###############################################################
#  Generated by:      Cadence Innovus 21.19-s058_1
#  OS:                Linux x86_64(Host ID fastx3-08.ews.illinois.edu)
#  Generated on:      Wed Apr 22 14:25:34 2026
#  Design:            VX_socket_top
#  Command:           write_lef_abstract -stripePin -PGpinLayers {metal7 metal8} -specifyTopLayer 8 -extractBlockObs -cutObsMinSpacing /home/rid2/cs533.work/vortex/hw/pnr/cadence/export/single-core/VX_socket_top.lef
###############################################################

VERSION 5.8 ;

BUSBITCHARS "[]" ;
DIVIDERCHAR "/" ;

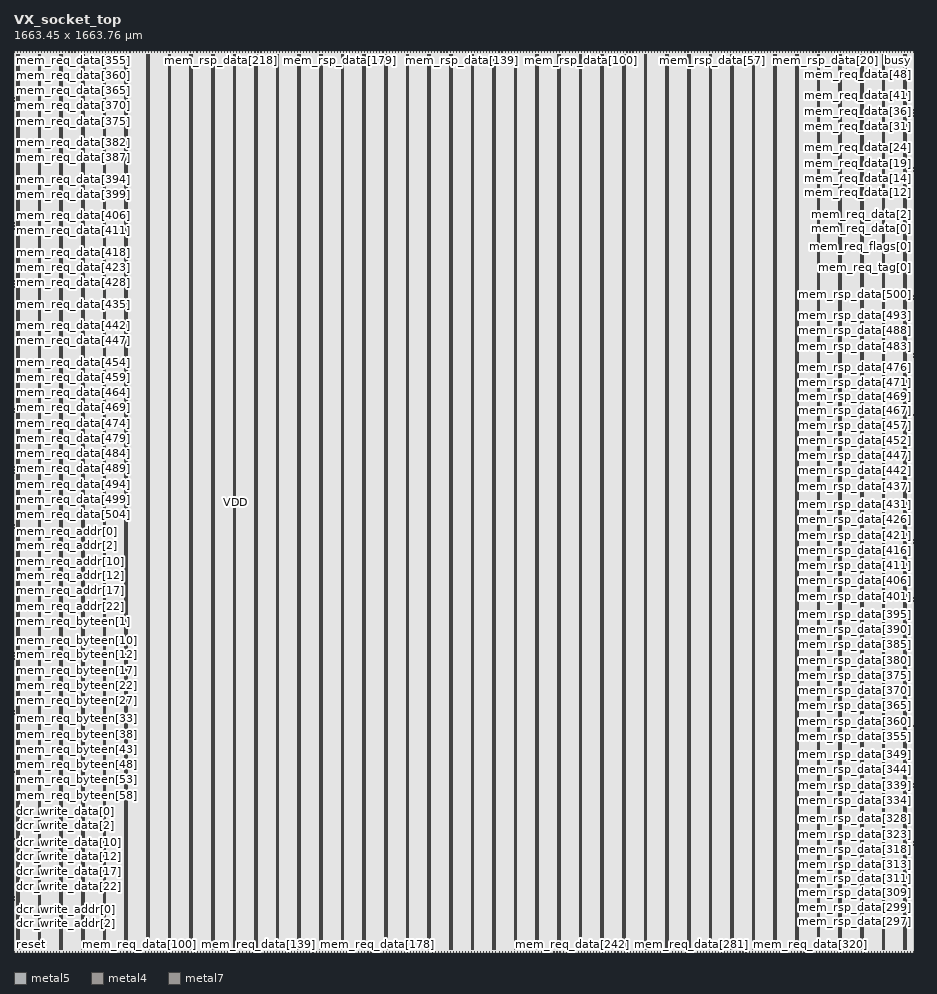
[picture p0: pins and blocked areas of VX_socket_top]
MACRO VX_socket_top
  CLASS BLOCK ;
  SIZE 1663.450000 BY 1663.760000 ;
  FOREIGN VX_socket_top 0.000000 0.000000 ;
  ORIGIN 0 0 ;
  SYMMETRY X Y R90 ;
  PIN clk
    DIRECTION INPUT ;
    USE SIGNAL ;
    PORT
      LAYER metal5 ;
        RECT 0.000000 0.280000 0.140000 0.420000 ;
    END
  END clk
  PIN reset
    DIRECTION INPUT ;
    USE SIGNAL ;
    PORT
      LAYER metal5 ;
        RECT 0.000000 5.880000 0.140000 6.020000 ;
    END
  END reset
  PIN dcr_write_valid
    DIRECTION INPUT ;
    USE SIGNAL ;
    PORT
      LAYER metal5 ;
        RECT 0.000000 11.480000 0.140000 11.620000 ;
    END
  END dcr_write_valid
  PIN dcr_write_addr[11]
    DIRECTION INPUT ;
    USE SIGNAL ;
    PORT
      LAYER metal5 ;
        RECT 0.000000 17.080000 0.140000 17.220000 ;
    END
  END dcr_write_addr[11]
  PIN dcr_write_addr[10]
    DIRECTION INPUT ;
    USE SIGNAL ;
    PORT
      LAYER metal5 ;
        RECT 0.000000 22.680000 0.140000 22.820000 ;
    END
  END dcr_write_addr[10]
  PIN dcr_write_addr[9]
    DIRECTION INPUT ;
    USE SIGNAL ;
    PORT
      LAYER metal5 ;
        RECT 0.000000 28.280000 0.140000 28.420000 ;
    END
  END dcr_write_addr[9]
  PIN dcr_write_addr[8]
    DIRECTION INPUT ;
    USE SIGNAL ;
    PORT
      LAYER metal5 ;
        RECT 0.000000 33.880000 0.140000 34.020000 ;
    END
  END dcr_write_addr[8]
  PIN dcr_write_addr[7]
    DIRECTION INPUT ;
    USE SIGNAL ;
    PORT
      LAYER metal5 ;
        RECT 0.000000 39.480000 0.140000 39.620000 ;
    END
  END dcr_write_addr[7]
  PIN dcr_write_addr[6]
    DIRECTION INPUT ;
    USE SIGNAL ;
    PORT
      LAYER metal5 ;
        RECT 0.000000 45.360000 0.140000 45.500000 ;
    END
  END dcr_write_addr[6]
  PIN dcr_write_addr[5]
    DIRECTION INPUT ;
    USE SIGNAL ;
    PORT
      LAYER metal5 ;
        RECT 0.000000 50.960000 0.140000 51.100000 ;
    END
  END dcr_write_addr[5]
  PIN dcr_write_addr[4]
    DIRECTION INPUT ;
    USE SIGNAL ;
    PORT
      LAYER metal5 ;
        RECT 0.000000 56.560000 0.140000 56.700000 ;
    END
  END dcr_write_addr[4]
  PIN dcr_write_addr[3]
    DIRECTION INPUT ;
    USE SIGNAL ;
    PORT
      LAYER metal5 ;
        RECT 0.000000 62.160000 0.140000 62.300000 ;
    END
  END dcr_write_addr[3]
  PIN dcr_write_addr[2]
    DIRECTION INPUT ;
    USE SIGNAL ;
    PORT
      LAYER metal5 ;
        RECT 0.000000 67.760000 0.140000 67.900000 ;
    END
  END dcr_write_addr[2]
  PIN dcr_write_addr[1]
    DIRECTION INPUT ;
    USE SIGNAL ;
    PORT
      LAYER metal5 ;
        RECT 0.000000 73.360000 0.140000 73.500000 ;
    END
  END dcr_write_addr[1]
  PIN dcr_write_addr[0]
    DIRECTION INPUT ;
    USE SIGNAL ;
    PORT
      LAYER metal5 ;
        RECT 0.000000 78.960000 0.140000 79.100000 ;
    END
  END dcr_write_addr[0]
  PIN dcr_write_data[31]
    DIRECTION INPUT ;
    USE SIGNAL ;
    PORT
      LAYER metal5 ;
        RECT 0.000000 84.840000 0.140000 84.980000 ;
    END
  END dcr_write_data[31]
  PIN dcr_write_data[30]
    DIRECTION INPUT ;
    USE SIGNAL ;
    PORT
      LAYER metal5 ;
        RECT 0.000000 90.440000 0.140000 90.580000 ;
    END
  END dcr_write_data[30]
  PIN dcr_write_data[29]
    DIRECTION INPUT ;
    USE SIGNAL ;
    PORT
      LAYER metal5 ;
        RECT 0.000000 96.040000 0.140000 96.180000 ;
    END
  END dcr_write_data[29]
  PIN dcr_write_data[28]
    DIRECTION INPUT ;
    USE SIGNAL ;
    PORT
      LAYER metal5 ;
        RECT 0.000000 101.640000 0.140000 101.780000 ;
    END
  END dcr_write_data[28]
  PIN dcr_write_data[27]
    DIRECTION INPUT ;
    USE SIGNAL ;
    PORT
      LAYER metal5 ;
        RECT 0.000000 107.240000 0.140000 107.380000 ;
    END
  END dcr_write_data[27]
  PIN dcr_write_data[26]
    DIRECTION INPUT ;
    USE SIGNAL ;
    PORT
      LAYER metal5 ;
        RECT 0.000000 112.840000 0.140000 112.980000 ;
    END
  END dcr_write_data[26]
  PIN dcr_write_data[25]
    DIRECTION INPUT ;
    USE SIGNAL ;
    PORT
      LAYER metal5 ;
        RECT 0.000000 118.440000 0.140000 118.580000 ;
    END
  END dcr_write_data[25]
  PIN dcr_write_data[24]
    DIRECTION INPUT ;
    USE SIGNAL ;
    PORT
      LAYER metal5 ;
        RECT 0.000000 124.040000 0.140000 124.180000 ;
    END
  END dcr_write_data[24]
  PIN dcr_write_data[23]
    DIRECTION INPUT ;
    USE SIGNAL ;
    PORT
      LAYER metal5 ;
        RECT 0.000000 129.920000 0.140000 130.060000 ;
    END
  END dcr_write_data[23]
  PIN dcr_write_data[22]
    DIRECTION INPUT ;
    USE SIGNAL ;
    PORT
      LAYER metal5 ;
        RECT 0.000000 135.520000 0.140000 135.660000 ;
    END
  END dcr_write_data[22]
  PIN dcr_write_data[21]
    DIRECTION INPUT ;
    USE SIGNAL ;
    PORT
      LAYER metal5 ;
        RECT 0.000000 141.120000 0.140000 141.260000 ;
    END
  END dcr_write_data[21]
  PIN dcr_write_data[20]
    DIRECTION INPUT ;
    USE SIGNAL ;
    PORT
      LAYER metal5 ;
        RECT 0.000000 146.720000 0.140000 146.860000 ;
    END
  END dcr_write_data[20]
  PIN dcr_write_data[19]
    DIRECTION INPUT ;
    USE SIGNAL ;
    PORT
      LAYER metal5 ;
        RECT 0.000000 152.320000 0.140000 152.460000 ;
    END
  END dcr_write_data[19]
  PIN dcr_write_data[18]
    DIRECTION INPUT ;
    USE SIGNAL ;
    PORT
      LAYER metal5 ;
        RECT 0.000000 157.920000 0.140000 158.060000 ;
    END
  END dcr_write_data[18]
  PIN dcr_write_data[17]
    DIRECTION INPUT ;
    USE SIGNAL ;
    PORT
      LAYER metal5 ;
        RECT 0.000000 163.520000 0.140000 163.660000 ;
    END
  END dcr_write_data[17]
  PIN dcr_write_data[16]
    DIRECTION INPUT ;
    USE SIGNAL ;
    PORT
      LAYER metal5 ;
        RECT 0.000000 169.400000 0.140000 169.540000 ;
    END
  END dcr_write_data[16]
  PIN dcr_write_data[15]
    DIRECTION INPUT ;
    USE SIGNAL ;
    PORT
      LAYER metal5 ;
        RECT 0.000000 175.000000 0.140000 175.140000 ;
    END
  END dcr_write_data[15]
  PIN dcr_write_data[14]
    DIRECTION INPUT ;
    USE SIGNAL ;
    PORT
      LAYER metal5 ;
        RECT 0.000000 180.600000 0.140000 180.740000 ;
    END
  END dcr_write_data[14]
  PIN dcr_write_data[13]
    DIRECTION INPUT ;
    USE SIGNAL ;
    PORT
      LAYER metal5 ;
        RECT 0.000000 186.200000 0.140000 186.340000 ;
    END
  END dcr_write_data[13]
  PIN dcr_write_data[12]
    DIRECTION INPUT ;
    USE SIGNAL ;
    PORT
      LAYER metal5 ;
        RECT 0.000000 191.800000 0.140000 191.940000 ;
    END
  END dcr_write_data[12]
  PIN dcr_write_data[11]
    DIRECTION INPUT ;
    USE SIGNAL ;
    PORT
      LAYER metal5 ;
        RECT 0.000000 197.400000 0.140000 197.540000 ;
    END
  END dcr_write_data[11]
  PIN dcr_write_data[10]
    DIRECTION INPUT ;
    USE SIGNAL ;
    PORT
      LAYER metal5 ;
        RECT 0.000000 203.000000 0.140000 203.140000 ;
    END
  END dcr_write_data[10]
  PIN dcr_write_data[9]
    DIRECTION INPUT ;
    USE SIGNAL ;
    PORT
      LAYER metal5 ;
        RECT 0.000000 208.880000 0.140000 209.020000 ;
    END
  END dcr_write_data[9]
  PIN dcr_write_data[8]
    DIRECTION INPUT ;
    USE SIGNAL ;
    PORT
      LAYER metal5 ;
        RECT 0.000000 214.480000 0.140000 214.620000 ;
    END
  END dcr_write_data[8]
  PIN dcr_write_data[7]
    DIRECTION INPUT ;
    USE SIGNAL ;
    PORT
      LAYER metal5 ;
        RECT 0.000000 220.080000 0.140000 220.220000 ;
    END
  END dcr_write_data[7]
  PIN dcr_write_data[6]
    DIRECTION INPUT ;
    USE SIGNAL ;
    PORT
      LAYER metal5 ;
        RECT 0.000000 225.680000 0.140000 225.820000 ;
    END
  END dcr_write_data[6]
  PIN dcr_write_data[5]
    DIRECTION INPUT ;
    USE SIGNAL ;
    PORT
      LAYER metal5 ;
        RECT 0.000000 231.280000 0.140000 231.420000 ;
    END
  END dcr_write_data[5]
  PIN dcr_write_data[4]
    DIRECTION INPUT ;
    USE SIGNAL ;
    PORT
      LAYER metal5 ;
        RECT 0.000000 236.880000 0.140000 237.020000 ;
    END
  END dcr_write_data[4]
  PIN dcr_write_data[3]
    DIRECTION INPUT ;
    USE SIGNAL ;
    PORT
      LAYER metal5 ;
        RECT 0.000000 242.480000 0.140000 242.620000 ;
    END
  END dcr_write_data[3]
  PIN dcr_write_data[2]
    DIRECTION INPUT ;
    USE SIGNAL ;
    PORT
      LAYER metal5 ;
        RECT 0.000000 248.080000 0.140000 248.220000 ;
    END
  END dcr_write_data[2]
  PIN dcr_write_data[1]
    DIRECTION INPUT ;
    USE SIGNAL ;
    PORT
      LAYER metal5 ;
        RECT 0.000000 253.960000 0.140000 254.100000 ;
    END
  END dcr_write_data[1]
  PIN dcr_write_data[0]
    DIRECTION INPUT ;
    USE SIGNAL ;
    PORT
      LAYER metal5 ;
        RECT 0.000000 259.560000 0.140000 259.700000 ;
    END
  END dcr_write_data[0]
  PIN mem_req_valid[0]
    DIRECTION OUTPUT ;
    USE SIGNAL ;
    PORT
      LAYER metal5 ;
        RECT 0.000000 265.160000 0.140000 265.300000 ;
    END
  END mem_req_valid[0]
  PIN mem_req_rw[0]
    DIRECTION OUTPUT ;
    USE SIGNAL ;
    PORT
      LAYER metal5 ;
        RECT 0.000000 270.760000 0.140000 270.900000 ;
    END
  END mem_req_rw[0]
  PIN mem_req_byteen[63]
    DIRECTION OUTPUT ;
    USE SIGNAL ;
    PORT
      LAYER metal5 ;
        RECT 0.000000 276.360000 0.140000 276.500000 ;
    END
  END mem_req_byteen[63]
  PIN mem_req_byteen[62]
    DIRECTION OUTPUT ;
    USE SIGNAL ;
    PORT
      LAYER metal5 ;
        RECT 0.000000 281.960000 0.140000 282.100000 ;
    END
  END mem_req_byteen[62]
  PIN mem_req_byteen[61]
    DIRECTION OUTPUT ;
    USE SIGNAL ;
    PORT
      LAYER metal5 ;
        RECT 0.000000 287.560000 0.140000 287.700000 ;
    END
  END mem_req_byteen[61]
  PIN mem_req_byteen[60]
    DIRECTION OUTPUT ;
    USE SIGNAL ;
    PORT
      LAYER metal5 ;
        RECT 0.000000 293.440000 0.140000 293.580000 ;
    END
  END mem_req_byteen[60]
  PIN mem_req_byteen[59]
    DIRECTION OUTPUT ;
    USE SIGNAL ;
    PORT
      LAYER metal5 ;
        RECT 0.000000 299.040000 0.140000 299.180000 ;
    END
  END mem_req_byteen[59]
  PIN mem_req_byteen[58]
    DIRECTION OUTPUT ;
    USE SIGNAL ;
    PORT
      LAYER metal5 ;
        RECT 0.000000 304.640000 0.140000 304.780000 ;
    END
  END mem_req_byteen[58]
  PIN mem_req_byteen[57]
    DIRECTION OUTPUT ;
    USE SIGNAL ;
    PORT
      LAYER metal5 ;
        RECT 0.000000 310.240000 0.140000 310.380000 ;
    END
  END mem_req_byteen[57]
  PIN mem_req_byteen[56]
    DIRECTION OUTPUT ;
    USE SIGNAL ;
    PORT
      LAYER metal5 ;
        RECT 0.000000 315.840000 0.140000 315.980000 ;
    END
  END mem_req_byteen[56]
  PIN mem_req_byteen[55]
    DIRECTION OUTPUT ;
    USE SIGNAL ;
    PORT
      LAYER metal5 ;
        RECT 0.000000 321.440000 0.140000 321.580000 ;
    END
  END mem_req_byteen[55]
  PIN mem_req_byteen[54]
    DIRECTION OUTPUT ;
    USE SIGNAL ;
    PORT
      LAYER metal5 ;
        RECT 0.000000 327.040000 0.140000 327.180000 ;
    END
  END mem_req_byteen[54]
  PIN mem_req_byteen[53]
    DIRECTION OUTPUT ;
    USE SIGNAL ;
    PORT
      LAYER metal5 ;
        RECT 0.000000 332.640000 0.140000 332.780000 ;
    END
  END mem_req_byteen[53]
  PIN mem_req_byteen[52]
    DIRECTION OUTPUT ;
    USE SIGNAL ;
    PORT
      LAYER metal5 ;
        RECT 0.000000 338.520000 0.140000 338.660000 ;
    END
  END mem_req_byteen[52]
  PIN mem_req_byteen[51]
    DIRECTION OUTPUT ;
    USE SIGNAL ;
    PORT
      LAYER metal5 ;
        RECT 0.000000 344.120000 0.140000 344.260000 ;
    END
  END mem_req_byteen[51]
  PIN mem_req_byteen[50]
    DIRECTION OUTPUT ;
    USE SIGNAL ;
    PORT
      LAYER metal5 ;
        RECT 0.000000 349.720000 0.140000 349.860000 ;
    END
  END mem_req_byteen[50]
  PIN mem_req_byteen[49]
    DIRECTION OUTPUT ;
    USE SIGNAL ;
    PORT
      LAYER metal5 ;
        RECT 0.000000 355.320000 0.140000 355.460000 ;
    END
  END mem_req_byteen[49]
  PIN mem_req_byteen[48]
    DIRECTION OUTPUT ;
    USE SIGNAL ;
    PORT
      LAYER metal5 ;
        RECT 0.000000 360.920000 0.140000 361.060000 ;
    END
  END mem_req_byteen[48]
  PIN mem_req_byteen[47]
    DIRECTION OUTPUT ;
    USE SIGNAL ;
    PORT
      LAYER metal5 ;
        RECT 0.000000 366.520000 0.140000 366.660000 ;
    END
  END mem_req_byteen[47]
  PIN mem_req_byteen[46]
    DIRECTION OUTPUT ;
    USE SIGNAL ;
    PORT
      LAYER metal5 ;
        RECT 0.000000 372.120000 0.140000 372.260000 ;
    END
  END mem_req_byteen[46]
  PIN mem_req_byteen[45]
    DIRECTION OUTPUT ;
    USE SIGNAL ;
    PORT
      LAYER metal5 ;
        RECT 0.000000 378.000000 0.140000 378.140000 ;
    END
  END mem_req_byteen[45]
  PIN mem_req_byteen[44]
    DIRECTION OUTPUT ;
    USE SIGNAL ;
    PORT
      LAYER metal5 ;
        RECT 0.000000 383.600000 0.140000 383.740000 ;
    END
  END mem_req_byteen[44]
  PIN mem_req_byteen[43]
    DIRECTION OUTPUT ;
    USE SIGNAL ;
    PORT
      LAYER metal5 ;
        RECT 0.000000 389.200000 0.140000 389.340000 ;
    END
  END mem_req_byteen[43]
  PIN mem_req_byteen[42]
    DIRECTION OUTPUT ;
    USE SIGNAL ;
    PORT
      LAYER metal5 ;
        RECT 0.000000 394.800000 0.140000 394.940000 ;
    END
  END mem_req_byteen[42]
  PIN mem_req_byteen[41]
    DIRECTION OUTPUT ;
    USE SIGNAL ;
    PORT
      LAYER metal5 ;
        RECT 0.000000 400.400000 0.140000 400.540000 ;
    END
  END mem_req_byteen[41]
  PIN mem_req_byteen[40]
    DIRECTION OUTPUT ;
    USE SIGNAL ;
    PORT
      LAYER metal5 ;
        RECT 0.000000 406.000000 0.140000 406.140000 ;
    END
  END mem_req_byteen[40]
  PIN mem_req_byteen[39]
    DIRECTION OUTPUT ;
    USE SIGNAL ;
    PORT
      LAYER metal5 ;
        RECT 0.000000 411.600000 0.140000 411.740000 ;
    END
  END mem_req_byteen[39]
  PIN mem_req_byteen[38]
    DIRECTION OUTPUT ;
    USE SIGNAL ;
    PORT
      LAYER metal5 ;
        RECT 0.000000 417.480000 0.140000 417.620000 ;
    END
  END mem_req_byteen[38]
  PIN mem_req_byteen[37]
    DIRECTION OUTPUT ;
    USE SIGNAL ;
    PORT
      LAYER metal5 ;
        RECT 0.000000 423.080000 0.140000 423.220000 ;
    END
  END mem_req_byteen[37]
  PIN mem_req_byteen[36]
    DIRECTION OUTPUT ;
    USE SIGNAL ;
    PORT
      LAYER metal5 ;
        RECT 0.000000 428.680000 0.140000 428.820000 ;
    END
  END mem_req_byteen[36]
  PIN mem_req_byteen[35]
    DIRECTION OUTPUT ;
    USE SIGNAL ;
    PORT
      LAYER metal5 ;
        RECT 0.000000 434.280000 0.140000 434.420000 ;
    END
  END mem_req_byteen[35]
  PIN mem_req_byteen[34]
    DIRECTION OUTPUT ;
    USE SIGNAL ;
    PORT
      LAYER metal5 ;
        RECT 0.000000 439.880000 0.140000 440.020000 ;
    END
  END mem_req_byteen[34]
  PIN mem_req_byteen[33]
    DIRECTION OUTPUT ;
    USE SIGNAL ;
    PORT
      LAYER metal5 ;
        RECT 0.000000 445.480000 0.140000 445.620000 ;
    END
  END mem_req_byteen[33]
  PIN mem_req_byteen[32]
    DIRECTION OUTPUT ;
    USE SIGNAL ;
    PORT
      LAYER metal5 ;
        RECT 0.000000 451.080000 0.140000 451.220000 ;
    END
  END mem_req_byteen[32]
  PIN mem_req_byteen[31]
    DIRECTION OUTPUT ;
    USE SIGNAL ;
    PORT
      LAYER metal5 ;
        RECT 0.000000 456.680000 0.140000 456.820000 ;
    END
  END mem_req_byteen[31]
  PIN mem_req_byteen[30]
    DIRECTION OUTPUT ;
    USE SIGNAL ;
    PORT
      LAYER metal5 ;
        RECT 0.000000 462.560000 0.140000 462.700000 ;
    END
  END mem_req_byteen[30]
  PIN mem_req_byteen[29]
    DIRECTION OUTPUT ;
    USE SIGNAL ;
    PORT
      LAYER metal5 ;
        RECT 0.000000 468.160000 0.140000 468.300000 ;
    END
  END mem_req_byteen[29]
  PIN mem_req_byteen[28]
    DIRECTION OUTPUT ;
    USE SIGNAL ;
    PORT
      LAYER metal5 ;
        RECT 0.000000 473.760000 0.140000 473.900000 ;
    END
  END mem_req_byteen[28]
  PIN mem_req_byteen[27]
    DIRECTION OUTPUT ;
    USE SIGNAL ;
    PORT
      LAYER metal5 ;
        RECT 0.000000 479.360000 0.140000 479.500000 ;
    END
  END mem_req_byteen[27]
  PIN mem_req_byteen[26]
    DIRECTION OUTPUT ;
    USE SIGNAL ;
    PORT
      LAYER metal5 ;
        RECT 0.000000 484.960000 0.140000 485.100000 ;
    END
  END mem_req_byteen[26]
  PIN mem_req_byteen[25]
    DIRECTION OUTPUT ;
    USE SIGNAL ;
    PORT
      LAYER metal5 ;
        RECT 0.000000 490.560000 0.140000 490.700000 ;
    END
  END mem_req_byteen[25]
  PIN mem_req_byteen[24]
    DIRECTION OUTPUT ;
    USE SIGNAL ;
    PORT
      LAYER metal5 ;
        RECT 0.000000 496.160000 0.140000 496.300000 ;
    END
  END mem_req_byteen[24]
  PIN mem_req_byteen[23]
    DIRECTION OUTPUT ;
    USE SIGNAL ;
    PORT
      LAYER metal5 ;
        RECT 0.000000 502.040000 0.140000 502.180000 ;
    END
  END mem_req_byteen[23]
  PIN mem_req_byteen[22]
    DIRECTION OUTPUT ;
    USE SIGNAL ;
    PORT
      LAYER metal5 ;
        RECT 0.000000 507.640000 0.140000 507.780000 ;
    END
  END mem_req_byteen[22]
  PIN mem_req_byteen[21]
    DIRECTION OUTPUT ;
    USE SIGNAL ;
    PORT
      LAYER metal5 ;
        RECT 0.000000 513.240000 0.140000 513.380000 ;
    END
  END mem_req_byteen[21]
  PIN mem_req_byteen[20]
    DIRECTION OUTPUT ;
    USE SIGNAL ;
    PORT
      LAYER metal5 ;
        RECT 0.000000 518.840000 0.140000 518.980000 ;
    END
  END mem_req_byteen[20]
  PIN mem_req_byteen[19]
    DIRECTION OUTPUT ;
    USE SIGNAL ;
    PORT
      LAYER metal5 ;
        RECT 0.000000 524.440000 0.140000 524.580000 ;
    END
  END mem_req_byteen[19]
  PIN mem_req_byteen[18]
    DIRECTION OUTPUT ;
    USE SIGNAL ;
    PORT
      LAYER metal5 ;
        RECT 0.000000 530.040000 0.140000 530.180000 ;
    END
  END mem_req_byteen[18]
  PIN mem_req_byteen[17]
    DIRECTION OUTPUT ;
    USE SIGNAL ;
    PORT
      LAYER metal5 ;
        RECT 0.000000 535.640000 0.140000 535.780000 ;
    END
  END mem_req_byteen[17]
  PIN mem_req_byteen[16]
    DIRECTION OUTPUT ;
    USE SIGNAL ;
    PORT
      LAYER metal5 ;
        RECT 0.000000 541.520000 0.140000 541.660000 ;
    END
  END mem_req_byteen[16]
  PIN mem_req_byteen[15]
    DIRECTION OUTPUT ;
    USE SIGNAL ;
    PORT
      LAYER metal5 ;
        RECT 0.000000 547.120000 0.140000 547.260000 ;
    END
  END mem_req_byteen[15]
  PIN mem_req_byteen[14]
    DIRECTION OUTPUT ;
    USE SIGNAL ;
    PORT
      LAYER metal5 ;
        RECT 0.000000 552.720000 0.140000 552.860000 ;
    END
  END mem_req_byteen[14]
  PIN mem_req_byteen[13]
    DIRECTION OUTPUT ;
    USE SIGNAL ;
    PORT
      LAYER metal5 ;
        RECT 0.000000 558.320000 0.140000 558.460000 ;
    END
  END mem_req_byteen[13]
  PIN mem_req_byteen[12]
    DIRECTION OUTPUT ;
    USE SIGNAL ;
    PORT
      LAYER metal5 ;
        RECT 0.000000 563.920000 0.140000 564.060000 ;
    END
  END mem_req_byteen[12]
  PIN mem_req_byteen[11]
    DIRECTION OUTPUT ;
    USE SIGNAL ;
    PORT
      LAYER metal5 ;
        RECT 0.000000 569.520000 0.140000 569.660000 ;
    END
  END mem_req_byteen[11]
  PIN mem_req_byteen[10]
    DIRECTION OUTPUT ;
    USE SIGNAL ;
    PORT
      LAYER metal5 ;
        RECT 0.000000 575.120000 0.140000 575.260000 ;
    END
  END mem_req_byteen[10]
  PIN mem_req_byteen[9]
    DIRECTION OUTPUT ;
    USE SIGNAL ;
    PORT
      LAYER metal5 ;
        RECT 0.000000 580.720000 0.140000 580.860000 ;
    END
  END mem_req_byteen[9]
  PIN mem_req_byteen[8]
    DIRECTION OUTPUT ;
    USE SIGNAL ;
    PORT
      LAYER metal5 ;
        RECT 0.000000 586.600000 0.140000 586.740000 ;
    END
  END mem_req_byteen[8]
  PIN mem_req_byteen[7]
    DIRECTION OUTPUT ;
    USE SIGNAL ;
    PORT
      LAYER metal5 ;
        RECT 0.000000 592.200000 0.140000 592.340000 ;
    END
  END mem_req_byteen[7]
  PIN mem_req_byteen[6]
    DIRECTION OUTPUT ;
    USE SIGNAL ;
    PORT
      LAYER metal5 ;
        RECT 0.000000 597.800000 0.140000 597.940000 ;
    END
  END mem_req_byteen[6]
  PIN mem_req_byteen[5]
    DIRECTION OUTPUT ;
    USE SIGNAL ;
    PORT
      LAYER metal5 ;
        RECT 0.000000 603.400000 0.140000 603.540000 ;
    END
  END mem_req_byteen[5]
  PIN mem_req_byteen[4]
    DIRECTION OUTPUT ;
    USE SIGNAL ;
    PORT
      LAYER metal5 ;
        RECT 0.000000 609.000000 0.140000 609.140000 ;
    END
  END mem_req_byteen[4]
  PIN mem_req_byteen[3]
    DIRECTION OUTPUT ;
    USE SIGNAL ;
    PORT
      LAYER metal5 ;
        RECT 0.000000 614.600000 0.140000 614.740000 ;
    END
  END mem_req_byteen[3]
  PIN mem_req_byteen[2]
    DIRECTION OUTPUT ;
    USE SIGNAL ;
    PORT
      LAYER metal5 ;
        RECT 0.000000 620.200000 0.140000 620.340000 ;
    END
  END mem_req_byteen[2]
  PIN mem_req_byteen[1]
    DIRECTION OUTPUT ;
    USE SIGNAL ;
    PORT
      LAYER metal5 ;
        RECT 0.000000 626.080000 0.140000 626.220000 ;
    END
  END mem_req_byteen[1]
  PIN mem_req_byteen[0]
    DIRECTION OUTPUT ;
    USE SIGNAL ;
    PORT
      LAYER metal5 ;
        RECT 0.000000 631.680000 0.140000 631.820000 ;
    END
  END mem_req_byteen[0]
  PIN mem_req_addr[25]
    DIRECTION OUTPUT ;
    USE SIGNAL ;
    PORT
      LAYER metal5 ;
        RECT 0.000000 637.280000 0.140000 637.420000 ;
    END
  END mem_req_addr[25]
  PIN mem_req_addr[24]
    DIRECTION OUTPUT ;
    USE SIGNAL ;
    PORT
      LAYER metal5 ;
        RECT 0.000000 642.880000 0.140000 643.020000 ;
    END
  END mem_req_addr[24]
  PIN mem_req_addr[23]
    DIRECTION OUTPUT ;
    USE SIGNAL ;
    PORT
      LAYER metal5 ;
        RECT 0.000000 648.480000 0.140000 648.620000 ;
    END
  END mem_req_addr[23]
  PIN mem_req_addr[22]
    DIRECTION OUTPUT ;
    USE SIGNAL ;
    PORT
      LAYER metal5 ;
        RECT 0.000000 654.080000 0.140000 654.220000 ;
    END
  END mem_req_addr[22]
  PIN mem_req_addr[21]
    DIRECTION OUTPUT ;
    USE SIGNAL ;
    PORT
      LAYER metal5 ;
        RECT 0.000000 659.680000 0.140000 659.820000 ;
    END
  END mem_req_addr[21]
  PIN mem_req_addr[20]
    DIRECTION OUTPUT ;
    USE SIGNAL ;
    PORT
      LAYER metal5 ;
        RECT 0.000000 665.280000 0.140000 665.420000 ;
    END
  END mem_req_addr[20]
  PIN mem_req_addr[19]
    DIRECTION OUTPUT ;
    USE SIGNAL ;
    PORT
      LAYER metal5 ;
        RECT 0.000000 671.160000 0.140000 671.300000 ;
    END
  END mem_req_addr[19]
  PIN mem_req_addr[18]
    DIRECTION OUTPUT ;
    USE SIGNAL ;
    PORT
      LAYER metal5 ;
        RECT 0.000000 676.760000 0.140000 676.900000 ;
    END
  END mem_req_addr[18]
  PIN mem_req_addr[17]
    DIRECTION OUTPUT ;
    USE SIGNAL ;
    PORT
      LAYER metal5 ;
        RECT 0.000000 682.360000 0.140000 682.500000 ;
    END
  END mem_req_addr[17]
  PIN mem_req_addr[16]
    DIRECTION OUTPUT ;
    USE SIGNAL ;
    PORT
      LAYER metal5 ;
        RECT 0.000000 687.960000 0.140000 688.100000 ;
    END
  END mem_req_addr[16]
  PIN mem_req_addr[15]
    DIRECTION OUTPUT ;
    USE SIGNAL ;
    PORT
      LAYER metal5 ;
        RECT 0.000000 693.560000 0.140000 693.700000 ;
    END
  END mem_req_addr[15]
  PIN mem_req_addr[14]
    DIRECTION OUTPUT ;
    USE SIGNAL ;
    PORT
      LAYER metal5 ;
        RECT 0.000000 699.160000 0.140000 699.300000 ;
    END
  END mem_req_addr[14]
  PIN mem_req_addr[13]
    DIRECTION OUTPUT ;
    USE SIGNAL ;
    PORT
      LAYER metal5 ;
        RECT 0.000000 704.760000 0.140000 704.900000 ;
    END
  END mem_req_addr[13]
  PIN mem_req_addr[12]
    DIRECTION OUTPUT ;
    USE SIGNAL ;
    PORT
      LAYER metal5 ;
        RECT 0.000000 710.640000 0.140000 710.780000 ;
    END
  END mem_req_addr[12]
  PIN mem_req_addr[11]
    DIRECTION OUTPUT ;
    USE SIGNAL ;
    PORT
      LAYER metal5 ;
        RECT 0.000000 716.240000 0.140000 716.380000 ;
    END
  END mem_req_addr[11]
  PIN mem_req_addr[10]
    DIRECTION OUTPUT ;
    USE SIGNAL ;
    PORT
      LAYER metal5 ;
        RECT 0.000000 721.840000 0.140000 721.980000 ;
    END
  END mem_req_addr[10]
  PIN mem_req_addr[9]
    DIRECTION OUTPUT ;
    USE SIGNAL ;
    PORT
      LAYER metal5 ;
        RECT 0.000000 727.440000 0.140000 727.580000 ;
    END
  END mem_req_addr[9]
  PIN mem_req_addr[8]
    DIRECTION OUTPUT ;
    USE SIGNAL ;
    PORT
      LAYER metal5 ;
        RECT 0.000000 733.040000 0.140000 733.180000 ;
    END
  END mem_req_addr[8]
  PIN mem_req_addr[7]
    DIRECTION OUTPUT ;
    USE SIGNAL ;
    PORT
      LAYER metal5 ;
        RECT 0.000000 738.640000 0.140000 738.780000 ;
    END
  END mem_req_addr[7]
  PIN mem_req_addr[6]
    DIRECTION OUTPUT ;
    USE SIGNAL ;
    PORT
      LAYER metal5 ;
        RECT 0.000000 744.240000 0.140000 744.380000 ;
    END
  END mem_req_addr[6]
  PIN mem_req_addr[5]
    DIRECTION OUTPUT ;
    USE SIGNAL ;
    PORT
      LAYER metal5 ;
        RECT 0.000000 750.120000 0.140000 750.260000 ;
    END
  END mem_req_addr[5]
  PIN mem_req_addr[4]
    DIRECTION OUTPUT ;
    USE SIGNAL ;
    PORT
      LAYER metal5 ;
        RECT 0.000000 755.720000 0.140000 755.860000 ;
    END
  END mem_req_addr[4]
  PIN mem_req_addr[3]
    DIRECTION OUTPUT ;
    USE SIGNAL ;
    PORT
      LAYER metal5 ;
        RECT 0.000000 761.320000 0.140000 761.460000 ;
    END
  END mem_req_addr[3]
  PIN mem_req_addr[2]
    DIRECTION OUTPUT ;
    USE SIGNAL ;
    PORT
      LAYER metal5 ;
        RECT 0.000000 766.920000 0.140000 767.060000 ;
    END
  END mem_req_addr[2]
  PIN mem_req_addr[1]
    DIRECTION OUTPUT ;
    USE SIGNAL ;
    PORT
      LAYER metal5 ;
        RECT 0.000000 772.520000 0.140000 772.660000 ;
    END
  END mem_req_addr[1]
  PIN mem_req_addr[0]
    DIRECTION OUTPUT ;
    USE SIGNAL ;
    PORT
      LAYER metal5 ;
        RECT 0.000000 778.120000 0.140000 778.260000 ;
    END
  END mem_req_addr[0]
  PIN mem_req_data[511]
    DIRECTION OUTPUT ;
    USE SIGNAL ;
    PORT
      LAYER metal5 ;
        RECT 0.000000 783.720000 0.140000 783.860000 ;
    END
  END mem_req_data[511]
  PIN mem_req_data[510]
    DIRECTION OUTPUT ;
    USE SIGNAL ;
    PORT
      LAYER metal5 ;
        RECT 0.000000 789.320000 0.140000 789.460000 ;
    END
  END mem_req_data[510]
  PIN mem_req_data[509]
    DIRECTION OUTPUT ;
    USE SIGNAL ;
    PORT
      LAYER metal5 ;
        RECT 0.000000 795.200000 0.140000 795.340000 ;
    END
  END mem_req_data[509]
  PIN mem_req_data[508]
    DIRECTION OUTPUT ;
    USE SIGNAL ;
    PORT
      LAYER metal5 ;
        RECT 0.000000 800.800000 0.140000 800.940000 ;
    END
  END mem_req_data[508]
  PIN mem_req_data[507]
    DIRECTION OUTPUT ;
    USE SIGNAL ;
    PORT
      LAYER metal5 ;
        RECT 0.000000 806.400000 0.140000 806.540000 ;
    END
  END mem_req_data[507]
  PIN mem_req_data[506]
    DIRECTION OUTPUT ;
    USE SIGNAL ;
    PORT
      LAYER metal5 ;
        RECT 0.000000 812.000000 0.140000 812.140000 ;
    END
  END mem_req_data[506]
  PIN mem_req_data[505]
    DIRECTION OUTPUT ;
    USE SIGNAL ;
    PORT
      LAYER metal5 ;
        RECT 0.000000 817.600000 0.140000 817.740000 ;
    END
  END mem_req_data[505]
  PIN mem_req_data[504]
    DIRECTION OUTPUT ;
    USE SIGNAL ;
    PORT
      LAYER metal5 ;
        RECT 0.000000 823.200000 0.140000 823.340000 ;
    END
  END mem_req_data[504]
  PIN mem_req_data[503]
    DIRECTION OUTPUT ;
    USE SIGNAL ;
    PORT
      LAYER metal5 ;
        RECT 0.000000 828.800000 0.140000 828.940000 ;
    END
  END mem_req_data[503]
  PIN mem_req_data[502]
    DIRECTION OUTPUT ;
    USE SIGNAL ;
    PORT
      LAYER metal5 ;
        RECT 0.000000 834.680000 0.140000 834.820000 ;
    END
  END mem_req_data[502]
  PIN mem_req_data[501]
    DIRECTION OUTPUT ;
    USE SIGNAL ;
    PORT
      LAYER metal5 ;
        RECT 0.000000 840.280000 0.140000 840.420000 ;
    END
  END mem_req_data[501]
  PIN mem_req_data[500]
    DIRECTION OUTPUT ;
    USE SIGNAL ;
    PORT
      LAYER metal5 ;
        RECT 0.000000 845.880000 0.140000 846.020000 ;
    END
  END mem_req_data[500]
  PIN mem_req_data[499]
    DIRECTION OUTPUT ;
    USE SIGNAL ;
    PORT
      LAYER metal5 ;
        RECT 0.000000 851.480000 0.140000 851.620000 ;
    END
  END mem_req_data[499]
  PIN mem_req_data[498]
    DIRECTION OUTPUT ;
    USE SIGNAL ;
    PORT
      LAYER metal5 ;
        RECT 0.000000 857.080000 0.140000 857.220000 ;
    END
  END mem_req_data[498]
  PIN mem_req_data[497]
    DIRECTION OUTPUT ;
    USE SIGNAL ;
    PORT
      LAYER metal5 ;
        RECT 0.000000 862.680000 0.140000 862.820000 ;
    END
  END mem_req_data[497]
  PIN mem_req_data[496]
    DIRECTION OUTPUT ;
    USE SIGNAL ;
    PORT
      LAYER metal5 ;
        RECT 0.000000 868.280000 0.140000 868.420000 ;
    END
  END mem_req_data[496]
  PIN mem_req_data[495]
    DIRECTION OUTPUT ;
    USE SIGNAL ;
    PORT
      LAYER metal5 ;
        RECT 0.000000 874.160000 0.140000 874.300000 ;
    END
  END mem_req_data[495]
  PIN mem_req_data[494]
    DIRECTION OUTPUT ;
    USE SIGNAL ;
    PORT
      LAYER metal5 ;
        RECT 0.000000 879.760000 0.140000 879.900000 ;
    END
  END mem_req_data[494]
  PIN mem_req_data[493]
    DIRECTION OUTPUT ;
    USE SIGNAL ;
    PORT
      LAYER metal5 ;
        RECT 0.000000 885.360000 0.140000 885.500000 ;
    END
  END mem_req_data[493]
  PIN mem_req_data[492]
    DIRECTION OUTPUT ;
    USE SIGNAL ;
    PORT
      LAYER metal5 ;
        RECT 0.000000 890.960000 0.140000 891.100000 ;
    END
  END mem_req_data[492]
  PIN mem_req_data[491]
    DIRECTION OUTPUT ;
    USE SIGNAL ;
    PORT
      LAYER metal5 ;
        RECT 0.000000 896.560000 0.140000 896.700000 ;
    END
  END mem_req_data[491]
  PIN mem_req_data[490]
    DIRECTION OUTPUT ;
    USE SIGNAL ;
    PORT
      LAYER metal5 ;
        RECT 0.000000 902.160000 0.140000 902.300000 ;
    END
  END mem_req_data[490]
  PIN mem_req_data[489]
    DIRECTION OUTPUT ;
    USE SIGNAL ;
    PORT
      LAYER metal5 ;
        RECT 0.000000 907.760000 0.140000 907.900000 ;
    END
  END mem_req_data[489]
  PIN mem_req_data[488]
    DIRECTION OUTPUT ;
    USE SIGNAL ;
    PORT
      LAYER metal5 ;
        RECT 0.000000 913.360000 0.140000 913.500000 ;
    END
  END mem_req_data[488]
  PIN mem_req_data[487]
    DIRECTION OUTPUT ;
    USE SIGNAL ;
    PORT
      LAYER metal5 ;
        RECT 0.000000 919.240000 0.140000 919.380000 ;
    END
  END mem_req_data[487]
  PIN mem_req_data[486]
    DIRECTION OUTPUT ;
    USE SIGNAL ;
    PORT
      LAYER metal5 ;
        RECT 0.000000 924.840000 0.140000 924.980000 ;
    END
  END mem_req_data[486]
  PIN mem_req_data[485]
    DIRECTION OUTPUT ;
    USE SIGNAL ;
    PORT
      LAYER metal5 ;
        RECT 0.000000 930.440000 0.140000 930.580000 ;
    END
  END mem_req_data[485]
  PIN mem_req_data[484]
    DIRECTION OUTPUT ;
    USE SIGNAL ;
    PORT
      LAYER metal5 ;
        RECT 0.000000 936.040000 0.140000 936.180000 ;
    END
  END mem_req_data[484]
  PIN mem_req_data[483]
    DIRECTION OUTPUT ;
    USE SIGNAL ;
    PORT
      LAYER metal5 ;
        RECT 0.000000 941.640000 0.140000 941.780000 ;
    END
  END mem_req_data[483]
  PIN mem_req_data[482]
    DIRECTION OUTPUT ;
    USE SIGNAL ;
    PORT
      LAYER metal5 ;
        RECT 0.000000 947.240000 0.140000 947.380000 ;
    END
  END mem_req_data[482]
  PIN mem_req_data[481]
    DIRECTION OUTPUT ;
    USE SIGNAL ;
    PORT
      LAYER metal5 ;
        RECT 0.000000 952.840000 0.140000 952.980000 ;
    END
  END mem_req_data[481]
  PIN mem_req_data[480]
    DIRECTION OUTPUT ;
    USE SIGNAL ;
    PORT
      LAYER metal5 ;
        RECT 0.000000 958.720000 0.140000 958.860000 ;
    END
  END mem_req_data[480]
  PIN mem_req_data[479]
    DIRECTION OUTPUT ;
    USE SIGNAL ;
    PORT
      LAYER metal5 ;
        RECT 0.000000 964.320000 0.140000 964.460000 ;
    END
  END mem_req_data[479]
  PIN mem_req_data[478]
    DIRECTION OUTPUT ;
    USE SIGNAL ;
    PORT
      LAYER metal5 ;
        RECT 0.000000 969.920000 0.140000 970.060000 ;
    END
  END mem_req_data[478]
  PIN mem_req_data[477]
    DIRECTION OUTPUT ;
    USE SIGNAL ;
    PORT
      LAYER metal5 ;
        RECT 0.000000 975.520000 0.140000 975.660000 ;
    END
  END mem_req_data[477]
  PIN mem_req_data[476]
    DIRECTION OUTPUT ;
    USE SIGNAL ;
    PORT
      LAYER metal5 ;
        RECT 0.000000 981.120000 0.140000 981.260000 ;
    END
  END mem_req_data[476]
  PIN mem_req_data[475]
    DIRECTION OUTPUT ;
    USE SIGNAL ;
    PORT
      LAYER metal5 ;
        RECT 0.000000 986.720000 0.140000 986.860000 ;
    END
  END mem_req_data[475]
  PIN mem_req_data[474]
    DIRECTION OUTPUT ;
    USE SIGNAL ;
    PORT
      LAYER metal5 ;
        RECT 0.000000 992.320000 0.140000 992.460000 ;
    END
  END mem_req_data[474]
  PIN mem_req_data[473]
    DIRECTION OUTPUT ;
    USE SIGNAL ;
    PORT
      LAYER metal5 ;
        RECT 0.000000 998.200000 0.140000 998.340000 ;
    END
  END mem_req_data[473]
  PIN mem_req_data[472]
    DIRECTION OUTPUT ;
    USE SIGNAL ;
    PORT
      LAYER metal5 ;
        RECT 0.000000 1003.800000 0.140000 1003.940000 ;
    END
  END mem_req_data[472]
  PIN mem_req_data[471]
    DIRECTION OUTPUT ;
    USE SIGNAL ;
    PORT
      LAYER metal5 ;
        RECT 0.000000 1009.400000 0.140000 1009.540000 ;
    END
  END mem_req_data[471]
  PIN mem_req_data[470]
    DIRECTION OUTPUT ;
    USE SIGNAL ;
    PORT
      LAYER metal5 ;
        RECT 0.000000 1015.000000 0.140000 1015.140000 ;
    END
  END mem_req_data[470]
  PIN mem_req_data[469]
    DIRECTION OUTPUT ;
    USE SIGNAL ;
    PORT
      LAYER metal5 ;
        RECT 0.000000 1020.600000 0.140000 1020.740000 ;
    END
  END mem_req_data[469]
  PIN mem_req_data[468]
    DIRECTION OUTPUT ;
    USE SIGNAL ;
    PORT
      LAYER metal5 ;
        RECT 0.000000 1026.200000 0.140000 1026.340000 ;
    END
  END mem_req_data[468]
  PIN mem_req_data[467]
    DIRECTION OUTPUT ;
    USE SIGNAL ;
    PORT
      LAYER metal5 ;
        RECT 0.000000 1031.800000 0.140000 1031.940000 ;
    END
  END mem_req_data[467]
  PIN mem_req_data[466]
    DIRECTION OUTPUT ;
    USE SIGNAL ;
    PORT
      LAYER metal5 ;
        RECT 0.000000 1037.400000 0.140000 1037.540000 ;
    END
  END mem_req_data[466]
  PIN mem_req_data[465]
    DIRECTION OUTPUT ;
    USE SIGNAL ;
    PORT
      LAYER metal5 ;
        RECT 0.000000 1043.280000 0.140000 1043.420000 ;
    END
  END mem_req_data[465]
  PIN mem_req_data[464]
    DIRECTION OUTPUT ;
    USE SIGNAL ;
    PORT
      LAYER metal5 ;
        RECT 0.000000 1048.880000 0.140000 1049.020000 ;
    END
  END mem_req_data[464]
  PIN mem_req_data[463]
    DIRECTION OUTPUT ;
    USE SIGNAL ;
    PORT
      LAYER metal5 ;
        RECT 0.000000 1054.480000 0.140000 1054.620000 ;
    END
  END mem_req_data[463]
  PIN mem_req_data[462]
    DIRECTION OUTPUT ;
    USE SIGNAL ;
    PORT
      LAYER metal5 ;
        RECT 0.000000 1060.080000 0.140000 1060.220000 ;
    END
  END mem_req_data[462]
  PIN mem_req_data[461]
    DIRECTION OUTPUT ;
    USE SIGNAL ;
    PORT
      LAYER metal5 ;
        RECT 0.000000 1065.680000 0.140000 1065.820000 ;
    END
  END mem_req_data[461]
  PIN mem_req_data[460]
    DIRECTION OUTPUT ;
    USE SIGNAL ;
    PORT
      LAYER metal5 ;
        RECT 0.000000 1071.280000 0.140000 1071.420000 ;
    END
  END mem_req_data[460]
  PIN mem_req_data[459]
    DIRECTION OUTPUT ;
    USE SIGNAL ;
    PORT
      LAYER metal5 ;
        RECT 0.000000 1076.880000 0.140000 1077.020000 ;
    END
  END mem_req_data[459]
  PIN mem_req_data[458]
    DIRECTION OUTPUT ;
    USE SIGNAL ;
    PORT
      LAYER metal5 ;
        RECT 0.000000 1082.760000 0.140000 1082.900000 ;
    END
  END mem_req_data[458]
  PIN mem_req_data[457]
    DIRECTION OUTPUT ;
    USE SIGNAL ;
    PORT
      LAYER metal5 ;
        RECT 0.000000 1088.360000 0.140000 1088.500000 ;
    END
  END mem_req_data[457]
  PIN mem_req_data[456]
    DIRECTION OUTPUT ;
    USE SIGNAL ;
    PORT
      LAYER metal5 ;
        RECT 0.000000 1093.960000 0.140000 1094.100000 ;
    END
  END mem_req_data[456]
  PIN mem_req_data[455]
    DIRECTION OUTPUT ;
    USE SIGNAL ;
    PORT
      LAYER metal5 ;
        RECT 0.000000 1099.560000 0.140000 1099.700000 ;
    END
  END mem_req_data[455]
  PIN mem_req_data[454]
    DIRECTION OUTPUT ;
    USE SIGNAL ;
    PORT
      LAYER metal5 ;
        RECT 0.000000 1105.160000 0.140000 1105.300000 ;
    END
  END mem_req_data[454]
  PIN mem_req_data[453]
    DIRECTION OUTPUT ;
    USE SIGNAL ;
    PORT
      LAYER metal5 ;
        RECT 0.000000 1110.760000 0.140000 1110.900000 ;
    END
  END mem_req_data[453]
  PIN mem_req_data[452]
    DIRECTION OUTPUT ;
    USE SIGNAL ;
    PORT
      LAYER metal5 ;
        RECT 0.000000 1116.360000 0.140000 1116.500000 ;
    END
  END mem_req_data[452]
  PIN mem_req_data[451]
    DIRECTION OUTPUT ;
    USE SIGNAL ;
    PORT
      LAYER metal5 ;
        RECT 0.000000 1121.960000 0.140000 1122.100000 ;
    END
  END mem_req_data[451]
  PIN mem_req_data[450]
    DIRECTION OUTPUT ;
    USE SIGNAL ;
    PORT
      LAYER metal5 ;
        RECT 0.000000 1127.840000 0.140000 1127.980000 ;
    END
  END mem_req_data[450]
  PIN mem_req_data[449]
    DIRECTION OUTPUT ;
    USE SIGNAL ;
    PORT
      LAYER metal5 ;
        RECT 0.000000 1133.440000 0.140000 1133.580000 ;
    END
  END mem_req_data[449]
  PIN mem_req_data[448]
    DIRECTION OUTPUT ;
    USE SIGNAL ;
    PORT
      LAYER metal5 ;
        RECT 0.000000 1139.040000 0.140000 1139.180000 ;
    END
  END mem_req_data[448]
  PIN mem_req_data[447]
    DIRECTION OUTPUT ;
    USE SIGNAL ;
    PORT
      LAYER metal5 ;
        RECT 0.000000 1144.640000 0.140000 1144.780000 ;
    END
  END mem_req_data[447]
  PIN mem_req_data[446]
    DIRECTION OUTPUT ;
    USE SIGNAL ;
    PORT
      LAYER metal5 ;
        RECT 0.000000 1150.240000 0.140000 1150.380000 ;
    END
  END mem_req_data[446]
  PIN mem_req_data[445]
    DIRECTION OUTPUT ;
    USE SIGNAL ;
    PORT
      LAYER metal5 ;
        RECT 0.000000 1155.840000 0.140000 1155.980000 ;
    END
  END mem_req_data[445]
  PIN mem_req_data[444]
    DIRECTION OUTPUT ;
    USE SIGNAL ;
    PORT
      LAYER metal5 ;
        RECT 0.000000 1161.440000 0.140000 1161.580000 ;
    END
  END mem_req_data[444]
  PIN mem_req_data[443]
    DIRECTION OUTPUT ;
    USE SIGNAL ;
    PORT
      LAYER metal5 ;
        RECT 0.000000 1167.320000 0.140000 1167.460000 ;
    END
  END mem_req_data[443]
  PIN mem_req_data[442]
    DIRECTION OUTPUT ;
    USE SIGNAL ;
    PORT
      LAYER metal5 ;
        RECT 0.000000 1172.920000 0.140000 1173.060000 ;
    END
  END mem_req_data[442]
  PIN mem_req_data[441]
    DIRECTION OUTPUT ;
    USE SIGNAL ;
    PORT
      LAYER metal5 ;
        RECT 0.000000 1178.520000 0.140000 1178.660000 ;
    END
  END mem_req_data[441]
  PIN mem_req_data[440]
    DIRECTION OUTPUT ;
    USE SIGNAL ;
    PORT
      LAYER metal5 ;
        RECT 0.000000 1184.120000 0.140000 1184.260000 ;
    END
  END mem_req_data[440]
  PIN mem_req_data[439]
    DIRECTION OUTPUT ;
    USE SIGNAL ;
    PORT
      LAYER metal5 ;
        RECT 0.000000 1189.720000 0.140000 1189.860000 ;
    END
  END mem_req_data[439]
  PIN mem_req_data[438]
    DIRECTION OUTPUT ;
    USE SIGNAL ;
    PORT
      LAYER metal5 ;
        RECT 0.000000 1195.320000 0.140000 1195.460000 ;
    END
  END mem_req_data[438]
  PIN mem_req_data[437]
    DIRECTION OUTPUT ;
    USE SIGNAL ;
    PORT
      LAYER metal5 ;
        RECT 0.000000 1200.920000 0.140000 1201.060000 ;
    END
  END mem_req_data[437]
  PIN mem_req_data[436]
    DIRECTION OUTPUT ;
    USE SIGNAL ;
    PORT
      LAYER metal5 ;
        RECT 0.000000 1206.800000 0.140000 1206.940000 ;
    END
  END mem_req_data[436]
  PIN mem_req_data[435]
    DIRECTION OUTPUT ;
    USE SIGNAL ;
    PORT
      LAYER metal5 ;
        RECT 0.000000 1212.400000 0.140000 1212.540000 ;
    END
  END mem_req_data[435]
  PIN mem_req_data[434]
    DIRECTION OUTPUT ;
    USE SIGNAL ;
    PORT
      LAYER metal5 ;
        RECT 0.000000 1218.000000 0.140000 1218.140000 ;
    END
  END mem_req_data[434]
  PIN mem_req_data[433]
    DIRECTION OUTPUT ;
    USE SIGNAL ;
    PORT
      LAYER metal5 ;
        RECT 0.000000 1223.600000 0.140000 1223.740000 ;
    END
  END mem_req_data[433]
  PIN mem_req_data[432]
    DIRECTION OUTPUT ;
    USE SIGNAL ;
    PORT
      LAYER metal5 ;
        RECT 0.000000 1229.200000 0.140000 1229.340000 ;
    END
  END mem_req_data[432]
  PIN mem_req_data[431]
    DIRECTION OUTPUT ;
    USE SIGNAL ;
    PORT
      LAYER metal5 ;
        RECT 0.000000 1234.800000 0.140000 1234.940000 ;
    END
  END mem_req_data[431]
  PIN mem_req_data[430]
    DIRECTION OUTPUT ;
    USE SIGNAL ;
    PORT
      LAYER metal5 ;
        RECT 0.000000 1240.400000 0.140000 1240.540000 ;
    END
  END mem_req_data[430]
  PIN mem_req_data[429]
    DIRECTION OUTPUT ;
    USE SIGNAL ;
    PORT
      LAYER metal5 ;
        RECT 0.000000 1246.000000 0.140000 1246.140000 ;
    END
  END mem_req_data[429]
  PIN mem_req_data[428]
    DIRECTION OUTPUT ;
    USE SIGNAL ;
    PORT
      LAYER metal5 ;
        RECT 0.000000 1251.880000 0.140000 1252.020000 ;
    END
  END mem_req_data[428]
  PIN mem_req_data[427]
    DIRECTION OUTPUT ;
    USE SIGNAL ;
    PORT
      LAYER metal5 ;
        RECT 0.000000 1257.480000 0.140000 1257.620000 ;
    END
  END mem_req_data[427]
  PIN mem_req_data[426]
    DIRECTION OUTPUT ;
    USE SIGNAL ;
    PORT
      LAYER metal5 ;
        RECT 0.000000 1263.080000 0.140000 1263.220000 ;
    END
  END mem_req_data[426]
  PIN mem_req_data[425]
    DIRECTION OUTPUT ;
    USE SIGNAL ;
    PORT
      LAYER metal5 ;
        RECT 0.000000 1268.680000 0.140000 1268.820000 ;
    END
  END mem_req_data[425]
  PIN mem_req_data[424]
    DIRECTION OUTPUT ;
    USE SIGNAL ;
    PORT
      LAYER metal5 ;
        RECT 0.000000 1274.280000 0.140000 1274.420000 ;
    END
  END mem_req_data[424]
  PIN mem_req_data[423]
    DIRECTION OUTPUT ;
    USE SIGNAL ;
    PORT
      LAYER metal5 ;
        RECT 0.000000 1279.880000 0.140000 1280.020000 ;
    END
  END mem_req_data[423]
  PIN mem_req_data[422]
    DIRECTION OUTPUT ;
    USE SIGNAL ;
    PORT
      LAYER metal5 ;
        RECT 0.000000 1285.480000 0.140000 1285.620000 ;
    END
  END mem_req_data[422]
  PIN mem_req_data[421]
    DIRECTION OUTPUT ;
    USE SIGNAL ;
    PORT
      LAYER metal5 ;
        RECT 0.000000 1291.360000 0.140000 1291.500000 ;
    END
  END mem_req_data[421]
  PIN mem_req_data[420]
    DIRECTION OUTPUT ;
    USE SIGNAL ;
    PORT
      LAYER metal5 ;
        RECT 0.000000 1296.960000 0.140000 1297.100000 ;
    END
  END mem_req_data[420]
  PIN mem_req_data[419]
    DIRECTION OUTPUT ;
    USE SIGNAL ;
    PORT
      LAYER metal5 ;
        RECT 0.000000 1302.560000 0.140000 1302.700000 ;
    END
  END mem_req_data[419]
  PIN mem_req_data[418]
    DIRECTION OUTPUT ;
    USE SIGNAL ;
    PORT
      LAYER metal5 ;
        RECT 0.000000 1308.160000 0.140000 1308.300000 ;
    END
  END mem_req_data[418]
  PIN mem_req_data[417]
    DIRECTION OUTPUT ;
    USE SIGNAL ;
    PORT
      LAYER metal5 ;
        RECT 0.000000 1313.760000 0.140000 1313.900000 ;
    END
  END mem_req_data[417]
  PIN mem_req_data[416]
    DIRECTION OUTPUT ;
    USE SIGNAL ;
    PORT
      LAYER metal5 ;
        RECT 0.000000 1319.360000 0.140000 1319.500000 ;
    END
  END mem_req_data[416]
  PIN mem_req_data[415]
    DIRECTION OUTPUT ;
    USE SIGNAL ;
    PORT
      LAYER metal5 ;
        RECT 0.000000 1324.960000 0.140000 1325.100000 ;
    END
  END mem_req_data[415]
  PIN mem_req_data[414]
    DIRECTION OUTPUT ;
    USE SIGNAL ;
    PORT
      LAYER metal5 ;
        RECT 0.000000 1330.840000 0.140000 1330.980000 ;
    END
  END mem_req_data[414]
  PIN mem_req_data[413]
    DIRECTION OUTPUT ;
    USE SIGNAL ;
    PORT
      LAYER metal5 ;
        RECT 0.000000 1336.440000 0.140000 1336.580000 ;
    END
  END mem_req_data[413]
  PIN mem_req_data[412]
    DIRECTION OUTPUT ;
    USE SIGNAL ;
    PORT
      LAYER metal5 ;
        RECT 0.000000 1342.040000 0.140000 1342.180000 ;
    END
  END mem_req_data[412]
  PIN mem_req_data[411]
    DIRECTION OUTPUT ;
    USE SIGNAL ;
    PORT
      LAYER metal5 ;
        RECT 0.000000 1347.640000 0.140000 1347.780000 ;
    END
  END mem_req_data[411]
  PIN mem_req_data[410]
    DIRECTION OUTPUT ;
    USE SIGNAL ;
    PORT
      LAYER metal5 ;
        RECT 0.000000 1353.240000 0.140000 1353.380000 ;
    END
  END mem_req_data[410]
  PIN mem_req_data[409]
    DIRECTION OUTPUT ;
    USE SIGNAL ;
    PORT
      LAYER metal5 ;
        RECT 0.000000 1358.840000 0.140000 1358.980000 ;
    END
  END mem_req_data[409]
  PIN mem_req_data[408]
    DIRECTION OUTPUT ;
    USE SIGNAL ;
    PORT
      LAYER metal5 ;
        RECT 0.000000 1364.440000 0.140000 1364.580000 ;
    END
  END mem_req_data[408]
  PIN mem_req_data[407]
    DIRECTION OUTPUT ;
    USE SIGNAL ;
    PORT
      LAYER metal5 ;
        RECT 0.000000 1370.040000 0.140000 1370.180000 ;
    END
  END mem_req_data[407]
  PIN mem_req_data[406]
    DIRECTION OUTPUT ;
    USE SIGNAL ;
    PORT
      LAYER metal5 ;
        RECT 0.000000 1375.920000 0.140000 1376.060000 ;
    END
  END mem_req_data[406]
  PIN mem_req_data[405]
    DIRECTION OUTPUT ;
    USE SIGNAL ;
    PORT
      LAYER metal5 ;
        RECT 0.000000 1381.520000 0.140000 1381.660000 ;
    END
  END mem_req_data[405]
  PIN mem_req_data[404]
    DIRECTION OUTPUT ;
    USE SIGNAL ;
    PORT
      LAYER metal5 ;
        RECT 0.000000 1387.120000 0.140000 1387.260000 ;
    END
  END mem_req_data[404]
  PIN mem_req_data[403]
    DIRECTION OUTPUT ;
    USE SIGNAL ;
    PORT
      LAYER metal5 ;
        RECT 0.000000 1392.720000 0.140000 1392.860000 ;
    END
  END mem_req_data[403]
  PIN mem_req_data[402]
    DIRECTION OUTPUT ;
    USE SIGNAL ;
    PORT
      LAYER metal5 ;
        RECT 0.000000 1398.320000 0.140000 1398.460000 ;
    END
  END mem_req_data[402]
  PIN mem_req_data[401]
    DIRECTION OUTPUT ;
    USE SIGNAL ;
    PORT
      LAYER metal5 ;
        RECT 0.000000 1403.920000 0.140000 1404.060000 ;
    END
  END mem_req_data[401]
  PIN mem_req_data[400]
    DIRECTION OUTPUT ;
    USE SIGNAL ;
    PORT
      LAYER metal5 ;
        RECT 0.000000 1409.520000 0.140000 1409.660000 ;
    END
  END mem_req_data[400]
  PIN mem_req_data[399]
    DIRECTION OUTPUT ;
    USE SIGNAL ;
    PORT
      LAYER metal5 ;
        RECT 0.000000 1415.400000 0.140000 1415.540000 ;
    END
  END mem_req_data[399]
  PIN mem_req_data[398]
    DIRECTION OUTPUT ;
    USE SIGNAL ;
    PORT
      LAYER metal5 ;
        RECT 0.000000 1421.000000 0.140000 1421.140000 ;
    END
  END mem_req_data[398]
  PIN mem_req_data[397]
    DIRECTION OUTPUT ;
    USE SIGNAL ;
    PORT
      LAYER metal5 ;
        RECT 0.000000 1426.600000 0.140000 1426.740000 ;
    END
  END mem_req_data[397]
  PIN mem_req_data[396]
    DIRECTION OUTPUT ;
    USE SIGNAL ;
    PORT
      LAYER metal5 ;
        RECT 0.000000 1432.200000 0.140000 1432.340000 ;
    END
  END mem_req_data[396]
  PIN mem_req_data[395]
    DIRECTION OUTPUT ;
    USE SIGNAL ;
    PORT
      LAYER metal5 ;
        RECT 0.000000 1437.800000 0.140000 1437.940000 ;
    END
  END mem_req_data[395]
  PIN mem_req_data[394]
    DIRECTION OUTPUT ;
    USE SIGNAL ;
    PORT
      LAYER metal5 ;
        RECT 0.000000 1443.400000 0.140000 1443.540000 ;
    END
  END mem_req_data[394]
  PIN mem_req_data[393]
    DIRECTION OUTPUT ;
    USE SIGNAL ;
    PORT
      LAYER metal5 ;
        RECT 0.000000 1449.000000 0.140000 1449.140000 ;
    END
  END mem_req_data[393]
  PIN mem_req_data[392]
    DIRECTION OUTPUT ;
    USE SIGNAL ;
    PORT
      LAYER metal5 ;
        RECT 0.000000 1454.600000 0.140000 1454.740000 ;
    END
  END mem_req_data[392]
  PIN mem_req_data[391]
    DIRECTION OUTPUT ;
    USE SIGNAL ;
    PORT
      LAYER metal5 ;
        RECT 0.000000 1460.480000 0.140000 1460.620000 ;
    END
  END mem_req_data[391]
  PIN mem_req_data[390]
    DIRECTION OUTPUT ;
    USE SIGNAL ;
    PORT
      LAYER metal5 ;
        RECT 0.000000 1466.080000 0.140000 1466.220000 ;
    END
  END mem_req_data[390]
  PIN mem_req_data[389]
    DIRECTION OUTPUT ;
    USE SIGNAL ;
    PORT
      LAYER metal5 ;
        RECT 0.000000 1471.680000 0.140000 1471.820000 ;
    END
  END mem_req_data[389]
  PIN mem_req_data[388]
    DIRECTION OUTPUT ;
    USE SIGNAL ;
    PORT
      LAYER metal5 ;
        RECT 0.000000 1477.280000 0.140000 1477.420000 ;
    END
  END mem_req_data[388]
  PIN mem_req_data[387]
    DIRECTION OUTPUT ;
    USE SIGNAL ;
    PORT
      LAYER metal5 ;
        RECT 0.000000 1482.880000 0.140000 1483.020000 ;
    END
  END mem_req_data[387]
  PIN mem_req_data[386]
    DIRECTION OUTPUT ;
    USE SIGNAL ;
    PORT
      LAYER metal5 ;
        RECT 0.000000 1488.480000 0.140000 1488.620000 ;
    END
  END mem_req_data[386]
  PIN mem_req_data[385]
    DIRECTION OUTPUT ;
    USE SIGNAL ;
    PORT
      LAYER metal5 ;
        RECT 0.000000 1494.080000 0.140000 1494.220000 ;
    END
  END mem_req_data[385]
  PIN mem_req_data[384]
    DIRECTION OUTPUT ;
    USE SIGNAL ;
    PORT
      LAYER metal5 ;
        RECT 0.000000 1499.960000 0.140000 1500.100000 ;
    END
  END mem_req_data[384]
  PIN mem_req_data[383]
    DIRECTION OUTPUT ;
    USE SIGNAL ;
    PORT
      LAYER metal5 ;
        RECT 0.000000 1505.560000 0.140000 1505.700000 ;
    END
  END mem_req_data[383]
  PIN mem_req_data[382]
    DIRECTION OUTPUT ;
    USE SIGNAL ;
    PORT
      LAYER metal5 ;
        RECT 0.000000 1511.160000 0.140000 1511.300000 ;
    END
  END mem_req_data[382]
  PIN mem_req_data[381]
    DIRECTION OUTPUT ;
    USE SIGNAL ;
    PORT
      LAYER metal5 ;
        RECT 0.000000 1516.760000 0.140000 1516.900000 ;
    END
  END mem_req_data[381]
  PIN mem_req_data[380]
    DIRECTION OUTPUT ;
    USE SIGNAL ;
    PORT
      LAYER metal5 ;
        RECT 0.000000 1522.360000 0.140000 1522.500000 ;
    END
  END mem_req_data[380]
  PIN mem_req_data[379]
    DIRECTION OUTPUT ;
    USE SIGNAL ;
    PORT
      LAYER metal5 ;
        RECT 0.000000 1527.960000 0.140000 1528.100000 ;
    END
  END mem_req_data[379]
  PIN mem_req_data[378]
    DIRECTION OUTPUT ;
    USE SIGNAL ;
    PORT
      LAYER metal5 ;
        RECT 0.000000 1533.560000 0.140000 1533.700000 ;
    END
  END mem_req_data[378]
  PIN mem_req_data[377]
    DIRECTION OUTPUT ;
    USE SIGNAL ;
    PORT
      LAYER metal5 ;
        RECT 0.000000 1539.440000 0.140000 1539.580000 ;
    END
  END mem_req_data[377]
  PIN mem_req_data[376]
    DIRECTION OUTPUT ;
    USE SIGNAL ;
    PORT
      LAYER metal5 ;
        RECT 0.000000 1545.040000 0.140000 1545.180000 ;
    END
  END mem_req_data[376]
  PIN mem_req_data[375]
    DIRECTION OUTPUT ;
    USE SIGNAL ;
    PORT
      LAYER metal5 ;
        RECT 0.000000 1550.640000 0.140000 1550.780000 ;
    END
  END mem_req_data[375]
  PIN mem_req_data[374]
    DIRECTION OUTPUT ;
    USE SIGNAL ;
    PORT
      LAYER metal5 ;
        RECT 0.000000 1556.240000 0.140000 1556.380000 ;
    END
  END mem_req_data[374]
  PIN mem_req_data[373]
    DIRECTION OUTPUT ;
    USE SIGNAL ;
    PORT
      LAYER metal5 ;
        RECT 0.000000 1561.840000 0.140000 1561.980000 ;
    END
  END mem_req_data[373]
  PIN mem_req_data[372]
    DIRECTION OUTPUT ;
    USE SIGNAL ;
    PORT
      LAYER metal5 ;
        RECT 0.000000 1567.440000 0.140000 1567.580000 ;
    END
  END mem_req_data[372]
  PIN mem_req_data[371]
    DIRECTION OUTPUT ;
    USE SIGNAL ;
    PORT
      LAYER metal5 ;
        RECT 0.000000 1573.040000 0.140000 1573.180000 ;
    END
  END mem_req_data[371]
  PIN mem_req_data[370]
    DIRECTION OUTPUT ;
    USE SIGNAL ;
    PORT
      LAYER metal5 ;
        RECT 0.000000 1578.640000 0.140000 1578.780000 ;
    END
  END mem_req_data[370]
  PIN mem_req_data[369]
    DIRECTION OUTPUT ;
    USE SIGNAL ;
    PORT
      LAYER metal5 ;
        RECT 0.000000 1584.520000 0.140000 1584.660000 ;
    END
  END mem_req_data[369]
  PIN mem_req_data[368]
    DIRECTION OUTPUT ;
    USE SIGNAL ;
    PORT
      LAYER metal5 ;
        RECT 0.000000 1590.120000 0.140000 1590.260000 ;
    END
  END mem_req_data[368]
  PIN mem_req_data[367]
    DIRECTION OUTPUT ;
    USE SIGNAL ;
    PORT
      LAYER metal5 ;
        RECT 0.000000 1595.720000 0.140000 1595.860000 ;
    END
  END mem_req_data[367]
  PIN mem_req_data[366]
    DIRECTION OUTPUT ;
    USE SIGNAL ;
    PORT
      LAYER metal5 ;
        RECT 0.000000 1601.320000 0.140000 1601.460000 ;
    END
  END mem_req_data[366]
  PIN mem_req_data[365]
    DIRECTION OUTPUT ;
    USE SIGNAL ;
    PORT
      LAYER metal5 ;
        RECT 0.000000 1606.920000 0.140000 1607.060000 ;
    END
  END mem_req_data[365]
  PIN mem_req_data[364]
    DIRECTION OUTPUT ;
    USE SIGNAL ;
    PORT
      LAYER metal5 ;
        RECT 0.000000 1612.520000 0.140000 1612.660000 ;
    END
  END mem_req_data[364]
  PIN mem_req_data[363]
    DIRECTION OUTPUT ;
    USE SIGNAL ;
    PORT
      LAYER metal5 ;
        RECT 0.000000 1618.120000 0.140000 1618.260000 ;
    END
  END mem_req_data[363]
  PIN mem_req_data[362]
    DIRECTION OUTPUT ;
    USE SIGNAL ;
    PORT
      LAYER metal5 ;
        RECT 0.000000 1624.000000 0.140000 1624.140000 ;
    END
  END mem_req_data[362]
  PIN mem_req_data[361]
    DIRECTION OUTPUT ;
    USE SIGNAL ;
    PORT
      LAYER metal5 ;
        RECT 0.000000 1629.600000 0.140000 1629.740000 ;
    END
  END mem_req_data[361]
  PIN mem_req_data[360]
    DIRECTION OUTPUT ;
    USE SIGNAL ;
    PORT
      LAYER metal5 ;
        RECT 0.000000 1635.200000 0.140000 1635.340000 ;
    END
  END mem_req_data[360]
  PIN mem_req_data[359]
    DIRECTION OUTPUT ;
    USE SIGNAL ;
    PORT
      LAYER metal5 ;
        RECT 0.000000 1640.800000 0.140000 1640.940000 ;
    END
  END mem_req_data[359]
  PIN mem_req_data[358]
    DIRECTION OUTPUT ;
    USE SIGNAL ;
    PORT
      LAYER metal5 ;
        RECT 0.000000 1646.400000 0.140000 1646.540000 ;
    END
  END mem_req_data[358]
  PIN mem_req_data[357]
    DIRECTION OUTPUT ;
    USE SIGNAL ;
    PORT
      LAYER metal5 ;
        RECT 0.000000 1652.000000 0.140000 1652.140000 ;
    END
  END mem_req_data[357]
  PIN mem_req_data[356]
    DIRECTION OUTPUT ;
    USE SIGNAL ;
    PORT
      LAYER metal5 ;
        RECT 0.000000 1657.600000 0.140000 1657.740000 ;
    END
  END mem_req_data[356]
  PIN mem_req_data[355]
    DIRECTION OUTPUT ;
    USE SIGNAL ;
    PORT
      LAYER metal5 ;
        RECT 0.000000 1663.200000 0.140000 1663.340000 ;
    END
  END mem_req_data[355]
  PIN mem_req_data[354]
    DIRECTION OUTPUT ;
    USE SIGNAL ;
    PORT
      LAYER metal4 ;
        RECT 1663.125000 0.000000 1663.265000 0.140000 ;
    END
  END mem_req_data[354]
  PIN mem_req_data[353]
    DIRECTION OUTPUT ;
    USE SIGNAL ;
    PORT
      LAYER metal4 ;
        RECT 1657.525000 0.000000 1657.665000 0.140000 ;
    END
  END mem_req_data[353]
  PIN mem_req_data[352]
    DIRECTION OUTPUT ;
    USE SIGNAL ;
    PORT
      LAYER metal4 ;
        RECT 1651.925000 0.000000 1652.065000 0.140000 ;
    END
  END mem_req_data[352]
  PIN mem_req_data[351]
    DIRECTION OUTPUT ;
    USE SIGNAL ;
    PORT
      LAYER metal4 ;
        RECT 1646.325000 0.000000 1646.465000 0.140000 ;
    END
  END mem_req_data[351]
  PIN mem_req_data[350]
    DIRECTION OUTPUT ;
    USE SIGNAL ;
    PORT
      LAYER metal4 ;
        RECT 1640.725000 0.000000 1640.865000 0.140000 ;
    END
  END mem_req_data[350]
  PIN mem_req_data[349]
    DIRECTION OUTPUT ;
    USE SIGNAL ;
    PORT
      LAYER metal4 ;
        RECT 1635.125000 0.000000 1635.265000 0.140000 ;
    END
  END mem_req_data[349]
  PIN mem_req_data[348]
    DIRECTION OUTPUT ;
    USE SIGNAL ;
    PORT
      LAYER metal4 ;
        RECT 1629.525000 0.000000 1629.665000 0.140000 ;
    END
  END mem_req_data[348]
  PIN mem_req_data[347]
    DIRECTION OUTPUT ;
    USE SIGNAL ;
    PORT
      LAYER metal4 ;
        RECT 1623.925000 0.000000 1624.065000 0.140000 ;
    END
  END mem_req_data[347]
  PIN mem_req_data[346]
    DIRECTION OUTPUT ;
    USE SIGNAL ;
    PORT
      LAYER metal4 ;
        RECT 1618.045000 0.000000 1618.185000 0.140000 ;
    END
  END mem_req_data[346]
  PIN mem_req_data[345]
    DIRECTION OUTPUT ;
    USE SIGNAL ;
    PORT
      LAYER metal4 ;
        RECT 1612.445000 0.000000 1612.585000 0.140000 ;
    END
  END mem_req_data[345]
  PIN mem_req_data[344]
    DIRECTION OUTPUT ;
    USE SIGNAL ;
    PORT
      LAYER metal4 ;
        RECT 1606.845000 0.000000 1606.985000 0.140000 ;
    END
  END mem_req_data[344]
  PIN mem_req_data[343]
    DIRECTION OUTPUT ;
    USE SIGNAL ;
    PORT
      LAYER metal4 ;
        RECT 1601.245000 0.000000 1601.385000 0.140000 ;
    END
  END mem_req_data[343]
  PIN mem_req_data[342]
    DIRECTION OUTPUT ;
    USE SIGNAL ;
    PORT
      LAYER metal4 ;
        RECT 1595.645000 0.000000 1595.785000 0.140000 ;
    END
  END mem_req_data[342]
  PIN mem_req_data[341]
    DIRECTION OUTPUT ;
    USE SIGNAL ;
    PORT
      LAYER metal4 ;
        RECT 1590.045000 0.000000 1590.185000 0.140000 ;
    END
  END mem_req_data[341]
  PIN mem_req_data[340]
    DIRECTION OUTPUT ;
    USE SIGNAL ;
    PORT
      LAYER metal4 ;
        RECT 1584.445000 0.000000 1584.585000 0.140000 ;
    END
  END mem_req_data[340]
  PIN mem_req_data[339]
    DIRECTION OUTPUT ;
    USE SIGNAL ;
    PORT
      LAYER metal4 ;
        RECT 1578.845000 0.000000 1578.985000 0.140000 ;
    END
  END mem_req_data[339]
  PIN mem_req_data[338]
    DIRECTION OUTPUT ;
    USE SIGNAL ;
    PORT
      LAYER metal4 ;
        RECT 1572.965000 0.000000 1573.105000 0.140000 ;
    END
  END mem_req_data[338]
  PIN mem_req_data[337]
    DIRECTION OUTPUT ;
    USE SIGNAL ;
    PORT
      LAYER metal4 ;
        RECT 1567.365000 0.000000 1567.505000 0.140000 ;
    END
  END mem_req_data[337]
  PIN mem_req_data[336]
    DIRECTION OUTPUT ;
    USE SIGNAL ;
    PORT
      LAYER metal4 ;
        RECT 1561.765000 0.000000 1561.905000 0.140000 ;
    END
  END mem_req_data[336]
  PIN mem_req_data[335]
    DIRECTION OUTPUT ;
    USE SIGNAL ;
    PORT
      LAYER metal4 ;
        RECT 1556.165000 0.000000 1556.305000 0.140000 ;
    END
  END mem_req_data[335]
  PIN mem_req_data[334]
    DIRECTION OUTPUT ;
    USE SIGNAL ;
    PORT
      LAYER metal4 ;
        RECT 1550.565000 0.000000 1550.705000 0.140000 ;
    END
  END mem_req_data[334]
  PIN mem_req_data[333]
    DIRECTION OUTPUT ;
    USE SIGNAL ;
    PORT
      LAYER metal4 ;
        RECT 1544.965000 0.000000 1545.105000 0.140000 ;
    END
  END mem_req_data[333]
  PIN mem_req_data[332]
    DIRECTION OUTPUT ;
    USE SIGNAL ;
    PORT
      LAYER metal4 ;
        RECT 1539.365000 0.000000 1539.505000 0.140000 ;
    END
  END mem_req_data[332]
  PIN mem_req_data[331]
    DIRECTION OUTPUT ;
    USE SIGNAL ;
    PORT
      LAYER metal4 ;
        RECT 1533.485000 0.000000 1533.625000 0.140000 ;
    END
  END mem_req_data[331]
  PIN mem_req_data[330]
    DIRECTION OUTPUT ;
    USE SIGNAL ;
    PORT
      LAYER metal4 ;
        RECT 1527.885000 0.000000 1528.025000 0.140000 ;
    END
  END mem_req_data[330]
  PIN mem_req_data[329]
    DIRECTION OUTPUT ;
    USE SIGNAL ;
    PORT
      LAYER metal4 ;
        RECT 1522.285000 0.000000 1522.425000 0.140000 ;
    END
  END mem_req_data[329]
  PIN mem_req_data[328]
    DIRECTION OUTPUT ;
    USE SIGNAL ;
    PORT
      LAYER metal4 ;
        RECT 1516.685000 0.000000 1516.825000 0.140000 ;
    END
  END mem_req_data[328]
  PIN mem_req_data[327]
    DIRECTION OUTPUT ;
    USE SIGNAL ;
    PORT
      LAYER metal4 ;
        RECT 1511.085000 0.000000 1511.225000 0.140000 ;
    END
  END mem_req_data[327]
  PIN mem_req_data[326]
    DIRECTION OUTPUT ;
    USE SIGNAL ;
    PORT
      LAYER metal4 ;
        RECT 1505.485000 0.000000 1505.625000 0.140000 ;
    END
  END mem_req_data[326]
  PIN mem_req_data[325]
    DIRECTION OUTPUT ;
    USE SIGNAL ;
    PORT
      LAYER metal4 ;
        RECT 1499.885000 0.000000 1500.025000 0.140000 ;
    END
  END mem_req_data[325]
  PIN mem_req_data[324]
    DIRECTION OUTPUT ;
    USE SIGNAL ;
    PORT
      LAYER metal4 ;
        RECT 1494.285000 0.000000 1494.425000 0.140000 ;
    END
  END mem_req_data[324]
  PIN mem_req_data[323]
    DIRECTION OUTPUT ;
    USE SIGNAL ;
    PORT
      LAYER metal4 ;
        RECT 1488.405000 0.000000 1488.545000 0.140000 ;
    END
  END mem_req_data[323]
  PIN mem_req_data[322]
    DIRECTION OUTPUT ;
    USE SIGNAL ;
    PORT
      LAYER metal4 ;
        RECT 1482.805000 0.000000 1482.945000 0.140000 ;
    END
  END mem_req_data[322]
  PIN mem_req_data[321]
    DIRECTION OUTPUT ;
    USE SIGNAL ;
    PORT
      LAYER metal4 ;
        RECT 1477.205000 0.000000 1477.345000 0.140000 ;
    END
  END mem_req_data[321]
  PIN mem_req_data[320]
    DIRECTION OUTPUT ;
    USE SIGNAL ;
    PORT
      LAYER metal4 ;
        RECT 1471.605000 0.000000 1471.745000 0.140000 ;
    END
  END mem_req_data[320]
  PIN mem_req_data[319]
    DIRECTION OUTPUT ;
    USE SIGNAL ;
    PORT
      LAYER metal4 ;
        RECT 1466.005000 0.000000 1466.145000 0.140000 ;
    END
  END mem_req_data[319]
  PIN mem_req_data[318]
    DIRECTION OUTPUT ;
    USE SIGNAL ;
    PORT
      LAYER metal4 ;
        RECT 1460.405000 0.000000 1460.545000 0.140000 ;
    END
  END mem_req_data[318]
  PIN mem_req_data[317]
    DIRECTION OUTPUT ;
    USE SIGNAL ;
    PORT
      LAYER metal4 ;
        RECT 1454.805000 0.000000 1454.945000 0.140000 ;
    END
  END mem_req_data[317]
  PIN mem_req_data[316]
    DIRECTION OUTPUT ;
    USE SIGNAL ;
    PORT
      LAYER metal4 ;
        RECT 1448.925000 0.000000 1449.065000 0.140000 ;
    END
  END mem_req_data[316]
  PIN mem_req_data[315]
    DIRECTION OUTPUT ;
    USE SIGNAL ;
    PORT
      LAYER metal4 ;
        RECT 1443.325000 0.000000 1443.465000 0.140000 ;
    END
  END mem_req_data[315]
  PIN mem_req_data[314]
    DIRECTION OUTPUT ;
    USE SIGNAL ;
    PORT
      LAYER metal4 ;
        RECT 1437.725000 0.000000 1437.865000 0.140000 ;
    END
  END mem_req_data[314]
  PIN mem_req_data[313]
    DIRECTION OUTPUT ;
    USE SIGNAL ;
    PORT
      LAYER metal4 ;
        RECT 1432.125000 0.000000 1432.265000 0.140000 ;
    END
  END mem_req_data[313]
  PIN mem_req_data[312]
    DIRECTION OUTPUT ;
    USE SIGNAL ;
    PORT
      LAYER metal4 ;
        RECT 1426.525000 0.000000 1426.665000 0.140000 ;
    END
  END mem_req_data[312]
  PIN mem_req_data[311]
    DIRECTION OUTPUT ;
    USE SIGNAL ;
    PORT
      LAYER metal4 ;
        RECT 1420.925000 0.000000 1421.065000 0.140000 ;
    END
  END mem_req_data[311]
  PIN mem_req_data[310]
    DIRECTION OUTPUT ;
    USE SIGNAL ;
    PORT
      LAYER metal4 ;
        RECT 1415.325000 0.000000 1415.465000 0.140000 ;
    END
  END mem_req_data[310]
  PIN mem_req_data[309]
    DIRECTION OUTPUT ;
    USE SIGNAL ;
    PORT
      LAYER metal4 ;
        RECT 1409.725000 0.000000 1409.865000 0.140000 ;
    END
  END mem_req_data[309]
  PIN mem_req_data[308]
    DIRECTION OUTPUT ;
    USE SIGNAL ;
    PORT
      LAYER metal4 ;
        RECT 1403.845000 0.000000 1403.985000 0.140000 ;
    END
  END mem_req_data[308]
  PIN mem_req_data[307]
    DIRECTION OUTPUT ;
    USE SIGNAL ;
    PORT
      LAYER metal4 ;
        RECT 1398.245000 0.000000 1398.385000 0.140000 ;
    END
  END mem_req_data[307]
  PIN mem_req_data[306]
    DIRECTION OUTPUT ;
    USE SIGNAL ;
    PORT
      LAYER metal4 ;
        RECT 1392.645000 0.000000 1392.785000 0.140000 ;
    END
  END mem_req_data[306]
  PIN mem_req_data[305]
    DIRECTION OUTPUT ;
    USE SIGNAL ;
    PORT
      LAYER metal4 ;
        RECT 1387.045000 0.000000 1387.185000 0.140000 ;
    END
  END mem_req_data[305]
  PIN mem_req_data[304]
    DIRECTION OUTPUT ;
    USE SIGNAL ;
    PORT
      LAYER metal4 ;
        RECT 1381.445000 0.000000 1381.585000 0.140000 ;
    END
  END mem_req_data[304]
  PIN mem_req_data[303]
    DIRECTION OUTPUT ;
    USE SIGNAL ;
    PORT
      LAYER metal4 ;
        RECT 1375.845000 0.000000 1375.985000 0.140000 ;
    END
  END mem_req_data[303]
  PIN mem_req_data[302]
    DIRECTION OUTPUT ;
    USE SIGNAL ;
    PORT
      LAYER metal4 ;
        RECT 1370.245000 0.000000 1370.385000 0.140000 ;
    END
  END mem_req_data[302]
  PIN mem_req_data[301]
    DIRECTION OUTPUT ;
    USE SIGNAL ;
    PORT
      LAYER metal4 ;
        RECT 1364.365000 0.000000 1364.505000 0.140000 ;
    END
  END mem_req_data[301]
  PIN mem_req_data[300]
    DIRECTION OUTPUT ;
    USE SIGNAL ;
    PORT
      LAYER metal4 ;
        RECT 1358.765000 0.000000 1358.905000 0.140000 ;
    END
  END mem_req_data[300]
  PIN mem_req_data[299]
    DIRECTION OUTPUT ;
    USE SIGNAL ;
    PORT
      LAYER metal4 ;
        RECT 1353.165000 0.000000 1353.305000 0.140000 ;
    END
  END mem_req_data[299]
  PIN mem_req_data[298]
    DIRECTION OUTPUT ;
    USE SIGNAL ;
    PORT
      LAYER metal4 ;
        RECT 1347.565000 0.000000 1347.705000 0.140000 ;
    END
  END mem_req_data[298]
  PIN mem_req_data[297]
    DIRECTION OUTPUT ;
    USE SIGNAL ;
    PORT
      LAYER metal4 ;
        RECT 1341.965000 0.000000 1342.105000 0.140000 ;
    END
  END mem_req_data[297]
  PIN mem_req_data[296]
    DIRECTION OUTPUT ;
    USE SIGNAL ;
    PORT
      LAYER metal4 ;
        RECT 1336.365000 0.000000 1336.505000 0.140000 ;
    END
  END mem_req_data[296]
  PIN mem_req_data[295]
    DIRECTION OUTPUT ;
    USE SIGNAL ;
    PORT
      LAYER metal4 ;
        RECT 1330.765000 0.000000 1330.905000 0.140000 ;
    END
  END mem_req_data[295]
  PIN mem_req_data[294]
    DIRECTION OUTPUT ;
    USE SIGNAL ;
    PORT
      LAYER metal4 ;
        RECT 1325.165000 0.000000 1325.305000 0.140000 ;
    END
  END mem_req_data[294]
  PIN mem_req_data[293]
    DIRECTION OUTPUT ;
    USE SIGNAL ;
    PORT
      LAYER metal4 ;
        RECT 1319.285000 0.000000 1319.425000 0.140000 ;
    END
  END mem_req_data[293]
  PIN mem_req_data[292]
    DIRECTION OUTPUT ;
    USE SIGNAL ;
    PORT
      LAYER metal4 ;
        RECT 1313.685000 0.000000 1313.825000 0.140000 ;
    END
  END mem_req_data[292]
  PIN mem_req_data[291]
    DIRECTION OUTPUT ;
    USE SIGNAL ;
    PORT
      LAYER metal4 ;
        RECT 1308.085000 0.000000 1308.225000 0.140000 ;
    END
  END mem_req_data[291]
  PIN mem_req_data[290]
    DIRECTION OUTPUT ;
    USE SIGNAL ;
    PORT
      LAYER metal4 ;
        RECT 1302.485000 0.000000 1302.625000 0.140000 ;
    END
  END mem_req_data[290]
  PIN mem_req_data[289]
    DIRECTION OUTPUT ;
    USE SIGNAL ;
    PORT
      LAYER metal4 ;
        RECT 1296.885000 0.000000 1297.025000 0.140000 ;
    END
  END mem_req_data[289]
  PIN mem_req_data[288]
    DIRECTION OUTPUT ;
    USE SIGNAL ;
    PORT
      LAYER metal4 ;
        RECT 1291.285000 0.000000 1291.425000 0.140000 ;
    END
  END mem_req_data[288]
  PIN mem_req_data[287]
    DIRECTION OUTPUT ;
    USE SIGNAL ;
    PORT
      LAYER metal4 ;
        RECT 1285.685000 0.000000 1285.825000 0.140000 ;
    END
  END mem_req_data[287]
  PIN mem_req_data[286]
    DIRECTION OUTPUT ;
    USE SIGNAL ;
    PORT
      LAYER metal4 ;
        RECT 1280.085000 0.000000 1280.225000 0.140000 ;
    END
  END mem_req_data[286]
  PIN mem_req_data[285]
    DIRECTION OUTPUT ;
    USE SIGNAL ;
    PORT
      LAYER metal4 ;
        RECT 1274.205000 0.000000 1274.345000 0.140000 ;
    END
  END mem_req_data[285]
  PIN mem_req_data[284]
    DIRECTION OUTPUT ;
    USE SIGNAL ;
    PORT
      LAYER metal4 ;
        RECT 1268.605000 0.000000 1268.745000 0.140000 ;
    END
  END mem_req_data[284]
  PIN mem_req_data[283]
    DIRECTION OUTPUT ;
    USE SIGNAL ;
    PORT
      LAYER metal4 ;
        RECT 1263.005000 0.000000 1263.145000 0.140000 ;
    END
  END mem_req_data[283]
  PIN mem_req_data[282]
    DIRECTION OUTPUT ;
    USE SIGNAL ;
    PORT
      LAYER metal4 ;
        RECT 1257.405000 0.000000 1257.545000 0.140000 ;
    END
  END mem_req_data[282]
  PIN mem_req_data[281]
    DIRECTION OUTPUT ;
    USE SIGNAL ;
    PORT
      LAYER metal4 ;
        RECT 1251.805000 0.000000 1251.945000 0.140000 ;
    END
  END mem_req_data[281]
  PIN mem_req_data[280]
    DIRECTION OUTPUT ;
    USE SIGNAL ;
    PORT
      LAYER metal4 ;
        RECT 1246.205000 0.000000 1246.345000 0.140000 ;
    END
  END mem_req_data[280]
  PIN mem_req_data[279]
    DIRECTION OUTPUT ;
    USE SIGNAL ;
    PORT
      LAYER metal4 ;
        RECT 1240.605000 0.000000 1240.745000 0.140000 ;
    END
  END mem_req_data[279]
  PIN mem_req_data[278]
    DIRECTION OUTPUT ;
    USE SIGNAL ;
    PORT
      LAYER metal4 ;
        RECT 1234.725000 0.000000 1234.865000 0.140000 ;
    END
  END mem_req_data[278]
  PIN mem_req_data[277]
    DIRECTION OUTPUT ;
    USE SIGNAL ;
    PORT
      LAYER metal4 ;
        RECT 1229.125000 0.000000 1229.265000 0.140000 ;
    END
  END mem_req_data[277]
  PIN mem_req_data[276]
    DIRECTION OUTPUT ;
    USE SIGNAL ;
    PORT
      LAYER metal4 ;
        RECT 1223.525000 0.000000 1223.665000 0.140000 ;
    END
  END mem_req_data[276]
  PIN mem_req_data[275]
    DIRECTION OUTPUT ;
    USE SIGNAL ;
    PORT
      LAYER metal4 ;
        RECT 1217.925000 0.000000 1218.065000 0.140000 ;
    END
  END mem_req_data[275]
  PIN mem_req_data[274]
    DIRECTION OUTPUT ;
    USE SIGNAL ;
    PORT
      LAYER metal4 ;
        RECT 1212.325000 0.000000 1212.465000 0.140000 ;
    END
  END mem_req_data[274]
  PIN mem_req_data[273]
    DIRECTION OUTPUT ;
    USE SIGNAL ;
    PORT
      LAYER metal4 ;
        RECT 1206.725000 0.000000 1206.865000 0.140000 ;
    END
  END mem_req_data[273]
  PIN mem_req_data[272]
    DIRECTION OUTPUT ;
    USE SIGNAL ;
    PORT
      LAYER metal4 ;
        RECT 1201.125000 0.000000 1201.265000 0.140000 ;
    END
  END mem_req_data[272]
  PIN mem_req_data[271]
    DIRECTION OUTPUT ;
    USE SIGNAL ;
    PORT
      LAYER metal4 ;
        RECT 1195.525000 0.000000 1195.665000 0.140000 ;
    END
  END mem_req_data[271]
  PIN mem_req_data[270]
    DIRECTION OUTPUT ;
    USE SIGNAL ;
    PORT
      LAYER metal4 ;
        RECT 1189.645000 0.000000 1189.785000 0.140000 ;
    END
  END mem_req_data[270]
  PIN mem_req_data[269]
    DIRECTION OUTPUT ;
    USE SIGNAL ;
    PORT
      LAYER metal4 ;
        RECT 1184.045000 0.000000 1184.185000 0.140000 ;
    END
  END mem_req_data[269]
  PIN mem_req_data[268]
    DIRECTION OUTPUT ;
    USE SIGNAL ;
    PORT
      LAYER metal4 ;
        RECT 1178.445000 0.000000 1178.585000 0.140000 ;
    END
  END mem_req_data[268]
  PIN mem_req_data[267]
    DIRECTION OUTPUT ;
    USE SIGNAL ;
    PORT
      LAYER metal4 ;
        RECT 1172.845000 0.000000 1172.985000 0.140000 ;
    END
  END mem_req_data[267]
  PIN mem_req_data[266]
    DIRECTION OUTPUT ;
    USE SIGNAL ;
    PORT
      LAYER metal4 ;
        RECT 1167.245000 0.000000 1167.385000 0.140000 ;
    END
  END mem_req_data[266]
  PIN mem_req_data[265]
    DIRECTION OUTPUT ;
    USE SIGNAL ;
    PORT
      LAYER metal4 ;
        RECT 1161.645000 0.000000 1161.785000 0.140000 ;
    END
  END mem_req_data[265]
  PIN mem_req_data[264]
    DIRECTION OUTPUT ;
    USE SIGNAL ;
    PORT
      LAYER metal4 ;
        RECT 1156.045000 0.000000 1156.185000 0.140000 ;
    END
  END mem_req_data[264]
  PIN mem_req_data[263]
    DIRECTION OUTPUT ;
    USE SIGNAL ;
    PORT
      LAYER metal4 ;
        RECT 1150.165000 0.000000 1150.305000 0.140000 ;
    END
  END mem_req_data[263]
  PIN mem_req_data[262]
    DIRECTION OUTPUT ;
    USE SIGNAL ;
    PORT
      LAYER metal4 ;
        RECT 1144.565000 0.000000 1144.705000 0.140000 ;
    END
  END mem_req_data[262]
  PIN mem_req_data[261]
    DIRECTION OUTPUT ;
    USE SIGNAL ;
    PORT
      LAYER metal4 ;
        RECT 1138.965000 0.000000 1139.105000 0.140000 ;
    END
  END mem_req_data[261]
  PIN mem_req_data[260]
    DIRECTION OUTPUT ;
    USE SIGNAL ;
    PORT
      LAYER metal4 ;
        RECT 1133.365000 0.000000 1133.505000 0.140000 ;
    END
  END mem_req_data[260]
  PIN mem_req_data[259]
    DIRECTION OUTPUT ;
    USE SIGNAL ;
    PORT
      LAYER metal4 ;
        RECT 1127.765000 0.000000 1127.905000 0.140000 ;
    END
  END mem_req_data[259]
  PIN mem_req_data[258]
    DIRECTION OUTPUT ;
    USE SIGNAL ;
    PORT
      LAYER metal4 ;
        RECT 1122.165000 0.000000 1122.305000 0.140000 ;
    END
  END mem_req_data[258]
  PIN mem_req_data[257]
    DIRECTION OUTPUT ;
    USE SIGNAL ;
    PORT
      LAYER metal4 ;
        RECT 1116.565000 0.000000 1116.705000 0.140000 ;
    END
  END mem_req_data[257]
  PIN mem_req_data[256]
    DIRECTION OUTPUT ;
    USE SIGNAL ;
    PORT
      LAYER metal4 ;
        RECT 1110.965000 0.000000 1111.105000 0.140000 ;
    END
  END mem_req_data[256]
  PIN mem_req_data[255]
    DIRECTION OUTPUT ;
    USE SIGNAL ;
    PORT
      LAYER metal4 ;
        RECT 1105.085000 0.000000 1105.225000 0.140000 ;
    END
  END mem_req_data[255]
  PIN mem_req_data[254]
    DIRECTION OUTPUT ;
    USE SIGNAL ;
    PORT
      LAYER metal4 ;
        RECT 1099.485000 0.000000 1099.625000 0.140000 ;
    END
  END mem_req_data[254]
  PIN mem_req_data[253]
    DIRECTION OUTPUT ;
    USE SIGNAL ;
    PORT
      LAYER metal4 ;
        RECT 1093.885000 0.000000 1094.025000 0.140000 ;
    END
  END mem_req_data[253]
  PIN mem_req_data[252]
    DIRECTION OUTPUT ;
    USE SIGNAL ;
    PORT
      LAYER metal4 ;
        RECT 1088.285000 0.000000 1088.425000 0.140000 ;
    END
  END mem_req_data[252]
  PIN mem_req_data[251]
    DIRECTION OUTPUT ;
    USE SIGNAL ;
    PORT
      LAYER metal4 ;
        RECT 1082.685000 0.000000 1082.825000 0.140000 ;
    END
  END mem_req_data[251]
  PIN mem_req_data[250]
    DIRECTION OUTPUT ;
    USE SIGNAL ;
    PORT
      LAYER metal4 ;
        RECT 1077.085000 0.000000 1077.225000 0.140000 ;
    END
  END mem_req_data[250]
  PIN mem_req_data[249]
    DIRECTION OUTPUT ;
    USE SIGNAL ;
    PORT
      LAYER metal4 ;
        RECT 1071.485000 0.000000 1071.625000 0.140000 ;
    END
  END mem_req_data[249]
  PIN mem_req_data[248]
    DIRECTION OUTPUT ;
    USE SIGNAL ;
    PORT
      LAYER metal4 ;
        RECT 1065.605000 0.000000 1065.745000 0.140000 ;
    END
  END mem_req_data[248]
  PIN mem_req_data[247]
    DIRECTION OUTPUT ;
    USE SIGNAL ;
    PORT
      LAYER metal4 ;
        RECT 1060.005000 0.000000 1060.145000 0.140000 ;
    END
  END mem_req_data[247]
  PIN mem_req_data[246]
    DIRECTION OUTPUT ;
    USE SIGNAL ;
    PORT
      LAYER metal4 ;
        RECT 1054.405000 0.000000 1054.545000 0.140000 ;
    END
  END mem_req_data[246]
  PIN mem_req_data[245]
    DIRECTION OUTPUT ;
    USE SIGNAL ;
    PORT
      LAYER metal4 ;
        RECT 1048.805000 0.000000 1048.945000 0.140000 ;
    END
  END mem_req_data[245]
  PIN mem_req_data[244]
    DIRECTION OUTPUT ;
    USE SIGNAL ;
    PORT
      LAYER metal4 ;
        RECT 1043.205000 0.000000 1043.345000 0.140000 ;
    END
  END mem_req_data[244]
  PIN mem_req_data[243]
    DIRECTION OUTPUT ;
    USE SIGNAL ;
    PORT
      LAYER metal4 ;
        RECT 1037.605000 0.000000 1037.745000 0.140000 ;
    END
  END mem_req_data[243]
  PIN mem_req_data[242]
    DIRECTION OUTPUT ;
    USE SIGNAL ;
    PORT
      LAYER metal4 ;
        RECT 1032.005000 0.000000 1032.145000 0.140000 ;
    END
  END mem_req_data[242]
  PIN mem_req_data[241]
    DIRECTION OUTPUT ;
    USE SIGNAL ;
    PORT
      LAYER metal4 ;
        RECT 1026.405000 0.000000 1026.545000 0.140000 ;
    END
  END mem_req_data[241]
  PIN mem_req_data[240]
    DIRECTION OUTPUT ;
    USE SIGNAL ;
    PORT
      LAYER metal4 ;
        RECT 1020.525000 0.000000 1020.665000 0.140000 ;
    END
  END mem_req_data[240]
  PIN mem_req_data[239]
    DIRECTION OUTPUT ;
    USE SIGNAL ;
    PORT
      LAYER metal4 ;
        RECT 1014.925000 0.000000 1015.065000 0.140000 ;
    END
  END mem_req_data[239]
  PIN mem_req_data[238]
    DIRECTION OUTPUT ;
    USE SIGNAL ;
    PORT
      LAYER metal4 ;
        RECT 1009.325000 0.000000 1009.465000 0.140000 ;
    END
  END mem_req_data[238]
  PIN mem_req_data[237]
    DIRECTION OUTPUT ;
    USE SIGNAL ;
    PORT
      LAYER metal4 ;
        RECT 1003.725000 0.000000 1003.865000 0.140000 ;
    END
  END mem_req_data[237]
  PIN mem_req_data[236]
    DIRECTION OUTPUT ;
    USE SIGNAL ;
    PORT
      LAYER metal4 ;
        RECT 998.125000 0.000000 998.265000 0.140000 ;
    END
  END mem_req_data[236]
  PIN mem_req_data[235]
    DIRECTION OUTPUT ;
    USE SIGNAL ;
    PORT
      LAYER metal4 ;
        RECT 992.525000 0.000000 992.665000 0.140000 ;
    END
  END mem_req_data[235]
  PIN mem_req_data[234]
    DIRECTION OUTPUT ;
    USE SIGNAL ;
    PORT
      LAYER metal4 ;
        RECT 986.925000 0.000000 987.065000 0.140000 ;
    END
  END mem_req_data[234]
  PIN mem_req_data[233]
    DIRECTION OUTPUT ;
    USE SIGNAL ;
    PORT
      LAYER metal4 ;
        RECT 981.325000 0.000000 981.465000 0.140000 ;
    END
  END mem_req_data[233]
  PIN mem_req_data[232]
    DIRECTION OUTPUT ;
    USE SIGNAL ;
    PORT
      LAYER metal4 ;
        RECT 975.445000 0.000000 975.585000 0.140000 ;
    END
  END mem_req_data[232]
  PIN mem_req_data[231]
    DIRECTION OUTPUT ;
    USE SIGNAL ;
    PORT
      LAYER metal4 ;
        RECT 969.845000 0.000000 969.985000 0.140000 ;
    END
  END mem_req_data[231]
  PIN mem_req_data[230]
    DIRECTION OUTPUT ;
    USE SIGNAL ;
    PORT
      LAYER metal4 ;
        RECT 964.245000 0.000000 964.385000 0.140000 ;
    END
  END mem_req_data[230]
  PIN mem_req_data[229]
    DIRECTION OUTPUT ;
    USE SIGNAL ;
    PORT
      LAYER metal4 ;
        RECT 958.645000 0.000000 958.785000 0.140000 ;
    END
  END mem_req_data[229]
  PIN mem_req_data[228]
    DIRECTION OUTPUT ;
    USE SIGNAL ;
    PORT
      LAYER metal4 ;
        RECT 953.045000 0.000000 953.185000 0.140000 ;
    END
  END mem_req_data[228]
  PIN mem_req_data[227]
    DIRECTION OUTPUT ;
    USE SIGNAL ;
    PORT
      LAYER metal4 ;
        RECT 947.445000 0.000000 947.585000 0.140000 ;
    END
  END mem_req_data[227]
  PIN mem_req_data[226]
    DIRECTION OUTPUT ;
    USE SIGNAL ;
    PORT
      LAYER metal4 ;
        RECT 941.845000 0.000000 941.985000 0.140000 ;
    END
  END mem_req_data[226]
  PIN mem_req_data[225]
    DIRECTION OUTPUT ;
    USE SIGNAL ;
    PORT
      LAYER metal4 ;
        RECT 935.965000 0.000000 936.105000 0.140000 ;
    END
  END mem_req_data[225]
  PIN mem_req_data[224]
    DIRECTION OUTPUT ;
    USE SIGNAL ;
    PORT
      LAYER metal4 ;
        RECT 930.365000 0.000000 930.505000 0.140000 ;
    END
  END mem_req_data[224]
  PIN mem_req_data[223]
    DIRECTION OUTPUT ;
    USE SIGNAL ;
    PORT
      LAYER metal4 ;
        RECT 924.765000 0.000000 924.905000 0.140000 ;
    END
  END mem_req_data[223]
  PIN mem_req_data[222]
    DIRECTION OUTPUT ;
    USE SIGNAL ;
    PORT
      LAYER metal4 ;
        RECT 919.165000 0.000000 919.305000 0.140000 ;
    END
  END mem_req_data[222]
  PIN mem_req_data[221]
    DIRECTION OUTPUT ;
    USE SIGNAL ;
    PORT
      LAYER metal4 ;
        RECT 913.565000 0.000000 913.705000 0.140000 ;
    END
  END mem_req_data[221]
  PIN mem_req_data[220]
    DIRECTION OUTPUT ;
    USE SIGNAL ;
    PORT
      LAYER metal4 ;
        RECT 907.965000 0.000000 908.105000 0.140000 ;
    END
  END mem_req_data[220]
  PIN mem_req_data[219]
    DIRECTION OUTPUT ;
    USE SIGNAL ;
    PORT
      LAYER metal4 ;
        RECT 902.365000 0.000000 902.505000 0.140000 ;
    END
  END mem_req_data[219]
  PIN mem_req_data[218]
    DIRECTION OUTPUT ;
    USE SIGNAL ;
    PORT
      LAYER metal4 ;
        RECT 896.765000 0.000000 896.905000 0.140000 ;
    END
  END mem_req_data[218]
  PIN mem_req_data[217]
    DIRECTION OUTPUT ;
    USE SIGNAL ;
    PORT
      LAYER metal4 ;
        RECT 890.885000 0.000000 891.025000 0.140000 ;
    END
  END mem_req_data[217]
  PIN mem_req_data[216]
    DIRECTION OUTPUT ;
    USE SIGNAL ;
    PORT
      LAYER metal4 ;
        RECT 885.285000 0.000000 885.425000 0.140000 ;
    END
  END mem_req_data[216]
  PIN mem_req_data[215]
    DIRECTION OUTPUT ;
    USE SIGNAL ;
    PORT
      LAYER metal4 ;
        RECT 879.685000 0.000000 879.825000 0.140000 ;
    END
  END mem_req_data[215]
  PIN mem_req_data[214]
    DIRECTION OUTPUT ;
    USE SIGNAL ;
    PORT
      LAYER metal4 ;
        RECT 874.085000 0.000000 874.225000 0.140000 ;
    END
  END mem_req_data[214]
  PIN mem_req_data[213]
    DIRECTION OUTPUT ;
    USE SIGNAL ;
    PORT
      LAYER metal4 ;
        RECT 868.485000 0.000000 868.625000 0.140000 ;
    END
  END mem_req_data[213]
  PIN mem_req_data[212]
    DIRECTION OUTPUT ;
    USE SIGNAL ;
    PORT
      LAYER metal4 ;
        RECT 862.885000 0.000000 863.025000 0.140000 ;
    END
  END mem_req_data[212]
  PIN mem_req_data[211]
    DIRECTION OUTPUT ;
    USE SIGNAL ;
    PORT
      LAYER metal4 ;
        RECT 857.285000 0.000000 857.425000 0.140000 ;
    END
  END mem_req_data[211]
  PIN mem_req_data[210]
    DIRECTION OUTPUT ;
    USE SIGNAL ;
    PORT
      LAYER metal4 ;
        RECT 851.405000 0.000000 851.545000 0.140000 ;
    END
  END mem_req_data[210]
  PIN mem_req_data[209]
    DIRECTION OUTPUT ;
    USE SIGNAL ;
    PORT
      LAYER metal4 ;
        RECT 845.805000 0.000000 845.945000 0.140000 ;
    END
  END mem_req_data[209]
  PIN mem_req_data[208]
    DIRECTION OUTPUT ;
    USE SIGNAL ;
    PORT
      LAYER metal4 ;
        RECT 840.205000 0.000000 840.345000 0.140000 ;
    END
  END mem_req_data[208]
  PIN mem_req_data[207]
    DIRECTION OUTPUT ;
    USE SIGNAL ;
    PORT
      LAYER metal4 ;
        RECT 834.605000 0.000000 834.745000 0.140000 ;
    END
  END mem_req_data[207]
  PIN mem_req_data[206]
    DIRECTION OUTPUT ;
    USE SIGNAL ;
    PORT
      LAYER metal4 ;
        RECT 829.005000 0.000000 829.145000 0.140000 ;
    END
  END mem_req_data[206]
  PIN mem_req_data[205]
    DIRECTION OUTPUT ;
    USE SIGNAL ;
    PORT
      LAYER metal4 ;
        RECT 823.405000 0.000000 823.545000 0.140000 ;
    END
  END mem_req_data[205]
  PIN mem_req_data[204]
    DIRECTION OUTPUT ;
    USE SIGNAL ;
    PORT
      LAYER metal4 ;
        RECT 817.805000 0.000000 817.945000 0.140000 ;
    END
  END mem_req_data[204]
  PIN mem_req_data[203]
    DIRECTION OUTPUT ;
    USE SIGNAL ;
    PORT
      LAYER metal4 ;
        RECT 812.205000 0.000000 812.345000 0.140000 ;
    END
  END mem_req_data[203]
  PIN mem_req_data[202]
    DIRECTION OUTPUT ;
    USE SIGNAL ;
    PORT
      LAYER metal4 ;
        RECT 806.325000 0.000000 806.465000 0.140000 ;
    END
  END mem_req_data[202]
  PIN mem_req_data[201]
    DIRECTION OUTPUT ;
    USE SIGNAL ;
    PORT
      LAYER metal4 ;
        RECT 800.725000 0.000000 800.865000 0.140000 ;
    END
  END mem_req_data[201]
  PIN mem_req_data[200]
    DIRECTION OUTPUT ;
    USE SIGNAL ;
    PORT
      LAYER metal4 ;
        RECT 795.125000 0.000000 795.265000 0.140000 ;
    END
  END mem_req_data[200]
  PIN mem_req_data[199]
    DIRECTION OUTPUT ;
    USE SIGNAL ;
    PORT
      LAYER metal4 ;
        RECT 789.525000 0.000000 789.665000 0.140000 ;
    END
  END mem_req_data[199]
  PIN mem_req_data[198]
    DIRECTION OUTPUT ;
    USE SIGNAL ;
    PORT
      LAYER metal4 ;
        RECT 783.925000 0.000000 784.065000 0.140000 ;
    END
  END mem_req_data[198]
  PIN mem_req_data[197]
    DIRECTION OUTPUT ;
    USE SIGNAL ;
    PORT
      LAYER metal4 ;
        RECT 778.325000 0.000000 778.465000 0.140000 ;
    END
  END mem_req_data[197]
  PIN mem_req_data[196]
    DIRECTION OUTPUT ;
    USE SIGNAL ;
    PORT
      LAYER metal4 ;
        RECT 772.725000 0.000000 772.865000 0.140000 ;
    END
  END mem_req_data[196]
  PIN mem_req_data[195]
    DIRECTION OUTPUT ;
    USE SIGNAL ;
    PORT
      LAYER metal4 ;
        RECT 766.845000 0.000000 766.985000 0.140000 ;
    END
  END mem_req_data[195]
  PIN mem_req_data[194]
    DIRECTION OUTPUT ;
    USE SIGNAL ;
    PORT
      LAYER metal4 ;
        RECT 761.245000 0.000000 761.385000 0.140000 ;
    END
  END mem_req_data[194]
  PIN mem_req_data[193]
    DIRECTION OUTPUT ;
    USE SIGNAL ;
    PORT
      LAYER metal4 ;
        RECT 755.645000 0.000000 755.785000 0.140000 ;
    END
  END mem_req_data[193]
  PIN mem_req_data[192]
    DIRECTION OUTPUT ;
    USE SIGNAL ;
    PORT
      LAYER metal4 ;
        RECT 750.045000 0.000000 750.185000 0.140000 ;
    END
  END mem_req_data[192]
  PIN mem_req_data[191]
    DIRECTION OUTPUT ;
    USE SIGNAL ;
    PORT
      LAYER metal4 ;
        RECT 744.445000 0.000000 744.585000 0.140000 ;
    END
  END mem_req_data[191]
  PIN mem_req_data[190]
    DIRECTION OUTPUT ;
    USE SIGNAL ;
    PORT
      LAYER metal4 ;
        RECT 738.845000 0.000000 738.985000 0.140000 ;
    END
  END mem_req_data[190]
  PIN mem_req_data[189]
    DIRECTION OUTPUT ;
    USE SIGNAL ;
    PORT
      LAYER metal4 ;
        RECT 733.245000 0.000000 733.385000 0.140000 ;
    END
  END mem_req_data[189]
  PIN mem_req_data[188]
    DIRECTION OUTPUT ;
    USE SIGNAL ;
    PORT
      LAYER metal4 ;
        RECT 727.645000 0.000000 727.785000 0.140000 ;
    END
  END mem_req_data[188]
  PIN mem_req_data[187]
    DIRECTION OUTPUT ;
    USE SIGNAL ;
    PORT
      LAYER metal4 ;
        RECT 721.765000 0.000000 721.905000 0.140000 ;
    END
  END mem_req_data[187]
  PIN mem_req_data[186]
    DIRECTION OUTPUT ;
    USE SIGNAL ;
    PORT
      LAYER metal4 ;
        RECT 716.165000 0.000000 716.305000 0.140000 ;
    END
  END mem_req_data[186]
  PIN mem_req_data[185]
    DIRECTION OUTPUT ;
    USE SIGNAL ;
    PORT
      LAYER metal4 ;
        RECT 710.565000 0.000000 710.705000 0.140000 ;
    END
  END mem_req_data[185]
  PIN mem_req_data[184]
    DIRECTION OUTPUT ;
    USE SIGNAL ;
    PORT
      LAYER metal4 ;
        RECT 704.965000 0.000000 705.105000 0.140000 ;
    END
  END mem_req_data[184]
  PIN mem_req_data[183]
    DIRECTION OUTPUT ;
    USE SIGNAL ;
    PORT
      LAYER metal4 ;
        RECT 699.365000 0.000000 699.505000 0.140000 ;
    END
  END mem_req_data[183]
  PIN mem_req_data[182]
    DIRECTION OUTPUT ;
    USE SIGNAL ;
    PORT
      LAYER metal4 ;
        RECT 693.765000 0.000000 693.905000 0.140000 ;
    END
  END mem_req_data[182]
  PIN mem_req_data[181]
    DIRECTION OUTPUT ;
    USE SIGNAL ;
    PORT
      LAYER metal4 ;
        RECT 688.165000 0.000000 688.305000 0.140000 ;
    END
  END mem_req_data[181]
  PIN mem_req_data[180]
    DIRECTION OUTPUT ;
    USE SIGNAL ;
    PORT
      LAYER metal4 ;
        RECT 682.285000 0.000000 682.425000 0.140000 ;
    END
  END mem_req_data[180]
  PIN mem_req_data[179]
    DIRECTION OUTPUT ;
    USE SIGNAL ;
    PORT
      LAYER metal4 ;
        RECT 676.685000 0.000000 676.825000 0.140000 ;
    END
  END mem_req_data[179]
  PIN mem_req_data[178]
    DIRECTION OUTPUT ;
    USE SIGNAL ;
    PORT
      LAYER metal4 ;
        RECT 671.085000 0.000000 671.225000 0.140000 ;
    END
  END mem_req_data[178]
  PIN mem_req_data[177]
    DIRECTION OUTPUT ;
    USE SIGNAL ;
    PORT
      LAYER metal4 ;
        RECT 665.485000 0.000000 665.625000 0.140000 ;
    END
  END mem_req_data[177]
  PIN mem_req_data[176]
    DIRECTION OUTPUT ;
    USE SIGNAL ;
    PORT
      LAYER metal4 ;
        RECT 659.885000 0.000000 660.025000 0.140000 ;
    END
  END mem_req_data[176]
  PIN mem_req_data[175]
    DIRECTION OUTPUT ;
    USE SIGNAL ;
    PORT
      LAYER metal4 ;
        RECT 654.285000 0.000000 654.425000 0.140000 ;
    END
  END mem_req_data[175]
  PIN mem_req_data[174]
    DIRECTION OUTPUT ;
    USE SIGNAL ;
    PORT
      LAYER metal4 ;
        RECT 648.685000 0.000000 648.825000 0.140000 ;
    END
  END mem_req_data[174]
  PIN mem_req_data[173]
    DIRECTION OUTPUT ;
    USE SIGNAL ;
    PORT
      LAYER metal4 ;
        RECT 643.085000 0.000000 643.225000 0.140000 ;
    END
  END mem_req_data[173]
  PIN mem_req_data[172]
    DIRECTION OUTPUT ;
    USE SIGNAL ;
    PORT
      LAYER metal4 ;
        RECT 637.205000 0.000000 637.345000 0.140000 ;
    END
  END mem_req_data[172]
  PIN mem_req_data[171]
    DIRECTION OUTPUT ;
    USE SIGNAL ;
    PORT
      LAYER metal4 ;
        RECT 631.605000 0.000000 631.745000 0.140000 ;
    END
  END mem_req_data[171]
  PIN mem_req_data[170]
    DIRECTION OUTPUT ;
    USE SIGNAL ;
    PORT
      LAYER metal4 ;
        RECT 626.005000 0.000000 626.145000 0.140000 ;
    END
  END mem_req_data[170]
  PIN mem_req_data[169]
    DIRECTION OUTPUT ;
    USE SIGNAL ;
    PORT
      LAYER metal4 ;
        RECT 620.405000 0.000000 620.545000 0.140000 ;
    END
  END mem_req_data[169]
  PIN mem_req_data[168]
    DIRECTION OUTPUT ;
    USE SIGNAL ;
    PORT
      LAYER metal4 ;
        RECT 614.805000 0.000000 614.945000 0.140000 ;
    END
  END mem_req_data[168]
  PIN mem_req_data[167]
    DIRECTION OUTPUT ;
    USE SIGNAL ;
    PORT
      LAYER metal4 ;
        RECT 609.205000 0.000000 609.345000 0.140000 ;
    END
  END mem_req_data[167]
  PIN mem_req_data[166]
    DIRECTION OUTPUT ;
    USE SIGNAL ;
    PORT
      LAYER metal4 ;
        RECT 603.605000 0.000000 603.745000 0.140000 ;
    END
  END mem_req_data[166]
  PIN mem_req_data[165]
    DIRECTION OUTPUT ;
    USE SIGNAL ;
    PORT
      LAYER metal4 ;
        RECT 598.005000 0.000000 598.145000 0.140000 ;
    END
  END mem_req_data[165]
  PIN mem_req_data[164]
    DIRECTION OUTPUT ;
    USE SIGNAL ;
    PORT
      LAYER metal4 ;
        RECT 592.125000 0.000000 592.265000 0.140000 ;
    END
  END mem_req_data[164]
  PIN mem_req_data[163]
    DIRECTION OUTPUT ;
    USE SIGNAL ;
    PORT
      LAYER metal4 ;
        RECT 586.525000 0.000000 586.665000 0.140000 ;
    END
  END mem_req_data[163]
  PIN mem_req_data[162]
    DIRECTION OUTPUT ;
    USE SIGNAL ;
    PORT
      LAYER metal4 ;
        RECT 580.925000 0.000000 581.065000 0.140000 ;
    END
  END mem_req_data[162]
  PIN mem_req_data[161]
    DIRECTION OUTPUT ;
    USE SIGNAL ;
    PORT
      LAYER metal4 ;
        RECT 575.325000 0.000000 575.465000 0.140000 ;
    END
  END mem_req_data[161]
  PIN mem_req_data[160]
    DIRECTION OUTPUT ;
    USE SIGNAL ;
    PORT
      LAYER metal4 ;
        RECT 569.725000 0.000000 569.865000 0.140000 ;
    END
  END mem_req_data[160]
  PIN mem_req_data[159]
    DIRECTION OUTPUT ;
    USE SIGNAL ;
    PORT
      LAYER metal4 ;
        RECT 564.125000 0.000000 564.265000 0.140000 ;
    END
  END mem_req_data[159]
  PIN mem_req_data[158]
    DIRECTION OUTPUT ;
    USE SIGNAL ;
    PORT
      LAYER metal4 ;
        RECT 558.525000 0.000000 558.665000 0.140000 ;
    END
  END mem_req_data[158]
  PIN mem_req_data[157]
    DIRECTION OUTPUT ;
    USE SIGNAL ;
    PORT
      LAYER metal4 ;
        RECT 552.645000 0.000000 552.785000 0.140000 ;
    END
  END mem_req_data[157]
  PIN mem_req_data[156]
    DIRECTION OUTPUT ;
    USE SIGNAL ;
    PORT
      LAYER metal4 ;
        RECT 547.045000 0.000000 547.185000 0.140000 ;
    END
  END mem_req_data[156]
  PIN mem_req_data[155]
    DIRECTION OUTPUT ;
    USE SIGNAL ;
    PORT
      LAYER metal4 ;
        RECT 541.445000 0.000000 541.585000 0.140000 ;
    END
  END mem_req_data[155]
  PIN mem_req_data[154]
    DIRECTION OUTPUT ;
    USE SIGNAL ;
    PORT
      LAYER metal4 ;
        RECT 535.845000 0.000000 535.985000 0.140000 ;
    END
  END mem_req_data[154]
  PIN mem_req_data[153]
    DIRECTION OUTPUT ;
    USE SIGNAL ;
    PORT
      LAYER metal4 ;
        RECT 530.245000 0.000000 530.385000 0.140000 ;
    END
  END mem_req_data[153]
  PIN mem_req_data[152]
    DIRECTION OUTPUT ;
    USE SIGNAL ;
    PORT
      LAYER metal4 ;
        RECT 524.645000 0.000000 524.785000 0.140000 ;
    END
  END mem_req_data[152]
  PIN mem_req_data[151]
    DIRECTION OUTPUT ;
    USE SIGNAL ;
    PORT
      LAYER metal4 ;
        RECT 519.045000 0.000000 519.185000 0.140000 ;
    END
  END mem_req_data[151]
  PIN mem_req_data[150]
    DIRECTION OUTPUT ;
    USE SIGNAL ;
    PORT
      LAYER metal4 ;
        RECT 513.445000 0.000000 513.585000 0.140000 ;
    END
  END mem_req_data[150]
  PIN mem_req_data[149]
    DIRECTION OUTPUT ;
    USE SIGNAL ;
    PORT
      LAYER metal4 ;
        RECT 507.565000 0.000000 507.705000 0.140000 ;
    END
  END mem_req_data[149]
  PIN mem_req_data[148]
    DIRECTION OUTPUT ;
    USE SIGNAL ;
    PORT
      LAYER metal4 ;
        RECT 501.965000 0.000000 502.105000 0.140000 ;
    END
  END mem_req_data[148]
  PIN mem_req_data[147]
    DIRECTION OUTPUT ;
    USE SIGNAL ;
    PORT
      LAYER metal4 ;
        RECT 496.365000 0.000000 496.505000 0.140000 ;
    END
  END mem_req_data[147]
  PIN mem_req_data[146]
    DIRECTION OUTPUT ;
    USE SIGNAL ;
    PORT
      LAYER metal4 ;
        RECT 490.765000 0.000000 490.905000 0.140000 ;
    END
  END mem_req_data[146]
  PIN mem_req_data[145]
    DIRECTION OUTPUT ;
    USE SIGNAL ;
    PORT
      LAYER metal4 ;
        RECT 485.165000 0.000000 485.305000 0.140000 ;
    END
  END mem_req_data[145]
  PIN mem_req_data[144]
    DIRECTION OUTPUT ;
    USE SIGNAL ;
    PORT
      LAYER metal4 ;
        RECT 479.565000 0.000000 479.705000 0.140000 ;
    END
  END mem_req_data[144]
  PIN mem_req_data[143]
    DIRECTION OUTPUT ;
    USE SIGNAL ;
    PORT
      LAYER metal4 ;
        RECT 473.965000 0.000000 474.105000 0.140000 ;
    END
  END mem_req_data[143]
  PIN mem_req_data[142]
    DIRECTION OUTPUT ;
    USE SIGNAL ;
    PORT
      LAYER metal4 ;
        RECT 468.085000 0.000000 468.225000 0.140000 ;
    END
  END mem_req_data[142]
  PIN mem_req_data[141]
    DIRECTION OUTPUT ;
    USE SIGNAL ;
    PORT
      LAYER metal4 ;
        RECT 462.485000 0.000000 462.625000 0.140000 ;
    END
  END mem_req_data[141]
  PIN mem_req_data[140]
    DIRECTION OUTPUT ;
    USE SIGNAL ;
    PORT
      LAYER metal4 ;
        RECT 456.885000 0.000000 457.025000 0.140000 ;
    END
  END mem_req_data[140]
  PIN mem_req_data[139]
    DIRECTION OUTPUT ;
    USE SIGNAL ;
    PORT
      LAYER metal4 ;
        RECT 451.285000 0.000000 451.425000 0.140000 ;
    END
  END mem_req_data[139]
  PIN mem_req_data[138]
    DIRECTION OUTPUT ;
    USE SIGNAL ;
    PORT
      LAYER metal4 ;
        RECT 445.685000 0.000000 445.825000 0.140000 ;
    END
  END mem_req_data[138]
  PIN mem_req_data[137]
    DIRECTION OUTPUT ;
    USE SIGNAL ;
    PORT
      LAYER metal4 ;
        RECT 440.085000 0.000000 440.225000 0.140000 ;
    END
  END mem_req_data[137]
  PIN mem_req_data[136]
    DIRECTION OUTPUT ;
    USE SIGNAL ;
    PORT
      LAYER metal4 ;
        RECT 434.485000 0.000000 434.625000 0.140000 ;
    END
  END mem_req_data[136]
  PIN mem_req_data[135]
    DIRECTION OUTPUT ;
    USE SIGNAL ;
    PORT
      LAYER metal4 ;
        RECT 428.885000 0.000000 429.025000 0.140000 ;
    END
  END mem_req_data[135]
  PIN mem_req_data[134]
    DIRECTION OUTPUT ;
    USE SIGNAL ;
    PORT
      LAYER metal4 ;
        RECT 423.005000 0.000000 423.145000 0.140000 ;
    END
  END mem_req_data[134]
  PIN mem_req_data[133]
    DIRECTION OUTPUT ;
    USE SIGNAL ;
    PORT
      LAYER metal4 ;
        RECT 417.405000 0.000000 417.545000 0.140000 ;
    END
  END mem_req_data[133]
  PIN mem_req_data[132]
    DIRECTION OUTPUT ;
    USE SIGNAL ;
    PORT
      LAYER metal4 ;
        RECT 411.805000 0.000000 411.945000 0.140000 ;
    END
  END mem_req_data[132]
  PIN mem_req_data[131]
    DIRECTION OUTPUT ;
    USE SIGNAL ;
    PORT
      LAYER metal4 ;
        RECT 406.205000 0.000000 406.345000 0.140000 ;
    END
  END mem_req_data[131]
  PIN mem_req_data[130]
    DIRECTION OUTPUT ;
    USE SIGNAL ;
    PORT
      LAYER metal4 ;
        RECT 400.605000 0.000000 400.745000 0.140000 ;
    END
  END mem_req_data[130]
  PIN mem_req_data[129]
    DIRECTION OUTPUT ;
    USE SIGNAL ;
    PORT
      LAYER metal4 ;
        RECT 395.005000 0.000000 395.145000 0.140000 ;
    END
  END mem_req_data[129]
  PIN mem_req_data[128]
    DIRECTION OUTPUT ;
    USE SIGNAL ;
    PORT
      LAYER metal4 ;
        RECT 389.405000 0.000000 389.545000 0.140000 ;
    END
  END mem_req_data[128]
  PIN mem_req_data[127]
    DIRECTION OUTPUT ;
    USE SIGNAL ;
    PORT
      LAYER metal4 ;
        RECT 383.525000 0.000000 383.665000 0.140000 ;
    END
  END mem_req_data[127]
  PIN mem_req_data[126]
    DIRECTION OUTPUT ;
    USE SIGNAL ;
    PORT
      LAYER metal4 ;
        RECT 377.925000 0.000000 378.065000 0.140000 ;
    END
  END mem_req_data[126]
  PIN mem_req_data[125]
    DIRECTION OUTPUT ;
    USE SIGNAL ;
    PORT
      LAYER metal4 ;
        RECT 372.325000 0.000000 372.465000 0.140000 ;
    END
  END mem_req_data[125]
  PIN mem_req_data[124]
    DIRECTION OUTPUT ;
    USE SIGNAL ;
    PORT
      LAYER metal4 ;
        RECT 366.725000 0.000000 366.865000 0.140000 ;
    END
  END mem_req_data[124]
  PIN mem_req_data[123]
    DIRECTION OUTPUT ;
    USE SIGNAL ;
    PORT
      LAYER metal4 ;
        RECT 361.125000 0.000000 361.265000 0.140000 ;
    END
  END mem_req_data[123]
  PIN mem_req_data[122]
    DIRECTION OUTPUT ;
    USE SIGNAL ;
    PORT
      LAYER metal4 ;
        RECT 355.525000 0.000000 355.665000 0.140000 ;
    END
  END mem_req_data[122]
  PIN mem_req_data[121]
    DIRECTION OUTPUT ;
    USE SIGNAL ;
    PORT
      LAYER metal4 ;
        RECT 349.925000 0.000000 350.065000 0.140000 ;
    END
  END mem_req_data[121]
  PIN mem_req_data[120]
    DIRECTION OUTPUT ;
    USE SIGNAL ;
    PORT
      LAYER metal4 ;
        RECT 344.325000 0.000000 344.465000 0.140000 ;
    END
  END mem_req_data[120]
  PIN mem_req_data[119]
    DIRECTION OUTPUT ;
    USE SIGNAL ;
    PORT
      LAYER metal4 ;
        RECT 338.445000 0.000000 338.585000 0.140000 ;
    END
  END mem_req_data[119]
  PIN mem_req_data[118]
    DIRECTION OUTPUT ;
    USE SIGNAL ;
    PORT
      LAYER metal4 ;
        RECT 332.845000 0.000000 332.985000 0.140000 ;
    END
  END mem_req_data[118]
  PIN mem_req_data[117]
    DIRECTION OUTPUT ;
    USE SIGNAL ;
    PORT
      LAYER metal4 ;
        RECT 327.245000 0.000000 327.385000 0.140000 ;
    END
  END mem_req_data[117]
  PIN mem_req_data[116]
    DIRECTION OUTPUT ;
    USE SIGNAL ;
    PORT
      LAYER metal4 ;
        RECT 321.645000 0.000000 321.785000 0.140000 ;
    END
  END mem_req_data[116]
  PIN mem_req_data[115]
    DIRECTION OUTPUT ;
    USE SIGNAL ;
    PORT
      LAYER metal4 ;
        RECT 316.045000 0.000000 316.185000 0.140000 ;
    END
  END mem_req_data[115]
  PIN mem_req_data[114]
    DIRECTION OUTPUT ;
    USE SIGNAL ;
    PORT
      LAYER metal4 ;
        RECT 310.445000 0.000000 310.585000 0.140000 ;
    END
  END mem_req_data[114]
  PIN mem_req_data[113]
    DIRECTION OUTPUT ;
    USE SIGNAL ;
    PORT
      LAYER metal4 ;
        RECT 304.845000 0.000000 304.985000 0.140000 ;
    END
  END mem_req_data[113]
  PIN mem_req_data[112]
    DIRECTION OUTPUT ;
    USE SIGNAL ;
    PORT
      LAYER metal4 ;
        RECT 299.245000 0.000000 299.385000 0.140000 ;
    END
  END mem_req_data[112]
  PIN mem_req_data[111]
    DIRECTION OUTPUT ;
    USE SIGNAL ;
    PORT
      LAYER metal4 ;
        RECT 293.365000 0.000000 293.505000 0.140000 ;
    END
  END mem_req_data[111]
  PIN mem_req_data[110]
    DIRECTION OUTPUT ;
    USE SIGNAL ;
    PORT
      LAYER metal4 ;
        RECT 287.765000 0.000000 287.905000 0.140000 ;
    END
  END mem_req_data[110]
  PIN mem_req_data[109]
    DIRECTION OUTPUT ;
    USE SIGNAL ;
    PORT
      LAYER metal4 ;
        RECT 282.165000 0.000000 282.305000 0.140000 ;
    END
  END mem_req_data[109]
  PIN mem_req_data[108]
    DIRECTION OUTPUT ;
    USE SIGNAL ;
    PORT
      LAYER metal4 ;
        RECT 276.565000 0.000000 276.705000 0.140000 ;
    END
  END mem_req_data[108]
  PIN mem_req_data[107]
    DIRECTION OUTPUT ;
    USE SIGNAL ;
    PORT
      LAYER metal4 ;
        RECT 270.965000 0.000000 271.105000 0.140000 ;
    END
  END mem_req_data[107]
  PIN mem_req_data[106]
    DIRECTION OUTPUT ;
    USE SIGNAL ;
    PORT
      LAYER metal4 ;
        RECT 265.365000 0.000000 265.505000 0.140000 ;
    END
  END mem_req_data[106]
  PIN mem_req_data[105]
    DIRECTION OUTPUT ;
    USE SIGNAL ;
    PORT
      LAYER metal4 ;
        RECT 259.765000 0.000000 259.905000 0.140000 ;
    END
  END mem_req_data[105]
  PIN mem_req_data[104]
    DIRECTION OUTPUT ;
    USE SIGNAL ;
    PORT
      LAYER metal4 ;
        RECT 253.885000 0.000000 254.025000 0.140000 ;
    END
  END mem_req_data[104]
  PIN mem_req_data[103]
    DIRECTION OUTPUT ;
    USE SIGNAL ;
    PORT
      LAYER metal4 ;
        RECT 248.285000 0.000000 248.425000 0.140000 ;
    END
  END mem_req_data[103]
  PIN mem_req_data[102]
    DIRECTION OUTPUT ;
    USE SIGNAL ;
    PORT
      LAYER metal4 ;
        RECT 242.685000 0.000000 242.825000 0.140000 ;
    END
  END mem_req_data[102]
  PIN mem_req_data[101]
    DIRECTION OUTPUT ;
    USE SIGNAL ;
    PORT
      LAYER metal4 ;
        RECT 237.085000 0.000000 237.225000 0.140000 ;
    END
  END mem_req_data[101]
  PIN mem_req_data[100]
    DIRECTION OUTPUT ;
    USE SIGNAL ;
    PORT
      LAYER metal4 ;
        RECT 231.485000 0.000000 231.625000 0.140000 ;
    END
  END mem_req_data[100]
  PIN mem_req_data[99]
    DIRECTION OUTPUT ;
    USE SIGNAL ;
    PORT
      LAYER metal4 ;
        RECT 225.885000 0.000000 226.025000 0.140000 ;
    END
  END mem_req_data[99]
  PIN mem_req_data[98]
    DIRECTION OUTPUT ;
    USE SIGNAL ;
    PORT
      LAYER metal4 ;
        RECT 220.285000 0.000000 220.425000 0.140000 ;
    END
  END mem_req_data[98]
  PIN mem_req_data[97]
    DIRECTION OUTPUT ;
    USE SIGNAL ;
    PORT
      LAYER metal4 ;
        RECT 214.685000 0.000000 214.825000 0.140000 ;
    END
  END mem_req_data[97]
  PIN mem_req_data[96]
    DIRECTION OUTPUT ;
    USE SIGNAL ;
    PORT
      LAYER metal4 ;
        RECT 208.805000 0.000000 208.945000 0.140000 ;
    END
  END mem_req_data[96]
  PIN mem_req_data[95]
    DIRECTION OUTPUT ;
    USE SIGNAL ;
    PORT
      LAYER metal4 ;
        RECT 203.205000 0.000000 203.345000 0.140000 ;
    END
  END mem_req_data[95]
  PIN mem_req_data[94]
    DIRECTION OUTPUT ;
    USE SIGNAL ;
    PORT
      LAYER metal4 ;
        RECT 197.605000 0.000000 197.745000 0.140000 ;
    END
  END mem_req_data[94]
  PIN mem_req_data[93]
    DIRECTION OUTPUT ;
    USE SIGNAL ;
    PORT
      LAYER metal4 ;
        RECT 192.005000 0.000000 192.145000 0.140000 ;
    END
  END mem_req_data[93]
  PIN mem_req_data[92]
    DIRECTION OUTPUT ;
    USE SIGNAL ;
    PORT
      LAYER metal4 ;
        RECT 186.405000 0.000000 186.545000 0.140000 ;
    END
  END mem_req_data[92]
  PIN mem_req_data[91]
    DIRECTION OUTPUT ;
    USE SIGNAL ;
    PORT
      LAYER metal4 ;
        RECT 180.805000 0.000000 180.945000 0.140000 ;
    END
  END mem_req_data[91]
  PIN mem_req_data[90]
    DIRECTION OUTPUT ;
    USE SIGNAL ;
    PORT
      LAYER metal4 ;
        RECT 175.205000 0.000000 175.345000 0.140000 ;
    END
  END mem_req_data[90]
  PIN mem_req_data[89]
    DIRECTION OUTPUT ;
    USE SIGNAL ;
    PORT
      LAYER metal4 ;
        RECT 169.325000 0.000000 169.465000 0.140000 ;
    END
  END mem_req_data[89]
  PIN mem_req_data[88]
    DIRECTION OUTPUT ;
    USE SIGNAL ;
    PORT
      LAYER metal4 ;
        RECT 163.725000 0.000000 163.865000 0.140000 ;
    END
  END mem_req_data[88]
  PIN mem_req_data[87]
    DIRECTION OUTPUT ;
    USE SIGNAL ;
    PORT
      LAYER metal4 ;
        RECT 158.125000 0.000000 158.265000 0.140000 ;
    END
  END mem_req_data[87]
  PIN mem_req_data[86]
    DIRECTION OUTPUT ;
    USE SIGNAL ;
    PORT
      LAYER metal4 ;
        RECT 152.525000 0.000000 152.665000 0.140000 ;
    END
  END mem_req_data[86]
  PIN mem_req_data[85]
    DIRECTION OUTPUT ;
    USE SIGNAL ;
    PORT
      LAYER metal4 ;
        RECT 146.925000 0.000000 147.065000 0.140000 ;
    END
  END mem_req_data[85]
  PIN mem_req_data[84]
    DIRECTION OUTPUT ;
    USE SIGNAL ;
    PORT
      LAYER metal4 ;
        RECT 141.325000 0.000000 141.465000 0.140000 ;
    END
  END mem_req_data[84]
  PIN mem_req_data[83]
    DIRECTION OUTPUT ;
    USE SIGNAL ;
    PORT
      LAYER metal4 ;
        RECT 135.725000 0.000000 135.865000 0.140000 ;
    END
  END mem_req_data[83]
  PIN mem_req_data[82]
    DIRECTION OUTPUT ;
    USE SIGNAL ;
    PORT
      LAYER metal4 ;
        RECT 130.125000 0.000000 130.265000 0.140000 ;
    END
  END mem_req_data[82]
  PIN mem_req_data[81]
    DIRECTION OUTPUT ;
    USE SIGNAL ;
    PORT
      LAYER metal4 ;
        RECT 124.245000 0.000000 124.385000 0.140000 ;
    END
  END mem_req_data[81]
  PIN mem_req_data[80]
    DIRECTION OUTPUT ;
    USE SIGNAL ;
    PORT
      LAYER metal4 ;
        RECT 118.645000 0.000000 118.785000 0.140000 ;
    END
  END mem_req_data[80]
  PIN mem_req_data[79]
    DIRECTION OUTPUT ;
    USE SIGNAL ;
    PORT
      LAYER metal4 ;
        RECT 113.045000 0.000000 113.185000 0.140000 ;
    END
  END mem_req_data[79]
  PIN mem_req_data[78]
    DIRECTION OUTPUT ;
    USE SIGNAL ;
    PORT
      LAYER metal4 ;
        RECT 107.445000 0.000000 107.585000 0.140000 ;
    END
  END mem_req_data[78]
  PIN mem_req_data[77]
    DIRECTION OUTPUT ;
    USE SIGNAL ;
    PORT
      LAYER metal4 ;
        RECT 101.845000 0.000000 101.985000 0.140000 ;
    END
  END mem_req_data[77]
  PIN mem_req_data[76]
    DIRECTION OUTPUT ;
    USE SIGNAL ;
    PORT
      LAYER metal4 ;
        RECT 96.245000 0.000000 96.385000 0.140000 ;
    END
  END mem_req_data[76]
  PIN mem_req_data[75]
    DIRECTION OUTPUT ;
    USE SIGNAL ;
    PORT
      LAYER metal4 ;
        RECT 90.645000 0.000000 90.785000 0.140000 ;
    END
  END mem_req_data[75]
  PIN mem_req_data[74]
    DIRECTION OUTPUT ;
    USE SIGNAL ;
    PORT
      LAYER metal4 ;
        RECT 84.765000 0.000000 84.905000 0.140000 ;
    END
  END mem_req_data[74]
  PIN mem_req_data[73]
    DIRECTION OUTPUT ;
    USE SIGNAL ;
    PORT
      LAYER metal4 ;
        RECT 79.165000 0.000000 79.305000 0.140000 ;
    END
  END mem_req_data[73]
  PIN mem_req_data[72]
    DIRECTION OUTPUT ;
    USE SIGNAL ;
    PORT
      LAYER metal4 ;
        RECT 73.565000 0.000000 73.705000 0.140000 ;
    END
  END mem_req_data[72]
  PIN mem_req_data[71]
    DIRECTION OUTPUT ;
    USE SIGNAL ;
    PORT
      LAYER metal4 ;
        RECT 67.965000 0.000000 68.105000 0.140000 ;
    END
  END mem_req_data[71]
  PIN mem_req_data[70]
    DIRECTION OUTPUT ;
    USE SIGNAL ;
    PORT
      LAYER metal4 ;
        RECT 62.365000 0.000000 62.505000 0.140000 ;
    END
  END mem_req_data[70]
  PIN mem_req_data[69]
    DIRECTION OUTPUT ;
    USE SIGNAL ;
    PORT
      LAYER metal4 ;
        RECT 56.765000 0.000000 56.905000 0.140000 ;
    END
  END mem_req_data[69]
  PIN mem_req_data[68]
    DIRECTION OUTPUT ;
    USE SIGNAL ;
    PORT
      LAYER metal4 ;
        RECT 51.165000 0.000000 51.305000 0.140000 ;
    END
  END mem_req_data[68]
  PIN mem_req_data[67]
    DIRECTION OUTPUT ;
    USE SIGNAL ;
    PORT
      LAYER metal4 ;
        RECT 45.565000 0.000000 45.705000 0.140000 ;
    END
  END mem_req_data[67]
  PIN mem_req_data[66]
    DIRECTION OUTPUT ;
    USE SIGNAL ;
    PORT
      LAYER metal4 ;
        RECT 39.685000 0.000000 39.825000 0.140000 ;
    END
  END mem_req_data[66]
  PIN mem_req_data[65]
    DIRECTION OUTPUT ;
    USE SIGNAL ;
    PORT
      LAYER metal4 ;
        RECT 34.085000 0.000000 34.225000 0.140000 ;
    END
  END mem_req_data[65]
  PIN mem_req_data[64]
    DIRECTION OUTPUT ;
    USE SIGNAL ;
    PORT
      LAYER metal4 ;
        RECT 28.485000 0.000000 28.625000 0.140000 ;
    END
  END mem_req_data[64]
  PIN mem_req_data[63]
    DIRECTION OUTPUT ;
    USE SIGNAL ;
    PORT
      LAYER metal4 ;
        RECT 22.885000 0.000000 23.025000 0.140000 ;
    END
  END mem_req_data[63]
  PIN mem_req_data[62]
    DIRECTION OUTPUT ;
    USE SIGNAL ;
    PORT
      LAYER metal4 ;
        RECT 17.285000 0.000000 17.425000 0.140000 ;
    END
  END mem_req_data[62]
  PIN mem_req_data[61]
    DIRECTION OUTPUT ;
    USE SIGNAL ;
    PORT
      LAYER metal4 ;
        RECT 11.685000 0.000000 11.825000 0.140000 ;
    END
  END mem_req_data[61]
  PIN mem_req_data[60]
    DIRECTION OUTPUT ;
    USE SIGNAL ;
    PORT
      LAYER metal4 ;
        RECT 6.085000 0.000000 6.225000 0.140000 ;
    END
  END mem_req_data[60]
  PIN mem_req_data[59]
    DIRECTION OUTPUT ;
    USE SIGNAL ;
    PORT
      LAYER metal4 ;
        RECT 0.485000 0.000000 0.625000 0.140000 ;
    END
  END mem_req_data[59]
  PIN mem_req_data[58]
    DIRECTION OUTPUT ;
    USE SIGNAL ;
    PORT
      LAYER metal5 ;
        RECT 1663.310000 1663.480000 1663.450000 1663.620000 ;
    END
  END mem_req_data[58]
  PIN mem_req_data[57]
    DIRECTION OUTPUT ;
    USE SIGNAL ;
    PORT
      LAYER metal5 ;
        RECT 1663.310000 1657.880000 1663.450000 1658.020000 ;
    END
  END mem_req_data[57]
  PIN mem_req_data[56]
    DIRECTION OUTPUT ;
    USE SIGNAL ;
    PORT
      LAYER metal5 ;
        RECT 1663.310000 1652.280000 1663.450000 1652.420000 ;
    END
  END mem_req_data[56]
  PIN mem_req_data[55]
    DIRECTION OUTPUT ;
    USE SIGNAL ;
    PORT
      LAYER metal5 ;
        RECT 1663.310000 1646.680000 1663.450000 1646.820000 ;
    END
  END mem_req_data[55]
  PIN mem_req_data[54]
    DIRECTION OUTPUT ;
    USE SIGNAL ;
    PORT
      LAYER metal5 ;
        RECT 1663.310000 1641.080000 1663.450000 1641.220000 ;
    END
  END mem_req_data[54]
  PIN mem_req_data[53]
    DIRECTION OUTPUT ;
    USE SIGNAL ;
    PORT
      LAYER metal5 ;
        RECT 1663.310000 1635.480000 1663.450000 1635.620000 ;
    END
  END mem_req_data[53]
  PIN mem_req_data[52]
    DIRECTION OUTPUT ;
    USE SIGNAL ;
    PORT
      LAYER metal5 ;
        RECT 1663.310000 1629.880000 1663.450000 1630.020000 ;
    END
  END mem_req_data[52]
  PIN mem_req_data[51]
    DIRECTION OUTPUT ;
    USE SIGNAL ;
    PORT
      LAYER metal5 ;
        RECT 1663.310000 1624.280000 1663.450000 1624.420000 ;
    END
  END mem_req_data[51]
  PIN mem_req_data[50]
    DIRECTION OUTPUT ;
    USE SIGNAL ;
    PORT
      LAYER metal5 ;
        RECT 1663.310000 1618.400000 1663.450000 1618.540000 ;
    END
  END mem_req_data[50]
  PIN mem_req_data[49]
    DIRECTION OUTPUT ;
    USE SIGNAL ;
    PORT
      LAYER metal5 ;
        RECT 1663.310000 1612.800000 1663.450000 1612.940000 ;
    END
  END mem_req_data[49]
  PIN mem_req_data[48]
    DIRECTION OUTPUT ;
    USE SIGNAL ;
    PORT
      LAYER metal5 ;
        RECT 1663.310000 1607.200000 1663.450000 1607.340000 ;
    END
  END mem_req_data[48]
  PIN mem_req_data[47]
    DIRECTION OUTPUT ;
    USE SIGNAL ;
    PORT
      LAYER metal5 ;
        RECT 1663.310000 1601.600000 1663.450000 1601.740000 ;
    END
  END mem_req_data[47]
  PIN mem_req_data[46]
    DIRECTION OUTPUT ;
    USE SIGNAL ;
    PORT
      LAYER metal5 ;
        RECT 1663.310000 1596.000000 1663.450000 1596.140000 ;
    END
  END mem_req_data[46]
  PIN mem_req_data[45]
    DIRECTION OUTPUT ;
    USE SIGNAL ;
    PORT
      LAYER metal5 ;
        RECT 1663.310000 1590.400000 1663.450000 1590.540000 ;
    END
  END mem_req_data[45]
  PIN mem_req_data[44]
    DIRECTION OUTPUT ;
    USE SIGNAL ;
    PORT
      LAYER metal5 ;
        RECT 1663.310000 1584.800000 1663.450000 1584.940000 ;
    END
  END mem_req_data[44]
  PIN mem_req_data[43]
    DIRECTION OUTPUT ;
    USE SIGNAL ;
    PORT
      LAYER metal5 ;
        RECT 1663.310000 1578.920000 1663.450000 1579.060000 ;
    END
  END mem_req_data[43]
  PIN mem_req_data[42]
    DIRECTION OUTPUT ;
    USE SIGNAL ;
    PORT
      LAYER metal5 ;
        RECT 1663.310000 1573.320000 1663.450000 1573.460000 ;
    END
  END mem_req_data[42]
  PIN mem_req_data[41]
    DIRECTION OUTPUT ;
    USE SIGNAL ;
    PORT
      LAYER metal5 ;
        RECT 1663.310000 1567.720000 1663.450000 1567.860000 ;
    END
  END mem_req_data[41]
  PIN mem_req_data[40]
    DIRECTION OUTPUT ;
    USE SIGNAL ;
    PORT
      LAYER metal5 ;
        RECT 1663.310000 1562.120000 1663.450000 1562.260000 ;
    END
  END mem_req_data[40]
  PIN mem_req_data[39]
    DIRECTION OUTPUT ;
    USE SIGNAL ;
    PORT
      LAYER metal5 ;
        RECT 1663.310000 1556.520000 1663.450000 1556.660000 ;
    END
  END mem_req_data[39]
  PIN mem_req_data[38]
    DIRECTION OUTPUT ;
    USE SIGNAL ;
    PORT
      LAYER metal5 ;
        RECT 1663.310000 1550.920000 1663.450000 1551.060000 ;
    END
  END mem_req_data[38]
  PIN mem_req_data[37]
    DIRECTION OUTPUT ;
    USE SIGNAL ;
    PORT
      LAYER metal5 ;
        RECT 1663.310000 1545.320000 1663.450000 1545.460000 ;
    END
  END mem_req_data[37]
  PIN mem_req_data[36]
    DIRECTION OUTPUT ;
    USE SIGNAL ;
    PORT
      LAYER metal5 ;
        RECT 1663.310000 1539.720000 1663.450000 1539.860000 ;
    END
  END mem_req_data[36]
  PIN mem_req_data[35]
    DIRECTION OUTPUT ;
    USE SIGNAL ;
    PORT
      LAYER metal5 ;
        RECT 1663.310000 1533.840000 1663.450000 1533.980000 ;
    END
  END mem_req_data[35]
  PIN mem_req_data[34]
    DIRECTION OUTPUT ;
    USE SIGNAL ;
    PORT
      LAYER metal5 ;
        RECT 1663.310000 1528.240000 1663.450000 1528.380000 ;
    END
  END mem_req_data[34]
  PIN mem_req_data[33]
    DIRECTION OUTPUT ;
    USE SIGNAL ;
    PORT
      LAYER metal5 ;
        RECT 1663.310000 1522.640000 1663.450000 1522.780000 ;
    END
  END mem_req_data[33]
  PIN mem_req_data[32]
    DIRECTION OUTPUT ;
    USE SIGNAL ;
    PORT
      LAYER metal5 ;
        RECT 1663.310000 1517.040000 1663.450000 1517.180000 ;
    END
  END mem_req_data[32]
  PIN mem_req_data[31]
    DIRECTION OUTPUT ;
    USE SIGNAL ;
    PORT
      LAYER metal5 ;
        RECT 1663.310000 1511.440000 1663.450000 1511.580000 ;
    END
  END mem_req_data[31]
  PIN mem_req_data[30]
    DIRECTION OUTPUT ;
    USE SIGNAL ;
    PORT
      LAYER metal5 ;
        RECT 1663.310000 1505.840000 1663.450000 1505.980000 ;
    END
  END mem_req_data[30]
  PIN mem_req_data[29]
    DIRECTION OUTPUT ;
    USE SIGNAL ;
    PORT
      LAYER metal5 ;
        RECT 1663.310000 1500.240000 1663.450000 1500.380000 ;
    END
  END mem_req_data[29]
  PIN mem_req_data[28]
    DIRECTION OUTPUT ;
    USE SIGNAL ;
    PORT
      LAYER metal5 ;
        RECT 1663.310000 1494.360000 1663.450000 1494.500000 ;
    END
  END mem_req_data[28]
  PIN mem_req_data[27]
    DIRECTION OUTPUT ;
    USE SIGNAL ;
    PORT
      LAYER metal5 ;
        RECT 1663.310000 1488.760000 1663.450000 1488.900000 ;
    END
  END mem_req_data[27]
  PIN mem_req_data[26]
    DIRECTION OUTPUT ;
    USE SIGNAL ;
    PORT
      LAYER metal5 ;
        RECT 1663.310000 1483.160000 1663.450000 1483.300000 ;
    END
  END mem_req_data[26]
  PIN mem_req_data[25]
    DIRECTION OUTPUT ;
    USE SIGNAL ;
    PORT
      LAYER metal5 ;
        RECT 1663.310000 1477.560000 1663.450000 1477.700000 ;
    END
  END mem_req_data[25]
  PIN mem_req_data[24]
    DIRECTION OUTPUT ;
    USE SIGNAL ;
    PORT
      LAYER metal5 ;
        RECT 1663.310000 1471.960000 1663.450000 1472.100000 ;
    END
  END mem_req_data[24]
  PIN mem_req_data[23]
    DIRECTION OUTPUT ;
    USE SIGNAL ;
    PORT
      LAYER metal5 ;
        RECT 1663.310000 1466.360000 1663.450000 1466.500000 ;
    END
  END mem_req_data[23]
  PIN mem_req_data[22]
    DIRECTION OUTPUT ;
    USE SIGNAL ;
    PORT
      LAYER metal5 ;
        RECT 1663.310000 1460.760000 1663.450000 1460.900000 ;
    END
  END mem_req_data[22]
  PIN mem_req_data[21]
    DIRECTION OUTPUT ;
    USE SIGNAL ;
    PORT
      LAYER metal5 ;
        RECT 1663.310000 1454.880000 1663.450000 1455.020000 ;
    END
  END mem_req_data[21]
  PIN mem_req_data[20]
    DIRECTION OUTPUT ;
    USE SIGNAL ;
    PORT
      LAYER metal5 ;
        RECT 1663.310000 1449.280000 1663.450000 1449.420000 ;
    END
  END mem_req_data[20]
  PIN mem_req_data[19]
    DIRECTION OUTPUT ;
    USE SIGNAL ;
    PORT
      LAYER metal5 ;
        RECT 1663.310000 1443.680000 1663.450000 1443.820000 ;
    END
  END mem_req_data[19]
  PIN mem_req_data[18]
    DIRECTION OUTPUT ;
    USE SIGNAL ;
    PORT
      LAYER metal5 ;
        RECT 1663.310000 1438.080000 1663.450000 1438.220000 ;
    END
  END mem_req_data[18]
  PIN mem_req_data[17]
    DIRECTION OUTPUT ;
    USE SIGNAL ;
    PORT
      LAYER metal5 ;
        RECT 1663.310000 1432.480000 1663.450000 1432.620000 ;
    END
  END mem_req_data[17]
  PIN mem_req_data[16]
    DIRECTION OUTPUT ;
    USE SIGNAL ;
    PORT
      LAYER metal5 ;
        RECT 1663.310000 1426.880000 1663.450000 1427.020000 ;
    END
  END mem_req_data[16]
  PIN mem_req_data[15]
    DIRECTION OUTPUT ;
    USE SIGNAL ;
    PORT
      LAYER metal5 ;
        RECT 1663.310000 1421.280000 1663.450000 1421.420000 ;
    END
  END mem_req_data[15]
  PIN mem_req_data[14]
    DIRECTION OUTPUT ;
    USE SIGNAL ;
    PORT
      LAYER metal5 ;
        RECT 1663.310000 1415.680000 1663.450000 1415.820000 ;
    END
  END mem_req_data[14]
  PIN mem_req_data[13]
    DIRECTION OUTPUT ;
    USE SIGNAL ;
    PORT
      LAYER metal5 ;
        RECT 1663.310000 1409.800000 1663.450000 1409.940000 ;
    END
  END mem_req_data[13]
  PIN mem_req_data[12]
    DIRECTION OUTPUT ;
    USE SIGNAL ;
    PORT
      LAYER metal5 ;
        RECT 1663.310000 1404.200000 1663.450000 1404.340000 ;
    END
  END mem_req_data[12]
  PIN mem_req_data[11]
    DIRECTION OUTPUT ;
    USE SIGNAL ;
    PORT
      LAYER metal5 ;
        RECT 1663.310000 1398.600000 1663.450000 1398.740000 ;
    END
  END mem_req_data[11]
  PIN mem_req_data[10]
    DIRECTION OUTPUT ;
    USE SIGNAL ;
    PORT
      LAYER metal5 ;
        RECT 1663.310000 1393.000000 1663.450000 1393.140000 ;
    END
  END mem_req_data[10]
  PIN mem_req_data[9]
    DIRECTION OUTPUT ;
    USE SIGNAL ;
    PORT
      LAYER metal5 ;
        RECT 1663.310000 1387.400000 1663.450000 1387.540000 ;
    END
  END mem_req_data[9]
  PIN mem_req_data[8]
    DIRECTION OUTPUT ;
    USE SIGNAL ;
    PORT
      LAYER metal5 ;
        RECT 1663.310000 1381.800000 1663.450000 1381.940000 ;
    END
  END mem_req_data[8]
  PIN mem_req_data[7]
    DIRECTION OUTPUT ;
    USE SIGNAL ;
    PORT
      LAYER metal5 ;
        RECT 1663.310000 1376.200000 1663.450000 1376.340000 ;
    END
  END mem_req_data[7]
  PIN mem_req_data[6]
    DIRECTION OUTPUT ;
    USE SIGNAL ;
    PORT
      LAYER metal5 ;
        RECT 1663.310000 1370.320000 1663.450000 1370.460000 ;
    END
  END mem_req_data[6]
  PIN mem_req_data[5]
    DIRECTION OUTPUT ;
    USE SIGNAL ;
    PORT
      LAYER metal5 ;
        RECT 1663.310000 1364.720000 1663.450000 1364.860000 ;
    END
  END mem_req_data[5]
  PIN mem_req_data[4]
    DIRECTION OUTPUT ;
    USE SIGNAL ;
    PORT
      LAYER metal5 ;
        RECT 1663.310000 1359.120000 1663.450000 1359.260000 ;
    END
  END mem_req_data[4]
  PIN mem_req_data[3]
    DIRECTION OUTPUT ;
    USE SIGNAL ;
    PORT
      LAYER metal5 ;
        RECT 1663.310000 1353.520000 1663.450000 1353.660000 ;
    END
  END mem_req_data[3]
  PIN mem_req_data[2]
    DIRECTION OUTPUT ;
    USE SIGNAL ;
    PORT
      LAYER metal5 ;
        RECT 1663.310000 1347.920000 1663.450000 1348.060000 ;
    END
  END mem_req_data[2]
  PIN mem_req_data[1]
    DIRECTION OUTPUT ;
    USE SIGNAL ;
    PORT
      LAYER metal5 ;
        RECT 1663.310000 1342.320000 1663.450000 1342.460000 ;
    END
  END mem_req_data[1]
  PIN mem_req_data[0]
    DIRECTION OUTPUT ;
    USE SIGNAL ;
    PORT
      LAYER metal5 ;
        RECT 1663.310000 1336.720000 1663.450000 1336.860000 ;
    END
  END mem_req_data[0]
  PIN mem_req_flags[2]
    DIRECTION OUTPUT ;
    USE SIGNAL ;
    PORT
      LAYER metal5 ;
        RECT 1663.310000 1331.120000 1663.450000 1331.260000 ;
    END
  END mem_req_flags[2]
  PIN mem_req_flags[1]
    DIRECTION OUTPUT ;
    USE SIGNAL ;
    PORT
      LAYER metal5 ;
        RECT 1663.310000 1325.240000 1663.450000 1325.380000 ;
    END
  END mem_req_flags[1]
  PIN mem_req_flags[0]
    DIRECTION OUTPUT ;
    USE SIGNAL ;
    PORT
      LAYER metal5 ;
        RECT 1663.310000 1319.640000 1663.450000 1319.780000 ;
    END
  END mem_req_flags[0]
  PIN mem_req_tag[6]
    DIRECTION OUTPUT ;
    USE SIGNAL ;
    PORT
      LAYER metal5 ;
        RECT 1663.310000 1314.040000 1663.450000 1314.180000 ;
    END
  END mem_req_tag[6]
  PIN mem_req_tag[5]
    DIRECTION OUTPUT ;
    USE SIGNAL ;
    PORT
      LAYER metal5 ;
        RECT 1663.310000 1308.440000 1663.450000 1308.580000 ;
    END
  END mem_req_tag[5]
  PIN mem_req_tag[4]
    DIRECTION OUTPUT ;
    USE SIGNAL ;
    PORT
      LAYER metal5 ;
        RECT 1663.310000 1302.840000 1663.450000 1302.980000 ;
    END
  END mem_req_tag[4]
  PIN mem_req_tag[3]
    DIRECTION OUTPUT ;
    USE SIGNAL ;
    PORT
      LAYER metal5 ;
        RECT 1663.310000 1297.240000 1663.450000 1297.380000 ;
    END
  END mem_req_tag[3]
  PIN mem_req_tag[2]
    DIRECTION OUTPUT ;
    USE SIGNAL ;
    PORT
      LAYER metal5 ;
        RECT 1663.310000 1291.640000 1663.450000 1291.780000 ;
    END
  END mem_req_tag[2]
  PIN mem_req_tag[1]
    DIRECTION OUTPUT ;
    USE SIGNAL ;
    PORT
      LAYER metal5 ;
        RECT 1663.310000 1285.760000 1663.450000 1285.900000 ;
    END
  END mem_req_tag[1]
  PIN mem_req_tag[0]
    DIRECTION OUTPUT ;
    USE SIGNAL ;
    PORT
      LAYER metal5 ;
        RECT 1663.310000 1280.160000 1663.450000 1280.300000 ;
    END
  END mem_req_tag[0]
  PIN mem_req_ready[0]
    DIRECTION INPUT ;
    USE SIGNAL ;
    PORT
      LAYER metal5 ;
        RECT 1663.310000 1274.560000 1663.450000 1274.700000 ;
    END
  END mem_req_ready[0]
  PIN mem_rsp_valid[0]
    DIRECTION INPUT ;
    USE SIGNAL ;
    PORT
      LAYER metal5 ;
        RECT 1663.310000 1268.960000 1663.450000 1269.100000 ;
    END
  END mem_rsp_valid[0]
  PIN mem_rsp_data[511]
    DIRECTION INPUT ;
    USE SIGNAL ;
    PORT
      LAYER metal5 ;
        RECT 1663.310000 1263.360000 1663.450000 1263.500000 ;
    END
  END mem_rsp_data[511]
  PIN mem_rsp_data[510]
    DIRECTION INPUT ;
    USE SIGNAL ;
    PORT
      LAYER metal5 ;
        RECT 1663.310000 1257.760000 1663.450000 1257.900000 ;
    END
  END mem_rsp_data[510]
  PIN mem_rsp_data[509]
    DIRECTION INPUT ;
    USE SIGNAL ;
    PORT
      LAYER metal5 ;
        RECT 1663.310000 1252.160000 1663.450000 1252.300000 ;
    END
  END mem_rsp_data[509]
  PIN mem_rsp_data[508]
    DIRECTION INPUT ;
    USE SIGNAL ;
    PORT
      LAYER metal5 ;
        RECT 1663.310000 1246.280000 1663.450000 1246.420000 ;
    END
  END mem_rsp_data[508]
  PIN mem_rsp_data[507]
    DIRECTION INPUT ;
    USE SIGNAL ;
    PORT
      LAYER metal5 ;
        RECT 1663.310000 1240.680000 1663.450000 1240.820000 ;
    END
  END mem_rsp_data[507]
  PIN mem_rsp_data[506]
    DIRECTION INPUT ;
    USE SIGNAL ;
    PORT
      LAYER metal5 ;
        RECT 1663.310000 1235.080000 1663.450000 1235.220000 ;
    END
  END mem_rsp_data[506]
  PIN mem_rsp_data[505]
    DIRECTION INPUT ;
    USE SIGNAL ;
    PORT
      LAYER metal5 ;
        RECT 1663.310000 1229.480000 1663.450000 1229.620000 ;
    END
  END mem_rsp_data[505]
  PIN mem_rsp_data[504]
    DIRECTION INPUT ;
    USE SIGNAL ;
    PORT
      LAYER metal5 ;
        RECT 1663.310000 1223.880000 1663.450000 1224.020000 ;
    END
  END mem_rsp_data[504]
  PIN mem_rsp_data[503]
    DIRECTION INPUT ;
    USE SIGNAL ;
    PORT
      LAYER metal5 ;
        RECT 1663.310000 1218.280000 1663.450000 1218.420000 ;
    END
  END mem_rsp_data[503]
  PIN mem_rsp_data[502]
    DIRECTION INPUT ;
    USE SIGNAL ;
    PORT
      LAYER metal5 ;
        RECT 1663.310000 1212.680000 1663.450000 1212.820000 ;
    END
  END mem_rsp_data[502]
  PIN mem_rsp_data[501]
    DIRECTION INPUT ;
    USE SIGNAL ;
    PORT
      LAYER metal5 ;
        RECT 1663.310000 1207.080000 1663.450000 1207.220000 ;
    END
  END mem_rsp_data[501]
  PIN mem_rsp_data[500]
    DIRECTION INPUT ;
    USE SIGNAL ;
    PORT
      LAYER metal5 ;
        RECT 1663.310000 1201.200000 1663.450000 1201.340000 ;
    END
  END mem_rsp_data[500]
  PIN mem_rsp_data[499]
    DIRECTION INPUT ;
    USE SIGNAL ;
    PORT
      LAYER metal5 ;
        RECT 1663.310000 1195.600000 1663.450000 1195.740000 ;
    END
  END mem_rsp_data[499]
  PIN mem_rsp_data[498]
    DIRECTION INPUT ;
    USE SIGNAL ;
    PORT
      LAYER metal5 ;
        RECT 1663.310000 1190.000000 1663.450000 1190.140000 ;
    END
  END mem_rsp_data[498]
  PIN mem_rsp_data[497]
    DIRECTION INPUT ;
    USE SIGNAL ;
    PORT
      LAYER metal5 ;
        RECT 1663.310000 1184.400000 1663.450000 1184.540000 ;
    END
  END mem_rsp_data[497]
  PIN mem_rsp_data[496]
    DIRECTION INPUT ;
    USE SIGNAL ;
    PORT
      LAYER metal5 ;
        RECT 1663.310000 1178.800000 1663.450000 1178.940000 ;
    END
  END mem_rsp_data[496]
  PIN mem_rsp_data[495]
    DIRECTION INPUT ;
    USE SIGNAL ;
    PORT
      LAYER metal5 ;
        RECT 1663.310000 1173.200000 1663.450000 1173.340000 ;
    END
  END mem_rsp_data[495]
  PIN mem_rsp_data[494]
    DIRECTION INPUT ;
    USE SIGNAL ;
    PORT
      LAYER metal5 ;
        RECT 1663.310000 1167.600000 1663.450000 1167.740000 ;
    END
  END mem_rsp_data[494]
  PIN mem_rsp_data[493]
    DIRECTION INPUT ;
    USE SIGNAL ;
    PORT
      LAYER metal5 ;
        RECT 1663.310000 1161.720000 1663.450000 1161.860000 ;
    END
  END mem_rsp_data[493]
  PIN mem_rsp_data[492]
    DIRECTION INPUT ;
    USE SIGNAL ;
    PORT
      LAYER metal5 ;
        RECT 1663.310000 1156.120000 1663.450000 1156.260000 ;
    END
  END mem_rsp_data[492]
  PIN mem_rsp_data[491]
    DIRECTION INPUT ;
    USE SIGNAL ;
    PORT
      LAYER metal5 ;
        RECT 1663.310000 1150.520000 1663.450000 1150.660000 ;
    END
  END mem_rsp_data[491]
  PIN mem_rsp_data[490]
    DIRECTION INPUT ;
    USE SIGNAL ;
    PORT
      LAYER metal5 ;
        RECT 1663.310000 1144.920000 1663.450000 1145.060000 ;
    END
  END mem_rsp_data[490]
  PIN mem_rsp_data[489]
    DIRECTION INPUT ;
    USE SIGNAL ;
    PORT
      LAYER metal5 ;
        RECT 1663.310000 1139.320000 1663.450000 1139.460000 ;
    END
  END mem_rsp_data[489]
  PIN mem_rsp_data[488]
    DIRECTION INPUT ;
    USE SIGNAL ;
    PORT
      LAYER metal5 ;
        RECT 1663.310000 1133.720000 1663.450000 1133.860000 ;
    END
  END mem_rsp_data[488]
  PIN mem_rsp_data[487]
    DIRECTION INPUT ;
    USE SIGNAL ;
    PORT
      LAYER metal5 ;
        RECT 1663.310000 1128.120000 1663.450000 1128.260000 ;
    END
  END mem_rsp_data[487]
  PIN mem_rsp_data[486]
    DIRECTION INPUT ;
    USE SIGNAL ;
    PORT
      LAYER metal5 ;
        RECT 1663.310000 1122.240000 1663.450000 1122.380000 ;
    END
  END mem_rsp_data[486]
  PIN mem_rsp_data[485]
    DIRECTION INPUT ;
    USE SIGNAL ;
    PORT
      LAYER metal5 ;
        RECT 1663.310000 1116.640000 1663.450000 1116.780000 ;
    END
  END mem_rsp_data[485]
  PIN mem_rsp_data[484]
    DIRECTION INPUT ;
    USE SIGNAL ;
    PORT
      LAYER metal5 ;
        RECT 1663.310000 1111.040000 1663.450000 1111.180000 ;
    END
  END mem_rsp_data[484]
  PIN mem_rsp_data[483]
    DIRECTION INPUT ;
    USE SIGNAL ;
    PORT
      LAYER metal5 ;
        RECT 1663.310000 1105.440000 1663.450000 1105.580000 ;
    END
  END mem_rsp_data[483]
  PIN mem_rsp_data[482]
    DIRECTION INPUT ;
    USE SIGNAL ;
    PORT
      LAYER metal5 ;
        RECT 1663.310000 1099.840000 1663.450000 1099.980000 ;
    END
  END mem_rsp_data[482]
  PIN mem_rsp_data[481]
    DIRECTION INPUT ;
    USE SIGNAL ;
    PORT
      LAYER metal5 ;
        RECT 1663.310000 1094.240000 1663.450000 1094.380000 ;
    END
  END mem_rsp_data[481]
  PIN mem_rsp_data[480]
    DIRECTION INPUT ;
    USE SIGNAL ;
    PORT
      LAYER metal5 ;
        RECT 1663.310000 1088.640000 1663.450000 1088.780000 ;
    END
  END mem_rsp_data[480]
  PIN mem_rsp_data[479]
    DIRECTION INPUT ;
    USE SIGNAL ;
    PORT
      LAYER metal5 ;
        RECT 1663.310000 1083.040000 1663.450000 1083.180000 ;
    END
  END mem_rsp_data[479]
  PIN mem_rsp_data[478]
    DIRECTION INPUT ;
    USE SIGNAL ;
    PORT
      LAYER metal5 ;
        RECT 1663.310000 1077.160000 1663.450000 1077.300000 ;
    END
  END mem_rsp_data[478]
  PIN mem_rsp_data[477]
    DIRECTION INPUT ;
    USE SIGNAL ;
    PORT
      LAYER metal5 ;
        RECT 1663.310000 1071.560000 1663.450000 1071.700000 ;
    END
  END mem_rsp_data[477]
  PIN mem_rsp_data[476]
    DIRECTION INPUT ;
    USE SIGNAL ;
    PORT
      LAYER metal5 ;
        RECT 1663.310000 1065.960000 1663.450000 1066.100000 ;
    END
  END mem_rsp_data[476]
  PIN mem_rsp_data[475]
    DIRECTION INPUT ;
    USE SIGNAL ;
    PORT
      LAYER metal5 ;
        RECT 1663.310000 1060.360000 1663.450000 1060.500000 ;
    END
  END mem_rsp_data[475]
  PIN mem_rsp_data[474]
    DIRECTION INPUT ;
    USE SIGNAL ;
    PORT
      LAYER metal5 ;
        RECT 1663.310000 1054.760000 1663.450000 1054.900000 ;
    END
  END mem_rsp_data[474]
  PIN mem_rsp_data[473]
    DIRECTION INPUT ;
    USE SIGNAL ;
    PORT
      LAYER metal5 ;
        RECT 1663.310000 1049.160000 1663.450000 1049.300000 ;
    END
  END mem_rsp_data[473]
  PIN mem_rsp_data[472]
    DIRECTION INPUT ;
    USE SIGNAL ;
    PORT
      LAYER metal5 ;
        RECT 1663.310000 1043.560000 1663.450000 1043.700000 ;
    END
  END mem_rsp_data[472]
  PIN mem_rsp_data[471]
    DIRECTION INPUT ;
    USE SIGNAL ;
    PORT
      LAYER metal5 ;
        RECT 1663.310000 1037.680000 1663.450000 1037.820000 ;
    END
  END mem_rsp_data[471]
  PIN mem_rsp_data[470]
    DIRECTION INPUT ;
    USE SIGNAL ;
    PORT
      LAYER metal5 ;
        RECT 1663.310000 1032.080000 1663.450000 1032.220000 ;
    END
  END mem_rsp_data[470]
  PIN mem_rsp_data[469]
    DIRECTION INPUT ;
    USE SIGNAL ;
    PORT
      LAYER metal5 ;
        RECT 1663.310000 1026.480000 1663.450000 1026.620000 ;
    END
  END mem_rsp_data[469]
  PIN mem_rsp_data[468]
    DIRECTION INPUT ;
    USE SIGNAL ;
    PORT
      LAYER metal5 ;
        RECT 1663.310000 1020.880000 1663.450000 1021.020000 ;
    END
  END mem_rsp_data[468]
  PIN mem_rsp_data[467]
    DIRECTION INPUT ;
    USE SIGNAL ;
    PORT
      LAYER metal5 ;
        RECT 1663.310000 1015.280000 1663.450000 1015.420000 ;
    END
  END mem_rsp_data[467]
  PIN mem_rsp_data[466]
    DIRECTION INPUT ;
    USE SIGNAL ;
    PORT
      LAYER metal5 ;
        RECT 1663.310000 1009.680000 1663.450000 1009.820000 ;
    END
  END mem_rsp_data[466]
  PIN mem_rsp_data[465]
    DIRECTION INPUT ;
    USE SIGNAL ;
    PORT
      LAYER metal5 ;
        RECT 1663.310000 1004.080000 1663.450000 1004.220000 ;
    END
  END mem_rsp_data[465]
  PIN mem_rsp_data[464]
    DIRECTION INPUT ;
    USE SIGNAL ;
    PORT
      LAYER metal5 ;
        RECT 1663.310000 998.480000 1663.450000 998.620000 ;
    END
  END mem_rsp_data[464]
  PIN mem_rsp_data[463]
    DIRECTION INPUT ;
    USE SIGNAL ;
    PORT
      LAYER metal5 ;
        RECT 1663.310000 992.600000 1663.450000 992.740000 ;
    END
  END mem_rsp_data[463]
  PIN mem_rsp_data[462]
    DIRECTION INPUT ;
    USE SIGNAL ;
    PORT
      LAYER metal5 ;
        RECT 1663.310000 987.000000 1663.450000 987.140000 ;
    END
  END mem_rsp_data[462]
  PIN mem_rsp_data[461]
    DIRECTION INPUT ;
    USE SIGNAL ;
    PORT
      LAYER metal5 ;
        RECT 1663.310000 981.400000 1663.450000 981.540000 ;
    END
  END mem_rsp_data[461]
  PIN mem_rsp_data[460]
    DIRECTION INPUT ;
    USE SIGNAL ;
    PORT
      LAYER metal5 ;
        RECT 1663.310000 975.800000 1663.450000 975.940000 ;
    END
  END mem_rsp_data[460]
  PIN mem_rsp_data[459]
    DIRECTION INPUT ;
    USE SIGNAL ;
    PORT
      LAYER metal5 ;
        RECT 1663.310000 970.200000 1663.450000 970.340000 ;
    END
  END mem_rsp_data[459]
  PIN mem_rsp_data[458]
    DIRECTION INPUT ;
    USE SIGNAL ;
    PORT
      LAYER metal5 ;
        RECT 1663.310000 964.600000 1663.450000 964.740000 ;
    END
  END mem_rsp_data[458]
  PIN mem_rsp_data[457]
    DIRECTION INPUT ;
    USE SIGNAL ;
    PORT
      LAYER metal5 ;
        RECT 1663.310000 959.000000 1663.450000 959.140000 ;
    END
  END mem_rsp_data[457]
  PIN mem_rsp_data[456]
    DIRECTION INPUT ;
    USE SIGNAL ;
    PORT
      LAYER metal5 ;
        RECT 1663.310000 953.120000 1663.450000 953.260000 ;
    END
  END mem_rsp_data[456]
  PIN mem_rsp_data[455]
    DIRECTION INPUT ;
    USE SIGNAL ;
    PORT
      LAYER metal5 ;
        RECT 1663.310000 947.520000 1663.450000 947.660000 ;
    END
  END mem_rsp_data[455]
  PIN mem_rsp_data[454]
    DIRECTION INPUT ;
    USE SIGNAL ;
    PORT
      LAYER metal5 ;
        RECT 1663.310000 941.920000 1663.450000 942.060000 ;
    END
  END mem_rsp_data[454]
  PIN mem_rsp_data[453]
    DIRECTION INPUT ;
    USE SIGNAL ;
    PORT
      LAYER metal5 ;
        RECT 1663.310000 936.320000 1663.450000 936.460000 ;
    END
  END mem_rsp_data[453]
  PIN mem_rsp_data[452]
    DIRECTION INPUT ;
    USE SIGNAL ;
    PORT
      LAYER metal5 ;
        RECT 1663.310000 930.720000 1663.450000 930.860000 ;
    END
  END mem_rsp_data[452]
  PIN mem_rsp_data[451]
    DIRECTION INPUT ;
    USE SIGNAL ;
    PORT
      LAYER metal5 ;
        RECT 1663.310000 925.120000 1663.450000 925.260000 ;
    END
  END mem_rsp_data[451]
  PIN mem_rsp_data[450]
    DIRECTION INPUT ;
    USE SIGNAL ;
    PORT
      LAYER metal5 ;
        RECT 1663.310000 919.520000 1663.450000 919.660000 ;
    END
  END mem_rsp_data[450]
  PIN mem_rsp_data[449]
    DIRECTION INPUT ;
    USE SIGNAL ;
    PORT
      LAYER metal5 ;
        RECT 1663.310000 913.640000 1663.450000 913.780000 ;
    END
  END mem_rsp_data[449]
  PIN mem_rsp_data[448]
    DIRECTION INPUT ;
    USE SIGNAL ;
    PORT
      LAYER metal5 ;
        RECT 1663.310000 908.040000 1663.450000 908.180000 ;
    END
  END mem_rsp_data[448]
  PIN mem_rsp_data[447]
    DIRECTION INPUT ;
    USE SIGNAL ;
    PORT
      LAYER metal5 ;
        RECT 1663.310000 902.440000 1663.450000 902.580000 ;
    END
  END mem_rsp_data[447]
  PIN mem_rsp_data[446]
    DIRECTION INPUT ;
    USE SIGNAL ;
    PORT
      LAYER metal5 ;
        RECT 1663.310000 896.840000 1663.450000 896.980000 ;
    END
  END mem_rsp_data[446]
  PIN mem_rsp_data[445]
    DIRECTION INPUT ;
    USE SIGNAL ;
    PORT
      LAYER metal5 ;
        RECT 1663.310000 891.240000 1663.450000 891.380000 ;
    END
  END mem_rsp_data[445]
  PIN mem_rsp_data[444]
    DIRECTION INPUT ;
    USE SIGNAL ;
    PORT
      LAYER metal5 ;
        RECT 1663.310000 885.640000 1663.450000 885.780000 ;
    END
  END mem_rsp_data[444]
  PIN mem_rsp_data[443]
    DIRECTION INPUT ;
    USE SIGNAL ;
    PORT
      LAYER metal5 ;
        RECT 1663.310000 880.040000 1663.450000 880.180000 ;
    END
  END mem_rsp_data[443]
  PIN mem_rsp_data[442]
    DIRECTION INPUT ;
    USE SIGNAL ;
    PORT
      LAYER metal5 ;
        RECT 1663.310000 874.440000 1663.450000 874.580000 ;
    END
  END mem_rsp_data[442]
  PIN mem_rsp_data[441]
    DIRECTION INPUT ;
    USE SIGNAL ;
    PORT
      LAYER metal5 ;
        RECT 1663.310000 868.560000 1663.450000 868.700000 ;
    END
  END mem_rsp_data[441]
  PIN mem_rsp_data[440]
    DIRECTION INPUT ;
    USE SIGNAL ;
    PORT
      LAYER metal5 ;
        RECT 1663.310000 862.960000 1663.450000 863.100000 ;
    END
  END mem_rsp_data[440]
  PIN mem_rsp_data[439]
    DIRECTION INPUT ;
    USE SIGNAL ;
    PORT
      LAYER metal5 ;
        RECT 1663.310000 857.360000 1663.450000 857.500000 ;
    END
  END mem_rsp_data[439]
  PIN mem_rsp_data[438]
    DIRECTION INPUT ;
    USE SIGNAL ;
    PORT
      LAYER metal5 ;
        RECT 1663.310000 851.760000 1663.450000 851.900000 ;
    END
  END mem_rsp_data[438]
  PIN mem_rsp_data[437]
    DIRECTION INPUT ;
    USE SIGNAL ;
    PORT
      LAYER metal5 ;
        RECT 1663.310000 846.160000 1663.450000 846.300000 ;
    END
  END mem_rsp_data[437]
  PIN mem_rsp_data[436]
    DIRECTION INPUT ;
    USE SIGNAL ;
    PORT
      LAYER metal5 ;
        RECT 1663.310000 840.560000 1663.450000 840.700000 ;
    END
  END mem_rsp_data[436]
  PIN mem_rsp_data[435]
    DIRECTION INPUT ;
    USE SIGNAL ;
    PORT
      LAYER metal5 ;
        RECT 1663.310000 834.960000 1663.450000 835.100000 ;
    END
  END mem_rsp_data[435]
  PIN mem_rsp_data[434]
    DIRECTION INPUT ;
    USE SIGNAL ;
    PORT
      LAYER metal5 ;
        RECT 1663.310000 829.080000 1663.450000 829.220000 ;
    END
  END mem_rsp_data[434]
  PIN mem_rsp_data[433]
    DIRECTION INPUT ;
    USE SIGNAL ;
    PORT
      LAYER metal5 ;
        RECT 1663.310000 823.480000 1663.450000 823.620000 ;
    END
  END mem_rsp_data[433]
  PIN mem_rsp_data[432]
    DIRECTION INPUT ;
    USE SIGNAL ;
    PORT
      LAYER metal5 ;
        RECT 1663.310000 817.880000 1663.450000 818.020000 ;
    END
  END mem_rsp_data[432]
  PIN mem_rsp_data[431]
    DIRECTION INPUT ;
    USE SIGNAL ;
    PORT
      LAYER metal5 ;
        RECT 1663.310000 812.280000 1663.450000 812.420000 ;
    END
  END mem_rsp_data[431]
  PIN mem_rsp_data[430]
    DIRECTION INPUT ;
    USE SIGNAL ;
    PORT
      LAYER metal5 ;
        RECT 1663.310000 806.680000 1663.450000 806.820000 ;
    END
  END mem_rsp_data[430]
  PIN mem_rsp_data[429]
    DIRECTION INPUT ;
    USE SIGNAL ;
    PORT
      LAYER metal5 ;
        RECT 1663.310000 801.080000 1663.450000 801.220000 ;
    END
  END mem_rsp_data[429]
  PIN mem_rsp_data[428]
    DIRECTION INPUT ;
    USE SIGNAL ;
    PORT
      LAYER metal5 ;
        RECT 1663.310000 795.480000 1663.450000 795.620000 ;
    END
  END mem_rsp_data[428]
  PIN mem_rsp_data[427]
    DIRECTION INPUT ;
    USE SIGNAL ;
    PORT
      LAYER metal5 ;
        RECT 1663.310000 789.600000 1663.450000 789.740000 ;
    END
  END mem_rsp_data[427]
  PIN mem_rsp_data[426]
    DIRECTION INPUT ;
    USE SIGNAL ;
    PORT
      LAYER metal5 ;
        RECT 1663.310000 784.000000 1663.450000 784.140000 ;
    END
  END mem_rsp_data[426]
  PIN mem_rsp_data[425]
    DIRECTION INPUT ;
    USE SIGNAL ;
    PORT
      LAYER metal5 ;
        RECT 1663.310000 778.400000 1663.450000 778.540000 ;
    END
  END mem_rsp_data[425]
  PIN mem_rsp_data[424]
    DIRECTION INPUT ;
    USE SIGNAL ;
    PORT
      LAYER metal5 ;
        RECT 1663.310000 772.800000 1663.450000 772.940000 ;
    END
  END mem_rsp_data[424]
  PIN mem_rsp_data[423]
    DIRECTION INPUT ;
    USE SIGNAL ;
    PORT
      LAYER metal5 ;
        RECT 1663.310000 767.200000 1663.450000 767.340000 ;
    END
  END mem_rsp_data[423]
  PIN mem_rsp_data[422]
    DIRECTION INPUT ;
    USE SIGNAL ;
    PORT
      LAYER metal5 ;
        RECT 1663.310000 761.600000 1663.450000 761.740000 ;
    END
  END mem_rsp_data[422]
  PIN mem_rsp_data[421]
    DIRECTION INPUT ;
    USE SIGNAL ;
    PORT
      LAYER metal5 ;
        RECT 1663.310000 756.000000 1663.450000 756.140000 ;
    END
  END mem_rsp_data[421]
  PIN mem_rsp_data[420]
    DIRECTION INPUT ;
    USE SIGNAL ;
    PORT
      LAYER metal5 ;
        RECT 1663.310000 750.400000 1663.450000 750.540000 ;
    END
  END mem_rsp_data[420]
  PIN mem_rsp_data[419]
    DIRECTION INPUT ;
    USE SIGNAL ;
    PORT
      LAYER metal5 ;
        RECT 1663.310000 744.520000 1663.450000 744.660000 ;
    END
  END mem_rsp_data[419]
  PIN mem_rsp_data[418]
    DIRECTION INPUT ;
    USE SIGNAL ;
    PORT
      LAYER metal5 ;
        RECT 1663.310000 738.920000 1663.450000 739.060000 ;
    END
  END mem_rsp_data[418]
  PIN mem_rsp_data[417]
    DIRECTION INPUT ;
    USE SIGNAL ;
    PORT
      LAYER metal5 ;
        RECT 1663.310000 733.320000 1663.450000 733.460000 ;
    END
  END mem_rsp_data[417]
  PIN mem_rsp_data[416]
    DIRECTION INPUT ;
    USE SIGNAL ;
    PORT
      LAYER metal5 ;
        RECT 1663.310000 727.720000 1663.450000 727.860000 ;
    END
  END mem_rsp_data[416]
  PIN mem_rsp_data[415]
    DIRECTION INPUT ;
    USE SIGNAL ;
    PORT
      LAYER metal5 ;
        RECT 1663.310000 722.120000 1663.450000 722.260000 ;
    END
  END mem_rsp_data[415]
  PIN mem_rsp_data[414]
    DIRECTION INPUT ;
    USE SIGNAL ;
    PORT
      LAYER metal5 ;
        RECT 1663.310000 716.520000 1663.450000 716.660000 ;
    END
  END mem_rsp_data[414]
  PIN mem_rsp_data[413]
    DIRECTION INPUT ;
    USE SIGNAL ;
    PORT
      LAYER metal5 ;
        RECT 1663.310000 710.920000 1663.450000 711.060000 ;
    END
  END mem_rsp_data[413]
  PIN mem_rsp_data[412]
    DIRECTION INPUT ;
    USE SIGNAL ;
    PORT
      LAYER metal5 ;
        RECT 1663.310000 705.040000 1663.450000 705.180000 ;
    END
  END mem_rsp_data[412]
  PIN mem_rsp_data[411]
    DIRECTION INPUT ;
    USE SIGNAL ;
    PORT
      LAYER metal5 ;
        RECT 1663.310000 699.440000 1663.450000 699.580000 ;
    END
  END mem_rsp_data[411]
  PIN mem_rsp_data[410]
    DIRECTION INPUT ;
    USE SIGNAL ;
    PORT
      LAYER metal5 ;
        RECT 1663.310000 693.840000 1663.450000 693.980000 ;
    END
  END mem_rsp_data[410]
  PIN mem_rsp_data[409]
    DIRECTION INPUT ;
    USE SIGNAL ;
    PORT
      LAYER metal5 ;
        RECT 1663.310000 688.240000 1663.450000 688.380000 ;
    END
  END mem_rsp_data[409]
  PIN mem_rsp_data[408]
    DIRECTION INPUT ;
    USE SIGNAL ;
    PORT
      LAYER metal5 ;
        RECT 1663.310000 682.640000 1663.450000 682.780000 ;
    END
  END mem_rsp_data[408]
  PIN mem_rsp_data[407]
    DIRECTION INPUT ;
    USE SIGNAL ;
    PORT
      LAYER metal5 ;
        RECT 1663.310000 677.040000 1663.450000 677.180000 ;
    END
  END mem_rsp_data[407]
  PIN mem_rsp_data[406]
    DIRECTION INPUT ;
    USE SIGNAL ;
    PORT
      LAYER metal5 ;
        RECT 1663.310000 671.440000 1663.450000 671.580000 ;
    END
  END mem_rsp_data[406]
  PIN mem_rsp_data[405]
    DIRECTION INPUT ;
    USE SIGNAL ;
    PORT
      LAYER metal5 ;
        RECT 1663.310000 665.560000 1663.450000 665.700000 ;
    END
  END mem_rsp_data[405]
  PIN mem_rsp_data[404]
    DIRECTION INPUT ;
    USE SIGNAL ;
    PORT
      LAYER metal5 ;
        RECT 1663.310000 659.960000 1663.450000 660.100000 ;
    END
  END mem_rsp_data[404]
  PIN mem_rsp_data[403]
    DIRECTION INPUT ;
    USE SIGNAL ;
    PORT
      LAYER metal5 ;
        RECT 1663.310000 654.360000 1663.450000 654.500000 ;
    END
  END mem_rsp_data[403]
  PIN mem_rsp_data[402]
    DIRECTION INPUT ;
    USE SIGNAL ;
    PORT
      LAYER metal5 ;
        RECT 1663.310000 648.760000 1663.450000 648.900000 ;
    END
  END mem_rsp_data[402]
  PIN mem_rsp_data[401]
    DIRECTION INPUT ;
    USE SIGNAL ;
    PORT
      LAYER metal5 ;
        RECT 1663.310000 643.160000 1663.450000 643.300000 ;
    END
  END mem_rsp_data[401]
  PIN mem_rsp_data[400]
    DIRECTION INPUT ;
    USE SIGNAL ;
    PORT
      LAYER metal5 ;
        RECT 1663.310000 637.560000 1663.450000 637.700000 ;
    END
  END mem_rsp_data[400]
  PIN mem_rsp_data[399]
    DIRECTION INPUT ;
    USE SIGNAL ;
    PORT
      LAYER metal5 ;
        RECT 1663.310000 631.960000 1663.450000 632.100000 ;
    END
  END mem_rsp_data[399]
  PIN mem_rsp_data[398]
    DIRECTION INPUT ;
    USE SIGNAL ;
    PORT
      LAYER metal5 ;
        RECT 1663.310000 626.360000 1663.450000 626.500000 ;
    END
  END mem_rsp_data[398]
  PIN mem_rsp_data[397]
    DIRECTION INPUT ;
    USE SIGNAL ;
    PORT
      LAYER metal5 ;
        RECT 1663.310000 620.480000 1663.450000 620.620000 ;
    END
  END mem_rsp_data[397]
  PIN mem_rsp_data[396]
    DIRECTION INPUT ;
    USE SIGNAL ;
    PORT
      LAYER metal5 ;
        RECT 1663.310000 614.880000 1663.450000 615.020000 ;
    END
  END mem_rsp_data[396]
  PIN mem_rsp_data[395]
    DIRECTION INPUT ;
    USE SIGNAL ;
    PORT
      LAYER metal5 ;
        RECT 1663.310000 609.280000 1663.450000 609.420000 ;
    END
  END mem_rsp_data[395]
  PIN mem_rsp_data[394]
    DIRECTION INPUT ;
    USE SIGNAL ;
    PORT
      LAYER metal5 ;
        RECT 1663.310000 603.680000 1663.450000 603.820000 ;
    END
  END mem_rsp_data[394]
  PIN mem_rsp_data[393]
    DIRECTION INPUT ;
    USE SIGNAL ;
    PORT
      LAYER metal5 ;
        RECT 1663.310000 598.080000 1663.450000 598.220000 ;
    END
  END mem_rsp_data[393]
  PIN mem_rsp_data[392]
    DIRECTION INPUT ;
    USE SIGNAL ;
    PORT
      LAYER metal5 ;
        RECT 1663.310000 592.480000 1663.450000 592.620000 ;
    END
  END mem_rsp_data[392]
  PIN mem_rsp_data[391]
    DIRECTION INPUT ;
    USE SIGNAL ;
    PORT
      LAYER metal5 ;
        RECT 1663.310000 586.880000 1663.450000 587.020000 ;
    END
  END mem_rsp_data[391]
  PIN mem_rsp_data[390]
    DIRECTION INPUT ;
    USE SIGNAL ;
    PORT
      LAYER metal5 ;
        RECT 1663.310000 581.000000 1663.450000 581.140000 ;
    END
  END mem_rsp_data[390]
  PIN mem_rsp_data[389]
    DIRECTION INPUT ;
    USE SIGNAL ;
    PORT
      LAYER metal5 ;
        RECT 1663.310000 575.400000 1663.450000 575.540000 ;
    END
  END mem_rsp_data[389]
  PIN mem_rsp_data[388]
    DIRECTION INPUT ;
    USE SIGNAL ;
    PORT
      LAYER metal5 ;
        RECT 1663.310000 569.800000 1663.450000 569.940000 ;
    END
  END mem_rsp_data[388]
  PIN mem_rsp_data[387]
    DIRECTION INPUT ;
    USE SIGNAL ;
    PORT
      LAYER metal5 ;
        RECT 1663.310000 564.200000 1663.450000 564.340000 ;
    END
  END mem_rsp_data[387]
  PIN mem_rsp_data[386]
    DIRECTION INPUT ;
    USE SIGNAL ;
    PORT
      LAYER metal5 ;
        RECT 1663.310000 558.600000 1663.450000 558.740000 ;
    END
  END mem_rsp_data[386]
  PIN mem_rsp_data[385]
    DIRECTION INPUT ;
    USE SIGNAL ;
    PORT
      LAYER metal5 ;
        RECT 1663.310000 553.000000 1663.450000 553.140000 ;
    END
  END mem_rsp_data[385]
  PIN mem_rsp_data[384]
    DIRECTION INPUT ;
    USE SIGNAL ;
    PORT
      LAYER metal5 ;
        RECT 1663.310000 547.400000 1663.450000 547.540000 ;
    END
  END mem_rsp_data[384]
  PIN mem_rsp_data[383]
    DIRECTION INPUT ;
    USE SIGNAL ;
    PORT
      LAYER metal5 ;
        RECT 1663.310000 541.800000 1663.450000 541.940000 ;
    END
  END mem_rsp_data[383]
  PIN mem_rsp_data[382]
    DIRECTION INPUT ;
    USE SIGNAL ;
    PORT
      LAYER metal5 ;
        RECT 1663.310000 535.920000 1663.450000 536.060000 ;
    END
  END mem_rsp_data[382]
  PIN mem_rsp_data[381]
    DIRECTION INPUT ;
    USE SIGNAL ;
    PORT
      LAYER metal5 ;
        RECT 1663.310000 530.320000 1663.450000 530.460000 ;
    END
  END mem_rsp_data[381]
  PIN mem_rsp_data[380]
    DIRECTION INPUT ;
    USE SIGNAL ;
    PORT
      LAYER metal5 ;
        RECT 1663.310000 524.720000 1663.450000 524.860000 ;
    END
  END mem_rsp_data[380]
  PIN mem_rsp_data[379]
    DIRECTION INPUT ;
    USE SIGNAL ;
    PORT
      LAYER metal5 ;
        RECT 1663.310000 519.120000 1663.450000 519.260000 ;
    END
  END mem_rsp_data[379]
  PIN mem_rsp_data[378]
    DIRECTION INPUT ;
    USE SIGNAL ;
    PORT
      LAYER metal5 ;
        RECT 1663.310000 513.520000 1663.450000 513.660000 ;
    END
  END mem_rsp_data[378]
  PIN mem_rsp_data[377]
    DIRECTION INPUT ;
    USE SIGNAL ;
    PORT
      LAYER metal5 ;
        RECT 1663.310000 507.920000 1663.450000 508.060000 ;
    END
  END mem_rsp_data[377]
  PIN mem_rsp_data[376]
    DIRECTION INPUT ;
    USE SIGNAL ;
    PORT
      LAYER metal5 ;
        RECT 1663.310000 502.320000 1663.450000 502.460000 ;
    END
  END mem_rsp_data[376]
  PIN mem_rsp_data[375]
    DIRECTION INPUT ;
    USE SIGNAL ;
    PORT
      LAYER metal5 ;
        RECT 1663.310000 496.440000 1663.450000 496.580000 ;
    END
  END mem_rsp_data[375]
  PIN mem_rsp_data[374]
    DIRECTION INPUT ;
    USE SIGNAL ;
    PORT
      LAYER metal5 ;
        RECT 1663.310000 490.840000 1663.450000 490.980000 ;
    END
  END mem_rsp_data[374]
  PIN mem_rsp_data[373]
    DIRECTION INPUT ;
    USE SIGNAL ;
    PORT
      LAYER metal5 ;
        RECT 1663.310000 485.240000 1663.450000 485.380000 ;
    END
  END mem_rsp_data[373]
  PIN mem_rsp_data[372]
    DIRECTION INPUT ;
    USE SIGNAL ;
    PORT
      LAYER metal5 ;
        RECT 1663.310000 479.640000 1663.450000 479.780000 ;
    END
  END mem_rsp_data[372]
  PIN mem_rsp_data[371]
    DIRECTION INPUT ;
    USE SIGNAL ;
    PORT
      LAYER metal5 ;
        RECT 1663.310000 474.040000 1663.450000 474.180000 ;
    END
  END mem_rsp_data[371]
  PIN mem_rsp_data[370]
    DIRECTION INPUT ;
    USE SIGNAL ;
    PORT
      LAYER metal5 ;
        RECT 1663.310000 468.440000 1663.450000 468.580000 ;
    END
  END mem_rsp_data[370]
  PIN mem_rsp_data[369]
    DIRECTION INPUT ;
    USE SIGNAL ;
    PORT
      LAYER metal5 ;
        RECT 1663.310000 462.840000 1663.450000 462.980000 ;
    END
  END mem_rsp_data[369]
  PIN mem_rsp_data[368]
    DIRECTION INPUT ;
    USE SIGNAL ;
    PORT
      LAYER metal5 ;
        RECT 1663.310000 456.960000 1663.450000 457.100000 ;
    END
  END mem_rsp_data[368]
  PIN mem_rsp_data[367]
    DIRECTION INPUT ;
    USE SIGNAL ;
    PORT
      LAYER metal5 ;
        RECT 1663.310000 451.360000 1663.450000 451.500000 ;
    END
  END mem_rsp_data[367]
  PIN mem_rsp_data[366]
    DIRECTION INPUT ;
    USE SIGNAL ;
    PORT
      LAYER metal5 ;
        RECT 1663.310000 445.760000 1663.450000 445.900000 ;
    END
  END mem_rsp_data[366]
  PIN mem_rsp_data[365]
    DIRECTION INPUT ;
    USE SIGNAL ;
    PORT
      LAYER metal5 ;
        RECT 1663.310000 440.160000 1663.450000 440.300000 ;
    END
  END mem_rsp_data[365]
  PIN mem_rsp_data[364]
    DIRECTION INPUT ;
    USE SIGNAL ;
    PORT
      LAYER metal5 ;
        RECT 1663.310000 434.560000 1663.450000 434.700000 ;
    END
  END mem_rsp_data[364]
  PIN mem_rsp_data[363]
    DIRECTION INPUT ;
    USE SIGNAL ;
    PORT
      LAYER metal5 ;
        RECT 1663.310000 428.960000 1663.450000 429.100000 ;
    END
  END mem_rsp_data[363]
  PIN mem_rsp_data[362]
    DIRECTION INPUT ;
    USE SIGNAL ;
    PORT
      LAYER metal5 ;
        RECT 1663.310000 423.360000 1663.450000 423.500000 ;
    END
  END mem_rsp_data[362]
  PIN mem_rsp_data[361]
    DIRECTION INPUT ;
    USE SIGNAL ;
    PORT
      LAYER metal5 ;
        RECT 1663.310000 417.760000 1663.450000 417.900000 ;
    END
  END mem_rsp_data[361]
  PIN mem_rsp_data[360]
    DIRECTION INPUT ;
    USE SIGNAL ;
    PORT
      LAYER metal5 ;
        RECT 1663.310000 411.880000 1663.450000 412.020000 ;
    END
  END mem_rsp_data[360]
  PIN mem_rsp_data[359]
    DIRECTION INPUT ;
    USE SIGNAL ;
    PORT
      LAYER metal5 ;
        RECT 1663.310000 406.280000 1663.450000 406.420000 ;
    END
  END mem_rsp_data[359]
  PIN mem_rsp_data[358]
    DIRECTION INPUT ;
    USE SIGNAL ;
    PORT
      LAYER metal5 ;
        RECT 1663.310000 400.680000 1663.450000 400.820000 ;
    END
  END mem_rsp_data[358]
  PIN mem_rsp_data[357]
    DIRECTION INPUT ;
    USE SIGNAL ;
    PORT
      LAYER metal5 ;
        RECT 1663.310000 395.080000 1663.450000 395.220000 ;
    END
  END mem_rsp_data[357]
  PIN mem_rsp_data[356]
    DIRECTION INPUT ;
    USE SIGNAL ;
    PORT
      LAYER metal5 ;
        RECT 1663.310000 389.480000 1663.450000 389.620000 ;
    END
  END mem_rsp_data[356]
  PIN mem_rsp_data[355]
    DIRECTION INPUT ;
    USE SIGNAL ;
    PORT
      LAYER metal5 ;
        RECT 1663.310000 383.880000 1663.450000 384.020000 ;
    END
  END mem_rsp_data[355]
  PIN mem_rsp_data[354]
    DIRECTION INPUT ;
    USE SIGNAL ;
    PORT
      LAYER metal5 ;
        RECT 1663.310000 378.280000 1663.450000 378.420000 ;
    END
  END mem_rsp_data[354]
  PIN mem_rsp_data[353]
    DIRECTION INPUT ;
    USE SIGNAL ;
    PORT
      LAYER metal5 ;
        RECT 1663.310000 372.400000 1663.450000 372.540000 ;
    END
  END mem_rsp_data[353]
  PIN mem_rsp_data[352]
    DIRECTION INPUT ;
    USE SIGNAL ;
    PORT
      LAYER metal5 ;
        RECT 1663.310000 366.800000 1663.450000 366.940000 ;
    END
  END mem_rsp_data[352]
  PIN mem_rsp_data[351]
    DIRECTION INPUT ;
    USE SIGNAL ;
    PORT
      LAYER metal5 ;
        RECT 1663.310000 361.200000 1663.450000 361.340000 ;
    END
  END mem_rsp_data[351]
  PIN mem_rsp_data[350]
    DIRECTION INPUT ;
    USE SIGNAL ;
    PORT
      LAYER metal5 ;
        RECT 1663.310000 355.600000 1663.450000 355.740000 ;
    END
  END mem_rsp_data[350]
  PIN mem_rsp_data[349]
    DIRECTION INPUT ;
    USE SIGNAL ;
    PORT
      LAYER metal5 ;
        RECT 1663.310000 350.000000 1663.450000 350.140000 ;
    END
  END mem_rsp_data[349]
  PIN mem_rsp_data[348]
    DIRECTION INPUT ;
    USE SIGNAL ;
    PORT
      LAYER metal5 ;
        RECT 1663.310000 344.400000 1663.450000 344.540000 ;
    END
  END mem_rsp_data[348]
  PIN mem_rsp_data[347]
    DIRECTION INPUT ;
    USE SIGNAL ;
    PORT
      LAYER metal5 ;
        RECT 1663.310000 338.800000 1663.450000 338.940000 ;
    END
  END mem_rsp_data[347]
  PIN mem_rsp_data[346]
    DIRECTION INPUT ;
    USE SIGNAL ;
    PORT
      LAYER metal5 ;
        RECT 1663.310000 332.920000 1663.450000 333.060000 ;
    END
  END mem_rsp_data[346]
  PIN mem_rsp_data[345]
    DIRECTION INPUT ;
    USE SIGNAL ;
    PORT
      LAYER metal5 ;
        RECT 1663.310000 327.320000 1663.450000 327.460000 ;
    END
  END mem_rsp_data[345]
  PIN mem_rsp_data[344]
    DIRECTION INPUT ;
    USE SIGNAL ;
    PORT
      LAYER metal5 ;
        RECT 1663.310000 321.720000 1663.450000 321.860000 ;
    END
  END mem_rsp_data[344]
  PIN mem_rsp_data[343]
    DIRECTION INPUT ;
    USE SIGNAL ;
    PORT
      LAYER metal5 ;
        RECT 1663.310000 316.120000 1663.450000 316.260000 ;
    END
  END mem_rsp_data[343]
  PIN mem_rsp_data[342]
    DIRECTION INPUT ;
    USE SIGNAL ;
    PORT
      LAYER metal5 ;
        RECT 1663.310000 310.520000 1663.450000 310.660000 ;
    END
  END mem_rsp_data[342]
  PIN mem_rsp_data[341]
    DIRECTION INPUT ;
    USE SIGNAL ;
    PORT
      LAYER metal5 ;
        RECT 1663.310000 304.920000 1663.450000 305.060000 ;
    END
  END mem_rsp_data[341]
  PIN mem_rsp_data[340]
    DIRECTION INPUT ;
    USE SIGNAL ;
    PORT
      LAYER metal5 ;
        RECT 1663.310000 299.320000 1663.450000 299.460000 ;
    END
  END mem_rsp_data[340]
  PIN mem_rsp_data[339]
    DIRECTION INPUT ;
    USE SIGNAL ;
    PORT
      LAYER metal5 ;
        RECT 1663.310000 293.720000 1663.450000 293.860000 ;
    END
  END mem_rsp_data[339]
  PIN mem_rsp_data[338]
    DIRECTION INPUT ;
    USE SIGNAL ;
    PORT
      LAYER metal5 ;
        RECT 1663.310000 287.840000 1663.450000 287.980000 ;
    END
  END mem_rsp_data[338]
  PIN mem_rsp_data[337]
    DIRECTION INPUT ;
    USE SIGNAL ;
    PORT
      LAYER metal5 ;
        RECT 1663.310000 282.240000 1663.450000 282.380000 ;
    END
  END mem_rsp_data[337]
  PIN mem_rsp_data[336]
    DIRECTION INPUT ;
    USE SIGNAL ;
    PORT
      LAYER metal5 ;
        RECT 1663.310000 276.640000 1663.450000 276.780000 ;
    END
  END mem_rsp_data[336]
  PIN mem_rsp_data[335]
    DIRECTION INPUT ;
    USE SIGNAL ;
    PORT
      LAYER metal5 ;
        RECT 1663.310000 271.040000 1663.450000 271.180000 ;
    END
  END mem_rsp_data[335]
  PIN mem_rsp_data[334]
    DIRECTION INPUT ;
    USE SIGNAL ;
    PORT
      LAYER metal5 ;
        RECT 1663.310000 265.440000 1663.450000 265.580000 ;
    END
  END mem_rsp_data[334]
  PIN mem_rsp_data[333]
    DIRECTION INPUT ;
    USE SIGNAL ;
    PORT
      LAYER metal5 ;
        RECT 1663.310000 259.840000 1663.450000 259.980000 ;
    END
  END mem_rsp_data[333]
  PIN mem_rsp_data[332]
    DIRECTION INPUT ;
    USE SIGNAL ;
    PORT
      LAYER metal5 ;
        RECT 1663.310000 254.240000 1663.450000 254.380000 ;
    END
  END mem_rsp_data[332]
  PIN mem_rsp_data[331]
    DIRECTION INPUT ;
    USE SIGNAL ;
    PORT
      LAYER metal5 ;
        RECT 1663.310000 248.360000 1663.450000 248.500000 ;
    END
  END mem_rsp_data[331]
  PIN mem_rsp_data[330]
    DIRECTION INPUT ;
    USE SIGNAL ;
    PORT
      LAYER metal5 ;
        RECT 1663.310000 242.760000 1663.450000 242.900000 ;
    END
  END mem_rsp_data[330]
  PIN mem_rsp_data[329]
    DIRECTION INPUT ;
    USE SIGNAL ;
    PORT
      LAYER metal5 ;
        RECT 1663.310000 237.160000 1663.450000 237.300000 ;
    END
  END mem_rsp_data[329]
  PIN mem_rsp_data[328]
    DIRECTION INPUT ;
    USE SIGNAL ;
    PORT
      LAYER metal5 ;
        RECT 1663.310000 231.560000 1663.450000 231.700000 ;
    END
  END mem_rsp_data[328]
  PIN mem_rsp_data[327]
    DIRECTION INPUT ;
    USE SIGNAL ;
    PORT
      LAYER metal5 ;
        RECT 1663.310000 225.960000 1663.450000 226.100000 ;
    END
  END mem_rsp_data[327]
  PIN mem_rsp_data[326]
    DIRECTION INPUT ;
    USE SIGNAL ;
    PORT
      LAYER metal5 ;
        RECT 1663.310000 220.360000 1663.450000 220.500000 ;
    END
  END mem_rsp_data[326]
  PIN mem_rsp_data[325]
    DIRECTION INPUT ;
    USE SIGNAL ;
    PORT
      LAYER metal5 ;
        RECT 1663.310000 214.760000 1663.450000 214.900000 ;
    END
  END mem_rsp_data[325]
  PIN mem_rsp_data[324]
    DIRECTION INPUT ;
    USE SIGNAL ;
    PORT
      LAYER metal5 ;
        RECT 1663.310000 209.160000 1663.450000 209.300000 ;
    END
  END mem_rsp_data[324]
  PIN mem_rsp_data[323]
    DIRECTION INPUT ;
    USE SIGNAL ;
    PORT
      LAYER metal5 ;
        RECT 1663.310000 203.280000 1663.450000 203.420000 ;
    END
  END mem_rsp_data[323]
  PIN mem_rsp_data[322]
    DIRECTION INPUT ;
    USE SIGNAL ;
    PORT
      LAYER metal5 ;
        RECT 1663.310000 197.680000 1663.450000 197.820000 ;
    END
  END mem_rsp_data[322]
  PIN mem_rsp_data[321]
    DIRECTION INPUT ;
    USE SIGNAL ;
    PORT
      LAYER metal5 ;
        RECT 1663.310000 192.080000 1663.450000 192.220000 ;
    END
  END mem_rsp_data[321]
  PIN mem_rsp_data[320]
    DIRECTION INPUT ;
    USE SIGNAL ;
    PORT
      LAYER metal5 ;
        RECT 1663.310000 186.480000 1663.450000 186.620000 ;
    END
  END mem_rsp_data[320]
  PIN mem_rsp_data[319]
    DIRECTION INPUT ;
    USE SIGNAL ;
    PORT
      LAYER metal5 ;
        RECT 1663.310000 180.880000 1663.450000 181.020000 ;
    END
  END mem_rsp_data[319]
  PIN mem_rsp_data[318]
    DIRECTION INPUT ;
    USE SIGNAL ;
    PORT
      LAYER metal5 ;
        RECT 1663.310000 175.280000 1663.450000 175.420000 ;
    END
  END mem_rsp_data[318]
  PIN mem_rsp_data[317]
    DIRECTION INPUT ;
    USE SIGNAL ;
    PORT
      LAYER metal5 ;
        RECT 1663.310000 169.680000 1663.450000 169.820000 ;
    END
  END mem_rsp_data[317]
  PIN mem_rsp_data[316]
    DIRECTION INPUT ;
    USE SIGNAL ;
    PORT
      LAYER metal5 ;
        RECT 1663.310000 163.800000 1663.450000 163.940000 ;
    END
  END mem_rsp_data[316]
  PIN mem_rsp_data[315]
    DIRECTION INPUT ;
    USE SIGNAL ;
    PORT
      LAYER metal5 ;
        RECT 1663.310000 158.200000 1663.450000 158.340000 ;
    END
  END mem_rsp_data[315]
  PIN mem_rsp_data[314]
    DIRECTION INPUT ;
    USE SIGNAL ;
    PORT
      LAYER metal5 ;
        RECT 1663.310000 152.600000 1663.450000 152.740000 ;
    END
  END mem_rsp_data[314]
  PIN mem_rsp_data[313]
    DIRECTION INPUT ;
    USE SIGNAL ;
    PORT
      LAYER metal5 ;
        RECT 1663.310000 147.000000 1663.450000 147.140000 ;
    END
  END mem_rsp_data[313]
  PIN mem_rsp_data[312]
    DIRECTION INPUT ;
    USE SIGNAL ;
    PORT
      LAYER metal5 ;
        RECT 1663.310000 141.400000 1663.450000 141.540000 ;
    END
  END mem_rsp_data[312]
  PIN mem_rsp_data[311]
    DIRECTION INPUT ;
    USE SIGNAL ;
    PORT
      LAYER metal5 ;
        RECT 1663.310000 135.800000 1663.450000 135.940000 ;
    END
  END mem_rsp_data[311]
  PIN mem_rsp_data[310]
    DIRECTION INPUT ;
    USE SIGNAL ;
    PORT
      LAYER metal5 ;
        RECT 1663.310000 130.200000 1663.450000 130.340000 ;
    END
  END mem_rsp_data[310]
  PIN mem_rsp_data[309]
    DIRECTION INPUT ;
    USE SIGNAL ;
    PORT
      LAYER metal5 ;
        RECT 1663.310000 124.320000 1663.450000 124.460000 ;
    END
  END mem_rsp_data[309]
  PIN mem_rsp_data[308]
    DIRECTION INPUT ;
    USE SIGNAL ;
    PORT
      LAYER metal5 ;
        RECT 1663.310000 118.720000 1663.450000 118.860000 ;
    END
  END mem_rsp_data[308]
  PIN mem_rsp_data[307]
    DIRECTION INPUT ;
    USE SIGNAL ;
    PORT
      LAYER metal5 ;
        RECT 1663.310000 113.120000 1663.450000 113.260000 ;
    END
  END mem_rsp_data[307]
  PIN mem_rsp_data[306]
    DIRECTION INPUT ;
    USE SIGNAL ;
    PORT
      LAYER metal5 ;
        RECT 1663.310000 107.520000 1663.450000 107.660000 ;
    END
  END mem_rsp_data[306]
  PIN mem_rsp_data[305]
    DIRECTION INPUT ;
    USE SIGNAL ;
    PORT
      LAYER metal5 ;
        RECT 1663.310000 101.920000 1663.450000 102.060000 ;
    END
  END mem_rsp_data[305]
  PIN mem_rsp_data[304]
    DIRECTION INPUT ;
    USE SIGNAL ;
    PORT
      LAYER metal5 ;
        RECT 1663.310000 96.320000 1663.450000 96.460000 ;
    END
  END mem_rsp_data[304]
  PIN mem_rsp_data[303]
    DIRECTION INPUT ;
    USE SIGNAL ;
    PORT
      LAYER metal5 ;
        RECT 1663.310000 90.720000 1663.450000 90.860000 ;
    END
  END mem_rsp_data[303]
  PIN mem_rsp_data[302]
    DIRECTION INPUT ;
    USE SIGNAL ;
    PORT
      LAYER metal5 ;
        RECT 1663.310000 85.120000 1663.450000 85.260000 ;
    END
  END mem_rsp_data[302]
  PIN mem_rsp_data[301]
    DIRECTION INPUT ;
    USE SIGNAL ;
    PORT
      LAYER metal5 ;
        RECT 1663.310000 79.240000 1663.450000 79.380000 ;
    END
  END mem_rsp_data[301]
  PIN mem_rsp_data[300]
    DIRECTION INPUT ;
    USE SIGNAL ;
    PORT
      LAYER metal5 ;
        RECT 1663.310000 73.640000 1663.450000 73.780000 ;
    END
  END mem_rsp_data[300]
  PIN mem_rsp_data[299]
    DIRECTION INPUT ;
    USE SIGNAL ;
    PORT
      LAYER metal5 ;
        RECT 1663.310000 68.040000 1663.450000 68.180000 ;
    END
  END mem_rsp_data[299]
  PIN mem_rsp_data[298]
    DIRECTION INPUT ;
    USE SIGNAL ;
    PORT
      LAYER metal5 ;
        RECT 1663.310000 62.440000 1663.450000 62.580000 ;
    END
  END mem_rsp_data[298]
  PIN mem_rsp_data[297]
    DIRECTION INPUT ;
    USE SIGNAL ;
    PORT
      LAYER metal5 ;
        RECT 1663.310000 56.840000 1663.450000 56.980000 ;
    END
  END mem_rsp_data[297]
  PIN mem_rsp_data[296]
    DIRECTION INPUT ;
    USE SIGNAL ;
    PORT
      LAYER metal5 ;
        RECT 1663.310000 51.240000 1663.450000 51.380000 ;
    END
  END mem_rsp_data[296]
  PIN mem_rsp_data[295]
    DIRECTION INPUT ;
    USE SIGNAL ;
    PORT
      LAYER metal5 ;
        RECT 1663.310000 45.640000 1663.450000 45.780000 ;
    END
  END mem_rsp_data[295]
  PIN mem_rsp_data[294]
    DIRECTION INPUT ;
    USE SIGNAL ;
    PORT
      LAYER metal5 ;
        RECT 1663.310000 39.760000 1663.450000 39.900000 ;
    END
  END mem_rsp_data[294]
  PIN mem_rsp_data[293]
    DIRECTION INPUT ;
    USE SIGNAL ;
    PORT
      LAYER metal5 ;
        RECT 1663.310000 34.160000 1663.450000 34.300000 ;
    END
  END mem_rsp_data[293]
  PIN mem_rsp_data[292]
    DIRECTION INPUT ;
    USE SIGNAL ;
    PORT
      LAYER metal5 ;
        RECT 1663.310000 28.560000 1663.450000 28.700000 ;
    END
  END mem_rsp_data[292]
  PIN mem_rsp_data[291]
    DIRECTION INPUT ;
    USE SIGNAL ;
    PORT
      LAYER metal5 ;
        RECT 1663.310000 22.960000 1663.450000 23.100000 ;
    END
  END mem_rsp_data[291]
  PIN mem_rsp_data[290]
    DIRECTION INPUT ;
    USE SIGNAL ;
    PORT
      LAYER metal5 ;
        RECT 1663.310000 17.360000 1663.450000 17.500000 ;
    END
  END mem_rsp_data[290]
  PIN mem_rsp_data[289]
    DIRECTION INPUT ;
    USE SIGNAL ;
    PORT
      LAYER metal5 ;
        RECT 1663.310000 11.760000 1663.450000 11.900000 ;
    END
  END mem_rsp_data[289]
  PIN mem_rsp_data[288]
    DIRECTION INPUT ;
    USE SIGNAL ;
    PORT
      LAYER metal5 ;
        RECT 1663.310000 6.160000 1663.450000 6.300000 ;
    END
  END mem_rsp_data[288]
  PIN mem_rsp_data[287]
    DIRECTION INPUT ;
    USE SIGNAL ;
    PORT
      LAYER metal5 ;
        RECT 1663.310000 0.560000 1663.450000 0.700000 ;
    END
  END mem_rsp_data[287]
  PIN mem_rsp_data[286]
    DIRECTION INPUT ;
    USE SIGNAL ;
    PORT
      LAYER metal4 ;
        RECT 0.205000 1663.620000 0.345000 1663.760000 ;
    END
  END mem_rsp_data[286]
  PIN mem_rsp_data[285]
    DIRECTION INPUT ;
    USE SIGNAL ;
    PORT
      LAYER metal4 ;
        RECT 5.805000 1663.620000 5.945000 1663.760000 ;
    END
  END mem_rsp_data[285]
  PIN mem_rsp_data[284]
    DIRECTION INPUT ;
    USE SIGNAL ;
    PORT
      LAYER metal4 ;
        RECT 11.405000 1663.620000 11.545000 1663.760000 ;
    END
  END mem_rsp_data[284]
  PIN mem_rsp_data[283]
    DIRECTION INPUT ;
    USE SIGNAL ;
    PORT
      LAYER metal4 ;
        RECT 17.005000 1663.620000 17.145000 1663.760000 ;
    END
  END mem_rsp_data[283]
  PIN mem_rsp_data[282]
    DIRECTION INPUT ;
    USE SIGNAL ;
    PORT
      LAYER metal4 ;
        RECT 22.605000 1663.620000 22.745000 1663.760000 ;
    END
  END mem_rsp_data[282]
  PIN mem_rsp_data[281]
    DIRECTION INPUT ;
    USE SIGNAL ;
    PORT
      LAYER metal4 ;
        RECT 28.205000 1663.620000 28.345000 1663.760000 ;
    END
  END mem_rsp_data[281]
  PIN mem_rsp_data[280]
    DIRECTION INPUT ;
    USE SIGNAL ;
    PORT
      LAYER metal4 ;
        RECT 33.805000 1663.620000 33.945000 1663.760000 ;
    END
  END mem_rsp_data[280]
  PIN mem_rsp_data[279]
    DIRECTION INPUT ;
    USE SIGNAL ;
    PORT
      LAYER metal4 ;
        RECT 39.405000 1663.620000 39.545000 1663.760000 ;
    END
  END mem_rsp_data[279]
  PIN mem_rsp_data[278]
    DIRECTION INPUT ;
    USE SIGNAL ;
    PORT
      LAYER metal4 ;
        RECT 45.285000 1663.620000 45.425000 1663.760000 ;
    END
  END mem_rsp_data[278]
  PIN mem_rsp_data[277]
    DIRECTION INPUT ;
    USE SIGNAL ;
    PORT
      LAYER metal4 ;
        RECT 50.885000 1663.620000 51.025000 1663.760000 ;
    END
  END mem_rsp_data[277]
  PIN mem_rsp_data[276]
    DIRECTION INPUT ;
    USE SIGNAL ;
    PORT
      LAYER metal4 ;
        RECT 56.485000 1663.620000 56.625000 1663.760000 ;
    END
  END mem_rsp_data[276]
  PIN mem_rsp_data[275]
    DIRECTION INPUT ;
    USE SIGNAL ;
    PORT
      LAYER metal4 ;
        RECT 62.085000 1663.620000 62.225000 1663.760000 ;
    END
  END mem_rsp_data[275]
  PIN mem_rsp_data[274]
    DIRECTION INPUT ;
    USE SIGNAL ;
    PORT
      LAYER metal4 ;
        RECT 67.685000 1663.620000 67.825000 1663.760000 ;
    END
  END mem_rsp_data[274]
  PIN mem_rsp_data[273]
    DIRECTION INPUT ;
    USE SIGNAL ;
    PORT
      LAYER metal4 ;
        RECT 73.285000 1663.620000 73.425000 1663.760000 ;
    END
  END mem_rsp_data[273]
  PIN mem_rsp_data[272]
    DIRECTION INPUT ;
    USE SIGNAL ;
    PORT
      LAYER metal4 ;
        RECT 78.885000 1663.620000 79.025000 1663.760000 ;
    END
  END mem_rsp_data[272]
  PIN mem_rsp_data[271]
    DIRECTION INPUT ;
    USE SIGNAL ;
    PORT
      LAYER metal4 ;
        RECT 84.485000 1663.620000 84.625000 1663.760000 ;
    END
  END mem_rsp_data[271]
  PIN mem_rsp_data[270]
    DIRECTION INPUT ;
    USE SIGNAL ;
    PORT
      LAYER metal4 ;
        RECT 90.365000 1663.620000 90.505000 1663.760000 ;
    END
  END mem_rsp_data[270]
  PIN mem_rsp_data[269]
    DIRECTION INPUT ;
    USE SIGNAL ;
    PORT
      LAYER metal4 ;
        RECT 95.965000 1663.620000 96.105000 1663.760000 ;
    END
  END mem_rsp_data[269]
  PIN mem_rsp_data[268]
    DIRECTION INPUT ;
    USE SIGNAL ;
    PORT
      LAYER metal4 ;
        RECT 101.565000 1663.620000 101.705000 1663.760000 ;
    END
  END mem_rsp_data[268]
  PIN mem_rsp_data[267]
    DIRECTION INPUT ;
    USE SIGNAL ;
    PORT
      LAYER metal4 ;
        RECT 107.165000 1663.620000 107.305000 1663.760000 ;
    END
  END mem_rsp_data[267]
  PIN mem_rsp_data[266]
    DIRECTION INPUT ;
    USE SIGNAL ;
    PORT
      LAYER metal4 ;
        RECT 112.765000 1663.620000 112.905000 1663.760000 ;
    END
  END mem_rsp_data[266]
  PIN mem_rsp_data[265]
    DIRECTION INPUT ;
    USE SIGNAL ;
    PORT
      LAYER metal4 ;
        RECT 118.365000 1663.620000 118.505000 1663.760000 ;
    END
  END mem_rsp_data[265]
  PIN mem_rsp_data[264]
    DIRECTION INPUT ;
    USE SIGNAL ;
    PORT
      LAYER metal4 ;
        RECT 123.965000 1663.620000 124.105000 1663.760000 ;
    END
  END mem_rsp_data[264]
  PIN mem_rsp_data[263]
    DIRECTION INPUT ;
    USE SIGNAL ;
    PORT
      LAYER metal4 ;
        RECT 129.845000 1663.620000 129.985000 1663.760000 ;
    END
  END mem_rsp_data[263]
  PIN mem_rsp_data[262]
    DIRECTION INPUT ;
    USE SIGNAL ;
    PORT
      LAYER metal4 ;
        RECT 135.445000 1663.620000 135.585000 1663.760000 ;
    END
  END mem_rsp_data[262]
  PIN mem_rsp_data[261]
    DIRECTION INPUT ;
    USE SIGNAL ;
    PORT
      LAYER metal4 ;
        RECT 141.045000 1663.620000 141.185000 1663.760000 ;
    END
  END mem_rsp_data[261]
  PIN mem_rsp_data[260]
    DIRECTION INPUT ;
    USE SIGNAL ;
    PORT
      LAYER metal4 ;
        RECT 146.645000 1663.620000 146.785000 1663.760000 ;
    END
  END mem_rsp_data[260]
  PIN mem_rsp_data[259]
    DIRECTION INPUT ;
    USE SIGNAL ;
    PORT
      LAYER metal4 ;
        RECT 152.245000 1663.620000 152.385000 1663.760000 ;
    END
  END mem_rsp_data[259]
  PIN mem_rsp_data[258]
    DIRECTION INPUT ;
    USE SIGNAL ;
    PORT
      LAYER metal4 ;
        RECT 157.845000 1663.620000 157.985000 1663.760000 ;
    END
  END mem_rsp_data[258]
  PIN mem_rsp_data[257]
    DIRECTION INPUT ;
    USE SIGNAL ;
    PORT
      LAYER metal4 ;
        RECT 163.445000 1663.620000 163.585000 1663.760000 ;
    END
  END mem_rsp_data[257]
  PIN mem_rsp_data[256]
    DIRECTION INPUT ;
    USE SIGNAL ;
    PORT
      LAYER metal4 ;
        RECT 169.045000 1663.620000 169.185000 1663.760000 ;
    END
  END mem_rsp_data[256]
  PIN mem_rsp_data[255]
    DIRECTION INPUT ;
    USE SIGNAL ;
    PORT
      LAYER metal4 ;
        RECT 174.925000 1663.620000 175.065000 1663.760000 ;
    END
  END mem_rsp_data[255]
  PIN mem_rsp_data[254]
    DIRECTION INPUT ;
    USE SIGNAL ;
    PORT
      LAYER metal4 ;
        RECT 180.525000 1663.620000 180.665000 1663.760000 ;
    END
  END mem_rsp_data[254]
  PIN mem_rsp_data[253]
    DIRECTION INPUT ;
    USE SIGNAL ;
    PORT
      LAYER metal4 ;
        RECT 186.125000 1663.620000 186.265000 1663.760000 ;
    END
  END mem_rsp_data[253]
  PIN mem_rsp_data[252]
    DIRECTION INPUT ;
    USE SIGNAL ;
    PORT
      LAYER metal4 ;
        RECT 191.725000 1663.620000 191.865000 1663.760000 ;
    END
  END mem_rsp_data[252]
  PIN mem_rsp_data[251]
    DIRECTION INPUT ;
    USE SIGNAL ;
    PORT
      LAYER metal4 ;
        RECT 197.325000 1663.620000 197.465000 1663.760000 ;
    END
  END mem_rsp_data[251]
  PIN mem_rsp_data[250]
    DIRECTION INPUT ;
    USE SIGNAL ;
    PORT
      LAYER metal4 ;
        RECT 202.925000 1663.620000 203.065000 1663.760000 ;
    END
  END mem_rsp_data[250]
  PIN mem_rsp_data[249]
    DIRECTION INPUT ;
    USE SIGNAL ;
    PORT
      LAYER metal4 ;
        RECT 208.525000 1663.620000 208.665000 1663.760000 ;
    END
  END mem_rsp_data[249]
  PIN mem_rsp_data[248]
    DIRECTION INPUT ;
    USE SIGNAL ;
    PORT
      LAYER metal4 ;
        RECT 214.405000 1663.620000 214.545000 1663.760000 ;
    END
  END mem_rsp_data[248]
  PIN mem_rsp_data[247]
    DIRECTION INPUT ;
    USE SIGNAL ;
    PORT
      LAYER metal4 ;
        RECT 220.005000 1663.620000 220.145000 1663.760000 ;
    END
  END mem_rsp_data[247]
  PIN mem_rsp_data[246]
    DIRECTION INPUT ;
    USE SIGNAL ;
    PORT
      LAYER metal4 ;
        RECT 225.605000 1663.620000 225.745000 1663.760000 ;
    END
  END mem_rsp_data[246]
  PIN mem_rsp_data[245]
    DIRECTION INPUT ;
    USE SIGNAL ;
    PORT
      LAYER metal4 ;
        RECT 231.205000 1663.620000 231.345000 1663.760000 ;
    END
  END mem_rsp_data[245]
  PIN mem_rsp_data[244]
    DIRECTION INPUT ;
    USE SIGNAL ;
    PORT
      LAYER metal4 ;
        RECT 236.805000 1663.620000 236.945000 1663.760000 ;
    END
  END mem_rsp_data[244]
  PIN mem_rsp_data[243]
    DIRECTION INPUT ;
    USE SIGNAL ;
    PORT
      LAYER metal4 ;
        RECT 242.405000 1663.620000 242.545000 1663.760000 ;
    END
  END mem_rsp_data[243]
  PIN mem_rsp_data[242]
    DIRECTION INPUT ;
    USE SIGNAL ;
    PORT
      LAYER metal4 ;
        RECT 248.005000 1663.620000 248.145000 1663.760000 ;
    END
  END mem_rsp_data[242]
  PIN mem_rsp_data[241]
    DIRECTION INPUT ;
    USE SIGNAL ;
    PORT
      LAYER metal4 ;
        RECT 253.605000 1663.620000 253.745000 1663.760000 ;
    END
  END mem_rsp_data[241]
  PIN mem_rsp_data[240]
    DIRECTION INPUT ;
    USE SIGNAL ;
    PORT
      LAYER metal4 ;
        RECT 259.485000 1663.620000 259.625000 1663.760000 ;
    END
  END mem_rsp_data[240]
  PIN mem_rsp_data[239]
    DIRECTION INPUT ;
    USE SIGNAL ;
    PORT
      LAYER metal4 ;
        RECT 265.085000 1663.620000 265.225000 1663.760000 ;
    END
  END mem_rsp_data[239]
  PIN mem_rsp_data[238]
    DIRECTION INPUT ;
    USE SIGNAL ;
    PORT
      LAYER metal4 ;
        RECT 270.685000 1663.620000 270.825000 1663.760000 ;
    END
  END mem_rsp_data[238]
  PIN mem_rsp_data[237]
    DIRECTION INPUT ;
    USE SIGNAL ;
    PORT
      LAYER metal4 ;
        RECT 276.285000 1663.620000 276.425000 1663.760000 ;
    END
  END mem_rsp_data[237]
  PIN mem_rsp_data[236]
    DIRECTION INPUT ;
    USE SIGNAL ;
    PORT
      LAYER metal4 ;
        RECT 281.885000 1663.620000 282.025000 1663.760000 ;
    END
  END mem_rsp_data[236]
  PIN mem_rsp_data[235]
    DIRECTION INPUT ;
    USE SIGNAL ;
    PORT
      LAYER metal4 ;
        RECT 287.485000 1663.620000 287.625000 1663.760000 ;
    END
  END mem_rsp_data[235]
  PIN mem_rsp_data[234]
    DIRECTION INPUT ;
    USE SIGNAL ;
    PORT
      LAYER metal4 ;
        RECT 293.085000 1663.620000 293.225000 1663.760000 ;
    END
  END mem_rsp_data[234]
  PIN mem_rsp_data[233]
    DIRECTION INPUT ;
    USE SIGNAL ;
    PORT
      LAYER metal4 ;
        RECT 298.965000 1663.620000 299.105000 1663.760000 ;
    END
  END mem_rsp_data[233]
  PIN mem_rsp_data[232]
    DIRECTION INPUT ;
    USE SIGNAL ;
    PORT
      LAYER metal4 ;
        RECT 304.565000 1663.620000 304.705000 1663.760000 ;
    END
  END mem_rsp_data[232]
  PIN mem_rsp_data[231]
    DIRECTION INPUT ;
    USE SIGNAL ;
    PORT
      LAYER metal4 ;
        RECT 310.165000 1663.620000 310.305000 1663.760000 ;
    END
  END mem_rsp_data[231]
  PIN mem_rsp_data[230]
    DIRECTION INPUT ;
    USE SIGNAL ;
    PORT
      LAYER metal4 ;
        RECT 315.765000 1663.620000 315.905000 1663.760000 ;
    END
  END mem_rsp_data[230]
  PIN mem_rsp_data[229]
    DIRECTION INPUT ;
    USE SIGNAL ;
    PORT
      LAYER metal4 ;
        RECT 321.365000 1663.620000 321.505000 1663.760000 ;
    END
  END mem_rsp_data[229]
  PIN mem_rsp_data[228]
    DIRECTION INPUT ;
    USE SIGNAL ;
    PORT
      LAYER metal4 ;
        RECT 326.965000 1663.620000 327.105000 1663.760000 ;
    END
  END mem_rsp_data[228]
  PIN mem_rsp_data[227]
    DIRECTION INPUT ;
    USE SIGNAL ;
    PORT
      LAYER metal4 ;
        RECT 332.565000 1663.620000 332.705000 1663.760000 ;
    END
  END mem_rsp_data[227]
  PIN mem_rsp_data[226]
    DIRECTION INPUT ;
    USE SIGNAL ;
    PORT
      LAYER metal4 ;
        RECT 338.165000 1663.620000 338.305000 1663.760000 ;
    END
  END mem_rsp_data[226]
  PIN mem_rsp_data[225]
    DIRECTION INPUT ;
    USE SIGNAL ;
    PORT
      LAYER metal4 ;
        RECT 344.045000 1663.620000 344.185000 1663.760000 ;
    END
  END mem_rsp_data[225]
  PIN mem_rsp_data[224]
    DIRECTION INPUT ;
    USE SIGNAL ;
    PORT
      LAYER metal4 ;
        RECT 349.645000 1663.620000 349.785000 1663.760000 ;
    END
  END mem_rsp_data[224]
  PIN mem_rsp_data[223]
    DIRECTION INPUT ;
    USE SIGNAL ;
    PORT
      LAYER metal4 ;
        RECT 355.245000 1663.620000 355.385000 1663.760000 ;
    END
  END mem_rsp_data[223]
  PIN mem_rsp_data[222]
    DIRECTION INPUT ;
    USE SIGNAL ;
    PORT
      LAYER metal4 ;
        RECT 360.845000 1663.620000 360.985000 1663.760000 ;
    END
  END mem_rsp_data[222]
  PIN mem_rsp_data[221]
    DIRECTION INPUT ;
    USE SIGNAL ;
    PORT
      LAYER metal4 ;
        RECT 366.445000 1663.620000 366.585000 1663.760000 ;
    END
  END mem_rsp_data[221]
  PIN mem_rsp_data[220]
    DIRECTION INPUT ;
    USE SIGNAL ;
    PORT
      LAYER metal4 ;
        RECT 372.045000 1663.620000 372.185000 1663.760000 ;
    END
  END mem_rsp_data[220]
  PIN mem_rsp_data[219]
    DIRECTION INPUT ;
    USE SIGNAL ;
    PORT
      LAYER metal4 ;
        RECT 377.645000 1663.620000 377.785000 1663.760000 ;
    END
  END mem_rsp_data[219]
  PIN mem_rsp_data[218]
    DIRECTION INPUT ;
    USE SIGNAL ;
    PORT
      LAYER metal4 ;
        RECT 383.245000 1663.620000 383.385000 1663.760000 ;
    END
  END mem_rsp_data[218]
  PIN mem_rsp_data[217]
    DIRECTION INPUT ;
    USE SIGNAL ;
    PORT
      LAYER metal4 ;
        RECT 389.125000 1663.620000 389.265000 1663.760000 ;
    END
  END mem_rsp_data[217]
  PIN mem_rsp_data[216]
    DIRECTION INPUT ;
    USE SIGNAL ;
    PORT
      LAYER metal4 ;
        RECT 394.725000 1663.620000 394.865000 1663.760000 ;
    END
  END mem_rsp_data[216]
  PIN mem_rsp_data[215]
    DIRECTION INPUT ;
    USE SIGNAL ;
    PORT
      LAYER metal4 ;
        RECT 400.325000 1663.620000 400.465000 1663.760000 ;
    END
  END mem_rsp_data[215]
  PIN mem_rsp_data[214]
    DIRECTION INPUT ;
    USE SIGNAL ;
    PORT
      LAYER metal4 ;
        RECT 405.925000 1663.620000 406.065000 1663.760000 ;
    END
  END mem_rsp_data[214]
  PIN mem_rsp_data[213]
    DIRECTION INPUT ;
    USE SIGNAL ;
    PORT
      LAYER metal4 ;
        RECT 411.525000 1663.620000 411.665000 1663.760000 ;
    END
  END mem_rsp_data[213]
  PIN mem_rsp_data[212]
    DIRECTION INPUT ;
    USE SIGNAL ;
    PORT
      LAYER metal4 ;
        RECT 417.125000 1663.620000 417.265000 1663.760000 ;
    END
  END mem_rsp_data[212]
  PIN mem_rsp_data[211]
    DIRECTION INPUT ;
    USE SIGNAL ;
    PORT
      LAYER metal4 ;
        RECT 422.725000 1663.620000 422.865000 1663.760000 ;
    END
  END mem_rsp_data[211]
  PIN mem_rsp_data[210]
    DIRECTION INPUT ;
    USE SIGNAL ;
    PORT
      LAYER metal4 ;
        RECT 428.605000 1663.620000 428.745000 1663.760000 ;
    END
  END mem_rsp_data[210]
  PIN mem_rsp_data[209]
    DIRECTION INPUT ;
    USE SIGNAL ;
    PORT
      LAYER metal4 ;
        RECT 434.205000 1663.620000 434.345000 1663.760000 ;
    END
  END mem_rsp_data[209]
  PIN mem_rsp_data[208]
    DIRECTION INPUT ;
    USE SIGNAL ;
    PORT
      LAYER metal4 ;
        RECT 439.805000 1663.620000 439.945000 1663.760000 ;
    END
  END mem_rsp_data[208]
  PIN mem_rsp_data[207]
    DIRECTION INPUT ;
    USE SIGNAL ;
    PORT
      LAYER metal4 ;
        RECT 445.405000 1663.620000 445.545000 1663.760000 ;
    END
  END mem_rsp_data[207]
  PIN mem_rsp_data[206]
    DIRECTION INPUT ;
    USE SIGNAL ;
    PORT
      LAYER metal4 ;
        RECT 451.005000 1663.620000 451.145000 1663.760000 ;
    END
  END mem_rsp_data[206]
  PIN mem_rsp_data[205]
    DIRECTION INPUT ;
    USE SIGNAL ;
    PORT
      LAYER metal4 ;
        RECT 456.605000 1663.620000 456.745000 1663.760000 ;
    END
  END mem_rsp_data[205]
  PIN mem_rsp_data[204]
    DIRECTION INPUT ;
    USE SIGNAL ;
    PORT
      LAYER metal4 ;
        RECT 462.205000 1663.620000 462.345000 1663.760000 ;
    END
  END mem_rsp_data[204]
  PIN mem_rsp_data[203]
    DIRECTION INPUT ;
    USE SIGNAL ;
    PORT
      LAYER metal4 ;
        RECT 467.805000 1663.620000 467.945000 1663.760000 ;
    END
  END mem_rsp_data[203]
  PIN mem_rsp_data[202]
    DIRECTION INPUT ;
    USE SIGNAL ;
    PORT
      LAYER metal4 ;
        RECT 473.685000 1663.620000 473.825000 1663.760000 ;
    END
  END mem_rsp_data[202]
  PIN mem_rsp_data[201]
    DIRECTION INPUT ;
    USE SIGNAL ;
    PORT
      LAYER metal4 ;
        RECT 479.285000 1663.620000 479.425000 1663.760000 ;
    END
  END mem_rsp_data[201]
  PIN mem_rsp_data[200]
    DIRECTION INPUT ;
    USE SIGNAL ;
    PORT
      LAYER metal4 ;
        RECT 484.885000 1663.620000 485.025000 1663.760000 ;
    END
  END mem_rsp_data[200]
  PIN mem_rsp_data[199]
    DIRECTION INPUT ;
    USE SIGNAL ;
    PORT
      LAYER metal4 ;
        RECT 490.485000 1663.620000 490.625000 1663.760000 ;
    END
  END mem_rsp_data[199]
  PIN mem_rsp_data[198]
    DIRECTION INPUT ;
    USE SIGNAL ;
    PORT
      LAYER metal4 ;
        RECT 496.085000 1663.620000 496.225000 1663.760000 ;
    END
  END mem_rsp_data[198]
  PIN mem_rsp_data[197]
    DIRECTION INPUT ;
    USE SIGNAL ;
    PORT
      LAYER metal4 ;
        RECT 501.685000 1663.620000 501.825000 1663.760000 ;
    END
  END mem_rsp_data[197]
  PIN mem_rsp_data[196]
    DIRECTION INPUT ;
    USE SIGNAL ;
    PORT
      LAYER metal4 ;
        RECT 507.285000 1663.620000 507.425000 1663.760000 ;
    END
  END mem_rsp_data[196]
  PIN mem_rsp_data[195]
    DIRECTION INPUT ;
    USE SIGNAL ;
    PORT
      LAYER metal4 ;
        RECT 513.165000 1663.620000 513.305000 1663.760000 ;
    END
  END mem_rsp_data[195]
  PIN mem_rsp_data[194]
    DIRECTION INPUT ;
    USE SIGNAL ;
    PORT
      LAYER metal4 ;
        RECT 518.765000 1663.620000 518.905000 1663.760000 ;
    END
  END mem_rsp_data[194]
  PIN mem_rsp_data[193]
    DIRECTION INPUT ;
    USE SIGNAL ;
    PORT
      LAYER metal4 ;
        RECT 524.365000 1663.620000 524.505000 1663.760000 ;
    END
  END mem_rsp_data[193]
  PIN mem_rsp_data[192]
    DIRECTION INPUT ;
    USE SIGNAL ;
    PORT
      LAYER metal4 ;
        RECT 529.965000 1663.620000 530.105000 1663.760000 ;
    END
  END mem_rsp_data[192]
  PIN mem_rsp_data[191]
    DIRECTION INPUT ;
    USE SIGNAL ;
    PORT
      LAYER metal4 ;
        RECT 535.565000 1663.620000 535.705000 1663.760000 ;
    END
  END mem_rsp_data[191]
  PIN mem_rsp_data[190]
    DIRECTION INPUT ;
    USE SIGNAL ;
    PORT
      LAYER metal4 ;
        RECT 541.165000 1663.620000 541.305000 1663.760000 ;
    END
  END mem_rsp_data[190]
  PIN mem_rsp_data[189]
    DIRECTION INPUT ;
    USE SIGNAL ;
    PORT
      LAYER metal4 ;
        RECT 546.765000 1663.620000 546.905000 1663.760000 ;
    END
  END mem_rsp_data[189]
  PIN mem_rsp_data[188]
    DIRECTION INPUT ;
    USE SIGNAL ;
    PORT
      LAYER metal4 ;
        RECT 552.365000 1663.620000 552.505000 1663.760000 ;
    END
  END mem_rsp_data[188]
  PIN mem_rsp_data[187]
    DIRECTION INPUT ;
    USE SIGNAL ;
    PORT
      LAYER metal4 ;
        RECT 558.245000 1663.620000 558.385000 1663.760000 ;
    END
  END mem_rsp_data[187]
  PIN mem_rsp_data[186]
    DIRECTION INPUT ;
    USE SIGNAL ;
    PORT
      LAYER metal4 ;
        RECT 563.845000 1663.620000 563.985000 1663.760000 ;
    END
  END mem_rsp_data[186]
  PIN mem_rsp_data[185]
    DIRECTION INPUT ;
    USE SIGNAL ;
    PORT
      LAYER metal4 ;
        RECT 569.445000 1663.620000 569.585000 1663.760000 ;
    END
  END mem_rsp_data[185]
  PIN mem_rsp_data[184]
    DIRECTION INPUT ;
    USE SIGNAL ;
    PORT
      LAYER metal4 ;
        RECT 575.045000 1663.620000 575.185000 1663.760000 ;
    END
  END mem_rsp_data[184]
  PIN mem_rsp_data[183]
    DIRECTION INPUT ;
    USE SIGNAL ;
    PORT
      LAYER metal4 ;
        RECT 580.645000 1663.620000 580.785000 1663.760000 ;
    END
  END mem_rsp_data[183]
  PIN mem_rsp_data[182]
    DIRECTION INPUT ;
    USE SIGNAL ;
    PORT
      LAYER metal4 ;
        RECT 586.245000 1663.620000 586.385000 1663.760000 ;
    END
  END mem_rsp_data[182]
  PIN mem_rsp_data[181]
    DIRECTION INPUT ;
    USE SIGNAL ;
    PORT
      LAYER metal4 ;
        RECT 591.845000 1663.620000 591.985000 1663.760000 ;
    END
  END mem_rsp_data[181]
  PIN mem_rsp_data[180]
    DIRECTION INPUT ;
    USE SIGNAL ;
    PORT
      LAYER metal4 ;
        RECT 597.725000 1663.620000 597.865000 1663.760000 ;
    END
  END mem_rsp_data[180]
  PIN mem_rsp_data[179]
    DIRECTION INPUT ;
    USE SIGNAL ;
    PORT
      LAYER metal4 ;
        RECT 603.325000 1663.620000 603.465000 1663.760000 ;
    END
  END mem_rsp_data[179]
  PIN mem_rsp_data[178]
    DIRECTION INPUT ;
    USE SIGNAL ;
    PORT
      LAYER metal4 ;
        RECT 608.925000 1663.620000 609.065000 1663.760000 ;
    END
  END mem_rsp_data[178]
  PIN mem_rsp_data[177]
    DIRECTION INPUT ;
    USE SIGNAL ;
    PORT
      LAYER metal4 ;
        RECT 614.525000 1663.620000 614.665000 1663.760000 ;
    END
  END mem_rsp_data[177]
  PIN mem_rsp_data[176]
    DIRECTION INPUT ;
    USE SIGNAL ;
    PORT
      LAYER metal4 ;
        RECT 620.125000 1663.620000 620.265000 1663.760000 ;
    END
  END mem_rsp_data[176]
  PIN mem_rsp_data[175]
    DIRECTION INPUT ;
    USE SIGNAL ;
    PORT
      LAYER metal4 ;
        RECT 625.725000 1663.620000 625.865000 1663.760000 ;
    END
  END mem_rsp_data[175]
  PIN mem_rsp_data[174]
    DIRECTION INPUT ;
    USE SIGNAL ;
    PORT
      LAYER metal4 ;
        RECT 631.325000 1663.620000 631.465000 1663.760000 ;
    END
  END mem_rsp_data[174]
  PIN mem_rsp_data[173]
    DIRECTION INPUT ;
    USE SIGNAL ;
    PORT
      LAYER metal4 ;
        RECT 636.925000 1663.620000 637.065000 1663.760000 ;
    END
  END mem_rsp_data[173]
  PIN mem_rsp_data[172]
    DIRECTION INPUT ;
    USE SIGNAL ;
    PORT
      LAYER metal4 ;
        RECT 642.805000 1663.620000 642.945000 1663.760000 ;
    END
  END mem_rsp_data[172]
  PIN mem_rsp_data[171]
    DIRECTION INPUT ;
    USE SIGNAL ;
    PORT
      LAYER metal4 ;
        RECT 648.405000 1663.620000 648.545000 1663.760000 ;
    END
  END mem_rsp_data[171]
  PIN mem_rsp_data[170]
    DIRECTION INPUT ;
    USE SIGNAL ;
    PORT
      LAYER metal4 ;
        RECT 654.005000 1663.620000 654.145000 1663.760000 ;
    END
  END mem_rsp_data[170]
  PIN mem_rsp_data[169]
    DIRECTION INPUT ;
    USE SIGNAL ;
    PORT
      LAYER metal4 ;
        RECT 659.605000 1663.620000 659.745000 1663.760000 ;
    END
  END mem_rsp_data[169]
  PIN mem_rsp_data[168]
    DIRECTION INPUT ;
    USE SIGNAL ;
    PORT
      LAYER metal4 ;
        RECT 665.205000 1663.620000 665.345000 1663.760000 ;
    END
  END mem_rsp_data[168]
  PIN mem_rsp_data[167]
    DIRECTION INPUT ;
    USE SIGNAL ;
    PORT
      LAYER metal4 ;
        RECT 670.805000 1663.620000 670.945000 1663.760000 ;
    END
  END mem_rsp_data[167]
  PIN mem_rsp_data[166]
    DIRECTION INPUT ;
    USE SIGNAL ;
    PORT
      LAYER metal4 ;
        RECT 676.405000 1663.620000 676.545000 1663.760000 ;
    END
  END mem_rsp_data[166]
  PIN mem_rsp_data[165]
    DIRECTION INPUT ;
    USE SIGNAL ;
    PORT
      LAYER metal4 ;
        RECT 682.005000 1663.620000 682.145000 1663.760000 ;
    END
  END mem_rsp_data[165]
  PIN mem_rsp_data[164]
    DIRECTION INPUT ;
    USE SIGNAL ;
    PORT
      LAYER metal4 ;
        RECT 687.885000 1663.620000 688.025000 1663.760000 ;
    END
  END mem_rsp_data[164]
  PIN mem_rsp_data[163]
    DIRECTION INPUT ;
    USE SIGNAL ;
    PORT
      LAYER metal4 ;
        RECT 693.485000 1663.620000 693.625000 1663.760000 ;
    END
  END mem_rsp_data[163]
  PIN mem_rsp_data[162]
    DIRECTION INPUT ;
    USE SIGNAL ;
    PORT
      LAYER metal4 ;
        RECT 699.085000 1663.620000 699.225000 1663.760000 ;
    END
  END mem_rsp_data[162]
  PIN mem_rsp_data[161]
    DIRECTION INPUT ;
    USE SIGNAL ;
    PORT
      LAYER metal4 ;
        RECT 704.685000 1663.620000 704.825000 1663.760000 ;
    END
  END mem_rsp_data[161]
  PIN mem_rsp_data[160]
    DIRECTION INPUT ;
    USE SIGNAL ;
    PORT
      LAYER metal4 ;
        RECT 710.285000 1663.620000 710.425000 1663.760000 ;
    END
  END mem_rsp_data[160]
  PIN mem_rsp_data[159]
    DIRECTION INPUT ;
    USE SIGNAL ;
    PORT
      LAYER metal4 ;
        RECT 715.885000 1663.620000 716.025000 1663.760000 ;
    END
  END mem_rsp_data[159]
  PIN mem_rsp_data[158]
    DIRECTION INPUT ;
    USE SIGNAL ;
    PORT
      LAYER metal4 ;
        RECT 721.485000 1663.620000 721.625000 1663.760000 ;
    END
  END mem_rsp_data[158]
  PIN mem_rsp_data[157]
    DIRECTION INPUT ;
    USE SIGNAL ;
    PORT
      LAYER metal4 ;
        RECT 727.365000 1663.620000 727.505000 1663.760000 ;
    END
  END mem_rsp_data[157]
  PIN mem_rsp_data[156]
    DIRECTION INPUT ;
    USE SIGNAL ;
    PORT
      LAYER metal4 ;
        RECT 732.965000 1663.620000 733.105000 1663.760000 ;
    END
  END mem_rsp_data[156]
  PIN mem_rsp_data[155]
    DIRECTION INPUT ;
    USE SIGNAL ;
    PORT
      LAYER metal4 ;
        RECT 738.565000 1663.620000 738.705000 1663.760000 ;
    END
  END mem_rsp_data[155]
  PIN mem_rsp_data[154]
    DIRECTION INPUT ;
    USE SIGNAL ;
    PORT
      LAYER metal4 ;
        RECT 744.165000 1663.620000 744.305000 1663.760000 ;
    END
  END mem_rsp_data[154]
  PIN mem_rsp_data[153]
    DIRECTION INPUT ;
    USE SIGNAL ;
    PORT
      LAYER metal4 ;
        RECT 749.765000 1663.620000 749.905000 1663.760000 ;
    END
  END mem_rsp_data[153]
  PIN mem_rsp_data[152]
    DIRECTION INPUT ;
    USE SIGNAL ;
    PORT
      LAYER metal4 ;
        RECT 755.365000 1663.620000 755.505000 1663.760000 ;
    END
  END mem_rsp_data[152]
  PIN mem_rsp_data[151]
    DIRECTION INPUT ;
    USE SIGNAL ;
    PORT
      LAYER metal4 ;
        RECT 760.965000 1663.620000 761.105000 1663.760000 ;
    END
  END mem_rsp_data[151]
  PIN mem_rsp_data[150]
    DIRECTION INPUT ;
    USE SIGNAL ;
    PORT
      LAYER metal4 ;
        RECT 766.565000 1663.620000 766.705000 1663.760000 ;
    END
  END mem_rsp_data[150]
  PIN mem_rsp_data[149]
    DIRECTION INPUT ;
    USE SIGNAL ;
    PORT
      LAYER metal4 ;
        RECT 772.445000 1663.620000 772.585000 1663.760000 ;
    END
  END mem_rsp_data[149]
  PIN mem_rsp_data[148]
    DIRECTION INPUT ;
    USE SIGNAL ;
    PORT
      LAYER metal4 ;
        RECT 778.045000 1663.620000 778.185000 1663.760000 ;
    END
  END mem_rsp_data[148]
  PIN mem_rsp_data[147]
    DIRECTION INPUT ;
    USE SIGNAL ;
    PORT
      LAYER metal4 ;
        RECT 783.645000 1663.620000 783.785000 1663.760000 ;
    END
  END mem_rsp_data[147]
  PIN mem_rsp_data[146]
    DIRECTION INPUT ;
    USE SIGNAL ;
    PORT
      LAYER metal4 ;
        RECT 789.245000 1663.620000 789.385000 1663.760000 ;
    END
  END mem_rsp_data[146]
  PIN mem_rsp_data[145]
    DIRECTION INPUT ;
    USE SIGNAL ;
    PORT
      LAYER metal4 ;
        RECT 794.845000 1663.620000 794.985000 1663.760000 ;
    END
  END mem_rsp_data[145]
  PIN mem_rsp_data[144]
    DIRECTION INPUT ;
    USE SIGNAL ;
    PORT
      LAYER metal4 ;
        RECT 800.445000 1663.620000 800.585000 1663.760000 ;
    END
  END mem_rsp_data[144]
  PIN mem_rsp_data[143]
    DIRECTION INPUT ;
    USE SIGNAL ;
    PORT
      LAYER metal4 ;
        RECT 806.045000 1663.620000 806.185000 1663.760000 ;
    END
  END mem_rsp_data[143]
  PIN mem_rsp_data[142]
    DIRECTION INPUT ;
    USE SIGNAL ;
    PORT
      LAYER metal4 ;
        RECT 811.925000 1663.620000 812.065000 1663.760000 ;
    END
  END mem_rsp_data[142]
  PIN mem_rsp_data[141]
    DIRECTION INPUT ;
    USE SIGNAL ;
    PORT
      LAYER metal4 ;
        RECT 817.525000 1663.620000 817.665000 1663.760000 ;
    END
  END mem_rsp_data[141]
  PIN mem_rsp_data[140]
    DIRECTION INPUT ;
    USE SIGNAL ;
    PORT
      LAYER metal4 ;
        RECT 823.125000 1663.620000 823.265000 1663.760000 ;
    END
  END mem_rsp_data[140]
  PIN mem_rsp_data[139]
    DIRECTION INPUT ;
    USE SIGNAL ;
    PORT
      LAYER metal4 ;
        RECT 828.725000 1663.620000 828.865000 1663.760000 ;
    END
  END mem_rsp_data[139]
  PIN mem_rsp_data[138]
    DIRECTION INPUT ;
    USE SIGNAL ;
    PORT
      LAYER metal4 ;
        RECT 834.325000 1663.620000 834.465000 1663.760000 ;
    END
  END mem_rsp_data[138]
  PIN mem_rsp_data[137]
    DIRECTION INPUT ;
    USE SIGNAL ;
    PORT
      LAYER metal4 ;
        RECT 839.925000 1663.620000 840.065000 1663.760000 ;
    END
  END mem_rsp_data[137]
  PIN mem_rsp_data[136]
    DIRECTION INPUT ;
    USE SIGNAL ;
    PORT
      LAYER metal4 ;
        RECT 845.525000 1663.620000 845.665000 1663.760000 ;
    END
  END mem_rsp_data[136]
  PIN mem_rsp_data[135]
    DIRECTION INPUT ;
    USE SIGNAL ;
    PORT
      LAYER metal4 ;
        RECT 851.125000 1663.620000 851.265000 1663.760000 ;
    END
  END mem_rsp_data[135]
  PIN mem_rsp_data[134]
    DIRECTION INPUT ;
    USE SIGNAL ;
    PORT
      LAYER metal4 ;
        RECT 857.005000 1663.620000 857.145000 1663.760000 ;
    END
  END mem_rsp_data[134]
  PIN mem_rsp_data[133]
    DIRECTION INPUT ;
    USE SIGNAL ;
    PORT
      LAYER metal4 ;
        RECT 862.605000 1663.620000 862.745000 1663.760000 ;
    END
  END mem_rsp_data[133]
  PIN mem_rsp_data[132]
    DIRECTION INPUT ;
    USE SIGNAL ;
    PORT
      LAYER metal4 ;
        RECT 868.205000 1663.620000 868.345000 1663.760000 ;
    END
  END mem_rsp_data[132]
  PIN mem_rsp_data[131]
    DIRECTION INPUT ;
    USE SIGNAL ;
    PORT
      LAYER metal4 ;
        RECT 873.805000 1663.620000 873.945000 1663.760000 ;
    END
  END mem_rsp_data[131]
  PIN mem_rsp_data[130]
    DIRECTION INPUT ;
    USE SIGNAL ;
    PORT
      LAYER metal4 ;
        RECT 879.405000 1663.620000 879.545000 1663.760000 ;
    END
  END mem_rsp_data[130]
  PIN mem_rsp_data[129]
    DIRECTION INPUT ;
    USE SIGNAL ;
    PORT
      LAYER metal4 ;
        RECT 885.005000 1663.620000 885.145000 1663.760000 ;
    END
  END mem_rsp_data[129]
  PIN mem_rsp_data[128]
    DIRECTION INPUT ;
    USE SIGNAL ;
    PORT
      LAYER metal4 ;
        RECT 890.605000 1663.620000 890.745000 1663.760000 ;
    END
  END mem_rsp_data[128]
  PIN mem_rsp_data[127]
    DIRECTION INPUT ;
    USE SIGNAL ;
    PORT
      LAYER metal4 ;
        RECT 896.485000 1663.620000 896.625000 1663.760000 ;
    END
  END mem_rsp_data[127]
  PIN mem_rsp_data[126]
    DIRECTION INPUT ;
    USE SIGNAL ;
    PORT
      LAYER metal4 ;
        RECT 902.085000 1663.620000 902.225000 1663.760000 ;
    END
  END mem_rsp_data[126]
  PIN mem_rsp_data[125]
    DIRECTION INPUT ;
    USE SIGNAL ;
    PORT
      LAYER metal4 ;
        RECT 907.685000 1663.620000 907.825000 1663.760000 ;
    END
  END mem_rsp_data[125]
  PIN mem_rsp_data[124]
    DIRECTION INPUT ;
    USE SIGNAL ;
    PORT
      LAYER metal4 ;
        RECT 913.285000 1663.620000 913.425000 1663.760000 ;
    END
  END mem_rsp_data[124]
  PIN mem_rsp_data[123]
    DIRECTION INPUT ;
    USE SIGNAL ;
    PORT
      LAYER metal4 ;
        RECT 918.885000 1663.620000 919.025000 1663.760000 ;
    END
  END mem_rsp_data[123]
  PIN mem_rsp_data[122]
    DIRECTION INPUT ;
    USE SIGNAL ;
    PORT
      LAYER metal4 ;
        RECT 924.485000 1663.620000 924.625000 1663.760000 ;
    END
  END mem_rsp_data[122]
  PIN mem_rsp_data[121]
    DIRECTION INPUT ;
    USE SIGNAL ;
    PORT
      LAYER metal4 ;
        RECT 930.085000 1663.620000 930.225000 1663.760000 ;
    END
  END mem_rsp_data[121]
  PIN mem_rsp_data[120]
    DIRECTION INPUT ;
    USE SIGNAL ;
    PORT
      LAYER metal4 ;
        RECT 935.685000 1663.620000 935.825000 1663.760000 ;
    END
  END mem_rsp_data[120]
  PIN mem_rsp_data[119]
    DIRECTION INPUT ;
    USE SIGNAL ;
    PORT
      LAYER metal4 ;
        RECT 941.565000 1663.620000 941.705000 1663.760000 ;
    END
  END mem_rsp_data[119]
  PIN mem_rsp_data[118]
    DIRECTION INPUT ;
    USE SIGNAL ;
    PORT
      LAYER metal4 ;
        RECT 947.165000 1663.620000 947.305000 1663.760000 ;
    END
  END mem_rsp_data[118]
  PIN mem_rsp_data[117]
    DIRECTION INPUT ;
    USE SIGNAL ;
    PORT
      LAYER metal4 ;
        RECT 952.765000 1663.620000 952.905000 1663.760000 ;
    END
  END mem_rsp_data[117]
  PIN mem_rsp_data[116]
    DIRECTION INPUT ;
    USE SIGNAL ;
    PORT
      LAYER metal4 ;
        RECT 958.365000 1663.620000 958.505000 1663.760000 ;
    END
  END mem_rsp_data[116]
  PIN mem_rsp_data[115]
    DIRECTION INPUT ;
    USE SIGNAL ;
    PORT
      LAYER metal4 ;
        RECT 963.965000 1663.620000 964.105000 1663.760000 ;
    END
  END mem_rsp_data[115]
  PIN mem_rsp_data[114]
    DIRECTION INPUT ;
    USE SIGNAL ;
    PORT
      LAYER metal4 ;
        RECT 969.565000 1663.620000 969.705000 1663.760000 ;
    END
  END mem_rsp_data[114]
  PIN mem_rsp_data[113]
    DIRECTION INPUT ;
    USE SIGNAL ;
    PORT
      LAYER metal4 ;
        RECT 975.165000 1663.620000 975.305000 1663.760000 ;
    END
  END mem_rsp_data[113]
  PIN mem_rsp_data[112]
    DIRECTION INPUT ;
    USE SIGNAL ;
    PORT
      LAYER metal4 ;
        RECT 981.045000 1663.620000 981.185000 1663.760000 ;
    END
  END mem_rsp_data[112]
  PIN mem_rsp_data[111]
    DIRECTION INPUT ;
    USE SIGNAL ;
    PORT
      LAYER metal4 ;
        RECT 986.645000 1663.620000 986.785000 1663.760000 ;
    END
  END mem_rsp_data[111]
  PIN mem_rsp_data[110]
    DIRECTION INPUT ;
    USE SIGNAL ;
    PORT
      LAYER metal4 ;
        RECT 992.245000 1663.620000 992.385000 1663.760000 ;
    END
  END mem_rsp_data[110]
  PIN mem_rsp_data[109]
    DIRECTION INPUT ;
    USE SIGNAL ;
    PORT
      LAYER metal4 ;
        RECT 997.845000 1663.620000 997.985000 1663.760000 ;
    END
  END mem_rsp_data[109]
  PIN mem_rsp_data[108]
    DIRECTION INPUT ;
    USE SIGNAL ;
    PORT
      LAYER metal4 ;
        RECT 1003.445000 1663.620000 1003.585000 1663.760000 ;
    END
  END mem_rsp_data[108]
  PIN mem_rsp_data[107]
    DIRECTION INPUT ;
    USE SIGNAL ;
    PORT
      LAYER metal4 ;
        RECT 1009.045000 1663.620000 1009.185000 1663.760000 ;
    END
  END mem_rsp_data[107]
  PIN mem_rsp_data[106]
    DIRECTION INPUT ;
    USE SIGNAL ;
    PORT
      LAYER metal4 ;
        RECT 1014.645000 1663.620000 1014.785000 1663.760000 ;
    END
  END mem_rsp_data[106]
  PIN mem_rsp_data[105]
    DIRECTION INPUT ;
    USE SIGNAL ;
    PORT
      LAYER metal4 ;
        RECT 1020.245000 1663.620000 1020.385000 1663.760000 ;
    END
  END mem_rsp_data[105]
  PIN mem_rsp_data[104]
    DIRECTION INPUT ;
    USE SIGNAL ;
    PORT
      LAYER metal4 ;
        RECT 1026.125000 1663.620000 1026.265000 1663.760000 ;
    END
  END mem_rsp_data[104]
  PIN mem_rsp_data[103]
    DIRECTION INPUT ;
    USE SIGNAL ;
    PORT
      LAYER metal4 ;
        RECT 1031.725000 1663.620000 1031.865000 1663.760000 ;
    END
  END mem_rsp_data[103]
  PIN mem_rsp_data[102]
    DIRECTION INPUT ;
    USE SIGNAL ;
    PORT
      LAYER metal4 ;
        RECT 1037.325000 1663.620000 1037.465000 1663.760000 ;
    END
  END mem_rsp_data[102]
  PIN mem_rsp_data[101]
    DIRECTION INPUT ;
    USE SIGNAL ;
    PORT
      LAYER metal4 ;
        RECT 1042.925000 1663.620000 1043.065000 1663.760000 ;
    END
  END mem_rsp_data[101]
  PIN mem_rsp_data[100]
    DIRECTION INPUT ;
    USE SIGNAL ;
    PORT
      LAYER metal4 ;
        RECT 1048.525000 1663.620000 1048.665000 1663.760000 ;
    END
  END mem_rsp_data[100]
  PIN mem_rsp_data[99]
    DIRECTION INPUT ;
    USE SIGNAL ;
    PORT
      LAYER metal4 ;
        RECT 1054.125000 1663.620000 1054.265000 1663.760000 ;
    END
  END mem_rsp_data[99]
  PIN mem_rsp_data[98]
    DIRECTION INPUT ;
    USE SIGNAL ;
    PORT
      LAYER metal4 ;
        RECT 1059.725000 1663.620000 1059.865000 1663.760000 ;
    END
  END mem_rsp_data[98]
  PIN mem_rsp_data[97]
    DIRECTION INPUT ;
    USE SIGNAL ;
    PORT
      LAYER metal4 ;
        RECT 1065.325000 1663.620000 1065.465000 1663.760000 ;
    END
  END mem_rsp_data[97]
  PIN mem_rsp_data[96]
    DIRECTION INPUT ;
    USE SIGNAL ;
    PORT
      LAYER metal4 ;
        RECT 1071.205000 1663.620000 1071.345000 1663.760000 ;
    END
  END mem_rsp_data[96]
  PIN mem_rsp_data[95]
    DIRECTION INPUT ;
    USE SIGNAL ;
    PORT
      LAYER metal4 ;
        RECT 1076.805000 1663.620000 1076.945000 1663.760000 ;
    END
  END mem_rsp_data[95]
  PIN mem_rsp_data[94]
    DIRECTION INPUT ;
    USE SIGNAL ;
    PORT
      LAYER metal4 ;
        RECT 1082.405000 1663.620000 1082.545000 1663.760000 ;
    END
  END mem_rsp_data[94]
  PIN mem_rsp_data[93]
    DIRECTION INPUT ;
    USE SIGNAL ;
    PORT
      LAYER metal4 ;
        RECT 1088.005000 1663.620000 1088.145000 1663.760000 ;
    END
  END mem_rsp_data[93]
  PIN mem_rsp_data[92]
    DIRECTION INPUT ;
    USE SIGNAL ;
    PORT
      LAYER metal4 ;
        RECT 1093.605000 1663.620000 1093.745000 1663.760000 ;
    END
  END mem_rsp_data[92]
  PIN mem_rsp_data[91]
    DIRECTION INPUT ;
    USE SIGNAL ;
    PORT
      LAYER metal4 ;
        RECT 1099.205000 1663.620000 1099.345000 1663.760000 ;
    END
  END mem_rsp_data[91]
  PIN mem_rsp_data[90]
    DIRECTION INPUT ;
    USE SIGNAL ;
    PORT
      LAYER metal4 ;
        RECT 1104.805000 1663.620000 1104.945000 1663.760000 ;
    END
  END mem_rsp_data[90]
  PIN mem_rsp_data[89]
    DIRECTION INPUT ;
    USE SIGNAL ;
    PORT
      LAYER metal4 ;
        RECT 1110.685000 1663.620000 1110.825000 1663.760000 ;
    END
  END mem_rsp_data[89]
  PIN mem_rsp_data[88]
    DIRECTION INPUT ;
    USE SIGNAL ;
    PORT
      LAYER metal4 ;
        RECT 1116.285000 1663.620000 1116.425000 1663.760000 ;
    END
  END mem_rsp_data[88]
  PIN mem_rsp_data[87]
    DIRECTION INPUT ;
    USE SIGNAL ;
    PORT
      LAYER metal4 ;
        RECT 1121.885000 1663.620000 1122.025000 1663.760000 ;
    END
  END mem_rsp_data[87]
  PIN mem_rsp_data[86]
    DIRECTION INPUT ;
    USE SIGNAL ;
    PORT
      LAYER metal4 ;
        RECT 1127.485000 1663.620000 1127.625000 1663.760000 ;
    END
  END mem_rsp_data[86]
  PIN mem_rsp_data[85]
    DIRECTION INPUT ;
    USE SIGNAL ;
    PORT
      LAYER metal4 ;
        RECT 1133.085000 1663.620000 1133.225000 1663.760000 ;
    END
  END mem_rsp_data[85]
  PIN mem_rsp_data[84]
    DIRECTION INPUT ;
    USE SIGNAL ;
    PORT
      LAYER metal4 ;
        RECT 1138.685000 1663.620000 1138.825000 1663.760000 ;
    END
  END mem_rsp_data[84]
  PIN mem_rsp_data[83]
    DIRECTION INPUT ;
    USE SIGNAL ;
    PORT
      LAYER metal4 ;
        RECT 1144.285000 1663.620000 1144.425000 1663.760000 ;
    END
  END mem_rsp_data[83]
  PIN mem_rsp_data[82]
    DIRECTION INPUT ;
    USE SIGNAL ;
    PORT
      LAYER metal4 ;
        RECT 1149.885000 1663.620000 1150.025000 1663.760000 ;
    END
  END mem_rsp_data[82]
  PIN mem_rsp_data[81]
    DIRECTION INPUT ;
    USE SIGNAL ;
    PORT
      LAYER metal4 ;
        RECT 1155.765000 1663.620000 1155.905000 1663.760000 ;
    END
  END mem_rsp_data[81]
  PIN mem_rsp_data[80]
    DIRECTION INPUT ;
    USE SIGNAL ;
    PORT
      LAYER metal4 ;
        RECT 1161.365000 1663.620000 1161.505000 1663.760000 ;
    END
  END mem_rsp_data[80]
  PIN mem_rsp_data[79]
    DIRECTION INPUT ;
    USE SIGNAL ;
    PORT
      LAYER metal4 ;
        RECT 1166.965000 1663.620000 1167.105000 1663.760000 ;
    END
  END mem_rsp_data[79]
  PIN mem_rsp_data[78]
    DIRECTION INPUT ;
    USE SIGNAL ;
    PORT
      LAYER metal4 ;
        RECT 1172.565000 1663.620000 1172.705000 1663.760000 ;
    END
  END mem_rsp_data[78]
  PIN mem_rsp_data[77]
    DIRECTION INPUT ;
    USE SIGNAL ;
    PORT
      LAYER metal4 ;
        RECT 1178.165000 1663.620000 1178.305000 1663.760000 ;
    END
  END mem_rsp_data[77]
  PIN mem_rsp_data[76]
    DIRECTION INPUT ;
    USE SIGNAL ;
    PORT
      LAYER metal4 ;
        RECT 1183.765000 1663.620000 1183.905000 1663.760000 ;
    END
  END mem_rsp_data[76]
  PIN mem_rsp_data[75]
    DIRECTION INPUT ;
    USE SIGNAL ;
    PORT
      LAYER metal4 ;
        RECT 1189.365000 1663.620000 1189.505000 1663.760000 ;
    END
  END mem_rsp_data[75]
  PIN mem_rsp_data[74]
    DIRECTION INPUT ;
    USE SIGNAL ;
    PORT
      LAYER metal4 ;
        RECT 1195.245000 1663.620000 1195.385000 1663.760000 ;
    END
  END mem_rsp_data[74]
  PIN mem_rsp_data[73]
    DIRECTION INPUT ;
    USE SIGNAL ;
    PORT
      LAYER metal4 ;
        RECT 1200.845000 1663.620000 1200.985000 1663.760000 ;
    END
  END mem_rsp_data[73]
  PIN mem_rsp_data[72]
    DIRECTION INPUT ;
    USE SIGNAL ;
    PORT
      LAYER metal4 ;
        RECT 1206.445000 1663.620000 1206.585000 1663.760000 ;
    END
  END mem_rsp_data[72]
  PIN mem_rsp_data[71]
    DIRECTION INPUT ;
    USE SIGNAL ;
    PORT
      LAYER metal4 ;
        RECT 1212.045000 1663.620000 1212.185000 1663.760000 ;
    END
  END mem_rsp_data[71]
  PIN mem_rsp_data[70]
    DIRECTION INPUT ;
    USE SIGNAL ;
    PORT
      LAYER metal4 ;
        RECT 1217.645000 1663.620000 1217.785000 1663.760000 ;
    END
  END mem_rsp_data[70]
  PIN mem_rsp_data[69]
    DIRECTION INPUT ;
    USE SIGNAL ;
    PORT
      LAYER metal4 ;
        RECT 1223.245000 1663.620000 1223.385000 1663.760000 ;
    END
  END mem_rsp_data[69]
  PIN mem_rsp_data[68]
    DIRECTION INPUT ;
    USE SIGNAL ;
    PORT
      LAYER metal4 ;
        RECT 1228.845000 1663.620000 1228.985000 1663.760000 ;
    END
  END mem_rsp_data[68]
  PIN mem_rsp_data[67]
    DIRECTION INPUT ;
    USE SIGNAL ;
    PORT
      LAYER metal4 ;
        RECT 1234.445000 1663.620000 1234.585000 1663.760000 ;
    END
  END mem_rsp_data[67]
  PIN mem_rsp_data[66]
    DIRECTION INPUT ;
    USE SIGNAL ;
    PORT
      LAYER metal4 ;
        RECT 1240.325000 1663.620000 1240.465000 1663.760000 ;
    END
  END mem_rsp_data[66]
  PIN mem_rsp_data[65]
    DIRECTION INPUT ;
    USE SIGNAL ;
    PORT
      LAYER metal4 ;
        RECT 1245.925000 1663.620000 1246.065000 1663.760000 ;
    END
  END mem_rsp_data[65]
  PIN mem_rsp_data[64]
    DIRECTION INPUT ;
    USE SIGNAL ;
    PORT
      LAYER metal4 ;
        RECT 1251.525000 1663.620000 1251.665000 1663.760000 ;
    END
  END mem_rsp_data[64]
  PIN mem_rsp_data[63]
    DIRECTION INPUT ;
    USE SIGNAL ;
    PORT
      LAYER metal4 ;
        RECT 1257.125000 1663.620000 1257.265000 1663.760000 ;
    END
  END mem_rsp_data[63]
  PIN mem_rsp_data[62]
    DIRECTION INPUT ;
    USE SIGNAL ;
    PORT
      LAYER metal4 ;
        RECT 1262.725000 1663.620000 1262.865000 1663.760000 ;
    END
  END mem_rsp_data[62]
  PIN mem_rsp_data[61]
    DIRECTION INPUT ;
    USE SIGNAL ;
    PORT
      LAYER metal4 ;
        RECT 1268.325000 1663.620000 1268.465000 1663.760000 ;
    END
  END mem_rsp_data[61]
  PIN mem_rsp_data[60]
    DIRECTION INPUT ;
    USE SIGNAL ;
    PORT
      LAYER metal4 ;
        RECT 1273.925000 1663.620000 1274.065000 1663.760000 ;
    END
  END mem_rsp_data[60]
  PIN mem_rsp_data[59]
    DIRECTION INPUT ;
    USE SIGNAL ;
    PORT
      LAYER metal4 ;
        RECT 1279.805000 1663.620000 1279.945000 1663.760000 ;
    END
  END mem_rsp_data[59]
  PIN mem_rsp_data[58]
    DIRECTION INPUT ;
    USE SIGNAL ;
    PORT
      LAYER metal4 ;
        RECT 1285.405000 1663.620000 1285.545000 1663.760000 ;
    END
  END mem_rsp_data[58]
  PIN mem_rsp_data[57]
    DIRECTION INPUT ;
    USE SIGNAL ;
    PORT
      LAYER metal4 ;
        RECT 1291.005000 1663.620000 1291.145000 1663.760000 ;
    END
  END mem_rsp_data[57]
  PIN mem_rsp_data[56]
    DIRECTION INPUT ;
    USE SIGNAL ;
    PORT
      LAYER metal4 ;
        RECT 1296.605000 1663.620000 1296.745000 1663.760000 ;
    END
  END mem_rsp_data[56]
  PIN mem_rsp_data[55]
    DIRECTION INPUT ;
    USE SIGNAL ;
    PORT
      LAYER metal4 ;
        RECT 1302.205000 1663.620000 1302.345000 1663.760000 ;
    END
  END mem_rsp_data[55]
  PIN mem_rsp_data[54]
    DIRECTION INPUT ;
    USE SIGNAL ;
    PORT
      LAYER metal4 ;
        RECT 1307.805000 1663.620000 1307.945000 1663.760000 ;
    END
  END mem_rsp_data[54]
  PIN mem_rsp_data[53]
    DIRECTION INPUT ;
    USE SIGNAL ;
    PORT
      LAYER metal4 ;
        RECT 1313.405000 1663.620000 1313.545000 1663.760000 ;
    END
  END mem_rsp_data[53]
  PIN mem_rsp_data[52]
    DIRECTION INPUT ;
    USE SIGNAL ;
    PORT
      LAYER metal4 ;
        RECT 1319.005000 1663.620000 1319.145000 1663.760000 ;
    END
  END mem_rsp_data[52]
  PIN mem_rsp_data[51]
    DIRECTION INPUT ;
    USE SIGNAL ;
    PORT
      LAYER metal4 ;
        RECT 1324.885000 1663.620000 1325.025000 1663.760000 ;
    END
  END mem_rsp_data[51]
  PIN mem_rsp_data[50]
    DIRECTION INPUT ;
    USE SIGNAL ;
    PORT
      LAYER metal4 ;
        RECT 1330.485000 1663.620000 1330.625000 1663.760000 ;
    END
  END mem_rsp_data[50]
  PIN mem_rsp_data[49]
    DIRECTION INPUT ;
    USE SIGNAL ;
    PORT
      LAYER metal4 ;
        RECT 1336.085000 1663.620000 1336.225000 1663.760000 ;
    END
  END mem_rsp_data[49]
  PIN mem_rsp_data[48]
    DIRECTION INPUT ;
    USE SIGNAL ;
    PORT
      LAYER metal4 ;
        RECT 1341.685000 1663.620000 1341.825000 1663.760000 ;
    END
  END mem_rsp_data[48]
  PIN mem_rsp_data[47]
    DIRECTION INPUT ;
    USE SIGNAL ;
    PORT
      LAYER metal4 ;
        RECT 1347.285000 1663.620000 1347.425000 1663.760000 ;
    END
  END mem_rsp_data[47]
  PIN mem_rsp_data[46]
    DIRECTION INPUT ;
    USE SIGNAL ;
    PORT
      LAYER metal4 ;
        RECT 1352.885000 1663.620000 1353.025000 1663.760000 ;
    END
  END mem_rsp_data[46]
  PIN mem_rsp_data[45]
    DIRECTION INPUT ;
    USE SIGNAL ;
    PORT
      LAYER metal4 ;
        RECT 1358.485000 1663.620000 1358.625000 1663.760000 ;
    END
  END mem_rsp_data[45]
  PIN mem_rsp_data[44]
    DIRECTION INPUT ;
    USE SIGNAL ;
    PORT
      LAYER metal4 ;
        RECT 1364.085000 1663.620000 1364.225000 1663.760000 ;
    END
  END mem_rsp_data[44]
  PIN mem_rsp_data[43]
    DIRECTION INPUT ;
    USE SIGNAL ;
    PORT
      LAYER metal4 ;
        RECT 1369.965000 1663.620000 1370.105000 1663.760000 ;
    END
  END mem_rsp_data[43]
  PIN mem_rsp_data[42]
    DIRECTION INPUT ;
    USE SIGNAL ;
    PORT
      LAYER metal4 ;
        RECT 1375.565000 1663.620000 1375.705000 1663.760000 ;
    END
  END mem_rsp_data[42]
  PIN mem_rsp_data[41]
    DIRECTION INPUT ;
    USE SIGNAL ;
    PORT
      LAYER metal4 ;
        RECT 1381.165000 1663.620000 1381.305000 1663.760000 ;
    END
  END mem_rsp_data[41]
  PIN mem_rsp_data[40]
    DIRECTION INPUT ;
    USE SIGNAL ;
    PORT
      LAYER metal4 ;
        RECT 1386.765000 1663.620000 1386.905000 1663.760000 ;
    END
  END mem_rsp_data[40]
  PIN mem_rsp_data[39]
    DIRECTION INPUT ;
    USE SIGNAL ;
    PORT
      LAYER metal4 ;
        RECT 1392.365000 1663.620000 1392.505000 1663.760000 ;
    END
  END mem_rsp_data[39]
  PIN mem_rsp_data[38]
    DIRECTION INPUT ;
    USE SIGNAL ;
    PORT
      LAYER metal4 ;
        RECT 1397.965000 1663.620000 1398.105000 1663.760000 ;
    END
  END mem_rsp_data[38]
  PIN mem_rsp_data[37]
    DIRECTION INPUT ;
    USE SIGNAL ;
    PORT
      LAYER metal4 ;
        RECT 1403.565000 1663.620000 1403.705000 1663.760000 ;
    END
  END mem_rsp_data[37]
  PIN mem_rsp_data[36]
    DIRECTION INPUT ;
    USE SIGNAL ;
    PORT
      LAYER metal4 ;
        RECT 1409.445000 1663.620000 1409.585000 1663.760000 ;
    END
  END mem_rsp_data[36]
  PIN mem_rsp_data[35]
    DIRECTION INPUT ;
    USE SIGNAL ;
    PORT
      LAYER metal4 ;
        RECT 1415.045000 1663.620000 1415.185000 1663.760000 ;
    END
  END mem_rsp_data[35]
  PIN mem_rsp_data[34]
    DIRECTION INPUT ;
    USE SIGNAL ;
    PORT
      LAYER metal4 ;
        RECT 1420.645000 1663.620000 1420.785000 1663.760000 ;
    END
  END mem_rsp_data[34]
  PIN mem_rsp_data[33]
    DIRECTION INPUT ;
    USE SIGNAL ;
    PORT
      LAYER metal4 ;
        RECT 1426.245000 1663.620000 1426.385000 1663.760000 ;
    END
  END mem_rsp_data[33]
  PIN mem_rsp_data[32]
    DIRECTION INPUT ;
    USE SIGNAL ;
    PORT
      LAYER metal4 ;
        RECT 1431.845000 1663.620000 1431.985000 1663.760000 ;
    END
  END mem_rsp_data[32]
  PIN mem_rsp_data[31]
    DIRECTION INPUT ;
    USE SIGNAL ;
    PORT
      LAYER metal4 ;
        RECT 1437.445000 1663.620000 1437.585000 1663.760000 ;
    END
  END mem_rsp_data[31]
  PIN mem_rsp_data[30]
    DIRECTION INPUT ;
    USE SIGNAL ;
    PORT
      LAYER metal4 ;
        RECT 1443.045000 1663.620000 1443.185000 1663.760000 ;
    END
  END mem_rsp_data[30]
  PIN mem_rsp_data[29]
    DIRECTION INPUT ;
    USE SIGNAL ;
    PORT
      LAYER metal4 ;
        RECT 1448.645000 1663.620000 1448.785000 1663.760000 ;
    END
  END mem_rsp_data[29]
  PIN mem_rsp_data[28]
    DIRECTION INPUT ;
    USE SIGNAL ;
    PORT
      LAYER metal4 ;
        RECT 1454.525000 1663.620000 1454.665000 1663.760000 ;
    END
  END mem_rsp_data[28]
  PIN mem_rsp_data[27]
    DIRECTION INPUT ;
    USE SIGNAL ;
    PORT
      LAYER metal4 ;
        RECT 1460.125000 1663.620000 1460.265000 1663.760000 ;
    END
  END mem_rsp_data[27]
  PIN mem_rsp_data[26]
    DIRECTION INPUT ;
    USE SIGNAL ;
    PORT
      LAYER metal4 ;
        RECT 1465.725000 1663.620000 1465.865000 1663.760000 ;
    END
  END mem_rsp_data[26]
  PIN mem_rsp_data[25]
    DIRECTION INPUT ;
    USE SIGNAL ;
    PORT
      LAYER metal4 ;
        RECT 1471.325000 1663.620000 1471.465000 1663.760000 ;
    END
  END mem_rsp_data[25]
  PIN mem_rsp_data[24]
    DIRECTION INPUT ;
    USE SIGNAL ;
    PORT
      LAYER metal4 ;
        RECT 1476.925000 1663.620000 1477.065000 1663.760000 ;
    END
  END mem_rsp_data[24]
  PIN mem_rsp_data[23]
    DIRECTION INPUT ;
    USE SIGNAL ;
    PORT
      LAYER metal4 ;
        RECT 1482.525000 1663.620000 1482.665000 1663.760000 ;
    END
  END mem_rsp_data[23]
  PIN mem_rsp_data[22]
    DIRECTION INPUT ;
    USE SIGNAL ;
    PORT
      LAYER metal4 ;
        RECT 1488.125000 1663.620000 1488.265000 1663.760000 ;
    END
  END mem_rsp_data[22]
  PIN mem_rsp_data[21]
    DIRECTION INPUT ;
    USE SIGNAL ;
    PORT
      LAYER metal4 ;
        RECT 1494.005000 1663.620000 1494.145000 1663.760000 ;
    END
  END mem_rsp_data[21]
  PIN mem_rsp_data[20]
    DIRECTION INPUT ;
    USE SIGNAL ;
    PORT
      LAYER metal4 ;
        RECT 1499.605000 1663.620000 1499.745000 1663.760000 ;
    END
  END mem_rsp_data[20]
  PIN mem_rsp_data[19]
    DIRECTION INPUT ;
    USE SIGNAL ;
    PORT
      LAYER metal4 ;
        RECT 1505.205000 1663.620000 1505.345000 1663.760000 ;
    END
  END mem_rsp_data[19]
  PIN mem_rsp_data[18]
    DIRECTION INPUT ;
    USE SIGNAL ;
    PORT
      LAYER metal4 ;
        RECT 1510.805000 1663.620000 1510.945000 1663.760000 ;
    END
  END mem_rsp_data[18]
  PIN mem_rsp_data[17]
    DIRECTION INPUT ;
    USE SIGNAL ;
    PORT
      LAYER metal4 ;
        RECT 1516.405000 1663.620000 1516.545000 1663.760000 ;
    END
  END mem_rsp_data[17]
  PIN mem_rsp_data[16]
    DIRECTION INPUT ;
    USE SIGNAL ;
    PORT
      LAYER metal4 ;
        RECT 1522.005000 1663.620000 1522.145000 1663.760000 ;
    END
  END mem_rsp_data[16]
  PIN mem_rsp_data[15]
    DIRECTION INPUT ;
    USE SIGNAL ;
    PORT
      LAYER metal4 ;
        RECT 1527.605000 1663.620000 1527.745000 1663.760000 ;
    END
  END mem_rsp_data[15]
  PIN mem_rsp_data[14]
    DIRECTION INPUT ;
    USE SIGNAL ;
    PORT
      LAYER metal4 ;
        RECT 1533.205000 1663.620000 1533.345000 1663.760000 ;
    END
  END mem_rsp_data[14]
  PIN mem_rsp_data[13]
    DIRECTION INPUT ;
    USE SIGNAL ;
    PORT
      LAYER metal4 ;
        RECT 1539.085000 1663.620000 1539.225000 1663.760000 ;
    END
  END mem_rsp_data[13]
  PIN mem_rsp_data[12]
    DIRECTION INPUT ;
    USE SIGNAL ;
    PORT
      LAYER metal4 ;
        RECT 1544.685000 1663.620000 1544.825000 1663.760000 ;
    END
  END mem_rsp_data[12]
  PIN mem_rsp_data[11]
    DIRECTION INPUT ;
    USE SIGNAL ;
    PORT
      LAYER metal4 ;
        RECT 1550.285000 1663.620000 1550.425000 1663.760000 ;
    END
  END mem_rsp_data[11]
  PIN mem_rsp_data[10]
    DIRECTION INPUT ;
    USE SIGNAL ;
    PORT
      LAYER metal4 ;
        RECT 1555.885000 1663.620000 1556.025000 1663.760000 ;
    END
  END mem_rsp_data[10]
  PIN mem_rsp_data[9]
    DIRECTION INPUT ;
    USE SIGNAL ;
    PORT
      LAYER metal4 ;
        RECT 1561.485000 1663.620000 1561.625000 1663.760000 ;
    END
  END mem_rsp_data[9]
  PIN mem_rsp_data[8]
    DIRECTION INPUT ;
    USE SIGNAL ;
    PORT
      LAYER metal4 ;
        RECT 1567.085000 1663.620000 1567.225000 1663.760000 ;
    END
  END mem_rsp_data[8]
  PIN mem_rsp_data[7]
    DIRECTION INPUT ;
    USE SIGNAL ;
    PORT
      LAYER metal4 ;
        RECT 1572.685000 1663.620000 1572.825000 1663.760000 ;
    END
  END mem_rsp_data[7]
  PIN mem_rsp_data[6]
    DIRECTION INPUT ;
    USE SIGNAL ;
    PORT
      LAYER metal4 ;
        RECT 1578.565000 1663.620000 1578.705000 1663.760000 ;
    END
  END mem_rsp_data[6]
  PIN mem_rsp_data[5]
    DIRECTION INPUT ;
    USE SIGNAL ;
    PORT
      LAYER metal4 ;
        RECT 1584.165000 1663.620000 1584.305000 1663.760000 ;
    END
  END mem_rsp_data[5]
  PIN mem_rsp_data[4]
    DIRECTION INPUT ;
    USE SIGNAL ;
    PORT
      LAYER metal4 ;
        RECT 1589.765000 1663.620000 1589.905000 1663.760000 ;
    END
  END mem_rsp_data[4]
  PIN mem_rsp_data[3]
    DIRECTION INPUT ;
    USE SIGNAL ;
    PORT
      LAYER metal4 ;
        RECT 1595.365000 1663.620000 1595.505000 1663.760000 ;
    END
  END mem_rsp_data[3]
  PIN mem_rsp_data[2]
    DIRECTION INPUT ;
    USE SIGNAL ;
    PORT
      LAYER metal4 ;
        RECT 1600.965000 1663.620000 1601.105000 1663.760000 ;
    END
  END mem_rsp_data[2]
  PIN mem_rsp_data[1]
    DIRECTION INPUT ;
    USE SIGNAL ;
    PORT
      LAYER metal4 ;
        RECT 1606.565000 1663.620000 1606.705000 1663.760000 ;
    END
  END mem_rsp_data[1]
  PIN mem_rsp_data[0]
    DIRECTION INPUT ;
    USE SIGNAL ;
    PORT
      LAYER metal4 ;
        RECT 1612.165000 1663.620000 1612.305000 1663.760000 ;
    END
  END mem_rsp_data[0]
  PIN mem_rsp_tag[6]
    DIRECTION INPUT ;
    USE SIGNAL ;
    PORT
      LAYER metal4 ;
        RECT 1617.765000 1663.620000 1617.905000 1663.760000 ;
    END
  END mem_rsp_tag[6]
  PIN mem_rsp_tag[5]
    DIRECTION INPUT ;
    USE SIGNAL ;
    PORT
      LAYER metal4 ;
        RECT 1623.645000 1663.620000 1623.785000 1663.760000 ;
    END
  END mem_rsp_tag[5]
  PIN mem_rsp_tag[4]
    DIRECTION INPUT ;
    USE SIGNAL ;
    PORT
      LAYER metal4 ;
        RECT 1629.245000 1663.620000 1629.385000 1663.760000 ;
    END
  END mem_rsp_tag[4]
  PIN mem_rsp_tag[3]
    DIRECTION INPUT ;
    USE SIGNAL ;
    PORT
      LAYER metal4 ;
        RECT 1634.845000 1663.620000 1634.985000 1663.760000 ;
    END
  END mem_rsp_tag[3]
  PIN mem_rsp_tag[2]
    DIRECTION INPUT ;
    USE SIGNAL ;
    PORT
      LAYER metal4 ;
        RECT 1640.445000 1663.620000 1640.585000 1663.760000 ;
    END
  END mem_rsp_tag[2]
  PIN mem_rsp_tag[1]
    DIRECTION INPUT ;
    USE SIGNAL ;
    PORT
      LAYER metal4 ;
        RECT 1646.045000 1663.620000 1646.185000 1663.760000 ;
    END
  END mem_rsp_tag[1]
  PIN mem_rsp_tag[0]
    DIRECTION INPUT ;
    USE SIGNAL ;
    PORT
      LAYER metal4 ;
        RECT 1651.645000 1663.620000 1651.785000 1663.760000 ;
    END
  END mem_rsp_tag[0]
  PIN mem_rsp_ready[0]
    DIRECTION OUTPUT ;
    USE SIGNAL ;
    PORT
      LAYER metal4 ;
        RECT 1657.245000 1663.620000 1657.385000 1663.760000 ;
    END
  END mem_rsp_ready[0]
  PIN busy
    DIRECTION OUTPUT ;
    USE SIGNAL ;
    PORT
      LAYER metal4 ;
        RECT 1662.845000 1663.620000 1662.985000 1663.760000 ;
    END
  END busy
  PIN VSS
    DIRECTION INOUT ;
    USE GROUND ;

# P/G power stripe data as pin
    PORT
      LAYER metal7 ;
        RECT 404.940000 5.040000 406.540000 1658.720000 ;
        RECT 364.940000 5.040000 366.540000 1658.720000 ;
        RECT 324.940000 5.040000 326.540000 1658.720000 ;
        RECT 284.940000 5.040000 286.540000 1658.720000 ;
        RECT 244.940000 5.040000 246.540000 1658.720000 ;
        RECT 204.940000 5.040000 206.540000 1658.720000 ;
        RECT 164.940000 5.040000 166.540000 1658.720000 ;
        RECT 124.940000 5.040000 126.540000 1658.720000 ;
        RECT 84.940000 5.040000 86.540000 1658.720000 ;
        RECT 44.940000 5.040000 46.540000 1658.720000 ;
        RECT 4.940000 5.040000 6.540000 1658.720000 ;
        RECT 804.940000 5.040000 806.540000 1658.720000 ;
        RECT 764.940000 5.040000 766.540000 1658.720000 ;
        RECT 724.940000 5.040000 726.540000 1658.720000 ;
        RECT 684.940000 5.040000 686.540000 1658.720000 ;
        RECT 644.940000 5.040000 646.540000 1658.720000 ;
        RECT 604.940000 5.040000 606.540000 1658.720000 ;
        RECT 564.940000 5.040000 566.540000 1658.720000 ;
        RECT 524.940000 5.040000 526.540000 1658.720000 ;
        RECT 484.940000 5.040000 486.540000 1658.720000 ;
        RECT 444.940000 5.040000 446.540000 1658.720000 ;
        RECT 1164.940000 5.040000 1166.540000 1658.720000 ;
        RECT 1124.940000 5.040000 1126.540000 1658.720000 ;
        RECT 1084.940000 5.040000 1086.540000 1658.720000 ;
        RECT 1044.940000 5.040000 1046.540000 1658.720000 ;
        RECT 1004.940000 5.040000 1006.540000 1658.720000 ;
        RECT 964.940000 5.040000 966.540000 1658.720000 ;
        RECT 924.940000 5.040000 926.540000 1658.720000 ;
        RECT 884.940000 5.040000 886.540000 1658.720000 ;
        RECT 844.940000 5.040000 846.540000 1658.720000 ;
        RECT 1204.940000 5.040000 1206.540000 1658.720000 ;
        RECT 1244.940000 5.040000 1246.540000 1658.720000 ;
        RECT 1284.940000 5.040000 1286.540000 1658.720000 ;
        RECT 1324.940000 5.040000 1326.540000 1658.720000 ;
        RECT 1364.940000 5.040000 1366.540000 1658.720000 ;
        RECT 1404.940000 5.040000 1406.540000 1658.720000 ;
        RECT 1444.940000 5.040000 1446.540000 1658.720000 ;
        RECT 1484.940000 5.040000 1486.540000 1658.720000 ;
        RECT 1524.940000 5.040000 1526.540000 1658.720000 ;
        RECT 1564.940000 5.040000 1566.540000 1658.720000 ;
        RECT 1604.940000 5.040000 1606.540000 1658.720000 ;
        RECT 1644.940000 5.040000 1646.540000 1658.720000 ;
    END
# end of P/G power stripe data as pin

  END VSS
  PIN VDD
    DIRECTION INOUT ;
    USE POWER ;

# P/G power stripe data as pin
    PORT
      LAYER metal7 ;
        RECT 408.140000 5.040000 409.740000 1658.720000 ;
        RECT 368.140000 5.040000 369.740000 1658.720000 ;
        RECT 8.140000 5.040000 9.740000 1658.720000 ;
        RECT 48.140000 5.040000 49.740000 1658.720000 ;
        RECT 88.140000 5.040000 89.740000 1658.720000 ;
        RECT 128.140000 5.040000 129.740000 1658.720000 ;
        RECT 168.140000 5.040000 169.740000 1658.720000 ;
        RECT 208.140000 5.040000 209.740000 1658.720000 ;
        RECT 248.140000 5.040000 249.740000 1658.720000 ;
        RECT 288.140000 5.040000 289.740000 1658.720000 ;
        RECT 328.140000 5.040000 329.740000 1658.720000 ;
        RECT 808.140000 5.040000 809.740000 1658.720000 ;
        RECT 768.140000 5.040000 769.740000 1658.720000 ;
        RECT 728.140000 5.040000 729.740000 1658.720000 ;
        RECT 688.140000 5.040000 689.740000 1658.720000 ;
        RECT 648.140000 5.040000 649.740000 1658.720000 ;
        RECT 608.140000 5.040000 609.740000 1658.720000 ;
        RECT 568.140000 5.040000 569.740000 1658.720000 ;
        RECT 528.140000 5.040000 529.740000 1658.720000 ;
        RECT 488.140000 5.040000 489.740000 1658.720000 ;
        RECT 448.140000 5.040000 449.740000 1658.720000 ;
        RECT 1208.140000 5.040000 1209.740000 1658.720000 ;
        RECT 848.140000 5.040000 849.740000 1658.720000 ;
        RECT 888.140000 5.040000 889.740000 1658.720000 ;
        RECT 928.140000 5.040000 929.740000 1658.720000 ;
        RECT 968.140000 5.040000 969.740000 1658.720000 ;
        RECT 1008.140000 5.040000 1009.740000 1658.720000 ;
        RECT 1048.140000 5.040000 1049.740000 1658.720000 ;
        RECT 1088.140000 5.040000 1089.740000 1658.720000 ;
        RECT 1128.140000 5.040000 1129.740000 1658.720000 ;
        RECT 1168.140000 5.040000 1169.740000 1658.720000 ;
        RECT 1648.140000 5.040000 1649.740000 1658.720000 ;
        RECT 1608.140000 5.040000 1609.740000 1658.720000 ;
        RECT 1568.140000 5.040000 1569.740000 1658.720000 ;
        RECT 1528.140000 5.040000 1529.740000 1658.720000 ;
        RECT 1488.140000 5.040000 1489.740000 1658.720000 ;
        RECT 1448.140000 5.040000 1449.740000 1658.720000 ;
        RECT 1408.140000 5.040000 1409.740000 1658.720000 ;
        RECT 1368.140000 5.040000 1369.740000 1658.720000 ;
        RECT 1328.140000 5.040000 1329.740000 1658.720000 ;
        RECT 1288.140000 5.040000 1289.740000 1658.720000 ;
        RECT 1248.140000 5.040000 1249.740000 1658.720000 ;
        RECT 8.140000 4.882500 9.740000 5.282500 ;
        RECT 48.140000 4.882500 49.740000 5.282500 ;
        RECT 88.140000 4.882500 89.740000 5.282500 ;
        RECT 128.140000 4.882500 129.740000 5.282500 ;
        RECT 168.140000 4.882500 169.740000 5.282500 ;
        RECT 208.140000 4.882500 209.740000 5.282500 ;
        RECT 248.140000 4.882500 249.740000 5.282500 ;
        RECT 288.140000 4.882500 289.740000 5.282500 ;
        RECT 328.140000 4.882500 329.740000 5.282500 ;
        RECT 368.140000 4.882500 369.740000 5.282500 ;
        RECT 408.140000 4.882500 409.740000 5.282500 ;
        RECT 448.140000 4.882500 449.740000 5.282500 ;
        RECT 488.140000 4.882500 489.740000 5.282500 ;
        RECT 528.140000 4.882500 529.740000 5.282500 ;
        RECT 568.140000 4.882500 569.740000 5.282500 ;
        RECT 608.140000 4.882500 609.740000 5.282500 ;
        RECT 648.140000 4.882500 649.740000 5.282500 ;
        RECT 688.140000 4.882500 689.740000 5.282500 ;
        RECT 728.140000 4.882500 729.740000 5.282500 ;
        RECT 768.140000 4.882500 769.740000 5.282500 ;
        RECT 808.140000 4.882500 809.740000 5.282500 ;
        RECT 848.140000 4.882500 849.740000 5.282500 ;
        RECT 888.140000 4.882500 889.740000 5.282500 ;
        RECT 928.140000 4.882500 929.740000 5.282500 ;
        RECT 968.140000 4.882500 969.740000 5.282500 ;
        RECT 1008.140000 4.882500 1009.740000 5.282500 ;
        RECT 1048.140000 4.882500 1049.740000 5.282500 ;
        RECT 1088.140000 4.882500 1089.740000 5.282500 ;
        RECT 1128.140000 4.882500 1129.740000 5.282500 ;
        RECT 1168.140000 4.882500 1169.740000 5.282500 ;
        RECT 1208.140000 4.882500 1209.740000 5.282500 ;
        RECT 1248.140000 4.882500 1249.740000 5.282500 ;
        RECT 1288.140000 4.882500 1289.740000 5.282500 ;
        RECT 1328.140000 4.882500 1329.740000 5.282500 ;
        RECT 1368.140000 4.882500 1369.740000 5.282500 ;
        RECT 1408.140000 4.882500 1409.740000 5.282500 ;
        RECT 1448.140000 4.882500 1449.740000 5.282500 ;
        RECT 1488.140000 4.882500 1489.740000 5.282500 ;
        RECT 1528.140000 4.882500 1529.740000 5.282500 ;
        RECT 1568.140000 4.882500 1569.740000 5.282500 ;
        RECT 1608.140000 4.882500 1609.740000 5.282500 ;
        RECT 1648.140000 4.882500 1649.740000 5.282500 ;
    END
# end of P/G power stripe data as pin

  END VDD
  OBS
    LAYER metal1 ;
      RECT 0.000000 0.000000 1663.450000 1663.760000 ;
    LAYER metal2 ;
      RECT 0.000000 0.000000 1663.450000 1663.760000 ;
    LAYER metal3 ;
      RECT 0.000000 0.000000 1663.450000 1663.760000 ;
    LAYER metal4 ;
      RECT 1663.125000 1663.480000 1663.450000 1663.760000 ;
      RECT 1657.525000 1663.480000 1662.705000 1663.760000 ;
      RECT 1651.925000 1663.480000 1657.105000 1663.760000 ;
      RECT 1646.325000 1663.480000 1651.505000 1663.760000 ;
      RECT 1640.725000 1663.480000 1645.905000 1663.760000 ;
      RECT 1635.125000 1663.480000 1640.305000 1663.760000 ;
      RECT 1629.525000 1663.480000 1634.705000 1663.760000 ;
      RECT 1623.925000 1663.480000 1629.105000 1663.760000 ;
      RECT 1618.045000 1663.480000 1623.505000 1663.760000 ;
      RECT 1612.445000 1663.480000 1617.625000 1663.760000 ;
      RECT 1606.845000 1663.480000 1612.025000 1663.760000 ;
      RECT 1601.245000 1663.480000 1606.425000 1663.760000 ;
      RECT 1595.645000 1663.480000 1600.825000 1663.760000 ;
      RECT 1590.045000 1663.480000 1595.225000 1663.760000 ;
      RECT 1584.445000 1663.480000 1589.625000 1663.760000 ;
      RECT 1578.845000 1663.480000 1584.025000 1663.760000 ;
      RECT 1572.965000 1663.480000 1578.425000 1663.760000 ;
      RECT 1567.365000 1663.480000 1572.545000 1663.760000 ;
      RECT 1561.765000 1663.480000 1566.945000 1663.760000 ;
      RECT 1556.165000 1663.480000 1561.345000 1663.760000 ;
      RECT 1550.565000 1663.480000 1555.745000 1663.760000 ;
      RECT 1544.965000 1663.480000 1550.145000 1663.760000 ;
      RECT 1539.365000 1663.480000 1544.545000 1663.760000 ;
      RECT 1533.485000 1663.480000 1538.945000 1663.760000 ;
      RECT 1527.885000 1663.480000 1533.065000 1663.760000 ;
      RECT 1522.285000 1663.480000 1527.465000 1663.760000 ;
      RECT 1516.685000 1663.480000 1521.865000 1663.760000 ;
      RECT 1511.085000 1663.480000 1516.265000 1663.760000 ;
      RECT 1505.485000 1663.480000 1510.665000 1663.760000 ;
      RECT 1499.885000 1663.480000 1505.065000 1663.760000 ;
      RECT 1494.285000 1663.480000 1499.465000 1663.760000 ;
      RECT 1488.405000 1663.480000 1493.865000 1663.760000 ;
      RECT 1482.805000 1663.480000 1487.985000 1663.760000 ;
      RECT 1477.205000 1663.480000 1482.385000 1663.760000 ;
      RECT 1471.605000 1663.480000 1476.785000 1663.760000 ;
      RECT 1466.005000 1663.480000 1471.185000 1663.760000 ;
      RECT 1460.405000 1663.480000 1465.585000 1663.760000 ;
      RECT 1454.805000 1663.480000 1459.985000 1663.760000 ;
      RECT 1448.925000 1663.480000 1454.385000 1663.760000 ;
      RECT 1443.325000 1663.480000 1448.505000 1663.760000 ;
      RECT 1437.725000 1663.480000 1442.905000 1663.760000 ;
      RECT 1432.125000 1663.480000 1437.305000 1663.760000 ;
      RECT 1426.525000 1663.480000 1431.705000 1663.760000 ;
      RECT 1420.925000 1663.480000 1426.105000 1663.760000 ;
      RECT 1415.325000 1663.480000 1420.505000 1663.760000 ;
      RECT 1409.725000 1663.480000 1414.905000 1663.760000 ;
      RECT 1403.845000 1663.480000 1409.305000 1663.760000 ;
      RECT 1398.245000 1663.480000 1403.425000 1663.760000 ;
      RECT 1392.645000 1663.480000 1397.825000 1663.760000 ;
      RECT 1387.045000 1663.480000 1392.225000 1663.760000 ;
      RECT 1381.445000 1663.480000 1386.625000 1663.760000 ;
      RECT 1375.845000 1663.480000 1381.025000 1663.760000 ;
      RECT 1370.245000 1663.480000 1375.425000 1663.760000 ;
      RECT 1364.365000 1663.480000 1369.825000 1663.760000 ;
      RECT 1358.765000 1663.480000 1363.945000 1663.760000 ;
      RECT 1353.165000 1663.480000 1358.345000 1663.760000 ;
      RECT 1347.565000 1663.480000 1352.745000 1663.760000 ;
      RECT 1341.965000 1663.480000 1347.145000 1663.760000 ;
      RECT 1336.365000 1663.480000 1341.545000 1663.760000 ;
      RECT 1330.765000 1663.480000 1335.945000 1663.760000 ;
      RECT 1325.165000 1663.480000 1330.345000 1663.760000 ;
      RECT 1319.285000 1663.480000 1324.745000 1663.760000 ;
      RECT 1313.685000 1663.480000 1318.865000 1663.760000 ;
      RECT 1308.085000 1663.480000 1313.265000 1663.760000 ;
      RECT 1302.485000 1663.480000 1307.665000 1663.760000 ;
      RECT 1296.885000 1663.480000 1302.065000 1663.760000 ;
      RECT 1291.285000 1663.480000 1296.465000 1663.760000 ;
      RECT 1285.685000 1663.480000 1290.865000 1663.760000 ;
      RECT 1280.085000 1663.480000 1285.265000 1663.760000 ;
      RECT 1274.205000 1663.480000 1279.665000 1663.760000 ;
      RECT 1268.605000 1663.480000 1273.785000 1663.760000 ;
      RECT 1263.005000 1663.480000 1268.185000 1663.760000 ;
      RECT 1257.405000 1663.480000 1262.585000 1663.760000 ;
      RECT 1251.805000 1663.480000 1256.985000 1663.760000 ;
      RECT 1246.205000 1663.480000 1251.385000 1663.760000 ;
      RECT 1240.605000 1663.480000 1245.785000 1663.760000 ;
      RECT 1234.725000 1663.480000 1240.185000 1663.760000 ;
      RECT 1229.125000 1663.480000 1234.305000 1663.760000 ;
      RECT 1223.525000 1663.480000 1228.705000 1663.760000 ;
      RECT 1217.925000 1663.480000 1223.105000 1663.760000 ;
      RECT 1212.325000 1663.480000 1217.505000 1663.760000 ;
      RECT 1206.725000 1663.480000 1211.905000 1663.760000 ;
      RECT 1201.125000 1663.480000 1206.305000 1663.760000 ;
      RECT 1195.525000 1663.480000 1200.705000 1663.760000 ;
      RECT 1189.645000 1663.480000 1195.105000 1663.760000 ;
      RECT 1184.045000 1663.480000 1189.225000 1663.760000 ;
      RECT 1178.445000 1663.480000 1183.625000 1663.760000 ;
      RECT 1172.845000 1663.480000 1178.025000 1663.760000 ;
      RECT 1167.245000 1663.480000 1172.425000 1663.760000 ;
      RECT 1161.645000 1663.480000 1166.825000 1663.760000 ;
      RECT 1156.045000 1663.480000 1161.225000 1663.760000 ;
      RECT 1150.165000 1663.480000 1155.625000 1663.760000 ;
      RECT 1144.565000 1663.480000 1149.745000 1663.760000 ;
      RECT 1138.965000 1663.480000 1144.145000 1663.760000 ;
      RECT 1133.365000 1663.480000 1138.545000 1663.760000 ;
      RECT 1127.765000 1663.480000 1132.945000 1663.760000 ;
      RECT 1122.165000 1663.480000 1127.345000 1663.760000 ;
      RECT 1116.565000 1663.480000 1121.745000 1663.760000 ;
      RECT 1110.965000 1663.480000 1116.145000 1663.760000 ;
      RECT 1105.085000 1663.480000 1110.545000 1663.760000 ;
      RECT 1099.485000 1663.480000 1104.665000 1663.760000 ;
      RECT 1093.885000 1663.480000 1099.065000 1663.760000 ;
      RECT 1088.285000 1663.480000 1093.465000 1663.760000 ;
      RECT 1082.685000 1663.480000 1087.865000 1663.760000 ;
      RECT 1077.085000 1663.480000 1082.265000 1663.760000 ;
      RECT 1071.485000 1663.480000 1076.665000 1663.760000 ;
      RECT 1065.605000 1663.480000 1071.065000 1663.760000 ;
      RECT 1060.005000 1663.480000 1065.185000 1663.760000 ;
      RECT 1054.405000 1663.480000 1059.585000 1663.760000 ;
      RECT 1048.805000 1663.480000 1053.985000 1663.760000 ;
      RECT 1043.205000 1663.480000 1048.385000 1663.760000 ;
      RECT 1037.605000 1663.480000 1042.785000 1663.760000 ;
      RECT 1032.005000 1663.480000 1037.185000 1663.760000 ;
      RECT 1026.405000 1663.480000 1031.585000 1663.760000 ;
      RECT 1020.525000 1663.480000 1025.985000 1663.760000 ;
      RECT 1014.925000 1663.480000 1020.105000 1663.760000 ;
      RECT 1009.325000 1663.480000 1014.505000 1663.760000 ;
      RECT 1003.725000 1663.480000 1008.905000 1663.760000 ;
      RECT 998.125000 1663.480000 1003.305000 1663.760000 ;
      RECT 992.525000 1663.480000 997.705000 1663.760000 ;
      RECT 986.925000 1663.480000 992.105000 1663.760000 ;
      RECT 981.325000 1663.480000 986.505000 1663.760000 ;
      RECT 975.445000 1663.480000 980.905000 1663.760000 ;
      RECT 969.845000 1663.480000 975.025000 1663.760000 ;
      RECT 964.245000 1663.480000 969.425000 1663.760000 ;
      RECT 958.645000 1663.480000 963.825000 1663.760000 ;
      RECT 953.045000 1663.480000 958.225000 1663.760000 ;
      RECT 947.445000 1663.480000 952.625000 1663.760000 ;
      RECT 941.845000 1663.480000 947.025000 1663.760000 ;
      RECT 935.965000 1663.480000 941.425000 1663.760000 ;
      RECT 930.365000 1663.480000 935.545000 1663.760000 ;
      RECT 924.765000 1663.480000 929.945000 1663.760000 ;
      RECT 919.165000 1663.480000 924.345000 1663.760000 ;
      RECT 913.565000 1663.480000 918.745000 1663.760000 ;
      RECT 907.965000 1663.480000 913.145000 1663.760000 ;
      RECT 902.365000 1663.480000 907.545000 1663.760000 ;
      RECT 896.765000 1663.480000 901.945000 1663.760000 ;
      RECT 890.885000 1663.480000 896.345000 1663.760000 ;
      RECT 885.285000 1663.480000 890.465000 1663.760000 ;
      RECT 879.685000 1663.480000 884.865000 1663.760000 ;
      RECT 874.085000 1663.480000 879.265000 1663.760000 ;
      RECT 868.485000 1663.480000 873.665000 1663.760000 ;
      RECT 862.885000 1663.480000 868.065000 1663.760000 ;
      RECT 857.285000 1663.480000 862.465000 1663.760000 ;
      RECT 851.405000 1663.480000 856.865000 1663.760000 ;
      RECT 845.805000 1663.480000 850.985000 1663.760000 ;
      RECT 840.205000 1663.480000 845.385000 1663.760000 ;
      RECT 834.605000 1663.480000 839.785000 1663.760000 ;
      RECT 829.005000 1663.480000 834.185000 1663.760000 ;
      RECT 823.405000 1663.480000 828.585000 1663.760000 ;
      RECT 817.805000 1663.480000 822.985000 1663.760000 ;
      RECT 812.205000 1663.480000 817.385000 1663.760000 ;
      RECT 806.325000 1663.480000 811.785000 1663.760000 ;
      RECT 800.725000 1663.480000 805.905000 1663.760000 ;
      RECT 795.125000 1663.480000 800.305000 1663.760000 ;
      RECT 789.525000 1663.480000 794.705000 1663.760000 ;
      RECT 783.925000 1663.480000 789.105000 1663.760000 ;
      RECT 778.325000 1663.480000 783.505000 1663.760000 ;
      RECT 772.725000 1663.480000 777.905000 1663.760000 ;
      RECT 766.845000 1663.480000 772.305000 1663.760000 ;
      RECT 761.245000 1663.480000 766.425000 1663.760000 ;
      RECT 755.645000 1663.480000 760.825000 1663.760000 ;
      RECT 750.045000 1663.480000 755.225000 1663.760000 ;
      RECT 744.445000 1663.480000 749.625000 1663.760000 ;
      RECT 738.845000 1663.480000 744.025000 1663.760000 ;
      RECT 733.245000 1663.480000 738.425000 1663.760000 ;
      RECT 727.645000 1663.480000 732.825000 1663.760000 ;
      RECT 721.765000 1663.480000 727.225000 1663.760000 ;
      RECT 716.165000 1663.480000 721.345000 1663.760000 ;
      RECT 710.565000 1663.480000 715.745000 1663.760000 ;
      RECT 704.965000 1663.480000 710.145000 1663.760000 ;
      RECT 699.365000 1663.480000 704.545000 1663.760000 ;
      RECT 693.765000 1663.480000 698.945000 1663.760000 ;
      RECT 688.165000 1663.480000 693.345000 1663.760000 ;
      RECT 682.285000 1663.480000 687.745000 1663.760000 ;
      RECT 676.685000 1663.480000 681.865000 1663.760000 ;
      RECT 671.085000 1663.480000 676.265000 1663.760000 ;
      RECT 665.485000 1663.480000 670.665000 1663.760000 ;
      RECT 659.885000 1663.480000 665.065000 1663.760000 ;
      RECT 654.285000 1663.480000 659.465000 1663.760000 ;
      RECT 648.685000 1663.480000 653.865000 1663.760000 ;
      RECT 643.085000 1663.480000 648.265000 1663.760000 ;
      RECT 637.205000 1663.480000 642.665000 1663.760000 ;
      RECT 631.605000 1663.480000 636.785000 1663.760000 ;
      RECT 626.005000 1663.480000 631.185000 1663.760000 ;
      RECT 620.405000 1663.480000 625.585000 1663.760000 ;
      RECT 614.805000 1663.480000 619.985000 1663.760000 ;
      RECT 609.205000 1663.480000 614.385000 1663.760000 ;
      RECT 603.605000 1663.480000 608.785000 1663.760000 ;
      RECT 598.005000 1663.480000 603.185000 1663.760000 ;
      RECT 592.125000 1663.480000 597.585000 1663.760000 ;
      RECT 586.525000 1663.480000 591.705000 1663.760000 ;
      RECT 580.925000 1663.480000 586.105000 1663.760000 ;
      RECT 575.325000 1663.480000 580.505000 1663.760000 ;
      RECT 569.725000 1663.480000 574.905000 1663.760000 ;
      RECT 564.125000 1663.480000 569.305000 1663.760000 ;
      RECT 558.525000 1663.480000 563.705000 1663.760000 ;
      RECT 552.645000 1663.480000 558.105000 1663.760000 ;
      RECT 547.045000 1663.480000 552.225000 1663.760000 ;
      RECT 541.445000 1663.480000 546.625000 1663.760000 ;
      RECT 535.845000 1663.480000 541.025000 1663.760000 ;
      RECT 530.245000 1663.480000 535.425000 1663.760000 ;
      RECT 524.645000 1663.480000 529.825000 1663.760000 ;
      RECT 519.045000 1663.480000 524.225000 1663.760000 ;
      RECT 513.445000 1663.480000 518.625000 1663.760000 ;
      RECT 507.565000 1663.480000 513.025000 1663.760000 ;
      RECT 501.965000 1663.480000 507.145000 1663.760000 ;
      RECT 496.365000 1663.480000 501.545000 1663.760000 ;
      RECT 490.765000 1663.480000 495.945000 1663.760000 ;
      RECT 485.165000 1663.480000 490.345000 1663.760000 ;
      RECT 479.565000 1663.480000 484.745000 1663.760000 ;
      RECT 473.965000 1663.480000 479.145000 1663.760000 ;
      RECT 468.085000 1663.480000 473.545000 1663.760000 ;
      RECT 462.485000 1663.480000 467.665000 1663.760000 ;
      RECT 456.885000 1663.480000 462.065000 1663.760000 ;
      RECT 451.285000 1663.480000 456.465000 1663.760000 ;
      RECT 445.685000 1663.480000 450.865000 1663.760000 ;
      RECT 440.085000 1663.480000 445.265000 1663.760000 ;
      RECT 434.485000 1663.480000 439.665000 1663.760000 ;
      RECT 428.885000 1663.480000 434.065000 1663.760000 ;
      RECT 423.005000 1663.480000 428.465000 1663.760000 ;
      RECT 417.405000 1663.480000 422.585000 1663.760000 ;
      RECT 411.805000 1663.480000 416.985000 1663.760000 ;
      RECT 406.205000 1663.480000 411.385000 1663.760000 ;
      RECT 400.605000 1663.480000 405.785000 1663.760000 ;
      RECT 395.005000 1663.480000 400.185000 1663.760000 ;
      RECT 389.405000 1663.480000 394.585000 1663.760000 ;
      RECT 383.525000 1663.480000 388.985000 1663.760000 ;
      RECT 377.925000 1663.480000 383.105000 1663.760000 ;
      RECT 372.325000 1663.480000 377.505000 1663.760000 ;
      RECT 366.725000 1663.480000 371.905000 1663.760000 ;
      RECT 361.125000 1663.480000 366.305000 1663.760000 ;
      RECT 355.525000 1663.480000 360.705000 1663.760000 ;
      RECT 349.925000 1663.480000 355.105000 1663.760000 ;
      RECT 344.325000 1663.480000 349.505000 1663.760000 ;
      RECT 338.445000 1663.480000 343.905000 1663.760000 ;
      RECT 332.845000 1663.480000 338.025000 1663.760000 ;
      RECT 327.245000 1663.480000 332.425000 1663.760000 ;
      RECT 321.645000 1663.480000 326.825000 1663.760000 ;
      RECT 316.045000 1663.480000 321.225000 1663.760000 ;
      RECT 310.445000 1663.480000 315.625000 1663.760000 ;
      RECT 304.845000 1663.480000 310.025000 1663.760000 ;
      RECT 299.245000 1663.480000 304.425000 1663.760000 ;
      RECT 293.365000 1663.480000 298.825000 1663.760000 ;
      RECT 287.765000 1663.480000 292.945000 1663.760000 ;
      RECT 282.165000 1663.480000 287.345000 1663.760000 ;
      RECT 276.565000 1663.480000 281.745000 1663.760000 ;
      RECT 270.965000 1663.480000 276.145000 1663.760000 ;
      RECT 265.365000 1663.480000 270.545000 1663.760000 ;
      RECT 259.765000 1663.480000 264.945000 1663.760000 ;
      RECT 253.885000 1663.480000 259.345000 1663.760000 ;
      RECT 248.285000 1663.480000 253.465000 1663.760000 ;
      RECT 242.685000 1663.480000 247.865000 1663.760000 ;
      RECT 237.085000 1663.480000 242.265000 1663.760000 ;
      RECT 231.485000 1663.480000 236.665000 1663.760000 ;
      RECT 225.885000 1663.480000 231.065000 1663.760000 ;
      RECT 220.285000 1663.480000 225.465000 1663.760000 ;
      RECT 214.685000 1663.480000 219.865000 1663.760000 ;
      RECT 208.805000 1663.480000 214.265000 1663.760000 ;
      RECT 203.205000 1663.480000 208.385000 1663.760000 ;
      RECT 197.605000 1663.480000 202.785000 1663.760000 ;
      RECT 192.005000 1663.480000 197.185000 1663.760000 ;
      RECT 186.405000 1663.480000 191.585000 1663.760000 ;
      RECT 180.805000 1663.480000 185.985000 1663.760000 ;
      RECT 175.205000 1663.480000 180.385000 1663.760000 ;
      RECT 169.325000 1663.480000 174.785000 1663.760000 ;
      RECT 163.725000 1663.480000 168.905000 1663.760000 ;
      RECT 158.125000 1663.480000 163.305000 1663.760000 ;
      RECT 152.525000 1663.480000 157.705000 1663.760000 ;
      RECT 146.925000 1663.480000 152.105000 1663.760000 ;
      RECT 141.325000 1663.480000 146.505000 1663.760000 ;
      RECT 135.725000 1663.480000 140.905000 1663.760000 ;
      RECT 130.125000 1663.480000 135.305000 1663.760000 ;
      RECT 124.245000 1663.480000 129.705000 1663.760000 ;
      RECT 118.645000 1663.480000 123.825000 1663.760000 ;
      RECT 113.045000 1663.480000 118.225000 1663.760000 ;
      RECT 107.445000 1663.480000 112.625000 1663.760000 ;
      RECT 101.845000 1663.480000 107.025000 1663.760000 ;
      RECT 96.245000 1663.480000 101.425000 1663.760000 ;
      RECT 90.645000 1663.480000 95.825000 1663.760000 ;
      RECT 84.765000 1663.480000 90.225000 1663.760000 ;
      RECT 79.165000 1663.480000 84.345000 1663.760000 ;
      RECT 73.565000 1663.480000 78.745000 1663.760000 ;
      RECT 67.965000 1663.480000 73.145000 1663.760000 ;
      RECT 62.365000 1663.480000 67.545000 1663.760000 ;
      RECT 56.765000 1663.480000 61.945000 1663.760000 ;
      RECT 51.165000 1663.480000 56.345000 1663.760000 ;
      RECT 45.565000 1663.480000 50.745000 1663.760000 ;
      RECT 39.685000 1663.480000 45.145000 1663.760000 ;
      RECT 34.085000 1663.480000 39.265000 1663.760000 ;
      RECT 28.485000 1663.480000 33.665000 1663.760000 ;
      RECT 22.885000 1663.480000 28.065000 1663.760000 ;
      RECT 17.285000 1663.480000 22.465000 1663.760000 ;
      RECT 11.685000 1663.480000 16.865000 1663.760000 ;
      RECT 6.085000 1663.480000 11.265000 1663.760000 ;
      RECT 0.485000 1663.480000 5.665000 1663.760000 ;
      RECT 0.000000 1663.480000 0.065000 1663.760000 ;
      RECT 0.000000 0.280000 1663.450000 1663.480000 ;
      RECT 1663.405000 0.000000 1663.450000 0.280000 ;
      RECT 1657.805000 0.000000 1662.985000 0.280000 ;
      RECT 1652.205000 0.000000 1657.385000 0.280000 ;
      RECT 1646.605000 0.000000 1651.785000 0.280000 ;
      RECT 1641.005000 0.000000 1646.185000 0.280000 ;
      RECT 1635.405000 0.000000 1640.585000 0.280000 ;
      RECT 1629.805000 0.000000 1634.985000 0.280000 ;
      RECT 1624.205000 0.000000 1629.385000 0.280000 ;
      RECT 1618.325000 0.000000 1623.785000 0.280000 ;
      RECT 1612.725000 0.000000 1617.905000 0.280000 ;
      RECT 1607.125000 0.000000 1612.305000 0.280000 ;
      RECT 1601.525000 0.000000 1606.705000 0.280000 ;
      RECT 1595.925000 0.000000 1601.105000 0.280000 ;
      RECT 1590.325000 0.000000 1595.505000 0.280000 ;
      RECT 1584.725000 0.000000 1589.905000 0.280000 ;
      RECT 1579.125000 0.000000 1584.305000 0.280000 ;
      RECT 1573.245000 0.000000 1578.705000 0.280000 ;
      RECT 1567.645000 0.000000 1572.825000 0.280000 ;
      RECT 1562.045000 0.000000 1567.225000 0.280000 ;
      RECT 1556.445000 0.000000 1561.625000 0.280000 ;
      RECT 1550.845000 0.000000 1556.025000 0.280000 ;
      RECT 1545.245000 0.000000 1550.425000 0.280000 ;
      RECT 1539.645000 0.000000 1544.825000 0.280000 ;
      RECT 1533.765000 0.000000 1539.225000 0.280000 ;
      RECT 1528.165000 0.000000 1533.345000 0.280000 ;
      RECT 1522.565000 0.000000 1527.745000 0.280000 ;
      RECT 1516.965000 0.000000 1522.145000 0.280000 ;
      RECT 1511.365000 0.000000 1516.545000 0.280000 ;
      RECT 1505.765000 0.000000 1510.945000 0.280000 ;
      RECT 1500.165000 0.000000 1505.345000 0.280000 ;
      RECT 1494.565000 0.000000 1499.745000 0.280000 ;
      RECT 1488.685000 0.000000 1494.145000 0.280000 ;
      RECT 1483.085000 0.000000 1488.265000 0.280000 ;
      RECT 1477.485000 0.000000 1482.665000 0.280000 ;
      RECT 1471.885000 0.000000 1477.065000 0.280000 ;
      RECT 1466.285000 0.000000 1471.465000 0.280000 ;
      RECT 1460.685000 0.000000 1465.865000 0.280000 ;
      RECT 1455.085000 0.000000 1460.265000 0.280000 ;
      RECT 1449.205000 0.000000 1454.665000 0.280000 ;
      RECT 1443.605000 0.000000 1448.785000 0.280000 ;
      RECT 1438.005000 0.000000 1443.185000 0.280000 ;
      RECT 1432.405000 0.000000 1437.585000 0.280000 ;
      RECT 1426.805000 0.000000 1431.985000 0.280000 ;
      RECT 1421.205000 0.000000 1426.385000 0.280000 ;
      RECT 1415.605000 0.000000 1420.785000 0.280000 ;
      RECT 1410.005000 0.000000 1415.185000 0.280000 ;
      RECT 1404.125000 0.000000 1409.585000 0.280000 ;
      RECT 1398.525000 0.000000 1403.705000 0.280000 ;
      RECT 1392.925000 0.000000 1398.105000 0.280000 ;
      RECT 1387.325000 0.000000 1392.505000 0.280000 ;
      RECT 1381.725000 0.000000 1386.905000 0.280000 ;
      RECT 1376.125000 0.000000 1381.305000 0.280000 ;
      RECT 1370.525000 0.000000 1375.705000 0.280000 ;
      RECT 1364.645000 0.000000 1370.105000 0.280000 ;
      RECT 1359.045000 0.000000 1364.225000 0.280000 ;
      RECT 1353.445000 0.000000 1358.625000 0.280000 ;
      RECT 1347.845000 0.000000 1353.025000 0.280000 ;
      RECT 1342.245000 0.000000 1347.425000 0.280000 ;
      RECT 1336.645000 0.000000 1341.825000 0.280000 ;
      RECT 1331.045000 0.000000 1336.225000 0.280000 ;
      RECT 1325.445000 0.000000 1330.625000 0.280000 ;
      RECT 1319.565000 0.000000 1325.025000 0.280000 ;
      RECT 1313.965000 0.000000 1319.145000 0.280000 ;
      RECT 1308.365000 0.000000 1313.545000 0.280000 ;
      RECT 1302.765000 0.000000 1307.945000 0.280000 ;
      RECT 1297.165000 0.000000 1302.345000 0.280000 ;
      RECT 1291.565000 0.000000 1296.745000 0.280000 ;
      RECT 1285.965000 0.000000 1291.145000 0.280000 ;
      RECT 1280.365000 0.000000 1285.545000 0.280000 ;
      RECT 1274.485000 0.000000 1279.945000 0.280000 ;
      RECT 1268.885000 0.000000 1274.065000 0.280000 ;
      RECT 1263.285000 0.000000 1268.465000 0.280000 ;
      RECT 1257.685000 0.000000 1262.865000 0.280000 ;
      RECT 1252.085000 0.000000 1257.265000 0.280000 ;
      RECT 1246.485000 0.000000 1251.665000 0.280000 ;
      RECT 1240.885000 0.000000 1246.065000 0.280000 ;
      RECT 1235.005000 0.000000 1240.465000 0.280000 ;
      RECT 1229.405000 0.000000 1234.585000 0.280000 ;
      RECT 1223.805000 0.000000 1228.985000 0.280000 ;
      RECT 1218.205000 0.000000 1223.385000 0.280000 ;
      RECT 1212.605000 0.000000 1217.785000 0.280000 ;
      RECT 1207.005000 0.000000 1212.185000 0.280000 ;
      RECT 1201.405000 0.000000 1206.585000 0.280000 ;
      RECT 1195.805000 0.000000 1200.985000 0.280000 ;
      RECT 1189.925000 0.000000 1195.385000 0.280000 ;
      RECT 1184.325000 0.000000 1189.505000 0.280000 ;
      RECT 1178.725000 0.000000 1183.905000 0.280000 ;
      RECT 1173.125000 0.000000 1178.305000 0.280000 ;
      RECT 1167.525000 0.000000 1172.705000 0.280000 ;
      RECT 1161.925000 0.000000 1167.105000 0.280000 ;
      RECT 1156.325000 0.000000 1161.505000 0.280000 ;
      RECT 1150.445000 0.000000 1155.905000 0.280000 ;
      RECT 1144.845000 0.000000 1150.025000 0.280000 ;
      RECT 1139.245000 0.000000 1144.425000 0.280000 ;
      RECT 1133.645000 0.000000 1138.825000 0.280000 ;
      RECT 1128.045000 0.000000 1133.225000 0.280000 ;
      RECT 1122.445000 0.000000 1127.625000 0.280000 ;
      RECT 1116.845000 0.000000 1122.025000 0.280000 ;
      RECT 1111.245000 0.000000 1116.425000 0.280000 ;
      RECT 1105.365000 0.000000 1110.825000 0.280000 ;
      RECT 1099.765000 0.000000 1104.945000 0.280000 ;
      RECT 1094.165000 0.000000 1099.345000 0.280000 ;
      RECT 1088.565000 0.000000 1093.745000 0.280000 ;
      RECT 1082.965000 0.000000 1088.145000 0.280000 ;
      RECT 1077.365000 0.000000 1082.545000 0.280000 ;
      RECT 1071.765000 0.000000 1076.945000 0.280000 ;
      RECT 1065.885000 0.000000 1071.345000 0.280000 ;
      RECT 1060.285000 0.000000 1065.465000 0.280000 ;
      RECT 1054.685000 0.000000 1059.865000 0.280000 ;
      RECT 1049.085000 0.000000 1054.265000 0.280000 ;
      RECT 1043.485000 0.000000 1048.665000 0.280000 ;
      RECT 1037.885000 0.000000 1043.065000 0.280000 ;
      RECT 1032.285000 0.000000 1037.465000 0.280000 ;
      RECT 1026.685000 0.000000 1031.865000 0.280000 ;
      RECT 1020.805000 0.000000 1026.265000 0.280000 ;
      RECT 1015.205000 0.000000 1020.385000 0.280000 ;
      RECT 1009.605000 0.000000 1014.785000 0.280000 ;
      RECT 1004.005000 0.000000 1009.185000 0.280000 ;
      RECT 998.405000 0.000000 1003.585000 0.280000 ;
      RECT 992.805000 0.000000 997.985000 0.280000 ;
      RECT 987.205000 0.000000 992.385000 0.280000 ;
      RECT 981.605000 0.000000 986.785000 0.280000 ;
      RECT 975.725000 0.000000 981.185000 0.280000 ;
      RECT 970.125000 0.000000 975.305000 0.280000 ;
      RECT 964.525000 0.000000 969.705000 0.280000 ;
      RECT 958.925000 0.000000 964.105000 0.280000 ;
      RECT 953.325000 0.000000 958.505000 0.280000 ;
      RECT 947.725000 0.000000 952.905000 0.280000 ;
      RECT 942.125000 0.000000 947.305000 0.280000 ;
      RECT 936.245000 0.000000 941.705000 0.280000 ;
      RECT 930.645000 0.000000 935.825000 0.280000 ;
      RECT 925.045000 0.000000 930.225000 0.280000 ;
      RECT 919.445000 0.000000 924.625000 0.280000 ;
      RECT 913.845000 0.000000 919.025000 0.280000 ;
      RECT 908.245000 0.000000 913.425000 0.280000 ;
      RECT 902.645000 0.000000 907.825000 0.280000 ;
      RECT 897.045000 0.000000 902.225000 0.280000 ;
      RECT 891.165000 0.000000 896.625000 0.280000 ;
      RECT 885.565000 0.000000 890.745000 0.280000 ;
      RECT 879.965000 0.000000 885.145000 0.280000 ;
      RECT 874.365000 0.000000 879.545000 0.280000 ;
      RECT 868.765000 0.000000 873.945000 0.280000 ;
      RECT 863.165000 0.000000 868.345000 0.280000 ;
      RECT 857.565000 0.000000 862.745000 0.280000 ;
      RECT 851.685000 0.000000 857.145000 0.280000 ;
      RECT 846.085000 0.000000 851.265000 0.280000 ;
      RECT 840.485000 0.000000 845.665000 0.280000 ;
      RECT 834.885000 0.000000 840.065000 0.280000 ;
      RECT 829.285000 0.000000 834.465000 0.280000 ;
      RECT 823.685000 0.000000 828.865000 0.280000 ;
      RECT 818.085000 0.000000 823.265000 0.280000 ;
      RECT 812.485000 0.000000 817.665000 0.280000 ;
      RECT 806.605000 0.000000 812.065000 0.280000 ;
      RECT 801.005000 0.000000 806.185000 0.280000 ;
      RECT 795.405000 0.000000 800.585000 0.280000 ;
      RECT 789.805000 0.000000 794.985000 0.280000 ;
      RECT 784.205000 0.000000 789.385000 0.280000 ;
      RECT 778.605000 0.000000 783.785000 0.280000 ;
      RECT 773.005000 0.000000 778.185000 0.280000 ;
      RECT 767.125000 0.000000 772.585000 0.280000 ;
      RECT 761.525000 0.000000 766.705000 0.280000 ;
      RECT 755.925000 0.000000 761.105000 0.280000 ;
      RECT 750.325000 0.000000 755.505000 0.280000 ;
      RECT 744.725000 0.000000 749.905000 0.280000 ;
      RECT 739.125000 0.000000 744.305000 0.280000 ;
      RECT 733.525000 0.000000 738.705000 0.280000 ;
      RECT 727.925000 0.000000 733.105000 0.280000 ;
      RECT 722.045000 0.000000 727.505000 0.280000 ;
      RECT 716.445000 0.000000 721.625000 0.280000 ;
      RECT 710.845000 0.000000 716.025000 0.280000 ;
      RECT 705.245000 0.000000 710.425000 0.280000 ;
      RECT 699.645000 0.000000 704.825000 0.280000 ;
      RECT 694.045000 0.000000 699.225000 0.280000 ;
      RECT 688.445000 0.000000 693.625000 0.280000 ;
      RECT 682.565000 0.000000 688.025000 0.280000 ;
      RECT 676.965000 0.000000 682.145000 0.280000 ;
      RECT 671.365000 0.000000 676.545000 0.280000 ;
      RECT 665.765000 0.000000 670.945000 0.280000 ;
      RECT 660.165000 0.000000 665.345000 0.280000 ;
      RECT 654.565000 0.000000 659.745000 0.280000 ;
      RECT 648.965000 0.000000 654.145000 0.280000 ;
      RECT 643.365000 0.000000 648.545000 0.280000 ;
      RECT 637.485000 0.000000 642.945000 0.280000 ;
      RECT 631.885000 0.000000 637.065000 0.280000 ;
      RECT 626.285000 0.000000 631.465000 0.280000 ;
      RECT 620.685000 0.000000 625.865000 0.280000 ;
      RECT 615.085000 0.000000 620.265000 0.280000 ;
      RECT 609.485000 0.000000 614.665000 0.280000 ;
      RECT 603.885000 0.000000 609.065000 0.280000 ;
      RECT 598.285000 0.000000 603.465000 0.280000 ;
      RECT 592.405000 0.000000 597.865000 0.280000 ;
      RECT 586.805000 0.000000 591.985000 0.280000 ;
      RECT 581.205000 0.000000 586.385000 0.280000 ;
      RECT 575.605000 0.000000 580.785000 0.280000 ;
      RECT 570.005000 0.000000 575.185000 0.280000 ;
      RECT 564.405000 0.000000 569.585000 0.280000 ;
      RECT 558.805000 0.000000 563.985000 0.280000 ;
      RECT 552.925000 0.000000 558.385000 0.280000 ;
      RECT 547.325000 0.000000 552.505000 0.280000 ;
      RECT 541.725000 0.000000 546.905000 0.280000 ;
      RECT 536.125000 0.000000 541.305000 0.280000 ;
      RECT 530.525000 0.000000 535.705000 0.280000 ;
      RECT 524.925000 0.000000 530.105000 0.280000 ;
      RECT 519.325000 0.000000 524.505000 0.280000 ;
      RECT 513.725000 0.000000 518.905000 0.280000 ;
      RECT 507.845000 0.000000 513.305000 0.280000 ;
      RECT 502.245000 0.000000 507.425000 0.280000 ;
      RECT 496.645000 0.000000 501.825000 0.280000 ;
      RECT 491.045000 0.000000 496.225000 0.280000 ;
      RECT 485.445000 0.000000 490.625000 0.280000 ;
      RECT 479.845000 0.000000 485.025000 0.280000 ;
      RECT 474.245000 0.000000 479.425000 0.280000 ;
      RECT 468.365000 0.000000 473.825000 0.280000 ;
      RECT 462.765000 0.000000 467.945000 0.280000 ;
      RECT 457.165000 0.000000 462.345000 0.280000 ;
      RECT 451.565000 0.000000 456.745000 0.280000 ;
      RECT 445.965000 0.000000 451.145000 0.280000 ;
      RECT 440.365000 0.000000 445.545000 0.280000 ;
      RECT 434.765000 0.000000 439.945000 0.280000 ;
      RECT 429.165000 0.000000 434.345000 0.280000 ;
      RECT 423.285000 0.000000 428.745000 0.280000 ;
      RECT 417.685000 0.000000 422.865000 0.280000 ;
      RECT 412.085000 0.000000 417.265000 0.280000 ;
      RECT 406.485000 0.000000 411.665000 0.280000 ;
      RECT 400.885000 0.000000 406.065000 0.280000 ;
      RECT 395.285000 0.000000 400.465000 0.280000 ;
      RECT 389.685000 0.000000 394.865000 0.280000 ;
      RECT 383.805000 0.000000 389.265000 0.280000 ;
      RECT 378.205000 0.000000 383.385000 0.280000 ;
      RECT 372.605000 0.000000 377.785000 0.280000 ;
      RECT 367.005000 0.000000 372.185000 0.280000 ;
      RECT 361.405000 0.000000 366.585000 0.280000 ;
      RECT 355.805000 0.000000 360.985000 0.280000 ;
      RECT 350.205000 0.000000 355.385000 0.280000 ;
      RECT 344.605000 0.000000 349.785000 0.280000 ;
      RECT 338.725000 0.000000 344.185000 0.280000 ;
      RECT 333.125000 0.000000 338.305000 0.280000 ;
      RECT 327.525000 0.000000 332.705000 0.280000 ;
      RECT 321.925000 0.000000 327.105000 0.280000 ;
      RECT 316.325000 0.000000 321.505000 0.280000 ;
      RECT 310.725000 0.000000 315.905000 0.280000 ;
      RECT 305.125000 0.000000 310.305000 0.280000 ;
      RECT 299.525000 0.000000 304.705000 0.280000 ;
      RECT 293.645000 0.000000 299.105000 0.280000 ;
      RECT 288.045000 0.000000 293.225000 0.280000 ;
      RECT 282.445000 0.000000 287.625000 0.280000 ;
      RECT 276.845000 0.000000 282.025000 0.280000 ;
      RECT 271.245000 0.000000 276.425000 0.280000 ;
      RECT 265.645000 0.000000 270.825000 0.280000 ;
      RECT 260.045000 0.000000 265.225000 0.280000 ;
      RECT 254.165000 0.000000 259.625000 0.280000 ;
      RECT 248.565000 0.000000 253.745000 0.280000 ;
      RECT 242.965000 0.000000 248.145000 0.280000 ;
      RECT 237.365000 0.000000 242.545000 0.280000 ;
      RECT 231.765000 0.000000 236.945000 0.280000 ;
      RECT 226.165000 0.000000 231.345000 0.280000 ;
      RECT 220.565000 0.000000 225.745000 0.280000 ;
      RECT 214.965000 0.000000 220.145000 0.280000 ;
      RECT 209.085000 0.000000 214.545000 0.280000 ;
      RECT 203.485000 0.000000 208.665000 0.280000 ;
      RECT 197.885000 0.000000 203.065000 0.280000 ;
      RECT 192.285000 0.000000 197.465000 0.280000 ;
      RECT 186.685000 0.000000 191.865000 0.280000 ;
      RECT 181.085000 0.000000 186.265000 0.280000 ;
      RECT 175.485000 0.000000 180.665000 0.280000 ;
      RECT 169.605000 0.000000 175.065000 0.280000 ;
      RECT 164.005000 0.000000 169.185000 0.280000 ;
      RECT 158.405000 0.000000 163.585000 0.280000 ;
      RECT 152.805000 0.000000 157.985000 0.280000 ;
      RECT 147.205000 0.000000 152.385000 0.280000 ;
      RECT 141.605000 0.000000 146.785000 0.280000 ;
      RECT 136.005000 0.000000 141.185000 0.280000 ;
      RECT 130.405000 0.000000 135.585000 0.280000 ;
      RECT 124.525000 0.000000 129.985000 0.280000 ;
      RECT 118.925000 0.000000 124.105000 0.280000 ;
      RECT 113.325000 0.000000 118.505000 0.280000 ;
      RECT 107.725000 0.000000 112.905000 0.280000 ;
      RECT 102.125000 0.000000 107.305000 0.280000 ;
      RECT 96.525000 0.000000 101.705000 0.280000 ;
      RECT 90.925000 0.000000 96.105000 0.280000 ;
      RECT 85.045000 0.000000 90.505000 0.280000 ;
      RECT 79.445000 0.000000 84.625000 0.280000 ;
      RECT 73.845000 0.000000 79.025000 0.280000 ;
      RECT 68.245000 0.000000 73.425000 0.280000 ;
      RECT 62.645000 0.000000 67.825000 0.280000 ;
      RECT 57.045000 0.000000 62.225000 0.280000 ;
      RECT 51.445000 0.000000 56.625000 0.280000 ;
      RECT 45.845000 0.000000 51.025000 0.280000 ;
      RECT 39.965000 0.000000 45.425000 0.280000 ;
      RECT 34.365000 0.000000 39.545000 0.280000 ;
      RECT 28.765000 0.000000 33.945000 0.280000 ;
      RECT 23.165000 0.000000 28.345000 0.280000 ;
      RECT 17.565000 0.000000 22.745000 0.280000 ;
      RECT 11.965000 0.000000 17.145000 0.280000 ;
      RECT 6.365000 0.000000 11.545000 0.280000 ;
      RECT 0.765000 0.000000 5.945000 0.280000 ;
      RECT 0.000000 0.000000 0.345000 0.280000 ;
    LAYER metal5 ;
      RECT 0.000000 1663.480000 1663.170000 1663.760000 ;
      RECT 0.280000 1663.340000 1663.170000 1663.480000 ;
      RECT 0.280000 1663.060000 1663.450000 1663.340000 ;
      RECT 0.000000 1658.160000 1663.450000 1663.060000 ;
      RECT 0.000000 1657.880000 1663.170000 1658.160000 ;
      RECT 0.280000 1657.740000 1663.170000 1657.880000 ;
      RECT 0.280000 1657.460000 1663.450000 1657.740000 ;
      RECT 0.000000 1652.560000 1663.450000 1657.460000 ;
      RECT 0.000000 1652.280000 1663.170000 1652.560000 ;
      RECT 0.280000 1652.140000 1663.170000 1652.280000 ;
      RECT 0.280000 1651.860000 1663.450000 1652.140000 ;
      RECT 0.000000 1646.960000 1663.450000 1651.860000 ;
      RECT 0.000000 1646.680000 1663.170000 1646.960000 ;
      RECT 0.280000 1646.540000 1663.170000 1646.680000 ;
      RECT 0.280000 1646.260000 1663.450000 1646.540000 ;
      RECT 0.000000 1641.360000 1663.450000 1646.260000 ;
      RECT 0.000000 1641.080000 1663.170000 1641.360000 ;
      RECT 0.280000 1640.940000 1663.170000 1641.080000 ;
      RECT 0.280000 1640.660000 1663.450000 1640.940000 ;
      RECT 0.000000 1635.760000 1663.450000 1640.660000 ;
      RECT 0.000000 1635.480000 1663.170000 1635.760000 ;
      RECT 0.280000 1635.340000 1663.170000 1635.480000 ;
      RECT 0.280000 1635.060000 1663.450000 1635.340000 ;
      RECT 0.000000 1630.160000 1663.450000 1635.060000 ;
      RECT 0.000000 1629.880000 1663.170000 1630.160000 ;
      RECT 0.280000 1629.740000 1663.170000 1629.880000 ;
      RECT 0.280000 1629.460000 1663.450000 1629.740000 ;
      RECT 0.000000 1624.560000 1663.450000 1629.460000 ;
      RECT 0.000000 1624.280000 1663.170000 1624.560000 ;
      RECT 0.280000 1624.140000 1663.170000 1624.280000 ;
      RECT 0.280000 1623.860000 1663.450000 1624.140000 ;
      RECT 0.000000 1618.680000 1663.450000 1623.860000 ;
      RECT 0.000000 1618.400000 1663.170000 1618.680000 ;
      RECT 0.280000 1618.260000 1663.170000 1618.400000 ;
      RECT 0.280000 1617.980000 1663.450000 1618.260000 ;
      RECT 0.000000 1613.080000 1663.450000 1617.980000 ;
      RECT 0.000000 1612.800000 1663.170000 1613.080000 ;
      RECT 0.280000 1612.660000 1663.170000 1612.800000 ;
      RECT 0.280000 1612.380000 1663.450000 1612.660000 ;
      RECT 0.000000 1607.480000 1663.450000 1612.380000 ;
      RECT 0.000000 1607.200000 1663.170000 1607.480000 ;
      RECT 0.280000 1607.060000 1663.170000 1607.200000 ;
      RECT 0.280000 1606.780000 1663.450000 1607.060000 ;
      RECT 0.000000 1601.880000 1663.450000 1606.780000 ;
      RECT 0.000000 1601.600000 1663.170000 1601.880000 ;
      RECT 0.280000 1601.460000 1663.170000 1601.600000 ;
      RECT 0.280000 1601.180000 1663.450000 1601.460000 ;
      RECT 0.000000 1596.280000 1663.450000 1601.180000 ;
      RECT 0.000000 1596.000000 1663.170000 1596.280000 ;
      RECT 0.280000 1595.860000 1663.170000 1596.000000 ;
      RECT 0.280000 1595.580000 1663.450000 1595.860000 ;
      RECT 0.000000 1590.680000 1663.450000 1595.580000 ;
      RECT 0.000000 1590.400000 1663.170000 1590.680000 ;
      RECT 0.280000 1590.260000 1663.170000 1590.400000 ;
      RECT 0.280000 1589.980000 1663.450000 1590.260000 ;
      RECT 0.000000 1585.080000 1663.450000 1589.980000 ;
      RECT 0.000000 1584.800000 1663.170000 1585.080000 ;
      RECT 0.280000 1584.660000 1663.170000 1584.800000 ;
      RECT 0.280000 1584.380000 1663.450000 1584.660000 ;
      RECT 0.000000 1579.200000 1663.450000 1584.380000 ;
      RECT 0.000000 1578.920000 1663.170000 1579.200000 ;
      RECT 0.280000 1578.780000 1663.170000 1578.920000 ;
      RECT 0.280000 1578.500000 1663.450000 1578.780000 ;
      RECT 0.000000 1573.600000 1663.450000 1578.500000 ;
      RECT 0.000000 1573.320000 1663.170000 1573.600000 ;
      RECT 0.280000 1573.180000 1663.170000 1573.320000 ;
      RECT 0.280000 1572.900000 1663.450000 1573.180000 ;
      RECT 0.000000 1568.000000 1663.450000 1572.900000 ;
      RECT 0.000000 1567.720000 1663.170000 1568.000000 ;
      RECT 0.280000 1567.580000 1663.170000 1567.720000 ;
      RECT 0.280000 1567.300000 1663.450000 1567.580000 ;
      RECT 0.000000 1562.400000 1663.450000 1567.300000 ;
      RECT 0.000000 1562.120000 1663.170000 1562.400000 ;
      RECT 0.280000 1561.980000 1663.170000 1562.120000 ;
      RECT 0.280000 1561.700000 1663.450000 1561.980000 ;
      RECT 0.000000 1556.800000 1663.450000 1561.700000 ;
      RECT 0.000000 1556.520000 1663.170000 1556.800000 ;
      RECT 0.280000 1556.380000 1663.170000 1556.520000 ;
      RECT 0.280000 1556.100000 1663.450000 1556.380000 ;
      RECT 0.000000 1551.200000 1663.450000 1556.100000 ;
      RECT 0.000000 1550.920000 1663.170000 1551.200000 ;
      RECT 0.280000 1550.780000 1663.170000 1550.920000 ;
      RECT 0.280000 1550.500000 1663.450000 1550.780000 ;
      RECT 0.000000 1545.600000 1663.450000 1550.500000 ;
      RECT 0.000000 1545.320000 1663.170000 1545.600000 ;
      RECT 0.280000 1545.180000 1663.170000 1545.320000 ;
      RECT 0.280000 1544.900000 1663.450000 1545.180000 ;
      RECT 0.000000 1540.000000 1663.450000 1544.900000 ;
      RECT 0.000000 1539.720000 1663.170000 1540.000000 ;
      RECT 0.280000 1539.580000 1663.170000 1539.720000 ;
      RECT 0.280000 1539.300000 1663.450000 1539.580000 ;
      RECT 0.000000 1534.120000 1663.450000 1539.300000 ;
      RECT 0.000000 1533.840000 1663.170000 1534.120000 ;
      RECT 0.280000 1533.700000 1663.170000 1533.840000 ;
      RECT 0.280000 1533.420000 1663.450000 1533.700000 ;
      RECT 0.000000 1528.520000 1663.450000 1533.420000 ;
      RECT 0.000000 1528.240000 1663.170000 1528.520000 ;
      RECT 0.280000 1528.100000 1663.170000 1528.240000 ;
      RECT 0.280000 1527.820000 1663.450000 1528.100000 ;
      RECT 0.000000 1522.920000 1663.450000 1527.820000 ;
      RECT 0.000000 1522.640000 1663.170000 1522.920000 ;
      RECT 0.280000 1522.500000 1663.170000 1522.640000 ;
      RECT 0.280000 1522.220000 1663.450000 1522.500000 ;
      RECT 0.000000 1517.320000 1663.450000 1522.220000 ;
      RECT 0.000000 1517.040000 1663.170000 1517.320000 ;
      RECT 0.280000 1516.900000 1663.170000 1517.040000 ;
      RECT 0.280000 1516.620000 1663.450000 1516.900000 ;
      RECT 0.000000 1511.720000 1663.450000 1516.620000 ;
      RECT 0.000000 1511.440000 1663.170000 1511.720000 ;
      RECT 0.280000 1511.300000 1663.170000 1511.440000 ;
      RECT 0.280000 1511.020000 1663.450000 1511.300000 ;
      RECT 0.000000 1506.120000 1663.450000 1511.020000 ;
      RECT 0.000000 1505.840000 1663.170000 1506.120000 ;
      RECT 0.280000 1505.700000 1663.170000 1505.840000 ;
      RECT 0.280000 1505.420000 1663.450000 1505.700000 ;
      RECT 0.000000 1500.520000 1663.450000 1505.420000 ;
      RECT 0.000000 1500.240000 1663.170000 1500.520000 ;
      RECT 0.280000 1500.100000 1663.170000 1500.240000 ;
      RECT 0.280000 1499.820000 1663.450000 1500.100000 ;
      RECT 0.000000 1494.640000 1663.450000 1499.820000 ;
      RECT 0.000000 1494.360000 1663.170000 1494.640000 ;
      RECT 0.280000 1494.220000 1663.170000 1494.360000 ;
      RECT 0.280000 1493.940000 1663.450000 1494.220000 ;
      RECT 0.000000 1489.040000 1663.450000 1493.940000 ;
      RECT 0.000000 1488.760000 1663.170000 1489.040000 ;
      RECT 0.280000 1488.620000 1663.170000 1488.760000 ;
      RECT 0.280000 1488.340000 1663.450000 1488.620000 ;
      RECT 0.000000 1483.440000 1663.450000 1488.340000 ;
      RECT 0.000000 1483.160000 1663.170000 1483.440000 ;
      RECT 0.280000 1483.020000 1663.170000 1483.160000 ;
      RECT 0.280000 1482.740000 1663.450000 1483.020000 ;
      RECT 0.000000 1477.840000 1663.450000 1482.740000 ;
      RECT 0.000000 1477.560000 1663.170000 1477.840000 ;
      RECT 0.280000 1477.420000 1663.170000 1477.560000 ;
      RECT 0.280000 1477.140000 1663.450000 1477.420000 ;
      RECT 0.000000 1472.240000 1663.450000 1477.140000 ;
      RECT 0.000000 1471.960000 1663.170000 1472.240000 ;
      RECT 0.280000 1471.820000 1663.170000 1471.960000 ;
      RECT 0.280000 1471.540000 1663.450000 1471.820000 ;
      RECT 0.000000 1466.640000 1663.450000 1471.540000 ;
      RECT 0.000000 1466.360000 1663.170000 1466.640000 ;
      RECT 0.280000 1466.220000 1663.170000 1466.360000 ;
      RECT 0.280000 1465.940000 1663.450000 1466.220000 ;
      RECT 0.000000 1461.040000 1663.450000 1465.940000 ;
      RECT 0.000000 1460.760000 1663.170000 1461.040000 ;
      RECT 0.280000 1460.620000 1663.170000 1460.760000 ;
      RECT 0.280000 1460.340000 1663.450000 1460.620000 ;
      RECT 0.000000 1455.160000 1663.450000 1460.340000 ;
      RECT 0.000000 1454.880000 1663.170000 1455.160000 ;
      RECT 0.280000 1454.740000 1663.170000 1454.880000 ;
      RECT 0.280000 1454.460000 1663.450000 1454.740000 ;
      RECT 0.000000 1449.560000 1663.450000 1454.460000 ;
      RECT 0.000000 1449.280000 1663.170000 1449.560000 ;
      RECT 0.280000 1449.140000 1663.170000 1449.280000 ;
      RECT 0.280000 1448.860000 1663.450000 1449.140000 ;
      RECT 0.000000 1443.960000 1663.450000 1448.860000 ;
      RECT 0.000000 1443.680000 1663.170000 1443.960000 ;
      RECT 0.280000 1443.540000 1663.170000 1443.680000 ;
      RECT 0.280000 1443.260000 1663.450000 1443.540000 ;
      RECT 0.000000 1438.360000 1663.450000 1443.260000 ;
      RECT 0.000000 1438.080000 1663.170000 1438.360000 ;
      RECT 0.280000 1437.940000 1663.170000 1438.080000 ;
      RECT 0.280000 1437.660000 1663.450000 1437.940000 ;
      RECT 0.000000 1432.760000 1663.450000 1437.660000 ;
      RECT 0.000000 1432.480000 1663.170000 1432.760000 ;
      RECT 0.280000 1432.340000 1663.170000 1432.480000 ;
      RECT 0.280000 1432.060000 1663.450000 1432.340000 ;
      RECT 0.000000 1427.160000 1663.450000 1432.060000 ;
      RECT 0.000000 1426.880000 1663.170000 1427.160000 ;
      RECT 0.280000 1426.740000 1663.170000 1426.880000 ;
      RECT 0.280000 1426.460000 1663.450000 1426.740000 ;
      RECT 0.000000 1421.560000 1663.450000 1426.460000 ;
      RECT 0.000000 1421.280000 1663.170000 1421.560000 ;
      RECT 0.280000 1421.140000 1663.170000 1421.280000 ;
      RECT 0.280000 1420.860000 1663.450000 1421.140000 ;
      RECT 0.000000 1415.960000 1663.450000 1420.860000 ;
      RECT 0.000000 1415.680000 1663.170000 1415.960000 ;
      RECT 0.280000 1415.540000 1663.170000 1415.680000 ;
      RECT 0.280000 1415.260000 1663.450000 1415.540000 ;
      RECT 0.000000 1410.080000 1663.450000 1415.260000 ;
      RECT 0.000000 1409.800000 1663.170000 1410.080000 ;
      RECT 0.280000 1409.660000 1663.170000 1409.800000 ;
      RECT 0.280000 1409.380000 1663.450000 1409.660000 ;
      RECT 0.000000 1404.480000 1663.450000 1409.380000 ;
      RECT 0.000000 1404.200000 1663.170000 1404.480000 ;
      RECT 0.280000 1404.060000 1663.170000 1404.200000 ;
      RECT 0.280000 1403.780000 1663.450000 1404.060000 ;
      RECT 0.000000 1398.880000 1663.450000 1403.780000 ;
      RECT 0.000000 1398.600000 1663.170000 1398.880000 ;
      RECT 0.280000 1398.460000 1663.170000 1398.600000 ;
      RECT 0.280000 1398.180000 1663.450000 1398.460000 ;
      RECT 0.000000 1393.280000 1663.450000 1398.180000 ;
      RECT 0.000000 1393.000000 1663.170000 1393.280000 ;
      RECT 0.280000 1392.860000 1663.170000 1393.000000 ;
      RECT 0.280000 1392.580000 1663.450000 1392.860000 ;
      RECT 0.000000 1387.680000 1663.450000 1392.580000 ;
      RECT 0.000000 1387.400000 1663.170000 1387.680000 ;
      RECT 0.280000 1387.260000 1663.170000 1387.400000 ;
      RECT 0.280000 1386.980000 1663.450000 1387.260000 ;
      RECT 0.000000 1382.080000 1663.450000 1386.980000 ;
      RECT 0.000000 1381.800000 1663.170000 1382.080000 ;
      RECT 0.280000 1381.660000 1663.170000 1381.800000 ;
      RECT 0.280000 1381.380000 1663.450000 1381.660000 ;
      RECT 0.000000 1376.480000 1663.450000 1381.380000 ;
      RECT 0.000000 1376.200000 1663.170000 1376.480000 ;
      RECT 0.280000 1376.060000 1663.170000 1376.200000 ;
      RECT 0.280000 1375.780000 1663.450000 1376.060000 ;
      RECT 0.000000 1370.600000 1663.450000 1375.780000 ;
      RECT 0.000000 1370.320000 1663.170000 1370.600000 ;
      RECT 0.280000 1370.180000 1663.170000 1370.320000 ;
      RECT 0.280000 1369.900000 1663.450000 1370.180000 ;
      RECT 0.000000 1365.000000 1663.450000 1369.900000 ;
      RECT 0.000000 1364.720000 1663.170000 1365.000000 ;
      RECT 0.280000 1364.580000 1663.170000 1364.720000 ;
      RECT 0.280000 1364.300000 1663.450000 1364.580000 ;
      RECT 0.000000 1359.400000 1663.450000 1364.300000 ;
      RECT 0.000000 1359.120000 1663.170000 1359.400000 ;
      RECT 0.280000 1358.980000 1663.170000 1359.120000 ;
      RECT 0.280000 1358.700000 1663.450000 1358.980000 ;
      RECT 0.000000 1353.800000 1663.450000 1358.700000 ;
      RECT 0.000000 1353.520000 1663.170000 1353.800000 ;
      RECT 0.280000 1353.380000 1663.170000 1353.520000 ;
      RECT 0.280000 1353.100000 1663.450000 1353.380000 ;
      RECT 0.000000 1348.200000 1663.450000 1353.100000 ;
      RECT 0.000000 1347.920000 1663.170000 1348.200000 ;
      RECT 0.280000 1347.780000 1663.170000 1347.920000 ;
      RECT 0.280000 1347.500000 1663.450000 1347.780000 ;
      RECT 0.000000 1342.600000 1663.450000 1347.500000 ;
      RECT 0.000000 1342.320000 1663.170000 1342.600000 ;
      RECT 0.280000 1342.180000 1663.170000 1342.320000 ;
      RECT 0.280000 1341.900000 1663.450000 1342.180000 ;
      RECT 0.000000 1337.000000 1663.450000 1341.900000 ;
      RECT 0.000000 1336.720000 1663.170000 1337.000000 ;
      RECT 0.280000 1336.580000 1663.170000 1336.720000 ;
      RECT 0.280000 1336.300000 1663.450000 1336.580000 ;
      RECT 0.000000 1331.400000 1663.450000 1336.300000 ;
      RECT 0.000000 1331.120000 1663.170000 1331.400000 ;
      RECT 0.280000 1330.980000 1663.170000 1331.120000 ;
      RECT 0.280000 1330.700000 1663.450000 1330.980000 ;
      RECT 0.000000 1325.520000 1663.450000 1330.700000 ;
      RECT 0.000000 1325.240000 1663.170000 1325.520000 ;
      RECT 0.280000 1325.100000 1663.170000 1325.240000 ;
      RECT 0.280000 1324.820000 1663.450000 1325.100000 ;
      RECT 0.000000 1319.920000 1663.450000 1324.820000 ;
      RECT 0.000000 1319.640000 1663.170000 1319.920000 ;
      RECT 0.280000 1319.500000 1663.170000 1319.640000 ;
      RECT 0.280000 1319.220000 1663.450000 1319.500000 ;
      RECT 0.000000 1314.320000 1663.450000 1319.220000 ;
      RECT 0.000000 1314.040000 1663.170000 1314.320000 ;
      RECT 0.280000 1313.900000 1663.170000 1314.040000 ;
      RECT 0.280000 1313.620000 1663.450000 1313.900000 ;
      RECT 0.000000 1308.720000 1663.450000 1313.620000 ;
      RECT 0.000000 1308.440000 1663.170000 1308.720000 ;
      RECT 0.280000 1308.300000 1663.170000 1308.440000 ;
      RECT 0.280000 1308.020000 1663.450000 1308.300000 ;
      RECT 0.000000 1303.120000 1663.450000 1308.020000 ;
      RECT 0.000000 1302.840000 1663.170000 1303.120000 ;
      RECT 0.280000 1302.700000 1663.170000 1302.840000 ;
      RECT 0.280000 1302.420000 1663.450000 1302.700000 ;
      RECT 0.000000 1297.520000 1663.450000 1302.420000 ;
      RECT 0.000000 1297.240000 1663.170000 1297.520000 ;
      RECT 0.280000 1297.100000 1663.170000 1297.240000 ;
      RECT 0.280000 1296.820000 1663.450000 1297.100000 ;
      RECT 0.000000 1291.920000 1663.450000 1296.820000 ;
      RECT 0.000000 1291.640000 1663.170000 1291.920000 ;
      RECT 0.280000 1291.500000 1663.170000 1291.640000 ;
      RECT 0.280000 1291.220000 1663.450000 1291.500000 ;
      RECT 0.000000 1286.040000 1663.450000 1291.220000 ;
      RECT 0.000000 1285.760000 1663.170000 1286.040000 ;
      RECT 0.280000 1285.620000 1663.170000 1285.760000 ;
      RECT 0.280000 1285.340000 1663.450000 1285.620000 ;
      RECT 0.000000 1280.440000 1663.450000 1285.340000 ;
      RECT 0.000000 1280.160000 1663.170000 1280.440000 ;
      RECT 0.280000 1280.020000 1663.170000 1280.160000 ;
      RECT 0.280000 1279.740000 1663.450000 1280.020000 ;
      RECT 0.000000 1274.840000 1663.450000 1279.740000 ;
      RECT 0.000000 1274.560000 1663.170000 1274.840000 ;
      RECT 0.280000 1274.420000 1663.170000 1274.560000 ;
      RECT 0.280000 1274.140000 1663.450000 1274.420000 ;
      RECT 0.000000 1269.240000 1663.450000 1274.140000 ;
      RECT 0.000000 1268.960000 1663.170000 1269.240000 ;
      RECT 0.280000 1268.820000 1663.170000 1268.960000 ;
      RECT 0.280000 1268.540000 1663.450000 1268.820000 ;
      RECT 0.000000 1263.640000 1663.450000 1268.540000 ;
      RECT 0.000000 1263.360000 1663.170000 1263.640000 ;
      RECT 0.280000 1263.220000 1663.170000 1263.360000 ;
      RECT 0.280000 1262.940000 1663.450000 1263.220000 ;
      RECT 0.000000 1258.040000 1663.450000 1262.940000 ;
      RECT 0.000000 1257.760000 1663.170000 1258.040000 ;
      RECT 0.280000 1257.620000 1663.170000 1257.760000 ;
      RECT 0.280000 1257.340000 1663.450000 1257.620000 ;
      RECT 0.000000 1252.440000 1663.450000 1257.340000 ;
      RECT 0.000000 1252.160000 1663.170000 1252.440000 ;
      RECT 0.280000 1252.020000 1663.170000 1252.160000 ;
      RECT 0.280000 1251.740000 1663.450000 1252.020000 ;
      RECT 0.000000 1246.560000 1663.450000 1251.740000 ;
      RECT 0.000000 1246.280000 1663.170000 1246.560000 ;
      RECT 0.280000 1246.140000 1663.170000 1246.280000 ;
      RECT 0.280000 1245.860000 1663.450000 1246.140000 ;
      RECT 0.000000 1240.960000 1663.450000 1245.860000 ;
      RECT 0.000000 1240.680000 1663.170000 1240.960000 ;
      RECT 0.280000 1240.540000 1663.170000 1240.680000 ;
      RECT 0.280000 1240.260000 1663.450000 1240.540000 ;
      RECT 0.000000 1235.360000 1663.450000 1240.260000 ;
      RECT 0.000000 1235.080000 1663.170000 1235.360000 ;
      RECT 0.280000 1234.940000 1663.170000 1235.080000 ;
      RECT 0.280000 1234.660000 1663.450000 1234.940000 ;
      RECT 0.000000 1229.760000 1663.450000 1234.660000 ;
      RECT 0.000000 1229.480000 1663.170000 1229.760000 ;
      RECT 0.280000 1229.340000 1663.170000 1229.480000 ;
      RECT 0.280000 1229.060000 1663.450000 1229.340000 ;
      RECT 0.000000 1224.160000 1663.450000 1229.060000 ;
      RECT 0.000000 1223.880000 1663.170000 1224.160000 ;
      RECT 0.280000 1223.740000 1663.170000 1223.880000 ;
      RECT 0.280000 1223.460000 1663.450000 1223.740000 ;
      RECT 0.000000 1218.560000 1663.450000 1223.460000 ;
      RECT 0.000000 1218.280000 1663.170000 1218.560000 ;
      RECT 0.280000 1218.140000 1663.170000 1218.280000 ;
      RECT 0.280000 1217.860000 1663.450000 1218.140000 ;
      RECT 0.000000 1212.960000 1663.450000 1217.860000 ;
      RECT 0.000000 1212.680000 1663.170000 1212.960000 ;
      RECT 0.280000 1212.540000 1663.170000 1212.680000 ;
      RECT 0.280000 1212.260000 1663.450000 1212.540000 ;
      RECT 0.000000 1207.360000 1663.450000 1212.260000 ;
      RECT 0.000000 1207.080000 1663.170000 1207.360000 ;
      RECT 0.280000 1206.940000 1663.170000 1207.080000 ;
      RECT 0.280000 1206.660000 1663.450000 1206.940000 ;
      RECT 0.000000 1201.480000 1663.450000 1206.660000 ;
      RECT 0.000000 1201.200000 1663.170000 1201.480000 ;
      RECT 0.280000 1201.060000 1663.170000 1201.200000 ;
      RECT 0.280000 1200.780000 1663.450000 1201.060000 ;
      RECT 0.000000 1195.880000 1663.450000 1200.780000 ;
      RECT 0.000000 1195.600000 1663.170000 1195.880000 ;
      RECT 0.280000 1195.460000 1663.170000 1195.600000 ;
      RECT 0.280000 1195.180000 1663.450000 1195.460000 ;
      RECT 0.000000 1190.280000 1663.450000 1195.180000 ;
      RECT 0.000000 1190.000000 1663.170000 1190.280000 ;
      RECT 0.280000 1189.860000 1663.170000 1190.000000 ;
      RECT 0.280000 1189.580000 1663.450000 1189.860000 ;
      RECT 0.000000 1184.680000 1663.450000 1189.580000 ;
      RECT 0.000000 1184.400000 1663.170000 1184.680000 ;
      RECT 0.280000 1184.260000 1663.170000 1184.400000 ;
      RECT 0.280000 1183.980000 1663.450000 1184.260000 ;
      RECT 0.000000 1179.080000 1663.450000 1183.980000 ;
      RECT 0.000000 1178.800000 1663.170000 1179.080000 ;
      RECT 0.280000 1178.660000 1663.170000 1178.800000 ;
      RECT 0.280000 1178.380000 1663.450000 1178.660000 ;
      RECT 0.000000 1173.480000 1663.450000 1178.380000 ;
      RECT 0.000000 1173.200000 1663.170000 1173.480000 ;
      RECT 0.280000 1173.060000 1663.170000 1173.200000 ;
      RECT 0.280000 1172.780000 1663.450000 1173.060000 ;
      RECT 0.000000 1167.880000 1663.450000 1172.780000 ;
      RECT 0.000000 1167.600000 1663.170000 1167.880000 ;
      RECT 0.280000 1167.460000 1663.170000 1167.600000 ;
      RECT 0.280000 1167.180000 1663.450000 1167.460000 ;
      RECT 0.000000 1162.000000 1663.450000 1167.180000 ;
      RECT 0.000000 1161.720000 1663.170000 1162.000000 ;
      RECT 0.280000 1161.580000 1663.170000 1161.720000 ;
      RECT 0.280000 1161.300000 1663.450000 1161.580000 ;
      RECT 0.000000 1156.400000 1663.450000 1161.300000 ;
      RECT 0.000000 1156.120000 1663.170000 1156.400000 ;
      RECT 0.280000 1155.980000 1663.170000 1156.120000 ;
      RECT 0.280000 1155.700000 1663.450000 1155.980000 ;
      RECT 0.000000 1150.800000 1663.450000 1155.700000 ;
      RECT 0.000000 1150.520000 1663.170000 1150.800000 ;
      RECT 0.280000 1150.380000 1663.170000 1150.520000 ;
      RECT 0.280000 1150.100000 1663.450000 1150.380000 ;
      RECT 0.000000 1145.200000 1663.450000 1150.100000 ;
      RECT 0.000000 1144.920000 1663.170000 1145.200000 ;
      RECT 0.280000 1144.780000 1663.170000 1144.920000 ;
      RECT 0.280000 1144.500000 1663.450000 1144.780000 ;
      RECT 0.000000 1139.600000 1663.450000 1144.500000 ;
      RECT 0.000000 1139.320000 1663.170000 1139.600000 ;
      RECT 0.280000 1139.180000 1663.170000 1139.320000 ;
      RECT 0.280000 1138.900000 1663.450000 1139.180000 ;
      RECT 0.000000 1134.000000 1663.450000 1138.900000 ;
      RECT 0.000000 1133.720000 1663.170000 1134.000000 ;
      RECT 0.280000 1133.580000 1663.170000 1133.720000 ;
      RECT 0.280000 1133.300000 1663.450000 1133.580000 ;
      RECT 0.000000 1128.400000 1663.450000 1133.300000 ;
      RECT 0.000000 1128.120000 1663.170000 1128.400000 ;
      RECT 0.280000 1127.980000 1663.170000 1128.120000 ;
      RECT 0.280000 1127.700000 1663.450000 1127.980000 ;
      RECT 0.000000 1122.520000 1663.450000 1127.700000 ;
      RECT 0.000000 1122.240000 1663.170000 1122.520000 ;
      RECT 0.280000 1122.100000 1663.170000 1122.240000 ;
      RECT 0.280000 1121.820000 1663.450000 1122.100000 ;
      RECT 0.000000 1116.920000 1663.450000 1121.820000 ;
      RECT 0.000000 1116.640000 1663.170000 1116.920000 ;
      RECT 0.280000 1116.500000 1663.170000 1116.640000 ;
      RECT 0.280000 1116.220000 1663.450000 1116.500000 ;
      RECT 0.000000 1111.320000 1663.450000 1116.220000 ;
      RECT 0.000000 1111.040000 1663.170000 1111.320000 ;
      RECT 0.280000 1110.900000 1663.170000 1111.040000 ;
      RECT 0.280000 1110.620000 1663.450000 1110.900000 ;
      RECT 0.000000 1105.720000 1663.450000 1110.620000 ;
      RECT 0.000000 1105.440000 1663.170000 1105.720000 ;
      RECT 0.280000 1105.300000 1663.170000 1105.440000 ;
      RECT 0.280000 1105.020000 1663.450000 1105.300000 ;
      RECT 0.000000 1100.120000 1663.450000 1105.020000 ;
      RECT 0.000000 1099.840000 1663.170000 1100.120000 ;
      RECT 0.280000 1099.700000 1663.170000 1099.840000 ;
      RECT 0.280000 1099.420000 1663.450000 1099.700000 ;
      RECT 0.000000 1094.520000 1663.450000 1099.420000 ;
      RECT 0.000000 1094.240000 1663.170000 1094.520000 ;
      RECT 0.280000 1094.100000 1663.170000 1094.240000 ;
      RECT 0.280000 1093.820000 1663.450000 1094.100000 ;
      RECT 0.000000 1088.920000 1663.450000 1093.820000 ;
      RECT 0.000000 1088.640000 1663.170000 1088.920000 ;
      RECT 0.280000 1088.500000 1663.170000 1088.640000 ;
      RECT 0.280000 1088.220000 1663.450000 1088.500000 ;
      RECT 0.000000 1083.320000 1663.450000 1088.220000 ;
      RECT 0.000000 1083.040000 1663.170000 1083.320000 ;
      RECT 0.280000 1082.900000 1663.170000 1083.040000 ;
      RECT 0.280000 1082.620000 1663.450000 1082.900000 ;
      RECT 0.000000 1077.440000 1663.450000 1082.620000 ;
      RECT 0.000000 1077.160000 1663.170000 1077.440000 ;
      RECT 0.280000 1077.020000 1663.170000 1077.160000 ;
      RECT 0.280000 1076.740000 1663.450000 1077.020000 ;
      RECT 0.000000 1071.840000 1663.450000 1076.740000 ;
      RECT 0.000000 1071.560000 1663.170000 1071.840000 ;
      RECT 0.280000 1071.420000 1663.170000 1071.560000 ;
      RECT 0.280000 1071.140000 1663.450000 1071.420000 ;
      RECT 0.000000 1066.240000 1663.450000 1071.140000 ;
      RECT 0.000000 1065.960000 1663.170000 1066.240000 ;
      RECT 0.280000 1065.820000 1663.170000 1065.960000 ;
      RECT 0.280000 1065.540000 1663.450000 1065.820000 ;
      RECT 0.000000 1060.640000 1663.450000 1065.540000 ;
      RECT 0.000000 1060.360000 1663.170000 1060.640000 ;
      RECT 0.280000 1060.220000 1663.170000 1060.360000 ;
      RECT 0.280000 1059.940000 1663.450000 1060.220000 ;
      RECT 0.000000 1055.040000 1663.450000 1059.940000 ;
      RECT 0.000000 1054.760000 1663.170000 1055.040000 ;
      RECT 0.280000 1054.620000 1663.170000 1054.760000 ;
      RECT 0.280000 1054.340000 1663.450000 1054.620000 ;
      RECT 0.000000 1049.440000 1663.450000 1054.340000 ;
      RECT 0.000000 1049.160000 1663.170000 1049.440000 ;
      RECT 0.280000 1049.020000 1663.170000 1049.160000 ;
      RECT 0.280000 1048.740000 1663.450000 1049.020000 ;
      RECT 0.000000 1043.840000 1663.450000 1048.740000 ;
      RECT 0.000000 1043.560000 1663.170000 1043.840000 ;
      RECT 0.280000 1043.420000 1663.170000 1043.560000 ;
      RECT 0.280000 1043.140000 1663.450000 1043.420000 ;
      RECT 0.000000 1037.960000 1663.450000 1043.140000 ;
      RECT 0.000000 1037.680000 1663.170000 1037.960000 ;
      RECT 0.280000 1037.540000 1663.170000 1037.680000 ;
      RECT 0.280000 1037.260000 1663.450000 1037.540000 ;
      RECT 0.000000 1032.360000 1663.450000 1037.260000 ;
      RECT 0.000000 1032.080000 1663.170000 1032.360000 ;
      RECT 0.280000 1031.940000 1663.170000 1032.080000 ;
      RECT 0.280000 1031.660000 1663.450000 1031.940000 ;
      RECT 0.000000 1026.760000 1663.450000 1031.660000 ;
      RECT 0.000000 1026.480000 1663.170000 1026.760000 ;
      RECT 0.280000 1026.340000 1663.170000 1026.480000 ;
      RECT 0.280000 1026.060000 1663.450000 1026.340000 ;
      RECT 0.000000 1021.160000 1663.450000 1026.060000 ;
      RECT 0.000000 1020.880000 1663.170000 1021.160000 ;
      RECT 0.280000 1020.740000 1663.170000 1020.880000 ;
      RECT 0.280000 1020.460000 1663.450000 1020.740000 ;
      RECT 0.000000 1015.560000 1663.450000 1020.460000 ;
      RECT 0.000000 1015.280000 1663.170000 1015.560000 ;
      RECT 0.280000 1015.140000 1663.170000 1015.280000 ;
      RECT 0.280000 1014.860000 1663.450000 1015.140000 ;
      RECT 0.000000 1009.960000 1663.450000 1014.860000 ;
      RECT 0.000000 1009.680000 1663.170000 1009.960000 ;
      RECT 0.280000 1009.540000 1663.170000 1009.680000 ;
      RECT 0.280000 1009.260000 1663.450000 1009.540000 ;
      RECT 0.000000 1004.360000 1663.450000 1009.260000 ;
      RECT 0.000000 1004.080000 1663.170000 1004.360000 ;
      RECT 0.280000 1003.940000 1663.170000 1004.080000 ;
      RECT 0.280000 1003.660000 1663.450000 1003.940000 ;
      RECT 0.000000 998.760000 1663.450000 1003.660000 ;
      RECT 0.000000 998.480000 1663.170000 998.760000 ;
      RECT 0.280000 998.340000 1663.170000 998.480000 ;
      RECT 0.280000 998.060000 1663.450000 998.340000 ;
      RECT 0.000000 992.880000 1663.450000 998.060000 ;
      RECT 0.000000 992.600000 1663.170000 992.880000 ;
      RECT 0.280000 992.460000 1663.170000 992.600000 ;
      RECT 0.280000 992.180000 1663.450000 992.460000 ;
      RECT 0.000000 987.280000 1663.450000 992.180000 ;
      RECT 0.000000 987.000000 1663.170000 987.280000 ;
      RECT 0.280000 986.860000 1663.170000 987.000000 ;
      RECT 0.280000 986.580000 1663.450000 986.860000 ;
      RECT 0.000000 981.680000 1663.450000 986.580000 ;
      RECT 0.000000 981.400000 1663.170000 981.680000 ;
      RECT 0.280000 981.260000 1663.170000 981.400000 ;
      RECT 0.280000 980.980000 1663.450000 981.260000 ;
      RECT 0.000000 976.080000 1663.450000 980.980000 ;
      RECT 0.000000 975.800000 1663.170000 976.080000 ;
      RECT 0.280000 975.660000 1663.170000 975.800000 ;
      RECT 0.280000 975.380000 1663.450000 975.660000 ;
      RECT 0.000000 970.480000 1663.450000 975.380000 ;
      RECT 0.000000 970.200000 1663.170000 970.480000 ;
      RECT 0.280000 970.060000 1663.170000 970.200000 ;
      RECT 0.280000 969.780000 1663.450000 970.060000 ;
      RECT 0.000000 964.880000 1663.450000 969.780000 ;
      RECT 0.000000 964.600000 1663.170000 964.880000 ;
      RECT 0.280000 964.460000 1663.170000 964.600000 ;
      RECT 0.280000 964.180000 1663.450000 964.460000 ;
      RECT 0.000000 959.280000 1663.450000 964.180000 ;
      RECT 0.000000 959.000000 1663.170000 959.280000 ;
      RECT 0.280000 958.860000 1663.170000 959.000000 ;
      RECT 0.280000 958.580000 1663.450000 958.860000 ;
      RECT 0.000000 953.400000 1663.450000 958.580000 ;
      RECT 0.000000 953.120000 1663.170000 953.400000 ;
      RECT 0.280000 952.980000 1663.170000 953.120000 ;
      RECT 0.280000 952.700000 1663.450000 952.980000 ;
      RECT 0.000000 947.800000 1663.450000 952.700000 ;
      RECT 0.000000 947.520000 1663.170000 947.800000 ;
      RECT 0.280000 947.380000 1663.170000 947.520000 ;
      RECT 0.280000 947.100000 1663.450000 947.380000 ;
      RECT 0.000000 942.200000 1663.450000 947.100000 ;
      RECT 0.000000 941.920000 1663.170000 942.200000 ;
      RECT 0.280000 941.780000 1663.170000 941.920000 ;
      RECT 0.280000 941.500000 1663.450000 941.780000 ;
      RECT 0.000000 936.600000 1663.450000 941.500000 ;
      RECT 0.000000 936.320000 1663.170000 936.600000 ;
      RECT 0.280000 936.180000 1663.170000 936.320000 ;
      RECT 0.280000 935.900000 1663.450000 936.180000 ;
      RECT 0.000000 931.000000 1663.450000 935.900000 ;
      RECT 0.000000 930.720000 1663.170000 931.000000 ;
      RECT 0.280000 930.580000 1663.170000 930.720000 ;
      RECT 0.280000 930.300000 1663.450000 930.580000 ;
      RECT 0.000000 925.400000 1663.450000 930.300000 ;
      RECT 0.000000 925.120000 1663.170000 925.400000 ;
      RECT 0.280000 924.980000 1663.170000 925.120000 ;
      RECT 0.280000 924.700000 1663.450000 924.980000 ;
      RECT 0.000000 919.800000 1663.450000 924.700000 ;
      RECT 0.000000 919.520000 1663.170000 919.800000 ;
      RECT 0.280000 919.380000 1663.170000 919.520000 ;
      RECT 0.280000 919.100000 1663.450000 919.380000 ;
      RECT 0.000000 913.920000 1663.450000 919.100000 ;
      RECT 0.000000 913.640000 1663.170000 913.920000 ;
      RECT 0.280000 913.500000 1663.170000 913.640000 ;
      RECT 0.280000 913.220000 1663.450000 913.500000 ;
      RECT 0.000000 908.320000 1663.450000 913.220000 ;
      RECT 0.000000 908.040000 1663.170000 908.320000 ;
      RECT 0.280000 907.900000 1663.170000 908.040000 ;
      RECT 0.280000 907.620000 1663.450000 907.900000 ;
      RECT 0.000000 902.720000 1663.450000 907.620000 ;
      RECT 0.000000 902.440000 1663.170000 902.720000 ;
      RECT 0.280000 902.300000 1663.170000 902.440000 ;
      RECT 0.280000 902.020000 1663.450000 902.300000 ;
      RECT 0.000000 897.120000 1663.450000 902.020000 ;
      RECT 0.000000 896.840000 1663.170000 897.120000 ;
      RECT 0.280000 896.700000 1663.170000 896.840000 ;
      RECT 0.280000 896.420000 1663.450000 896.700000 ;
      RECT 0.000000 891.520000 1663.450000 896.420000 ;
      RECT 0.000000 891.240000 1663.170000 891.520000 ;
      RECT 0.280000 891.100000 1663.170000 891.240000 ;
      RECT 0.280000 890.820000 1663.450000 891.100000 ;
      RECT 0.000000 885.920000 1663.450000 890.820000 ;
      RECT 0.000000 885.640000 1663.170000 885.920000 ;
      RECT 0.280000 885.500000 1663.170000 885.640000 ;
      RECT 0.280000 885.220000 1663.450000 885.500000 ;
      RECT 0.000000 880.320000 1663.450000 885.220000 ;
      RECT 0.000000 880.040000 1663.170000 880.320000 ;
      RECT 0.280000 879.900000 1663.170000 880.040000 ;
      RECT 0.280000 879.620000 1663.450000 879.900000 ;
      RECT 0.000000 874.720000 1663.450000 879.620000 ;
      RECT 0.000000 874.440000 1663.170000 874.720000 ;
      RECT 0.280000 874.300000 1663.170000 874.440000 ;
      RECT 0.280000 874.020000 1663.450000 874.300000 ;
      RECT 0.000000 868.840000 1663.450000 874.020000 ;
      RECT 0.000000 868.560000 1663.170000 868.840000 ;
      RECT 0.280000 868.420000 1663.170000 868.560000 ;
      RECT 0.280000 868.140000 1663.450000 868.420000 ;
      RECT 0.000000 863.240000 1663.450000 868.140000 ;
      RECT 0.000000 862.960000 1663.170000 863.240000 ;
      RECT 0.280000 862.820000 1663.170000 862.960000 ;
      RECT 0.280000 862.540000 1663.450000 862.820000 ;
      RECT 0.000000 857.640000 1663.450000 862.540000 ;
      RECT 0.000000 857.360000 1663.170000 857.640000 ;
      RECT 0.280000 857.220000 1663.170000 857.360000 ;
      RECT 0.280000 856.940000 1663.450000 857.220000 ;
      RECT 0.000000 852.040000 1663.450000 856.940000 ;
      RECT 0.000000 851.760000 1663.170000 852.040000 ;
      RECT 0.280000 851.620000 1663.170000 851.760000 ;
      RECT 0.280000 851.340000 1663.450000 851.620000 ;
      RECT 0.000000 846.440000 1663.450000 851.340000 ;
      RECT 0.000000 846.160000 1663.170000 846.440000 ;
      RECT 0.280000 846.020000 1663.170000 846.160000 ;
      RECT 0.280000 845.740000 1663.450000 846.020000 ;
      RECT 0.000000 840.840000 1663.450000 845.740000 ;
      RECT 0.000000 840.560000 1663.170000 840.840000 ;
      RECT 0.280000 840.420000 1663.170000 840.560000 ;
      RECT 0.280000 840.140000 1663.450000 840.420000 ;
      RECT 0.000000 835.240000 1663.450000 840.140000 ;
      RECT 0.000000 834.960000 1663.170000 835.240000 ;
      RECT 0.280000 834.820000 1663.170000 834.960000 ;
      RECT 0.280000 834.540000 1663.450000 834.820000 ;
      RECT 0.000000 829.360000 1663.450000 834.540000 ;
      RECT 0.000000 829.080000 1663.170000 829.360000 ;
      RECT 0.280000 828.940000 1663.170000 829.080000 ;
      RECT 0.280000 828.660000 1663.450000 828.940000 ;
      RECT 0.000000 823.760000 1663.450000 828.660000 ;
      RECT 0.000000 823.480000 1663.170000 823.760000 ;
      RECT 0.280000 823.340000 1663.170000 823.480000 ;
      RECT 0.280000 823.060000 1663.450000 823.340000 ;
      RECT 0.000000 818.160000 1663.450000 823.060000 ;
      RECT 0.000000 817.880000 1663.170000 818.160000 ;
      RECT 0.280000 817.740000 1663.170000 817.880000 ;
      RECT 0.280000 817.460000 1663.450000 817.740000 ;
      RECT 0.000000 812.560000 1663.450000 817.460000 ;
      RECT 0.000000 812.280000 1663.170000 812.560000 ;
      RECT 0.280000 812.140000 1663.170000 812.280000 ;
      RECT 0.280000 811.860000 1663.450000 812.140000 ;
      RECT 0.000000 806.960000 1663.450000 811.860000 ;
      RECT 0.000000 806.680000 1663.170000 806.960000 ;
      RECT 0.280000 806.540000 1663.170000 806.680000 ;
      RECT 0.280000 806.260000 1663.450000 806.540000 ;
      RECT 0.000000 801.360000 1663.450000 806.260000 ;
      RECT 0.000000 801.080000 1663.170000 801.360000 ;
      RECT 0.280000 800.940000 1663.170000 801.080000 ;
      RECT 0.280000 800.660000 1663.450000 800.940000 ;
      RECT 0.000000 795.760000 1663.450000 800.660000 ;
      RECT 0.000000 795.480000 1663.170000 795.760000 ;
      RECT 0.280000 795.340000 1663.170000 795.480000 ;
      RECT 0.280000 795.060000 1663.450000 795.340000 ;
      RECT 0.000000 789.880000 1663.450000 795.060000 ;
      RECT 0.000000 789.600000 1663.170000 789.880000 ;
      RECT 0.280000 789.460000 1663.170000 789.600000 ;
      RECT 0.280000 789.180000 1663.450000 789.460000 ;
      RECT 0.000000 784.280000 1663.450000 789.180000 ;
      RECT 0.000000 784.000000 1663.170000 784.280000 ;
      RECT 0.280000 783.860000 1663.170000 784.000000 ;
      RECT 0.280000 783.580000 1663.450000 783.860000 ;
      RECT 0.000000 778.680000 1663.450000 783.580000 ;
      RECT 0.000000 778.400000 1663.170000 778.680000 ;
      RECT 0.280000 778.260000 1663.170000 778.400000 ;
      RECT 0.280000 777.980000 1663.450000 778.260000 ;
      RECT 0.000000 773.080000 1663.450000 777.980000 ;
      RECT 0.000000 772.800000 1663.170000 773.080000 ;
      RECT 0.280000 772.660000 1663.170000 772.800000 ;
      RECT 0.280000 772.380000 1663.450000 772.660000 ;
      RECT 0.000000 767.480000 1663.450000 772.380000 ;
      RECT 0.000000 767.200000 1663.170000 767.480000 ;
      RECT 0.280000 767.060000 1663.170000 767.200000 ;
      RECT 0.280000 766.780000 1663.450000 767.060000 ;
      RECT 0.000000 761.880000 1663.450000 766.780000 ;
      RECT 0.000000 761.600000 1663.170000 761.880000 ;
      RECT 0.280000 761.460000 1663.170000 761.600000 ;
      RECT 0.280000 761.180000 1663.450000 761.460000 ;
      RECT 0.000000 756.280000 1663.450000 761.180000 ;
      RECT 0.000000 756.000000 1663.170000 756.280000 ;
      RECT 0.280000 755.860000 1663.170000 756.000000 ;
      RECT 0.280000 755.580000 1663.450000 755.860000 ;
      RECT 0.000000 750.680000 1663.450000 755.580000 ;
      RECT 0.000000 750.400000 1663.170000 750.680000 ;
      RECT 0.280000 750.260000 1663.170000 750.400000 ;
      RECT 0.280000 749.980000 1663.450000 750.260000 ;
      RECT 0.000000 744.800000 1663.450000 749.980000 ;
      RECT 0.000000 744.520000 1663.170000 744.800000 ;
      RECT 0.280000 744.380000 1663.170000 744.520000 ;
      RECT 0.280000 744.100000 1663.450000 744.380000 ;
      RECT 0.000000 739.200000 1663.450000 744.100000 ;
      RECT 0.000000 738.920000 1663.170000 739.200000 ;
      RECT 0.280000 738.780000 1663.170000 738.920000 ;
      RECT 0.280000 738.500000 1663.450000 738.780000 ;
      RECT 0.000000 733.600000 1663.450000 738.500000 ;
      RECT 0.000000 733.320000 1663.170000 733.600000 ;
      RECT 0.280000 733.180000 1663.170000 733.320000 ;
      RECT 0.280000 732.900000 1663.450000 733.180000 ;
      RECT 0.000000 728.000000 1663.450000 732.900000 ;
      RECT 0.000000 727.720000 1663.170000 728.000000 ;
      RECT 0.280000 727.580000 1663.170000 727.720000 ;
      RECT 0.280000 727.300000 1663.450000 727.580000 ;
      RECT 0.000000 722.400000 1663.450000 727.300000 ;
      RECT 0.000000 722.120000 1663.170000 722.400000 ;
      RECT 0.280000 721.980000 1663.170000 722.120000 ;
      RECT 0.280000 721.700000 1663.450000 721.980000 ;
      RECT 0.000000 716.800000 1663.450000 721.700000 ;
      RECT 0.000000 716.520000 1663.170000 716.800000 ;
      RECT 0.280000 716.380000 1663.170000 716.520000 ;
      RECT 0.280000 716.100000 1663.450000 716.380000 ;
      RECT 0.000000 711.200000 1663.450000 716.100000 ;
      RECT 0.000000 710.920000 1663.170000 711.200000 ;
      RECT 0.280000 710.780000 1663.170000 710.920000 ;
      RECT 0.280000 710.500000 1663.450000 710.780000 ;
      RECT 0.000000 705.320000 1663.450000 710.500000 ;
      RECT 0.000000 705.040000 1663.170000 705.320000 ;
      RECT 0.280000 704.900000 1663.170000 705.040000 ;
      RECT 0.280000 704.620000 1663.450000 704.900000 ;
      RECT 0.000000 699.720000 1663.450000 704.620000 ;
      RECT 0.000000 699.440000 1663.170000 699.720000 ;
      RECT 0.280000 699.300000 1663.170000 699.440000 ;
      RECT 0.280000 699.020000 1663.450000 699.300000 ;
      RECT 0.000000 694.120000 1663.450000 699.020000 ;
      RECT 0.000000 693.840000 1663.170000 694.120000 ;
      RECT 0.280000 693.700000 1663.170000 693.840000 ;
      RECT 0.280000 693.420000 1663.450000 693.700000 ;
      RECT 0.000000 688.520000 1663.450000 693.420000 ;
      RECT 0.000000 688.240000 1663.170000 688.520000 ;
      RECT 0.280000 688.100000 1663.170000 688.240000 ;
      RECT 0.280000 687.820000 1663.450000 688.100000 ;
      RECT 0.000000 682.920000 1663.450000 687.820000 ;
      RECT 0.000000 682.640000 1663.170000 682.920000 ;
      RECT 0.280000 682.500000 1663.170000 682.640000 ;
      RECT 0.280000 682.220000 1663.450000 682.500000 ;
      RECT 0.000000 677.320000 1663.450000 682.220000 ;
      RECT 0.000000 677.040000 1663.170000 677.320000 ;
      RECT 0.280000 676.900000 1663.170000 677.040000 ;
      RECT 0.280000 676.620000 1663.450000 676.900000 ;
      RECT 0.000000 671.720000 1663.450000 676.620000 ;
      RECT 0.000000 671.440000 1663.170000 671.720000 ;
      RECT 0.280000 671.300000 1663.170000 671.440000 ;
      RECT 0.280000 671.020000 1663.450000 671.300000 ;
      RECT 0.000000 665.840000 1663.450000 671.020000 ;
      RECT 0.000000 665.560000 1663.170000 665.840000 ;
      RECT 0.280000 665.420000 1663.170000 665.560000 ;
      RECT 0.280000 665.140000 1663.450000 665.420000 ;
      RECT 0.000000 660.240000 1663.450000 665.140000 ;
      RECT 0.000000 659.960000 1663.170000 660.240000 ;
      RECT 0.280000 659.820000 1663.170000 659.960000 ;
      RECT 0.280000 659.540000 1663.450000 659.820000 ;
      RECT 0.000000 654.640000 1663.450000 659.540000 ;
      RECT 0.000000 654.360000 1663.170000 654.640000 ;
      RECT 0.280000 654.220000 1663.170000 654.360000 ;
      RECT 0.280000 653.940000 1663.450000 654.220000 ;
      RECT 0.000000 649.040000 1663.450000 653.940000 ;
      RECT 0.000000 648.760000 1663.170000 649.040000 ;
      RECT 0.280000 648.620000 1663.170000 648.760000 ;
      RECT 0.280000 648.340000 1663.450000 648.620000 ;
      RECT 0.000000 643.440000 1663.450000 648.340000 ;
      RECT 0.000000 643.160000 1663.170000 643.440000 ;
      RECT 0.280000 643.020000 1663.170000 643.160000 ;
      RECT 0.280000 642.740000 1663.450000 643.020000 ;
      RECT 0.000000 637.840000 1663.450000 642.740000 ;
      RECT 0.000000 637.560000 1663.170000 637.840000 ;
      RECT 0.280000 637.420000 1663.170000 637.560000 ;
      RECT 0.280000 637.140000 1663.450000 637.420000 ;
      RECT 0.000000 632.240000 1663.450000 637.140000 ;
      RECT 0.000000 631.960000 1663.170000 632.240000 ;
      RECT 0.280000 631.820000 1663.170000 631.960000 ;
      RECT 0.280000 631.540000 1663.450000 631.820000 ;
      RECT 0.000000 626.640000 1663.450000 631.540000 ;
      RECT 0.000000 626.360000 1663.170000 626.640000 ;
      RECT 0.280000 626.220000 1663.170000 626.360000 ;
      RECT 0.280000 625.940000 1663.450000 626.220000 ;
      RECT 0.000000 620.760000 1663.450000 625.940000 ;
      RECT 0.000000 620.480000 1663.170000 620.760000 ;
      RECT 0.280000 620.340000 1663.170000 620.480000 ;
      RECT 0.280000 620.060000 1663.450000 620.340000 ;
      RECT 0.000000 615.160000 1663.450000 620.060000 ;
      RECT 0.000000 614.880000 1663.170000 615.160000 ;
      RECT 0.280000 614.740000 1663.170000 614.880000 ;
      RECT 0.280000 614.460000 1663.450000 614.740000 ;
      RECT 0.000000 609.560000 1663.450000 614.460000 ;
      RECT 0.000000 609.280000 1663.170000 609.560000 ;
      RECT 0.280000 609.140000 1663.170000 609.280000 ;
      RECT 0.280000 608.860000 1663.450000 609.140000 ;
      RECT 0.000000 603.960000 1663.450000 608.860000 ;
      RECT 0.000000 603.680000 1663.170000 603.960000 ;
      RECT 0.280000 603.540000 1663.170000 603.680000 ;
      RECT 0.280000 603.260000 1663.450000 603.540000 ;
      RECT 0.000000 598.360000 1663.450000 603.260000 ;
      RECT 0.000000 598.080000 1663.170000 598.360000 ;
      RECT 0.280000 597.940000 1663.170000 598.080000 ;
      RECT 0.280000 597.660000 1663.450000 597.940000 ;
      RECT 0.000000 592.760000 1663.450000 597.660000 ;
      RECT 0.000000 592.480000 1663.170000 592.760000 ;
      RECT 0.280000 592.340000 1663.170000 592.480000 ;
      RECT 0.280000 592.060000 1663.450000 592.340000 ;
      RECT 0.000000 587.160000 1663.450000 592.060000 ;
      RECT 0.000000 586.880000 1663.170000 587.160000 ;
      RECT 0.280000 586.740000 1663.170000 586.880000 ;
      RECT 0.280000 586.460000 1663.450000 586.740000 ;
      RECT 0.000000 581.280000 1663.450000 586.460000 ;
      RECT 0.000000 581.000000 1663.170000 581.280000 ;
      RECT 0.280000 580.860000 1663.170000 581.000000 ;
      RECT 0.280000 580.580000 1663.450000 580.860000 ;
      RECT 0.000000 575.680000 1663.450000 580.580000 ;
      RECT 0.000000 575.400000 1663.170000 575.680000 ;
      RECT 0.280000 575.260000 1663.170000 575.400000 ;
      RECT 0.280000 574.980000 1663.450000 575.260000 ;
      RECT 0.000000 570.080000 1663.450000 574.980000 ;
      RECT 0.000000 569.800000 1663.170000 570.080000 ;
      RECT 0.280000 569.660000 1663.170000 569.800000 ;
      RECT 0.280000 569.380000 1663.450000 569.660000 ;
      RECT 0.000000 564.480000 1663.450000 569.380000 ;
      RECT 0.000000 564.200000 1663.170000 564.480000 ;
      RECT 0.280000 564.060000 1663.170000 564.200000 ;
      RECT 0.280000 563.780000 1663.450000 564.060000 ;
      RECT 0.000000 558.880000 1663.450000 563.780000 ;
      RECT 0.000000 558.600000 1663.170000 558.880000 ;
      RECT 0.280000 558.460000 1663.170000 558.600000 ;
      RECT 0.280000 558.180000 1663.450000 558.460000 ;
      RECT 0.000000 553.280000 1663.450000 558.180000 ;
      RECT 0.000000 553.000000 1663.170000 553.280000 ;
      RECT 0.280000 552.860000 1663.170000 553.000000 ;
      RECT 0.280000 552.580000 1663.450000 552.860000 ;
      RECT 0.000000 547.680000 1663.450000 552.580000 ;
      RECT 0.000000 547.400000 1663.170000 547.680000 ;
      RECT 0.280000 547.260000 1663.170000 547.400000 ;
      RECT 0.280000 546.980000 1663.450000 547.260000 ;
      RECT 0.000000 542.080000 1663.450000 546.980000 ;
      RECT 0.000000 541.800000 1663.170000 542.080000 ;
      RECT 0.280000 541.660000 1663.170000 541.800000 ;
      RECT 0.280000 541.380000 1663.450000 541.660000 ;
      RECT 0.000000 536.200000 1663.450000 541.380000 ;
      RECT 0.000000 535.920000 1663.170000 536.200000 ;
      RECT 0.280000 535.780000 1663.170000 535.920000 ;
      RECT 0.280000 535.500000 1663.450000 535.780000 ;
      RECT 0.000000 530.600000 1663.450000 535.500000 ;
      RECT 0.000000 530.320000 1663.170000 530.600000 ;
      RECT 0.280000 530.180000 1663.170000 530.320000 ;
      RECT 0.280000 529.900000 1663.450000 530.180000 ;
      RECT 0.000000 525.000000 1663.450000 529.900000 ;
      RECT 0.000000 524.720000 1663.170000 525.000000 ;
      RECT 0.280000 524.580000 1663.170000 524.720000 ;
      RECT 0.280000 524.300000 1663.450000 524.580000 ;
      RECT 0.000000 519.400000 1663.450000 524.300000 ;
      RECT 0.000000 519.120000 1663.170000 519.400000 ;
      RECT 0.280000 518.980000 1663.170000 519.120000 ;
      RECT 0.280000 518.700000 1663.450000 518.980000 ;
      RECT 0.000000 513.800000 1663.450000 518.700000 ;
      RECT 0.000000 513.520000 1663.170000 513.800000 ;
      RECT 0.280000 513.380000 1663.170000 513.520000 ;
      RECT 0.280000 513.100000 1663.450000 513.380000 ;
      RECT 0.000000 508.200000 1663.450000 513.100000 ;
      RECT 0.000000 507.920000 1663.170000 508.200000 ;
      RECT 0.280000 507.780000 1663.170000 507.920000 ;
      RECT 0.280000 507.500000 1663.450000 507.780000 ;
      RECT 0.000000 502.600000 1663.450000 507.500000 ;
      RECT 0.000000 502.320000 1663.170000 502.600000 ;
      RECT 0.280000 502.180000 1663.170000 502.320000 ;
      RECT 0.280000 501.900000 1663.450000 502.180000 ;
      RECT 0.000000 496.720000 1663.450000 501.900000 ;
      RECT 0.000000 496.440000 1663.170000 496.720000 ;
      RECT 0.280000 496.300000 1663.170000 496.440000 ;
      RECT 0.280000 496.020000 1663.450000 496.300000 ;
      RECT 0.000000 491.120000 1663.450000 496.020000 ;
      RECT 0.000000 490.840000 1663.170000 491.120000 ;
      RECT 0.280000 490.700000 1663.170000 490.840000 ;
      RECT 0.280000 490.420000 1663.450000 490.700000 ;
      RECT 0.000000 485.520000 1663.450000 490.420000 ;
      RECT 0.000000 485.240000 1663.170000 485.520000 ;
      RECT 0.280000 485.100000 1663.170000 485.240000 ;
      RECT 0.280000 484.820000 1663.450000 485.100000 ;
      RECT 0.000000 479.920000 1663.450000 484.820000 ;
      RECT 0.000000 479.640000 1663.170000 479.920000 ;
      RECT 0.280000 479.500000 1663.170000 479.640000 ;
      RECT 0.280000 479.220000 1663.450000 479.500000 ;
      RECT 0.000000 474.320000 1663.450000 479.220000 ;
      RECT 0.000000 474.040000 1663.170000 474.320000 ;
      RECT 0.280000 473.900000 1663.170000 474.040000 ;
      RECT 0.280000 473.620000 1663.450000 473.900000 ;
      RECT 0.000000 468.720000 1663.450000 473.620000 ;
      RECT 0.000000 468.440000 1663.170000 468.720000 ;
      RECT 0.280000 468.300000 1663.170000 468.440000 ;
      RECT 0.280000 468.020000 1663.450000 468.300000 ;
      RECT 0.000000 463.120000 1663.450000 468.020000 ;
      RECT 0.000000 462.840000 1663.170000 463.120000 ;
      RECT 0.280000 462.700000 1663.170000 462.840000 ;
      RECT 0.280000 462.420000 1663.450000 462.700000 ;
      RECT 0.000000 457.240000 1663.450000 462.420000 ;
      RECT 0.000000 456.960000 1663.170000 457.240000 ;
      RECT 0.280000 456.820000 1663.170000 456.960000 ;
      RECT 0.280000 456.540000 1663.450000 456.820000 ;
      RECT 0.000000 451.640000 1663.450000 456.540000 ;
      RECT 0.000000 451.360000 1663.170000 451.640000 ;
      RECT 0.280000 451.220000 1663.170000 451.360000 ;
      RECT 0.280000 450.940000 1663.450000 451.220000 ;
      RECT 0.000000 446.040000 1663.450000 450.940000 ;
      RECT 0.000000 445.760000 1663.170000 446.040000 ;
      RECT 0.280000 445.620000 1663.170000 445.760000 ;
      RECT 0.280000 445.340000 1663.450000 445.620000 ;
      RECT 0.000000 440.440000 1663.450000 445.340000 ;
      RECT 0.000000 440.160000 1663.170000 440.440000 ;
      RECT 0.280000 440.020000 1663.170000 440.160000 ;
      RECT 0.280000 439.740000 1663.450000 440.020000 ;
      RECT 0.000000 434.840000 1663.450000 439.740000 ;
      RECT 0.000000 434.560000 1663.170000 434.840000 ;
      RECT 0.280000 434.420000 1663.170000 434.560000 ;
      RECT 0.280000 434.140000 1663.450000 434.420000 ;
      RECT 0.000000 429.240000 1663.450000 434.140000 ;
      RECT 0.000000 428.960000 1663.170000 429.240000 ;
      RECT 0.280000 428.820000 1663.170000 428.960000 ;
      RECT 0.280000 428.540000 1663.450000 428.820000 ;
      RECT 0.000000 423.640000 1663.450000 428.540000 ;
      RECT 0.000000 423.360000 1663.170000 423.640000 ;
      RECT 0.280000 423.220000 1663.170000 423.360000 ;
      RECT 0.280000 422.940000 1663.450000 423.220000 ;
      RECT 0.000000 418.040000 1663.450000 422.940000 ;
      RECT 0.000000 417.760000 1663.170000 418.040000 ;
      RECT 0.280000 417.620000 1663.170000 417.760000 ;
      RECT 0.280000 417.340000 1663.450000 417.620000 ;
      RECT 0.000000 412.160000 1663.450000 417.340000 ;
      RECT 0.000000 411.880000 1663.170000 412.160000 ;
      RECT 0.280000 411.740000 1663.170000 411.880000 ;
      RECT 0.280000 411.460000 1663.450000 411.740000 ;
      RECT 0.000000 406.560000 1663.450000 411.460000 ;
      RECT 0.000000 406.280000 1663.170000 406.560000 ;
      RECT 0.280000 406.140000 1663.170000 406.280000 ;
      RECT 0.280000 405.860000 1663.450000 406.140000 ;
      RECT 0.000000 400.960000 1663.450000 405.860000 ;
      RECT 0.000000 400.680000 1663.170000 400.960000 ;
      RECT 0.280000 400.540000 1663.170000 400.680000 ;
      RECT 0.280000 400.260000 1663.450000 400.540000 ;
      RECT 0.000000 395.360000 1663.450000 400.260000 ;
      RECT 0.000000 395.080000 1663.170000 395.360000 ;
      RECT 0.280000 394.940000 1663.170000 395.080000 ;
      RECT 0.280000 394.660000 1663.450000 394.940000 ;
      RECT 0.000000 389.760000 1663.450000 394.660000 ;
      RECT 0.000000 389.480000 1663.170000 389.760000 ;
      RECT 0.280000 389.340000 1663.170000 389.480000 ;
      RECT 0.280000 389.060000 1663.450000 389.340000 ;
      RECT 0.000000 384.160000 1663.450000 389.060000 ;
      RECT 0.000000 383.880000 1663.170000 384.160000 ;
      RECT 0.280000 383.740000 1663.170000 383.880000 ;
      RECT 0.280000 383.460000 1663.450000 383.740000 ;
      RECT 0.000000 378.560000 1663.450000 383.460000 ;
      RECT 0.000000 378.280000 1663.170000 378.560000 ;
      RECT 0.280000 378.140000 1663.170000 378.280000 ;
      RECT 0.280000 377.860000 1663.450000 378.140000 ;
      RECT 0.000000 372.680000 1663.450000 377.860000 ;
      RECT 0.000000 372.400000 1663.170000 372.680000 ;
      RECT 0.280000 372.260000 1663.170000 372.400000 ;
      RECT 0.280000 371.980000 1663.450000 372.260000 ;
      RECT 0.000000 367.080000 1663.450000 371.980000 ;
      RECT 0.000000 366.800000 1663.170000 367.080000 ;
      RECT 0.280000 366.660000 1663.170000 366.800000 ;
      RECT 0.280000 366.380000 1663.450000 366.660000 ;
      RECT 0.000000 361.480000 1663.450000 366.380000 ;
      RECT 0.000000 361.200000 1663.170000 361.480000 ;
      RECT 0.280000 361.060000 1663.170000 361.200000 ;
      RECT 0.280000 360.780000 1663.450000 361.060000 ;
      RECT 0.000000 355.880000 1663.450000 360.780000 ;
      RECT 0.000000 355.600000 1663.170000 355.880000 ;
      RECT 0.280000 355.460000 1663.170000 355.600000 ;
      RECT 0.280000 355.180000 1663.450000 355.460000 ;
      RECT 0.000000 350.280000 1663.450000 355.180000 ;
      RECT 0.000000 350.000000 1663.170000 350.280000 ;
      RECT 0.280000 349.860000 1663.170000 350.000000 ;
      RECT 0.280000 349.580000 1663.450000 349.860000 ;
      RECT 0.000000 344.680000 1663.450000 349.580000 ;
      RECT 0.000000 344.400000 1663.170000 344.680000 ;
      RECT 0.280000 344.260000 1663.170000 344.400000 ;
      RECT 0.280000 343.980000 1663.450000 344.260000 ;
      RECT 0.000000 339.080000 1663.450000 343.980000 ;
      RECT 0.000000 338.800000 1663.170000 339.080000 ;
      RECT 0.280000 338.660000 1663.170000 338.800000 ;
      RECT 0.280000 338.380000 1663.450000 338.660000 ;
      RECT 0.000000 333.200000 1663.450000 338.380000 ;
      RECT 0.000000 332.920000 1663.170000 333.200000 ;
      RECT 0.280000 332.780000 1663.170000 332.920000 ;
      RECT 0.280000 332.500000 1663.450000 332.780000 ;
      RECT 0.000000 327.600000 1663.450000 332.500000 ;
      RECT 0.000000 327.320000 1663.170000 327.600000 ;
      RECT 0.280000 327.180000 1663.170000 327.320000 ;
      RECT 0.280000 326.900000 1663.450000 327.180000 ;
      RECT 0.000000 322.000000 1663.450000 326.900000 ;
      RECT 0.000000 321.720000 1663.170000 322.000000 ;
      RECT 0.280000 321.580000 1663.170000 321.720000 ;
      RECT 0.280000 321.300000 1663.450000 321.580000 ;
      RECT 0.000000 316.400000 1663.450000 321.300000 ;
      RECT 0.000000 316.120000 1663.170000 316.400000 ;
      RECT 0.280000 315.980000 1663.170000 316.120000 ;
      RECT 0.280000 315.700000 1663.450000 315.980000 ;
      RECT 0.000000 310.800000 1663.450000 315.700000 ;
      RECT 0.000000 310.520000 1663.170000 310.800000 ;
      RECT 0.280000 310.380000 1663.170000 310.520000 ;
      RECT 0.280000 310.100000 1663.450000 310.380000 ;
      RECT 0.000000 305.200000 1663.450000 310.100000 ;
      RECT 0.000000 304.920000 1663.170000 305.200000 ;
      RECT 0.280000 304.780000 1663.170000 304.920000 ;
      RECT 0.280000 304.500000 1663.450000 304.780000 ;
      RECT 0.000000 299.600000 1663.450000 304.500000 ;
      RECT 0.000000 299.320000 1663.170000 299.600000 ;
      RECT 0.280000 299.180000 1663.170000 299.320000 ;
      RECT 0.280000 298.900000 1663.450000 299.180000 ;
      RECT 0.000000 294.000000 1663.450000 298.900000 ;
      RECT 0.000000 293.720000 1663.170000 294.000000 ;
      RECT 0.280000 293.580000 1663.170000 293.720000 ;
      RECT 0.280000 293.300000 1663.450000 293.580000 ;
      RECT 0.000000 288.120000 1663.450000 293.300000 ;
      RECT 0.000000 287.840000 1663.170000 288.120000 ;
      RECT 0.280000 287.700000 1663.170000 287.840000 ;
      RECT 0.280000 287.420000 1663.450000 287.700000 ;
      RECT 0.000000 282.520000 1663.450000 287.420000 ;
      RECT 0.000000 282.240000 1663.170000 282.520000 ;
      RECT 0.280000 282.100000 1663.170000 282.240000 ;
      RECT 0.280000 281.820000 1663.450000 282.100000 ;
      RECT 0.000000 276.920000 1663.450000 281.820000 ;
      RECT 0.000000 276.640000 1663.170000 276.920000 ;
      RECT 0.280000 276.500000 1663.170000 276.640000 ;
      RECT 0.280000 276.220000 1663.450000 276.500000 ;
      RECT 0.000000 271.320000 1663.450000 276.220000 ;
      RECT 0.000000 271.040000 1663.170000 271.320000 ;
      RECT 0.280000 270.900000 1663.170000 271.040000 ;
      RECT 0.280000 270.620000 1663.450000 270.900000 ;
      RECT 0.000000 265.720000 1663.450000 270.620000 ;
      RECT 0.000000 265.440000 1663.170000 265.720000 ;
      RECT 0.280000 265.300000 1663.170000 265.440000 ;
      RECT 0.280000 265.020000 1663.450000 265.300000 ;
      RECT 0.000000 260.120000 1663.450000 265.020000 ;
      RECT 0.000000 259.840000 1663.170000 260.120000 ;
      RECT 0.280000 259.700000 1663.170000 259.840000 ;
      RECT 0.280000 259.420000 1663.450000 259.700000 ;
      RECT 0.000000 254.520000 1663.450000 259.420000 ;
      RECT 0.000000 254.240000 1663.170000 254.520000 ;
      RECT 0.280000 254.100000 1663.170000 254.240000 ;
      RECT 0.280000 253.820000 1663.450000 254.100000 ;
      RECT 0.000000 248.640000 1663.450000 253.820000 ;
      RECT 0.000000 248.360000 1663.170000 248.640000 ;
      RECT 0.280000 248.220000 1663.170000 248.360000 ;
      RECT 0.280000 247.940000 1663.450000 248.220000 ;
      RECT 0.000000 243.040000 1663.450000 247.940000 ;
      RECT 0.000000 242.760000 1663.170000 243.040000 ;
      RECT 0.280000 242.620000 1663.170000 242.760000 ;
      RECT 0.280000 242.340000 1663.450000 242.620000 ;
      RECT 0.000000 237.440000 1663.450000 242.340000 ;
      RECT 0.000000 237.160000 1663.170000 237.440000 ;
      RECT 0.280000 237.020000 1663.170000 237.160000 ;
      RECT 0.280000 236.740000 1663.450000 237.020000 ;
      RECT 0.000000 231.840000 1663.450000 236.740000 ;
      RECT 0.000000 231.560000 1663.170000 231.840000 ;
      RECT 0.280000 231.420000 1663.170000 231.560000 ;
      RECT 0.280000 231.140000 1663.450000 231.420000 ;
      RECT 0.000000 226.240000 1663.450000 231.140000 ;
      RECT 0.000000 225.960000 1663.170000 226.240000 ;
      RECT 0.280000 225.820000 1663.170000 225.960000 ;
      RECT 0.280000 225.540000 1663.450000 225.820000 ;
      RECT 0.000000 220.640000 1663.450000 225.540000 ;
      RECT 0.000000 220.360000 1663.170000 220.640000 ;
      RECT 0.280000 220.220000 1663.170000 220.360000 ;
      RECT 0.280000 219.940000 1663.450000 220.220000 ;
      RECT 0.000000 215.040000 1663.450000 219.940000 ;
      RECT 0.000000 214.760000 1663.170000 215.040000 ;
      RECT 0.280000 214.620000 1663.170000 214.760000 ;
      RECT 0.280000 214.340000 1663.450000 214.620000 ;
      RECT 0.000000 209.440000 1663.450000 214.340000 ;
      RECT 0.000000 209.160000 1663.170000 209.440000 ;
      RECT 0.280000 209.020000 1663.170000 209.160000 ;
      RECT 0.280000 208.740000 1663.450000 209.020000 ;
      RECT 0.000000 203.560000 1663.450000 208.740000 ;
      RECT 0.000000 203.280000 1663.170000 203.560000 ;
      RECT 0.280000 203.140000 1663.170000 203.280000 ;
      RECT 0.280000 202.860000 1663.450000 203.140000 ;
      RECT 0.000000 197.960000 1663.450000 202.860000 ;
      RECT 0.000000 197.680000 1663.170000 197.960000 ;
      RECT 0.280000 197.540000 1663.170000 197.680000 ;
      RECT 0.280000 197.260000 1663.450000 197.540000 ;
      RECT 0.000000 192.360000 1663.450000 197.260000 ;
      RECT 0.000000 192.080000 1663.170000 192.360000 ;
      RECT 0.280000 191.940000 1663.170000 192.080000 ;
      RECT 0.280000 191.660000 1663.450000 191.940000 ;
      RECT 0.000000 186.760000 1663.450000 191.660000 ;
      RECT 0.000000 186.480000 1663.170000 186.760000 ;
      RECT 0.280000 186.340000 1663.170000 186.480000 ;
      RECT 0.280000 186.060000 1663.450000 186.340000 ;
      RECT 0.000000 181.160000 1663.450000 186.060000 ;
      RECT 0.000000 180.880000 1663.170000 181.160000 ;
      RECT 0.280000 180.740000 1663.170000 180.880000 ;
      RECT 0.280000 180.460000 1663.450000 180.740000 ;
      RECT 0.000000 175.560000 1663.450000 180.460000 ;
      RECT 0.000000 175.280000 1663.170000 175.560000 ;
      RECT 0.280000 175.140000 1663.170000 175.280000 ;
      RECT 0.280000 174.860000 1663.450000 175.140000 ;
      RECT 0.000000 169.960000 1663.450000 174.860000 ;
      RECT 0.000000 169.680000 1663.170000 169.960000 ;
      RECT 0.280000 169.540000 1663.170000 169.680000 ;
      RECT 0.280000 169.260000 1663.450000 169.540000 ;
      RECT 0.000000 164.080000 1663.450000 169.260000 ;
      RECT 0.000000 163.800000 1663.170000 164.080000 ;
      RECT 0.280000 163.660000 1663.170000 163.800000 ;
      RECT 0.280000 163.380000 1663.450000 163.660000 ;
      RECT 0.000000 158.480000 1663.450000 163.380000 ;
      RECT 0.000000 158.200000 1663.170000 158.480000 ;
      RECT 0.280000 158.060000 1663.170000 158.200000 ;
      RECT 0.280000 157.780000 1663.450000 158.060000 ;
      RECT 0.000000 152.880000 1663.450000 157.780000 ;
      RECT 0.000000 152.600000 1663.170000 152.880000 ;
      RECT 0.280000 152.460000 1663.170000 152.600000 ;
      RECT 0.280000 152.180000 1663.450000 152.460000 ;
      RECT 0.000000 147.280000 1663.450000 152.180000 ;
      RECT 0.000000 147.000000 1663.170000 147.280000 ;
      RECT 0.280000 146.860000 1663.170000 147.000000 ;
      RECT 0.280000 146.580000 1663.450000 146.860000 ;
      RECT 0.000000 141.680000 1663.450000 146.580000 ;
      RECT 0.000000 141.400000 1663.170000 141.680000 ;
      RECT 0.280000 141.260000 1663.170000 141.400000 ;
      RECT 0.280000 140.980000 1663.450000 141.260000 ;
      RECT 0.000000 136.080000 1663.450000 140.980000 ;
      RECT 0.000000 135.800000 1663.170000 136.080000 ;
      RECT 0.280000 135.660000 1663.170000 135.800000 ;
      RECT 0.280000 135.380000 1663.450000 135.660000 ;
      RECT 0.000000 130.480000 1663.450000 135.380000 ;
      RECT 0.000000 130.200000 1663.170000 130.480000 ;
      RECT 0.280000 130.060000 1663.170000 130.200000 ;
      RECT 0.280000 129.780000 1663.450000 130.060000 ;
      RECT 0.000000 124.600000 1663.450000 129.780000 ;
      RECT 0.000000 124.320000 1663.170000 124.600000 ;
      RECT 0.280000 124.180000 1663.170000 124.320000 ;
      RECT 0.280000 123.900000 1663.450000 124.180000 ;
      RECT 0.000000 119.000000 1663.450000 123.900000 ;
      RECT 0.000000 118.720000 1663.170000 119.000000 ;
      RECT 0.280000 118.580000 1663.170000 118.720000 ;
      RECT 0.280000 118.300000 1663.450000 118.580000 ;
      RECT 0.000000 113.400000 1663.450000 118.300000 ;
      RECT 0.000000 113.120000 1663.170000 113.400000 ;
      RECT 0.280000 112.980000 1663.170000 113.120000 ;
      RECT 0.280000 112.700000 1663.450000 112.980000 ;
      RECT 0.000000 107.800000 1663.450000 112.700000 ;
      RECT 0.000000 107.520000 1663.170000 107.800000 ;
      RECT 0.280000 107.380000 1663.170000 107.520000 ;
      RECT 0.280000 107.100000 1663.450000 107.380000 ;
      RECT 0.000000 102.200000 1663.450000 107.100000 ;
      RECT 0.000000 101.920000 1663.170000 102.200000 ;
      RECT 0.280000 101.780000 1663.170000 101.920000 ;
      RECT 0.280000 101.500000 1663.450000 101.780000 ;
      RECT 0.000000 96.600000 1663.450000 101.500000 ;
      RECT 0.000000 96.320000 1663.170000 96.600000 ;
      RECT 0.280000 96.180000 1663.170000 96.320000 ;
      RECT 0.280000 95.900000 1663.450000 96.180000 ;
      RECT 0.000000 91.000000 1663.450000 95.900000 ;
      RECT 0.000000 90.720000 1663.170000 91.000000 ;
      RECT 0.280000 90.580000 1663.170000 90.720000 ;
      RECT 0.280000 90.300000 1663.450000 90.580000 ;
      RECT 0.000000 85.400000 1663.450000 90.300000 ;
      RECT 0.000000 85.120000 1663.170000 85.400000 ;
      RECT 0.280000 84.980000 1663.170000 85.120000 ;
      RECT 0.280000 84.700000 1663.450000 84.980000 ;
      RECT 0.000000 79.520000 1663.450000 84.700000 ;
      RECT 0.000000 79.240000 1663.170000 79.520000 ;
      RECT 0.280000 79.100000 1663.170000 79.240000 ;
      RECT 0.280000 78.820000 1663.450000 79.100000 ;
      RECT 0.000000 73.920000 1663.450000 78.820000 ;
      RECT 0.000000 73.640000 1663.170000 73.920000 ;
      RECT 0.280000 73.500000 1663.170000 73.640000 ;
      RECT 0.280000 73.220000 1663.450000 73.500000 ;
      RECT 0.000000 68.320000 1663.450000 73.220000 ;
      RECT 0.000000 68.040000 1663.170000 68.320000 ;
      RECT 0.280000 67.900000 1663.170000 68.040000 ;
      RECT 0.280000 67.620000 1663.450000 67.900000 ;
      RECT 0.000000 62.720000 1663.450000 67.620000 ;
      RECT 0.000000 62.440000 1663.170000 62.720000 ;
      RECT 0.280000 62.300000 1663.170000 62.440000 ;
      RECT 0.280000 62.020000 1663.450000 62.300000 ;
      RECT 0.000000 57.120000 1663.450000 62.020000 ;
      RECT 0.000000 56.840000 1663.170000 57.120000 ;
      RECT 0.280000 56.700000 1663.170000 56.840000 ;
      RECT 0.280000 56.420000 1663.450000 56.700000 ;
      RECT 0.000000 51.520000 1663.450000 56.420000 ;
      RECT 0.000000 51.240000 1663.170000 51.520000 ;
      RECT 0.280000 51.100000 1663.170000 51.240000 ;
      RECT 0.280000 50.820000 1663.450000 51.100000 ;
      RECT 0.000000 45.920000 1663.450000 50.820000 ;
      RECT 0.000000 45.640000 1663.170000 45.920000 ;
      RECT 0.280000 45.500000 1663.170000 45.640000 ;
      RECT 0.280000 45.220000 1663.450000 45.500000 ;
      RECT 0.000000 40.040000 1663.450000 45.220000 ;
      RECT 0.000000 39.760000 1663.170000 40.040000 ;
      RECT 0.280000 39.620000 1663.170000 39.760000 ;
      RECT 0.280000 39.340000 1663.450000 39.620000 ;
      RECT 0.000000 34.440000 1663.450000 39.340000 ;
      RECT 0.000000 34.160000 1663.170000 34.440000 ;
      RECT 0.280000 34.020000 1663.170000 34.160000 ;
      RECT 0.280000 33.740000 1663.450000 34.020000 ;
      RECT 0.000000 28.840000 1663.450000 33.740000 ;
      RECT 0.000000 28.560000 1663.170000 28.840000 ;
      RECT 0.280000 28.420000 1663.170000 28.560000 ;
      RECT 0.280000 28.140000 1663.450000 28.420000 ;
      RECT 0.000000 23.240000 1663.450000 28.140000 ;
      RECT 0.000000 22.960000 1663.170000 23.240000 ;
      RECT 0.280000 22.820000 1663.170000 22.960000 ;
      RECT 0.280000 22.540000 1663.450000 22.820000 ;
      RECT 0.000000 17.640000 1663.450000 22.540000 ;
      RECT 0.000000 17.360000 1663.170000 17.640000 ;
      RECT 0.280000 17.220000 1663.170000 17.360000 ;
      RECT 0.280000 16.940000 1663.450000 17.220000 ;
      RECT 0.000000 12.040000 1663.450000 16.940000 ;
      RECT 0.000000 11.760000 1663.170000 12.040000 ;
      RECT 0.280000 11.620000 1663.170000 11.760000 ;
      RECT 0.280000 11.340000 1663.450000 11.620000 ;
      RECT 0.000000 6.440000 1663.450000 11.340000 ;
      RECT 0.000000 6.160000 1663.170000 6.440000 ;
      RECT 0.280000 6.020000 1663.170000 6.160000 ;
      RECT 0.280000 5.740000 1663.450000 6.020000 ;
      RECT 0.000000 0.840000 1663.450000 5.740000 ;
      RECT 0.000000 0.560000 1663.170000 0.840000 ;
      RECT 0.280000 0.420000 1663.170000 0.560000 ;
      RECT 0.280000 0.140000 1663.450000 0.420000 ;
      RECT 0.000000 0.000000 1663.450000 0.140000 ;
    LAYER metal6 ;
      RECT 0.000000 0.000000 1663.450000 1663.760000 ;
    LAYER metal7 ;
      RECT 0.000000 1660.220000 1663.450000 1663.760000 ;
      RECT 1651.240000 3.540000 1663.450000 1660.220000 ;
      RECT 1611.240000 3.540000 1643.440000 1660.220000 ;
      RECT 1571.240000 3.540000 1603.440000 1660.220000 ;
      RECT 1531.240000 3.540000 1563.440000 1660.220000 ;
      RECT 1491.240000 3.540000 1523.440000 1660.220000 ;
      RECT 1451.240000 3.540000 1483.440000 1660.220000 ;
      RECT 1411.240000 3.540000 1443.440000 1660.220000 ;
      RECT 1371.240000 3.540000 1403.440000 1660.220000 ;
      RECT 1331.240000 3.540000 1363.440000 1660.220000 ;
      RECT 1291.240000 3.540000 1323.440000 1660.220000 ;
      RECT 1251.240000 3.540000 1283.440000 1660.220000 ;
      RECT 1211.240000 3.540000 1243.440000 1660.220000 ;
      RECT 1171.240000 3.540000 1203.440000 1660.220000 ;
      RECT 1131.240000 3.540000 1163.440000 1660.220000 ;
      RECT 1091.240000 3.540000 1123.440000 1660.220000 ;
      RECT 1051.240000 3.540000 1083.440000 1660.220000 ;
      RECT 1011.240000 3.540000 1043.440000 1660.220000 ;
      RECT 971.240000 3.540000 1003.440000 1660.220000 ;
      RECT 931.240000 3.540000 963.440000 1660.220000 ;
      RECT 891.240000 3.540000 923.440000 1660.220000 ;
      RECT 851.240000 3.540000 883.440000 1660.220000 ;
      RECT 811.240000 3.540000 843.440000 1660.220000 ;
      RECT 771.240000 3.540000 803.440000 1660.220000 ;
      RECT 731.240000 3.540000 763.440000 1660.220000 ;
      RECT 691.240000 3.540000 723.440000 1660.220000 ;
      RECT 651.240000 3.540000 683.440000 1660.220000 ;
      RECT 611.240000 3.540000 643.440000 1660.220000 ;
      RECT 571.240000 3.540000 603.440000 1660.220000 ;
      RECT 531.240000 3.540000 563.440000 1660.220000 ;
      RECT 491.240000 3.540000 523.440000 1660.220000 ;
      RECT 451.240000 3.540000 483.440000 1660.220000 ;
      RECT 411.240000 3.540000 443.440000 1660.220000 ;
      RECT 371.240000 3.540000 403.440000 1660.220000 ;
      RECT 331.240000 3.540000 363.440000 1660.220000 ;
      RECT 291.240000 3.540000 323.440000 1660.220000 ;
      RECT 251.240000 3.540000 283.440000 1660.220000 ;
      RECT 211.240000 3.540000 243.440000 1660.220000 ;
      RECT 171.240000 3.540000 203.440000 1660.220000 ;
      RECT 131.240000 3.540000 163.440000 1660.220000 ;
      RECT 91.240000 3.540000 123.440000 1660.220000 ;
      RECT 51.240000 3.540000 83.440000 1660.220000 ;
      RECT 11.240000 3.540000 43.440000 1660.220000 ;
      RECT 0.000000 3.540000 3.440000 1660.220000 ;
      RECT 0.000000 0.000000 1663.450000 3.540000 ;
    LAYER metal8 ;
      RECT 0.000000 0.000000 1663.450000 1663.760000 ;
  END
END VX_socket_top

END LIBRARY
